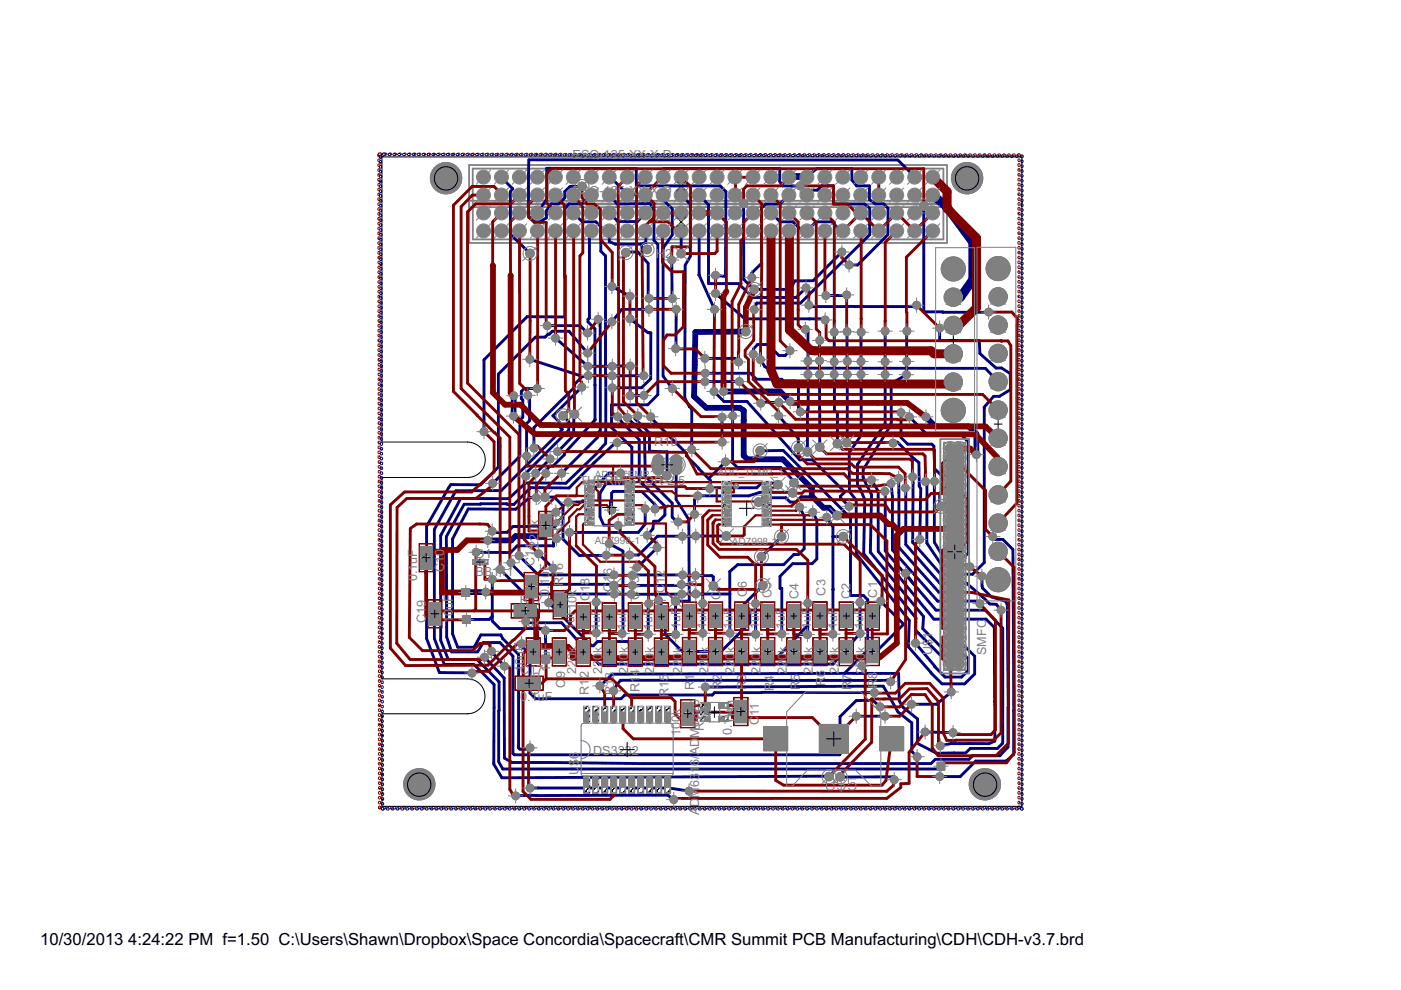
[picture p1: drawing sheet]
<svg xmlns="http://www.w3.org/2000/svg" width="297mm" height="210mm" viewBox="0 0 297 210" stroke-linecap="round" stroke-linejoin="round" font-family="sans-serif">
<defs><g id="words">
<g font-size="4">
<text x="8.5" y="200.4">10/30/2013</text>
<text x="27.2" y="200.4">4:24:22 PM f=1.50 C:\Users\Shawn\Dropbox\Space Concordia\Spacecraft\CMR Summit PCB Manufacturing\CDH\CDH-v3.7.brd</text>
</g>
<g font-size="3" fill="#808080">
<text x="121.4" y="33.7">ESQ-125-XX-X-D</text>
<text x="121.4" y="41.3">ESQ-125-X</text>
<text x="135.2" y="41.3">X-X-D</text>
<text x="139.1" y="47.1">H1</text>
<text x="139.1" y="54.7">H</text>
<text x="141" y="54.7">2</text>
<text x="138.7" y="94.6">R10</text>
<text x="122.9" y="102.7">TH</text>
<text x="126.5" y="102.7">ERMI</text>
<text x="133.2" y="102.7">STOR-2,</text>
<text x="143.8" y="102.7">5</text>
<text x="114.2" y="113.1" transform="rotate(-90 114.2 113.1)">0k</text>
<text x="119.2" y="113.7" transform="rotate(-90 119.2 113.7)">R9</text>
<text x="100.8" y="118.2">D1</text>
<text x="113.3" y="116.6" transform="rotate(-90 113.3 116.6)">4</text>
<text x="114.2" y="116.1" transform="rotate(-90 114.2 116.1)">22</text>
<text x="88.5" y="123.2" transform="rotate(-90 88.5 123.2)">0.1uF</text>
<text x="94.2" y="121.3" transform="rotate(-90 94.2 121.3)">C10</text>
<text x="100.8" y="122">BB</text>
<text x="104.4" y="122">141</text>
<text x="113.3" y="120.1" transform="rotate(-90 113.3 120.1)">C1</text>
<text x="116.5" y="121" transform="rotate(-90 116.5 121)">F</text>
<text x="119.4" y="124.2" transform="rotate(-90 119.4 124.2)">R16</text>
<text x="125" y="125.5" transform="rotate(-90 125 125.5)">18</text>
<text x="129.9" y="125.4" transform="rotate(-90 129.9 125.4)">C16</text>
<text x="135.5" y="125.2" transform="rotate(-90 135.5 125.2)">1</text>
<text x="135.5" y="123.7" transform="rotate(-90 135.5 123.7)">3</text>
<text x="141" y="125.8" transform="rotate(-90 141 125.8)">C</text>
<text x="141" y="123.9" transform="rotate(-90 141 123.9)">12</text>
<text x="152.8" y="125.2" transform="rotate(-90 152.8 125.2)">7</text>
<text x="158.3" y="124.6" transform="rotate(-90 158.3 124.6)">6</text>
<text x="96" y="130.5" transform="rotate(-90 96 130.5)">0</text>
<text x="96" y="129" transform="rotate(-90 96 129)">uF</text>
<text x="110.2" y="128">R17</text>
<text x="116.5" y="126.3" transform="rotate(-90 116.5 126.3)">0.1u</text>
<text x="122.2" y="127.9" transform="rotate(-90 122.2 127.9)">0k</text>
<text x="125" y="127.5" transform="rotate(-90 125 127.5)">C</text>
<text x="135.5" y="127.2" transform="rotate(-90 135.5 127.2)">C</text>
<text x="147.8" y="126.5" transform="rotate(-90 147.8 126.5)">C8</text>
<text x="152.8" y="127.1" transform="rotate(-90 152.8 127.1)">C</text>
<text x="158.3" y="126.5" transform="rotate(-90 158.3 126.5)">C</text>
<text x="163.6" y="126.8" transform="rotate(-90 163.6 126.8)">C5</text>
<text x="169.3" y="127.1" transform="rotate(-90 169.3 127.1)">C4</text>
<text x="175" y="126.3" transform="rotate(-90 175 126.3)">C3</text>
<text x="180.3" y="127" transform="rotate(-90 180.3 127)">C2</text>
<text x="186" y="126.7" transform="rotate(-90 186 126.7)">C1</text>
<text x="90.3" y="132" transform="rotate(-90 90.3 132)">C19</text>
<text x="96" y="132" transform="rotate(-90 96 132)">1</text>
<text x="110.2" y="132.9">1</text>
<text x="111.7" y="132.9">0k</text>
<text x="121.8" y="133.6" transform="rotate(-90 121.8 133.6)">1uF1</text>
<text x="127.3" y="133.6" transform="rotate(-90 127.3 133.6)">1uF</text>
<text x="132.8" y="133.6" transform="rotate(-90 132.8 133.6)">1uF</text>
<text x="138.3" y="133.5" transform="rotate(-90 138.3 133.5)">1uF</text>
<text x="144.3" y="133.4" transform="rotate(-90 144.3 133.4)">1uF</text>
<text x="149.8" y="133.4" transform="rotate(-90 149.8 133.4)">1uF</text>
<text x="155.3" y="133.4" transform="rotate(-90 155.3 133.4)">1uF</text>
<text x="160.9" y="133.4" transform="rotate(-90 160.9 133.4)">1uF</text>
<text x="166.4" y="133.4" transform="rotate(-90 166.4 133.4)">1uF</text>
<text x="171.9" y="133.4" transform="rotate(-90 171.9 133.4)">1uF</text>
<text x="177.5" y="133.4" transform="rotate(-90 177.5 133.4)">1uF</text>
<text x="183" y="133.4" transform="rotate(-90 183 133.4)">1uF</text>
<text x="110.3" y="143">C17</text>
<text x="111.2" y="142.5" transform="rotate(-90 111.2 142.5)">10uF</text>
<text x="116.7" y="142.5" transform="rotate(-90 116.7 142.5)">10</text>
<text x="116.7" y="139.5" transform="rotate(-90 116.7 139.5)">uF</text>
<text x="119.8" y="143.8" transform="rotate(-90 119.8 143.8)">9</text>
<text x="122.1" y="143" transform="rotate(-90 122.1 143)">220k</text>
<text x="124.8" y="143.9" transform="rotate(-90 124.8 143.9)">2</text>
<text x="127.7" y="143" transform="rotate(-90 127.7 143)">22</text>
<text x="127.7" y="140" transform="rotate(-90 127.7 140)">0k</text>
<text x="133.2" y="143" transform="rotate(-90 133.2 143)">22</text>
<text x="133.2" y="140" transform="rotate(-90 133.2 140)">0k</text>
<text x="138.7" y="143" transform="rotate(-90 138.7 143)">22</text>
<text x="138.7" y="140" transform="rotate(-90 138.7 140)">0k</text>
<text x="144.7" y="142.9" transform="rotate(-90 144.7 142.9)">220k</text>
<text x="150.2" y="142.9" transform="rotate(-90 150.2 142.9)">220k</text>
<text x="155.7" y="142.9" transform="rotate(-90 155.7 142.9)">220k</text>
<text x="161.2" y="142.9" transform="rotate(-90 161.2 142.9)">220k</text>
<text x="166.8" y="142.9" transform="rotate(-90 166.8 142.9)">220k</text>
<text x="172.3" y="142.9" transform="rotate(-90 172.3 142.9)">220k</text>
<text x="174.9" y="143.6" transform="rotate(-90 174.9 143.6)">6</text>
<text x="177.9" y="142.9" transform="rotate(-90 177.9 142.9)">220k</text>
<text x="183.4" y="142.9" transform="rotate(-90 183.4 142.9)">220k</text>
<text x="197.6" y="138.9" transform="rotate(-90 197.6 138.9)">U$1</text>
<text x="209.1" y="138.9" transform="rotate(-90 209.1 138.9)">SMFC</text>
<text x="110.3" y="148.7">0</text>
<text x="111.8" y="148.7">.1uF</text>
<text x="114.4" y="147.4" transform="rotate(-90 114.4 147.4)">C</text>
<text x="114.4" y="145.5" transform="rotate(-90 114.4 145.5)">15</text>
<text x="119.8" y="145.8" transform="rotate(-90 119.8 145.8)">C</text>
<text x="124.8" y="147.3" transform="rotate(-90 124.8 147.3)">R1</text>
<text x="130.2" y="147.4" transform="rotate(-90 130.2 147.4)">R13</text>
<text x="135.6" y="146.7" transform="rotate(-90 135.6 146.7)">R14</text>
<text x="141.7" y="147.8" transform="rotate(-90 141.7 147.8)">R15</text>
<text x="147.2" y="146.2" transform="rotate(-90 147.2 146.2)">R1</text>
<text x="153" y="146.3" transform="rotate(-90 153 146.3)">R2</text>
<text x="156.2" y="149.6" transform="rotate(-90 156.2 149.6)">4</text>
<text x="158.2" y="146.4" transform="rotate(-90 158.2 146.4)">R3</text>
<text x="164.1" y="146.6" transform="rotate(-90 164.1 146.6)">R4</text>
<text x="169.6" y="146.3" transform="rotate(-90 169.6 146.3)">R5</text>
<text x="174.9" y="145.5" transform="rotate(-90 174.9 145.5)">R</text>
<text x="180.5" y="146.2" transform="rotate(-90 180.5 146.2)">R7</text>
<text x="186" y="145.9" transform="rotate(-90 186 145.9)">R</text>
<text x="186" y="144" transform="rotate(-90 186 144)">8</text>
<text x="149.2" y="154.9" transform="rotate(-90 149.2 154.9)">R1</text>
<text x="149.2" y="151.7" transform="rotate(-90 149.2 151.7)">1</text>
<text x="155.2" y="155.9" transform="rotate(-90 155.2 155.9)">0.1u</text>
<text x="155.2" y="150.6" transform="rotate(-90 155.2 150.6)">F</text>
<text x="156.2" y="153.1" transform="rotate(-90 156.2 153.1)">U</text>
<text x="156.2" y="151.1" transform="rotate(-90 156.2 151.1)">$</text>
<text x="160.9" y="153.7" transform="rotate(-90 160.9 153.7)">C</text>
<text x="160.9" y="151.8" transform="rotate(-90 160.9 151.8)">11</text>
<text x="125.7" y="160.1">DS3232</text>
<text x="144.3" y="156" transform="rotate(-90 144.3 156)">100k</text>
<text x="148.2" y="156.4" transform="rotate(-90 148.2 156.4)">M6320</text>
<text x="122.7" y="164.3" transform="rotate(-90 122.7 164.3)">U</text>
<text x="122.7" y="162.3" transform="rotate(-90 122.7 162.3)">$6</text>
<text x="148.2" y="166.9" transform="rotate(-90 148.2 166.9)">631</text>
<text x="148.2" y="162.4" transform="rotate(-90 148.2 162.4)">6/AD</text>
<text x="148.2" y="172.9" transform="rotate(-90 148.2 172.9)">AD</text>
<text x="148.2" y="169.1" transform="rotate(-90 148.2 169.1)">M</text>
</g>
<g font-size="2.4" fill="#808080">
<text x="126.1" y="101.3">ADC_</text>
<text x="131.8" y="101.3">TE</text>
<text x="134.5" y="101.3">MP_2</text>
<text x="152.2" y="100.9">ADC_TEMP_1</text>
<text x="126.1" y="115.4">AD7998-1</text>
<text x="155.2" y="115.6">AD7998-1</text>
</g>
</g></defs>
<path d="M100.2 35.8h99.8v7.4h-99.8zM100.2 43.3h99.8v7.5h-99.8zM200.8 42.6h-101.3v8.9h101.3v-16.5h-101.3v8.9h101.3" fill="none" stroke="#808080" stroke-width=".38"/>
<g fill="#808080" stroke="#808080" stroke-width=".21">
<circle cx="88.9" cy="166.4" r="2.62"/>
<circle cx="94.6" cy="37.8" r="2.62"/>
<circle cx="208.9" cy="166.4" r="2.62"/>
<circle cx="205" cy="37.8" r="2.62"/>
<circle cx="203.4" cy="140.8" r="1.06"/>
<circle cx="201.5" cy="140.8" r="1.06"/>
<circle cx="203.4" cy="138.9" r="1.06"/>
<circle cx="201.5" cy="138.9" r="1.06"/>
<circle cx="203.4" cy="137" r="1.06"/>
<circle cx="201.5" cy="137" r="1.06"/>
<circle cx="203.4" cy="135.1" r="1.06"/>
<circle cx="201.5" cy="135.1" r="1.06"/>
<circle cx="203.4" cy="133.2" r="1.06"/>
<circle cx="201.5" cy="133.2" r="1.06"/>
<circle cx="203.4" cy="131.3" r="1.06"/>
<circle cx="201.5" cy="131.3" r="1.06"/>
<circle cx="203.4" cy="129.4" r="1.06"/>
<circle cx="201.5" cy="129.4" r="1.06"/>
<circle cx="203.4" cy="127.5" r="1.06"/>
<circle cx="201.5" cy="127.5" r="1.06"/>
<circle cx="203.4" cy="125.6" r="1.06"/>
<circle cx="201.5" cy="125.6" r="1.06"/>
<circle cx="203.4" cy="123.7" r="1.06"/>
<circle cx="201.5" cy="123.7" r="1.06"/>
<circle cx="203.4" cy="121.8" r="1.06"/>
<circle cx="201.5" cy="121.8" r="1.06"/>
<circle cx="203.4" cy="119.8" r="1.06"/>
<circle cx="201.5" cy="119.8" r="1.06"/>
<circle cx="203.4" cy="117.9" r="1.06"/>
<circle cx="201.5" cy="117.9" r="1.06"/>
<circle cx="203.4" cy="116" r="1.06"/>
<circle cx="201.5" cy="116" r="1.06"/>
<circle cx="203.4" cy="114.1" r="1.06"/>
<circle cx="201.5" cy="114.1" r="1.06"/>
<circle cx="203.4" cy="112.2" r="1.06"/>
<circle cx="201.5" cy="112.2" r="1.06"/>
<circle cx="203.4" cy="110.3" r="1.06"/>
<circle cx="201.5" cy="110.3" r="1.06"/>
<circle cx="203.4" cy="108.4" r="1.06"/>
<circle cx="201.5" cy="108.4" r="1.06"/>
<circle cx="203.4" cy="106.5" r="1.06"/>
<circle cx="201.5" cy="106.5" r="1.06"/>
<circle cx="203.4" cy="104.6" r="1.06"/>
<circle cx="201.5" cy="104.6" r="1.06"/>
<circle cx="203.4" cy="102.7" r="1.06"/>
<circle cx="201.5" cy="102.7" r="1.06"/>
<circle cx="203.4" cy="100.8" r="1.06"/>
<circle cx="201.5" cy="100.8" r="1.06"/>
<circle cx="203.4" cy="98.9" r="1.06"/>
<circle cx="201.5" cy="98.9" r="1.06"/>
<circle cx="203.4" cy="97" r="1.06"/>
<circle cx="201.5" cy="97" r="1.06"/>
<circle cx="203.4" cy="95.1" r="1.06"/>
<circle cx="201.5" cy="95.1" r="1.06"/>
<circle cx="102.5" cy="41.4" r="1.29"/>
<circle cx="102.5" cy="37.5" r="1.29"/>
<circle cx="106.3" cy="41.4" r="1.29"/>
<circle cx="106.3" cy="37.5" r="1.29"/>
<circle cx="110.1" cy="41.4" r="1.29"/>
<circle cx="110.1" cy="37.5" r="1.29"/>
<circle cx="113.9" cy="41.4" r="1.29"/>
<circle cx="113.9" cy="37.5" r="1.29"/>
<circle cx="117.8" cy="41.4" r="1.29"/>
<circle cx="117.8" cy="37.5" r="1.29"/>
<circle cx="121.6" cy="41.4" r="1.29"/>
<circle cx="121.6" cy="37.5" r="1.29"/>
<circle cx="125.4" cy="41.4" r="1.29"/>
<circle cx="125.4" cy="37.5" r="1.29"/>
<circle cx="129.2" cy="41.4" r="1.29"/>
<circle cx="129.2" cy="37.5" r="1.29"/>
<circle cx="133" cy="41.4" r="1.29"/>
<circle cx="133" cy="37.5" r="1.29"/>
<circle cx="136.8" cy="41.4" r="1.29"/>
<circle cx="136.8" cy="37.5" r="1.29"/>
<circle cx="140.6" cy="41.4" r="1.29"/>
<circle cx="140.6" cy="37.5" r="1.29"/>
<circle cx="144.4" cy="41.4" r="1.29"/>
<circle cx="144.4" cy="37.5" r="1.29"/>
<circle cx="148.2" cy="41.4" r="1.29"/>
<circle cx="148.2" cy="37.5" r="1.29"/>
<circle cx="152" cy="41.4" r="1.29"/>
<circle cx="152" cy="37.5" r="1.29"/>
<circle cx="155.8" cy="41.4" r="1.29"/>
<circle cx="155.8" cy="37.5" r="1.29"/>
<circle cx="159.6" cy="41.4" r="1.29"/>
<circle cx="159.6" cy="37.5" r="1.29"/>
<circle cx="163.4" cy="41.4" r="1.29"/>
<circle cx="163.4" cy="37.5" r="1.29"/>
<circle cx="167.3" cy="41.4" r="1.29"/>
<circle cx="167.3" cy="37.5" r="1.29"/>
<circle cx="171.1" cy="41.4" r="1.29"/>
<circle cx="171.1" cy="37.5" r="1.29"/>
<circle cx="174.9" cy="41.4" r="1.29"/>
<circle cx="174.9" cy="37.5" r="1.29"/>
<circle cx="178.7" cy="41.4" r="1.29"/>
<circle cx="178.7" cy="37.5" r="1.29"/>
<circle cx="182.5" cy="41.4" r="1.29"/>
<circle cx="182.5" cy="37.5" r="1.29"/>
<circle cx="186.3" cy="41.4" r="1.29"/>
<circle cx="186.3" cy="37.5" r="1.29"/>
<circle cx="190.1" cy="41.4" r="1.29"/>
<circle cx="190.1" cy="37.5" r="1.29"/>
<circle cx="193.9" cy="41.4" r="1.29"/>
<circle cx="193.9" cy="37.5" r="1.29"/>
<circle cx="197.7" cy="41.4" r="1.29"/>
<circle cx="197.7" cy="37.5" r="1.29"/>
<circle cx="102.5" cy="49" r="1.29"/>
<circle cx="102.5" cy="45.1" r="1.29"/>
<circle cx="106.3" cy="49" r="1.29"/>
<circle cx="106.3" cy="45.1" r="1.29"/>
<circle cx="110.1" cy="49" r="1.29"/>
<circle cx="110.1" cy="45.1" r="1.29"/>
<circle cx="113.9" cy="49" r="1.29"/>
<circle cx="113.9" cy="45.1" r="1.29"/>
<circle cx="117.8" cy="49" r="1.29"/>
<circle cx="117.8" cy="45.1" r="1.29"/>
<circle cx="121.6" cy="49" r="1.29"/>
<circle cx="121.6" cy="45.1" r="1.29"/>
<circle cx="125.4" cy="49" r="1.29"/>
<circle cx="125.4" cy="45.1" r="1.29"/>
<circle cx="129.2" cy="49" r="1.29"/>
<circle cx="129.2" cy="45.1" r="1.29"/>
<circle cx="133" cy="49" r="1.29"/>
<circle cx="133" cy="45.1" r="1.29"/>
<circle cx="136.8" cy="49" r="1.29"/>
<circle cx="136.8" cy="45.1" r="1.29"/>
<circle cx="140.6" cy="49" r="1.29"/>
<circle cx="140.6" cy="45.1" r="1.29"/>
<circle cx="144.4" cy="49" r="1.29"/>
<circle cx="144.4" cy="45.1" r="1.29"/>
<circle cx="148.2" cy="49" r="1.29"/>
<circle cx="148.2" cy="45.1" r="1.29"/>
<circle cx="152" cy="49" r="1.29"/>
<circle cx="152" cy="45.1" r="1.29"/>
<circle cx="155.9" cy="49" r="1.29"/>
<circle cx="155.9" cy="45.1" r="1.29"/>
<circle cx="159.7" cy="49" r="1.29"/>
<circle cx="159.7" cy="45.1" r="1.29"/>
<circle cx="163.5" cy="49" r="1.29"/>
<circle cx="163.5" cy="45.1" r="1.29"/>
<circle cx="167.3" cy="49" r="1.29"/>
<circle cx="167.3" cy="45.1" r="1.29"/>
<circle cx="171.1" cy="49" r="1.29"/>
<circle cx="171.1" cy="45.1" r="1.29"/>
<circle cx="174.9" cy="49" r="1.29"/>
<circle cx="174.9" cy="45.1" r="1.29"/>
<circle cx="178.7" cy="49" r="1.29"/>
<circle cx="178.7" cy="45.1" r="1.29"/>
<circle cx="182.5" cy="49" r="1.29"/>
<circle cx="182.5" cy="45.1" r="1.29"/>
<circle cx="186.3" cy="49" r="1.29"/>
<circle cx="186.3" cy="45.1" r="1.29"/>
<circle cx="190.1" cy="49" r="1.29"/>
<circle cx="190.1" cy="45.1" r="1.29"/>
<circle cx="193.9" cy="49" r="1.29"/>
<circle cx="193.9" cy="45.1" r="1.29"/>
<circle cx="197.7" cy="49" r="1.29"/>
<circle cx="197.7" cy="45.1" r="1.29"/>
<circle cx="202.1" cy="81" r="1.95"/>
<circle cx="202.1" cy="75" r="1.95"/>
<circle cx="202.1" cy="69" r="1.95"/>
<circle cx="202.1" cy="63" r="1.95"/>
<circle cx="202.1" cy="87" r="2.56"/>
<circle cx="202.1" cy="57" r="2.56"/>
<circle cx="211.6" cy="62.9" r="1.95"/>
<circle cx="211.6" cy="68.9" r="1.95"/>
<circle cx="211.6" cy="74.9" r="1.95"/>
<circle cx="211.6" cy="80.9" r="1.95"/>
<circle cx="211.6" cy="86.9" r="1.95"/>
<circle cx="211.6" cy="92.9" r="1.95"/>
<circle cx="211.6" cy="98.9" r="1.95"/>
<circle cx="211.6" cy="104.9" r="1.95"/>
<circle cx="211.6" cy="110.9" r="1.95"/>
<circle cx="211.6" cy="116.9" r="1.95"/>
<circle cx="211.6" cy="56.9" r="2.56"/>
<circle cx="211.6" cy="122.9" r="2.56"/>
<circle cx="115.6" cy="133.7" r=".83"/>
<circle cx="104.4" cy="122.8" r=".83"/>
<circle cx="187.6" cy="151.8" r=".83"/>
<circle cx="181.5" cy="151.8" r=".83"/>
<circle cx="169.7" cy="39.4" r=".83"/>
<circle cx="137.2" cy="52.9" r=".91"/>
<circle cx="112.4" cy="53.7" r=".91"/>
<circle cx="112.3" cy="76.2" r=".83"/>
<circle cx="124.7" cy="79.6" r=".83"/>
<circle cx="129.8" cy="79.7" r=".83"/>
<circle cx="136.5" cy="79.7" r=".83"/>
<circle cx="113.6" cy="100.4" r=".83"/>
<circle cx="116.6" cy="97.3" r=".83"/>
<circle cx="113.2" cy="95" r=".83"/>
<circle cx="144.4" cy="53.8" r=".91"/>
<circle cx="193.3" cy="149.3" r=".83"/>
<circle cx="201.7" cy="146.7" r=".83"/>
<circle cx="171.2" cy="134.6" r=".83"/>
<circle cx="171.3" cy="127.9" r=".83"/>
<circle cx="119.4" cy="88.2" r=".91"/>
<circle cx="111.5" cy="101" r=".83"/>
<circle cx="114.2" cy="117.4" r=".83"/>
<circle cx="117.2" cy="120.5" r=".83"/>
<circle cx="116.3" cy="127.8" r=".83"/>
<circle cx="176.6" cy="134.5" r=".83"/>
<circle cx="175.3" cy="109.7" r=".83"/>
<circle cx="178.8" cy="113.8" r=".91"/>
<circle cx="186.7" cy="127.5" r=".83"/>
<circle cx="182.8" cy="141.2" r=".83"/>
<circle cx="175.7" cy="164.7" r=".91"/>
<circle cx="123.3" cy="82.1" r=".83"/>
<circle cx="131.1" cy="111.4" r=".83"/>
<circle cx="139.6" cy="127.3" r=".83"/>
<circle cx="161.7" cy="124.1" r=".91"/>
<circle cx="161.4" cy="118" r=".91"/>
<circle cx="165.7" cy="113.8" r=".91"/>
<circle cx="131.9" cy="134.3" r=".83"/>
<circle cx="129.2" cy="115.3" r=".83"/>
<circle cx="126.4" cy="134.2" r=".83"/>
<circle cx="126.4" cy="127.7" r=".83"/>
<circle cx="137.4" cy="134.5" r=".83"/>
<circle cx="137.5" cy="128" r=".83"/>
<circle cx="135" cy="120.3" r=".83"/>
<circle cx="139.3" cy="116.1" r=".83"/>
<circle cx="137.2" cy="113.5" r=".83"/>
<circle cx="131" cy="88.3" r=".83"/>
<circle cx="129.8" cy="82.2" r=".83"/>
<circle cx="123.4" cy="39.5" r=".91"/>
<circle cx="129.7" cy="60.7" r=".83"/>
<circle cx="133.6" cy="62.8" r=".83"/>
<circle cx="133.6" cy="67.6" r=".83"/>
<circle cx="190.5" cy="101.4" r=".83"/>
<circle cx="146.7" cy="95.3" r=".83"/>
<circle cx="170.9" cy="61" r=".83"/>
<circle cx="171.5" cy="64.7" r=".83"/>
<circle cx="194.3" cy="64.7" r=".83"/>
<circle cx="199.2" cy="69.6" r=".83"/>
<circle cx="192.8" cy="88.4" r=".83"/>
<circle cx="165.1" cy="85.3" r=".83"/>
<circle cx="161.3" cy="85.5" r=".83"/>
<circle cx="156.8" cy="80.9" r=".83"/>
<circle cx="149.5" cy="80.9" r=".83"/>
<circle cx="136.5" cy="83.8" r=".83"/>
<circle cx="133.6" cy="83.9" r=".83"/>
<circle cx="133.6" cy="77.6" r=".83"/>
<circle cx="129.8" cy="77.7" r=".83"/>
<circle cx="124.6" cy="77.7" r=".83"/>
<circle cx="117.8" cy="71.7" r=".83"/>
<circle cx="154.7" cy="134.3" r=".83"/>
<circle cx="169.5" cy="107.5" r=".83"/>
<circle cx="106" cy="120.7" r=".83"/>
<circle cx="130.3" cy="125.9" r=".83"/>
<circle cx="133.8" cy="126" r=".83"/>
<circle cx="144.6" cy="126" r=".83"/>
<circle cx="147.5" cy="125.9" r=".83"/>
<circle cx="165.8" cy="134.4" r=".83"/>
<circle cx="172.3" cy="108.6" r=".83"/>
<circle cx="154" cy="113.6" r=".91"/>
<circle cx="147.5" cy="113.6" r=".83"/>
<circle cx="144.7" cy="113.7" r=".83"/>
<circle cx="133.5" cy="117.7" r=".83"/>
<circle cx="128.5" cy="117.7" r=".83"/>
<circle cx="115.5" cy="105.4" r=".91"/>
<circle cx="119.1" cy="100.4" r=".83"/>
<circle cx="126.8" cy="67.7" r=".83"/>
<circle cx="124.6" cy="70.6" r=".83"/>
<circle cx="116" cy="69" r=".83"/>
<circle cx="160.2" cy="134.5" r=".83"/>
<circle cx="160.2" cy="128" r=".83"/>
<circle cx="110.1" cy="117.8" r=".83"/>
<circle cx="130.2" cy="121.9" r=".83"/>
<circle cx="134" cy="122" r=".83"/>
<circle cx="144.7" cy="121.9" r=".83"/>
<circle cx="147.5" cy="122" r=".83"/>
<circle cx="151.2" cy="124.2" r=".91"/>
<circle cx="149" cy="134.3" r=".83"/>
<circle cx="149" cy="128" r=".83"/>
<circle cx="108.3" cy="119.3" r=".83"/>
<circle cx="130.2" cy="124.2" r=".91"/>
<circle cx="134.1" cy="124.1" r=".83"/>
<circle cx="144.5" cy="124" r=".83"/>
<circle cx="192" cy="103.5" r=".83"/>
<circle cx="159.9" cy="65.6" r=".83"/>
<circle cx="165.1" cy="88.2" r=".83"/>
<circle cx="169.3" cy="94.9" r=".91"/>
<circle cx="136.8" cy="107.9" r=".83"/>
<circle cx="120.8" cy="112.9" r=".83"/>
<circle cx="182.4" cy="134.3" r=".83"/>
<circle cx="182.3" cy="127.7" r=".83"/>
<circle cx="102.6" cy="91.5" r=".83"/>
<circle cx="111.5" cy="131.7" r=".83"/>
<circle cx="143.3" cy="134.5" r=".83"/>
<circle cx="143.2" cy="127.4" r=".91"/>
<circle cx="118" cy="114.2" r=".83"/>
<circle cx="138.9" cy="107.9" r=".83"/>
<circle cx="129.7" cy="108.2" r=".83"/>
<circle cx="100.9" cy="117.1" r=".83"/>
<circle cx="118" cy="110.8" r=".61"/>
<circle cx="103.4" cy="114.6" r=".83"/>
<circle cx="103" cy="125.5" r=".83"/>
<circle cx="180" cy="56.2" r=".83"/>
<circle cx="178.5" cy="53.4" r=".83"/>
<circle cx="159.9" cy="61.4" r=".91"/>
<circle cx="158.1" cy="70.3" r=".91"/>
<circle cx="160.8" cy="106.4" r=".91"/>
<circle cx="157.6" cy="43.1" r=".91"/>
<circle cx="177.5" cy="109.3" r=".91"/>
<circle cx="153.4" cy="83" r=".83"/>
<circle cx="167.5" cy="85.1" r=".83"/>
<circle cx="196.3" cy="88.4" r=".83"/>
<circle cx="207" cy="96.4" r=".83"/>
<circle cx="186.6" cy="149.9" r=".83"/>
<circle cx="130.9" cy="93.9" r=".83"/>
<circle cx="153.1" cy="93.7" r=".83"/>
<circle cx="153.1" cy="88.5" r=".83"/>
<circle cx="142.5" cy="82.4" r=".83"/>
<circle cx="159.4" cy="58.9" r=".83"/>
<circle cx="212.2" cy="129.4" r=".83"/>
<circle cx="185.4" cy="146.9" r=".83"/>
<circle cx="156.6" cy="76.8" r=".83"/>
<circle cx="100.1" cy="142.7" r=".83"/>
<circle cx="110.6" cy="136.5" r=".83"/>
<circle cx="149.4" cy="76" r=".83"/>
<circle cx="143.3" cy="73.9" r=".83"/>
<circle cx="143.4" cy="65.6" r=".83"/>
<circle cx="137.6" cy="65.6" r=".83"/>
<circle cx="129.7" cy="68.2" r=".83"/>
<circle cx="124.6" cy="74.9" r=".83"/>
<circle cx="182.6" cy="70.4" r=".83"/>
<circle cx="182.5" cy="76.6" r=".83"/>
<circle cx="182.5" cy="79.4" r=".83"/>
<circle cx="194.1" cy="136.4" r=".83"/>
<circle cx="195" cy="114.4" r=".83"/>
<circle cx="175.1" cy="62.7" r=".83"/>
<circle cx="179.5" cy="62.5" r=".83"/>
<circle cx="179.6" cy="70.3" r=".83"/>
<circle cx="179.6" cy="76.6" r=".83"/>
<circle cx="179.6" cy="79.4" r=".83"/>
<circle cx="179.5" cy="93.8" r=".91"/>
<circle cx="189.3" cy="93.9" r=".83"/>
<circle cx="187.7" cy="70.2" r=".83"/>
<circle cx="187.7" cy="76.7" r=".83"/>
<circle cx="187.7" cy="79.4" r=".83"/>
<circle cx="192.3" cy="70.2" r=".83"/>
<circle cx="192.2" cy="76.6" r=".83"/>
<circle cx="192.2" cy="79.4" r=".83"/>
<circle cx="167.5" cy="74.4" r=".83"/>
<circle cx="159.7" cy="75.1" r=".83"/>
<circle cx="130.1" cy="146.5" r=".83"/>
<circle cx="147.9" cy="105.1" r=".83"/>
<circle cx="168.1" cy="104.5" r=".91"/>
<circle cx="187.6" cy="104.2" r=".83"/>
<circle cx="133" cy="88.5" r=".83"/>
<circle cx="143.8" cy="110.7" r=".83"/>
<circle cx="147.3" cy="109" r=".83"/>
<circle cx="188.8" cy="144.5" r=".83"/>
<circle cx="192" cy="121.6" r=".83"/>
<circle cx="127.2" cy="145.4" r=".83"/>
<circle cx="150.5" cy="103.6" r=".83"/>
<circle cx="164.9" cy="102.8" r=".91"/>
<circle cx="138" cy="88.4" r=".83"/>
<circle cx="153.8" cy="97.9" r=".83"/>
<circle cx="161.2" cy="95.6" r=".91"/>
<circle cx="188.9" cy="102.5" r=".83"/>
<circle cx="168.3" cy="102.4" r=".91"/>
<circle cx="155.3" cy="88.2" r=".83"/>
<circle cx="207.8" cy="128" r=".83"/>
<circle cx="202.1" cy="155.3" r=".83"/>
<circle cx="196.1" cy="155.2" r=".83"/>
<circle cx="142.9" cy="169.5" r=".83"/>
<circle cx="109.3" cy="168.7" r=".83"/>
<circle cx="104.4" cy="112.6" r=".83"/>
<circle cx="117.9" cy="108.6" r=".83"/>
<circle cx="120.4" cy="106.5" r=".83"/>
<circle cx="131.6" cy="100.3" r=".83"/>
<circle cx="141.4" cy="100.8" r=".91"/>
<circle cx="135.2" cy="88.2" r=".83"/>
<circle cx="132.7" cy="53.6" r=".91"/>
<circle cx="137.6" cy="63.2" r=".83"/>
<circle cx="142.6" cy="63.3" r=".83"/>
<circle cx="142.4" cy="55.1" r=".83"/>
<circle cx="107" cy="141.2" r=".83"/>
<circle cx="104.2" cy="138.1" r=".83"/>
<circle cx="184.8" cy="101.7" r=".83"/>
<circle cx="118.2" cy="95.8" r=".83"/>
<circle cx="121.8" cy="87.8" r=".91"/>
<circle cx="170.8" cy="69.8" r=".83"/>
<circle cx="171.3" cy="76.5" r=".83"/>
<circle cx="171.3" cy="79.4" r=".83"/>
<circle cx="193.5" cy="101.1" r=".83"/>
<circle cx="171.2" cy="95.8" r=".91"/>
<circle cx="173.8" cy="72.2" r=".83"/>
<circle cx="173.8" cy="76.5" r=".83"/>
<circle cx="173.8" cy="79.4" r=".83"/>
<circle cx="196.2" cy="102.1" r=".83"/>
<circle cx="173.8" cy="94.8" r=".91"/>
<circle cx="176.9" cy="70.4" r=".83"/>
<circle cx="176.9" cy="76.7" r=".83"/>
<circle cx="176.9" cy="79.4" r=".83"/>
<circle cx="198.1" cy="102.1" r=".83"/>
<circle cx="177.5" cy="94.1" r=".91"/>
<circle cx="205.6" cy="120.2" r=".83"/>
<circle cx="208.2" cy="122.2" r=".83"/>
<circle cx="104.5" cy="102.5" r=".83"/>
<circle cx="113.9" cy="82.4" r=".83"/>
<circle cx="102.7" cy="139.3" r=".83"/>
<circle cx="149.5" cy="145.7" r=".83"/>
<circle cx="210.5" cy="113.8" r=".83"/>
<circle cx="199.2" cy="164.7" r=".83"/>
<circle cx="194.4" cy="160.4" r=".83"/>
<circle cx="191" cy="87.5" r=".83"/>
<circle cx="169.7" cy="87.3" r=".83"/>
<circle cx="149.5" cy="79.1" r=".83"/>
<circle cx="199.5" cy="107.4" r=".91"/>
<circle cx="180" cy="107.4" r=".83"/>
<circle cx="151.5" cy="65.6" r=".83"/>
<circle cx="151.4" cy="83" r=".83"/>
<circle cx="108.9" cy="88.2" r=".83"/>
<circle cx="108.9" cy="83.9" r=".83"/>
<circle cx="174.9" cy="67.8" r=".83"/>
<circle cx="151.7" cy="58.4" r=".83"/>
<circle cx="151.7" cy="62.2" r=".83"/>
<circle cx="209.6" cy="66.2" r=".83"/>
<circle cx="195.9" cy="43.7" r=".91"/>
<circle cx="161.2" cy="76.3" r=".83"/>
<circle cx="199.4" cy="158.1" r=".83"/>
<circle cx="178.1" cy="164.7" r=".91"/>
<circle cx="189.6" cy="165.3" r=".83"/>
<circle cx="146.1" cy="167.7" r=".83"/>
<circle cx="112.4" cy="167.1" r=".83"/>
<circle cx="112.4" cy="158.6" r=".83"/>
<circle cx="113.7" cy="105.5" r=".83"/>
<circle cx="115.7" cy="100.4" r=".83"/>
<circle cx="111.7" cy="96.7" r=".83"/>
<circle cx="111.9" cy="83.8" r=".83"/>
<circle cx="94.6" cy="37.8" r="3.3"/>
<circle cx="205" cy="37.8" r="3.3"/>
<circle cx="208.8" cy="166.3" r="3.3"/>
<circle cx="88.9" cy="166.3" r="3.3"/>
</g>
<g fill="#808080" stroke="#808080" stroke-width=".21">
<path d="M142.7 96.6a1.15 1.15 0 0 1 1.8 .8v2.3a1.15 1.15 0 0 1-1.1 1 1.15 1.15 0 0 1-1.2-1v-2.3z"/>
<path d="M138.9 96.6a1.15 1.15 0 0 1 1.8 .8v2.3a1.15 1.15 0 0 1-1.1 1 1.15 1.15 0 0 1-1.2-1v-2.3z"/>
<path d="M114.9 138.9h1.6v1.6h-1.6z"/>
<path d="M98 130.5h1.7v1.7h-1.7z"/>
<path d="M97.9 124.8h1.7v1.6h-1.7z"/>
<path d="M198.7 161.6h1.6v1.7h-1.6z"/>
</g>
<path d="M167 36.8h4.5v1.2h-4.5z" fill="#000080" stroke="#000080" stroke-width=".21"/>
<g fill="none" stroke="#000080" stroke-width=".61">
<path d="M106.3 37.5l2.4 2.5-.5 .6v9.1l4.2 4M129.2 37.5l.2 .1 3.4 3.3h.3l-.1 .5h3.8M140.6 37.5l.1 .1v-1.9h24.6v2.7l.6 1h3.8M148.2 35.7v1.8M170.9 37.6l2.3-1.8h7.4v2.4l1 1.2h2.7v2.9l1.3 .9h1.8l.9 1-.1 5.6-6.4 6.4h-1.8M193.9 37.5l-3.5-3.6h-78.3v11.9l1.2 1.2h1.2l1.3-.8v-1.5l1-1.5h1.7l1.2-1.2v-1.4l1.2-1.1h2.5M113.9 45.1l2-3v-6.4h19v3.7h17.8l1.2 1.2-.1 18-2.1-.2M121.6 45.1l1.9 1.9h2.8l1.1 1.1v5.2l1 1v39.7l-2 2.2-6.4 6.3-8.6-.1-3.6 3.3h-10.1l-4.3 7.9v22.1l1.6 4.1h6.1l4.7 4.7-.1 17 .9 1.5h92.3l.6-.6M125.4 41.4l-2 1.8h-2.8l-.9 1.1v22.9l-7.9-.1-9.2 9.2v15.2M125.4 49l-.2-.1-.2 .2v18.3l-.3 .3v.6l1.4 1.4 .1 19.3-6.5 7.1v.3l-2.5 2.4h-.6l-1.2 1.3 .3 .3M129.2 49v2.2l1.3 .6h5.4M129.2 41.4l1.7 1.8h6.9l.9 1.2v6.6l.8 .8v31.9l-2.2 2.1h-7.7v4.9l4.4 4.1v7l-.8 .8h-4.7l-1.3 2v4.9l.8 1.8 3.1 .1"/>
<path d="M129.2 45.1l1.8 1.9h4.1l1.7-1.9M132.7 53.6l.6-.2h1.9l2.2 2.4v7.6l.2-.2M135.9 51.8l.2 .7 1.1 .4M136.8 49l.1 .1v2.3l-1 .4M140.6 41.4l-.5 .4 2.4 2.5v5.5l-1.9 2.8v27.1l1.9 2.7M142.4 55.1l.2 8.2M142.4 55.1h.1M144.4 49v4.8M144.4 41.4l2 1.9v11l-1.1 1.9-.1 28.2 1 1.9 .5 .4v8.6M148.2 49v9.3l3.3 7.3M148.2 41.4l2 2v16.7h6.3l3.2 3h9.1l2.1-2.1M148.2 58.2v.1"/>
<path d="M157.6 43.1l.1 16.1 2.1 2.2h7.7l1-1.8 3.9-.1 6.1-6.1M163.5 45.1l1.9 1.9h2.7l1.9 1.9 1.1 .1 1.9-2h3.4l1.8 1.9 .5 .1M167.3 41.4l-1.9 1.9h-3.1l-.8 .8v11.7l-2.1 2.1v1h.2M171.1 41.4l1-1.1h1.2l.9-.9h2.5v3.8l6.7 .1 1 .9v5.6l-14.7 14.5h-9.3l-.5 1.3M195.9 43.7v22.4l13.7 .1M112.3 76.2l11.2 3.6M116 69h7l1.6 1.6M117.8 71.7l6.8 6M123.5 79.8l-1.7 1.7v.6l-8.6 8.6v4.3M124.6 74.9l-4-4.7h-3.5l-1.5 1.3h-2.1l-7.8 7.8v19.7l-3.8 3.8-6.3-.1-5.2 8.9v23.8l2.8 7.2 6.9 .1M124.7 79.6l-1.2 .2M126.8 67.7l.5 .5v23.1l-.6 .5v.9l-7.6 7.7"/>
<path d="M127.3 71h.1M129.7 60.7l3.9 2.1M133.6 67.6l3.8 2.9 .6 .1M133.6 77.6l-3.8 .1M136.5 79.7h-6.7M137.5 70.5l.5 .1M137.6 65.6h-5.8l-2.1 2.6M138 70.6v9.7l-2 1.9h-6.2M143.4 65.6l-.1 8.3M149.4 76h6.5l.7 .8M149.5 79.1h9.6l1.3 1.3h5.4l.3 .4h2.5l.7 .7v5.4l.4 .4M151.7 62.2l6.1 5.3 .5 .1h16.4l.2 .2"/>
<path d="M161.2 76.3l1 1.4 .4 .3 46.3 .1 2.7 2.8M167.5 74.4l-1 1h-1.4l-2.3-2.4h-2.2l-.9 1v1.1M170.8 69.8l.5 .6v6.1M171.3 79.4l-.1 16.4M171.5 64.7l.3 .3h22.2l.3-.3M171.6 67.6h.1M173.8 79.3v15.5M173.8 72.2v4.3M176.9 70.4v6.3M176.9 79.4v7.6l.6 .6v6.5M179.5 62.5l-.1 .2h-4.3M179.6 70.3v6.6v-.3"/>
<path d="M179.6 79.4l-.1 14.4M182.5 79.4l.1 12.9-2.6 3.7 .1 8.2 1.4 1.8v11.4l11.3 14.2-.2 5.5 4.8 5.6 2.3 2.3h4.8l2.2-2.1v-3.8l-2.2-2.1h-1.1M182.6 70.4l-.1 6.2M187.7 79.4v10.4l-5.9 8.7v4.3l.7 1.1 .8 2-.2 11.5 11.1 13.6v2.7l5.1 5.2h2.2M187.7 70.2v6.5M192.2 79.1v.3l-3.3 1.9 .1 8.2-.3 .9-5.7 9.2v1.6l1.8 3.7-.3 12.2 11.3 13.6-.2 2.6 3.7 3.7h2.2M192.3 70.2l-.1 6.4M199.2 69.6v2.6h8.4l.2 2.8 3.4 3h1.1l1.9 1.2v3.4l-2.3 1.4h-1.2l-2 2.3v33l-2.5 2.5h-2.8M111.9 83.7l.4 .5v5l-.6 .6v6.9M113.9 82.4h-2.8l-.6 .6v1.5l.3 .3v3.7l-.6 .6v7.6l-5.7 5.8M116.6 97.3l-3 3.1M117.2 88.2h.1"/>
<path d="M117.3 88.2l1.5 1.5v.9l.4 .5-12.9 12.9-9.7 .1-4.5 8.1v23.2l2.1 5.5h6.3l4.3 4.2-.1 16.9 1.7 2.9 69.3-.2M119.4 88.2l1.2 1.2v1.8l-9.5 9.5 .4 .3M121.6 88h.1M121.7 88l-.1 4.3-3.4 3.5M121.8 87.8l-.2 .2M123.3 82.1l-6.1 6.1M126.1 81.6l.1 .1M130.9 93.9l-.5 .1-4.5 4.1-5.3 5.4-8.2-.1-3.5 3.6h-1.3l-.2-.2-9 .1-3.8 6.9 .1 21.2 1.1 3.2h5.5l1.1-2h3.6l2.8 2.9v20.7l.2 .2h69l.1-8 3.4-3.5h3.6l1.5 1.4M131 88.3l1.2 1.7 3.3 3.2v8.7l5.5 5.4v1.9l-1.4 1.3h-1l-.2 1.6-1.2 1.4M133 88.5l3.7 3.7 .1 8.8 5.7 5.7v2.9l1 1.1h.3M135.2 88.2l-.6 .6 3.1 3v3.9l3.7 .1v5M136.5 83.8h-3.2l.3 .1"/>
<path d="M138 88.4v.1l7.5 7.6v.5l5.1 5.2-.1 1.8 .4-.2h9.5l1-1h3.2l.3 .4M143.4 98.6l-.1 7.3 2.7 4.3 .1 17.3-2.9-.1 .1 7.1M151.4 83l2.1 2.1h4.9l11.1 12.4h2.8l6.8 6.8-.9 .9v.3l1.8 1.9M153.1 88.5v5.2M153.8 97.9l-3.6 3.6M155.3 88.1v10l1 1h9.3l2.8 3-.1 .3M156.8 80.9h-7.3M161.2 95.6l4.9-.1 14.2 14.3v16.5h2.8l.9 .9v11.3h-.6l-4.3 4.3M165.1 88.2l4.1 4.7 .1 2M165.1 85.3h-3.6l-.2 .2M189.3 93.9l1-.2 3.5 3.6 1 .8 .1 4.9 .3 .6-.2 10.8M191 87.5v5.3l1.4 1.4h5.2l.4 .4 .2 4.8 1.4 1.4h1.9"/>
<path d="M192.8 88.4l3.8 3.7v.3h7.4l1.3 1.3v23.5l-.7 .7h-1.2M108.3 119.3l4.5 4.6h17.1l.3 .3M110.1 117.8l4 4.1h16.1M113.7 105.5h-1.4l-3 2.5-10-.1-3.4 6.4v20.1l1.1 2.8h3.5l1.5-2.6h4.2l.4 .8 3.3 3.3v19.9l.3 .3h1.9l.3-.3M114.2 117.4l3 3.1M115.5 105.4h2l1.9 1.9v7l3.4 3.5 5.7-.1M117.9 108.6l-4.1 3h-5l-1.3 1.3h-2.2l-.9-.3M118 114.2l-.6 .7v.9l-7.7-.1-1.5 1.5-7.3-.1M129.2 115.3l2.9 1.5v17.3l-.2 .2M131.6 100.3h-2.5l-3.6 4v2.1l-5.1 .1M136.3 102.6h.1M136.8 107.9v3.2l-1.5 1.8h-14.5"/>
<path d="M138.9 107.9v-.9l-2.8-2.8h-6.1l-.3 .4v3.6M139.3 116.1l-4.3 4.2M141 107.7h.1M144.7 113.7h.1h-5.4l-4 4h-1.9M147.5 113.6h6.5M165.7 113.8l-4.3 4.2M168.1 104.5l-.7-.1h-6.3l-2.4 .7h-10.8l-.6 .9v3M169.5 107.5l1 1.9v7l-1.2 1.2h-1l-2.1 2.1h-9.8l-1.7 1.5v13.1M172.1 105.2l.2 .1h-2.4l-1.2 1.1h-1.2l-.9-.9h-4.9l-.9 .9M172.3 108.6l.9 1.7v8.2l-1 1h-4.1l-2.7 2.7v2.6h.4v9.6M175.3 109.7l1.3 2v22.8M176.6 113.8h2.2"/>
<path d="M184.8 101.7l1.4 2.4v12.8l11.8 14.4h3.5M187.6 104.2l.1 12.6 6 7M188.9 102.5l.3 2.8v11.3l9.6 10.9h2.7M190.5 101.4l.1 14.7 8.5 9.5h2.4M192 103.5v-.2v12.1l7.2 8.2 2.3 .1M193.5 101.1v13.9l6 6.8h2M196.2 102.1l.3 .5v12.5l3.2 4.7h1.8M198.1 102.1v12.9l1.8 2.9h1.6M201.5 102.7l-.5 .1-1.8 1.8v2.5l.3 .3M203.4 119.8l1.5-.1 .4 .5h.3M210.5 113.8l.6 .6h1.5l2.2 2.1 .1 43.5-1.6 1.4h-6.4l-3.3 3.3h-4.4M98.8 125.5v.1"/>
<path d="M104.2 138.1l2.8 3.1M104.4 122.8v8.9l1.6 1.6h9.2l.4 .4 .1 6M104.4 130.7l-.7 .6h-4.8M106 120.7l5.3 5.2h19M110.6 136.5h-.6l2.4 2.3v8.1l1.2 1.2h18.1l.8-.7h18.5l.5-.5h33.9M116.3 127.8l9.2 9.1h.3l.9-.9h6.4l2.9 3.5h28.7l6.2-6.5h.4M126.4 127.7v6.5M133.8 126h.1M137.5 128l-.1 6.5M144.5 124l-.2 .1h-10.2M144.6 126h-10.7M144.7 121.9l-10.7 .1"/>
<path d="M147.5 122h3.4l.3 .3v1.9M147.5 125.9h7.2M149 128v6.3M160.2 128v6.5M161.7 124.1l-3.9 4 1.2 1.2v2.7l-6.1 6.1h-8.2l-3.7-3.6 .1-4.7-1.5-2.5M171.3 127.9l-.1 6.7M176.6 125h.1M182.3 127.7l.1 6.6-5.8 6.5h-49.7l-7.8-8.8h-7.3l-.3-.3M186.7 127.5l4.9 4.9-8.8 8.8M192 121.6l1.7 2.2M193.7 123.8l4.8 5.6h3M194.1 136.4l4.1 5 2.2 2.2h3.5l1.4-1.5v-2.4l-.8-.8h-1.1"/>
<path d="M201.5 133.2h1.9M201.5 135.1h1.9M203.4 123.7h1.5l3.6 3 1.3 1.4h1.4l1 1.3M203.4 129.4h5.5l3.7 3.8v24.4l-1.1 1.1h-5.8l-1 1h-6.2l-4-2.1v-5.2l-3.1-2.5-.7-1.3-.2-5.8h-11.4M203.4 127.5l3.8-.1 .6 .6M203.4 131.3h5.7l1.7 1.7 .1 24.1-1.2 .6-8.1-.1-2.2 .5M203.4 131.3h.1M208.2 122.2l.1 2.5 1.9 1.9 3 .9 .4 .8 .1 30.1-1.7 1.8h-5.8l-.8 .8h-7.1l-.9 .9h-61l-28.1-.2v-.2l-1.3-.8-.1-16.9-4.2-4.5M149.5 145.7l37.8-.2 3.1 5.5 2.9 2.3v6l1.1 1.1M179.1 142.8l-49.3 .1-2.6 2.5M181.5 151.8h6.1M188.8 144.5l-.6-.3h-56.6l-.8 .9-.7 1.4"/>
<path d="M196.1 155.2l6 .1M201.5 140.8h1.9M201.7 146.7l-3.1 2.6h-5.3M109.3 168.7l3.1-.1h29.2l1.3 .9M112.4 167.1h29.3l4.4 .6M178.1 164.7h11.4l.1 .6"/>
</g>
<path d="M158.1 70.3l-10.7 .1-.2 13.7 2.6 2.4h7l.9 .5v9.6l.8 .8h7.5l6.1 6.2v1.6M108.9 83.9v4.3M153.4 83h12l2.1 2.1M157.7 89v.1M196.3 88.4l2 2h7.1l1.6 1.6v4.4M117.9 110.9l-2.6 2.8h-6l-.9 .9h-5M172.3 105.3l2.3 2.4h1.2l1.7 1.6M98.8 125.5h4.2" fill="none" stroke="#000080" stroke-width="1.2"/>
<path d="M197.7 41.4l3 2.4 5.6 7.6v7.9l-2.7 3.7h-1.5" fill="none" stroke="#000080" stroke-width="1.9"/>
<circle cx="203.4" cy="140.8" r=".91" fill="#008000" stroke="#008000" stroke-width=".21"/>
<circle cx="203.4" cy="140.8" r=".53" fill="#fff" stroke="#000" stroke-width=".21"/>
<circle cx="201.5" cy="140.8" r=".91" fill="#008000" stroke="#008000" stroke-width=".21"/>
<circle cx="201.5" cy="140.8" r=".53" fill="#fff" stroke="#000" stroke-width=".21"/>
<circle cx="203.4" cy="138.9" r=".91" fill="#008000" stroke="#008000" stroke-width=".21"/>
<circle cx="203.4" cy="138.9" r=".53" fill="#fff" stroke="#000" stroke-width=".21"/>
<circle cx="201.5" cy="138.9" r=".91" fill="#008000" stroke="#008000" stroke-width=".21"/>
<circle cx="201.5" cy="138.9" r=".53" fill="#fff" stroke="#000" stroke-width=".21"/>
<circle cx="203.4" cy="137" r=".91" fill="#008000" stroke="#008000" stroke-width=".21"/>
<circle cx="203.4" cy="137" r=".53" fill="#fff" stroke="#000" stroke-width=".21"/>
<circle cx="201.5" cy="137" r=".91" fill="#008000" stroke="#008000" stroke-width=".21"/>
<circle cx="201.5" cy="137" r=".53" fill="#fff" stroke="#000" stroke-width=".21"/>
<circle cx="203.4" cy="135.1" r=".91" fill="#008000" stroke="#008000" stroke-width=".21"/>
<circle cx="203.4" cy="135.1" r=".53" fill="#fff" stroke="#000" stroke-width=".21"/>
<circle cx="201.5" cy="135.1" r=".91" fill="#008000" stroke="#008000" stroke-width=".21"/>
<circle cx="201.5" cy="135.1" r=".53" fill="#fff" stroke="#000" stroke-width=".21"/>
<circle cx="203.4" cy="133.2" r=".91" fill="#008000" stroke="#008000" stroke-width=".21"/>
<circle cx="203.4" cy="133.2" r=".53" fill="#fff" stroke="#000" stroke-width=".21"/>
<circle cx="201.5" cy="133.2" r=".91" fill="#008000" stroke="#008000" stroke-width=".21"/>
<circle cx="201.5" cy="133.2" r=".53" fill="#fff" stroke="#000" stroke-width=".21"/>
<circle cx="203.4" cy="131.3" r=".91" fill="#008000" stroke="#008000" stroke-width=".21"/>
<circle cx="203.4" cy="131.3" r=".53" fill="#fff" stroke="#000" stroke-width=".21"/>
<circle cx="201.5" cy="131.3" r=".91" fill="#008000" stroke="#008000" stroke-width=".21"/>
<circle cx="201.5" cy="131.3" r=".53" fill="#fff" stroke="#000" stroke-width=".21"/>
<circle cx="203.4" cy="129.4" r=".91" fill="#008000" stroke="#008000" stroke-width=".21"/>
<circle cx="203.4" cy="129.4" r=".53" fill="#fff" stroke="#000" stroke-width=".21"/>
<circle cx="201.5" cy="129.4" r=".91" fill="#008000" stroke="#008000" stroke-width=".21"/>
<circle cx="201.5" cy="129.4" r=".53" fill="#fff" stroke="#000" stroke-width=".21"/>
<circle cx="203.4" cy="127.5" r=".91" fill="#008000" stroke="#008000" stroke-width=".21"/>
<circle cx="203.4" cy="127.5" r=".53" fill="#fff" stroke="#000" stroke-width=".21"/>
<circle cx="201.5" cy="127.5" r=".91" fill="#008000" stroke="#008000" stroke-width=".21"/>
<circle cx="201.5" cy="127.5" r=".53" fill="#fff" stroke="#000" stroke-width=".21"/>
<circle cx="203.4" cy="125.6" r=".91" fill="#008000" stroke="#008000" stroke-width=".21"/>
<circle cx="203.4" cy="125.6" r=".53" fill="#fff" stroke="#000" stroke-width=".21"/>
<circle cx="201.5" cy="125.6" r=".91" fill="#008000" stroke="#008000" stroke-width=".21"/>
<circle cx="201.5" cy="125.6" r=".53" fill="#fff" stroke="#000" stroke-width=".21"/>
<circle cx="203.4" cy="123.7" r=".91" fill="#008000" stroke="#008000" stroke-width=".21"/>
<circle cx="203.4" cy="123.7" r=".53" fill="#fff" stroke="#000" stroke-width=".21"/>
<circle cx="201.5" cy="123.7" r=".91" fill="#008000" stroke="#008000" stroke-width=".21"/>
<circle cx="201.5" cy="123.7" r=".53" fill="#fff" stroke="#000" stroke-width=".21"/>
<circle cx="203.4" cy="121.8" r=".91" fill="#008000" stroke="#008000" stroke-width=".21"/>
<circle cx="203.4" cy="121.8" r=".53" fill="#fff" stroke="#000" stroke-width=".21"/>
<circle cx="201.5" cy="121.8" r=".91" fill="#008000" stroke="#008000" stroke-width=".21"/>
<circle cx="201.5" cy="121.8" r=".53" fill="#fff" stroke="#000" stroke-width=".21"/>
<circle cx="203.4" cy="119.8" r=".91" fill="#008000" stroke="#008000" stroke-width=".21"/>
<circle cx="203.4" cy="119.8" r=".53" fill="#fff" stroke="#000" stroke-width=".21"/>
<circle cx="201.5" cy="119.8" r=".91" fill="#008000" stroke="#008000" stroke-width=".21"/>
<circle cx="201.5" cy="119.8" r=".53" fill="#fff" stroke="#000" stroke-width=".21"/>
<circle cx="203.4" cy="117.9" r=".91" fill="#008000" stroke="#008000" stroke-width=".21"/>
<circle cx="203.4" cy="117.9" r=".53" fill="#fff" stroke="#000" stroke-width=".21"/>
<circle cx="201.5" cy="117.9" r=".91" fill="#008000" stroke="#008000" stroke-width=".21"/>
<circle cx="201.5" cy="117.9" r=".53" fill="#fff" stroke="#000" stroke-width=".21"/>
<circle cx="203.4" cy="116" r=".91" fill="#008000" stroke="#008000" stroke-width=".21"/>
<circle cx="203.4" cy="116" r=".53" fill="#fff" stroke="#000" stroke-width=".21"/>
<circle cx="201.5" cy="116" r=".91" fill="#008000" stroke="#008000" stroke-width=".21"/>
<circle cx="201.5" cy="116" r=".53" fill="#fff" stroke="#000" stroke-width=".21"/>
<circle cx="203.4" cy="114.1" r=".91" fill="#008000" stroke="#008000" stroke-width=".21"/>
<circle cx="203.4" cy="114.1" r=".53" fill="#fff" stroke="#000" stroke-width=".21"/>
<circle cx="201.5" cy="114.1" r=".91" fill="#008000" stroke="#008000" stroke-width=".21"/>
<circle cx="201.5" cy="114.1" r=".53" fill="#fff" stroke="#000" stroke-width=".21"/>
<circle cx="203.4" cy="112.2" r=".91" fill="#008000" stroke="#008000" stroke-width=".21"/>
<circle cx="203.4" cy="112.2" r=".53" fill="#fff" stroke="#000" stroke-width=".21"/>
<circle cx="201.5" cy="112.2" r=".91" fill="#008000" stroke="#008000" stroke-width=".21"/>
<circle cx="201.5" cy="112.2" r=".53" fill="#fff" stroke="#000" stroke-width=".21"/>
<circle cx="203.4" cy="110.3" r=".91" fill="#008000" stroke="#008000" stroke-width=".21"/>
<circle cx="203.4" cy="110.3" r=".53" fill="#fff" stroke="#000" stroke-width=".21"/>
<circle cx="201.5" cy="110.3" r=".91" fill="#008000" stroke="#008000" stroke-width=".21"/>
<circle cx="201.5" cy="110.3" r=".53" fill="#fff" stroke="#000" stroke-width=".21"/>
<circle cx="203.4" cy="108.4" r=".91" fill="#008000" stroke="#008000" stroke-width=".21"/>
<circle cx="203.4" cy="108.4" r=".53" fill="#fff" stroke="#000" stroke-width=".21"/>
<circle cx="201.5" cy="108.4" r=".91" fill="#008000" stroke="#008000" stroke-width=".21"/>
<circle cx="201.5" cy="108.4" r=".53" fill="#fff" stroke="#000" stroke-width=".21"/>
<circle cx="203.4" cy="106.5" r=".91" fill="#008000" stroke="#008000" stroke-width=".21"/>
<circle cx="203.4" cy="106.5" r=".53" fill="#fff" stroke="#000" stroke-width=".21"/>
<circle cx="201.5" cy="106.5" r=".91" fill="#008000" stroke="#008000" stroke-width=".21"/>
<circle cx="201.5" cy="106.5" r=".53" fill="#fff" stroke="#000" stroke-width=".21"/>
<circle cx="203.4" cy="104.6" r=".91" fill="#008000" stroke="#008000" stroke-width=".21"/>
<circle cx="203.4" cy="104.6" r=".53" fill="#fff" stroke="#000" stroke-width=".21"/>
<circle cx="201.5" cy="104.6" r=".91" fill="#008000" stroke="#008000" stroke-width=".21"/>
<circle cx="201.5" cy="104.6" r=".53" fill="#fff" stroke="#000" stroke-width=".21"/>
<circle cx="203.4" cy="102.7" r=".91" fill="#008000" stroke="#008000" stroke-width=".21"/>
<circle cx="203.4" cy="102.7" r=".53" fill="#fff" stroke="#000" stroke-width=".21"/>
<circle cx="201.5" cy="102.7" r=".91" fill="#008000" stroke="#008000" stroke-width=".21"/>
<circle cx="201.5" cy="102.7" r=".53" fill="#fff" stroke="#000" stroke-width=".21"/>
<circle cx="203.4" cy="100.8" r=".91" fill="#008000" stroke="#008000" stroke-width=".21"/>
<circle cx="203.4" cy="100.8" r=".53" fill="#fff" stroke="#000" stroke-width=".21"/>
<circle cx="201.5" cy="100.8" r=".91" fill="#008000" stroke="#008000" stroke-width=".21"/>
<circle cx="201.5" cy="100.8" r=".53" fill="#fff" stroke="#000" stroke-width=".21"/>
<circle cx="203.4" cy="98.9" r=".91" fill="#008000" stroke="#008000" stroke-width=".21"/>
<circle cx="203.4" cy="98.9" r=".53" fill="#fff" stroke="#000" stroke-width=".21"/>
<circle cx="201.5" cy="98.9" r=".91" fill="#008000" stroke="#008000" stroke-width=".21"/>
<circle cx="201.5" cy="98.9" r=".53" fill="#fff" stroke="#000" stroke-width=".21"/>
<circle cx="203.4" cy="97" r=".91" fill="#008000" stroke="#008000" stroke-width=".21"/>
<circle cx="203.4" cy="97" r=".53" fill="#fff" stroke="#000" stroke-width=".21"/>
<circle cx="201.5" cy="97" r=".91" fill="#008000" stroke="#008000" stroke-width=".21"/>
<circle cx="201.5" cy="97" r=".53" fill="#fff" stroke="#000" stroke-width=".21"/>
<circle cx="203.4" cy="95.1" r=".91" fill="#008000" stroke="#008000" stroke-width=".21"/>
<circle cx="203.4" cy="95.1" r=".53" fill="#fff" stroke="#000" stroke-width=".21"/>
<circle cx="201.5" cy="95.1" r=".91" fill="#008000" stroke="#008000" stroke-width=".21"/>
<circle cx="201.5" cy="95.1" r=".53" fill="#fff" stroke="#000" stroke-width=".21"/>
<circle cx="102.5" cy="41.4" r="1.14" fill="#008000" stroke="#008000" stroke-width=".21"/>
<circle cx="102.5" cy="41.4" r=".76" fill="#fff" stroke="#000" stroke-width=".21"/>
<circle cx="102.5" cy="37.5" r="1.14" fill="#008000" stroke="#008000" stroke-width=".21"/>
<circle cx="102.5" cy="37.5" r=".76" fill="#fff" stroke="#000" stroke-width=".21"/>
<circle cx="106.3" cy="41.4" r="1.14" fill="#008000" stroke="#008000" stroke-width=".21"/>
<circle cx="106.3" cy="41.4" r=".76" fill="#fff" stroke="#000" stroke-width=".21"/>
<circle cx="106.3" cy="37.5" r="1.14" fill="#008000" stroke="#008000" stroke-width=".21"/>
<circle cx="106.3" cy="37.5" r=".76" fill="#fff" stroke="#000" stroke-width=".21"/>
<circle cx="110.1" cy="41.4" r="1.14" fill="#008000" stroke="#008000" stroke-width=".21"/>
<circle cx="110.1" cy="41.4" r=".76" fill="#fff" stroke="#000" stroke-width=".21"/>
<circle cx="110.1" cy="37.5" r="1.14" fill="#008000" stroke="#008000" stroke-width=".21"/>
<circle cx="110.1" cy="37.5" r=".76" fill="#fff" stroke="#000" stroke-width=".21"/>
<circle cx="113.9" cy="41.4" r="1.14" fill="#008000" stroke="#008000" stroke-width=".21"/>
<circle cx="113.9" cy="41.4" r=".76" fill="#fff" stroke="#000" stroke-width=".21"/>
<circle cx="113.9" cy="37.5" r="1.14" fill="#008000" stroke="#008000" stroke-width=".21"/>
<circle cx="113.9" cy="37.5" r=".76" fill="#fff" stroke="#000" stroke-width=".21"/>
<circle cx="117.8" cy="41.4" r="1.14" fill="#008000" stroke="#008000" stroke-width=".21"/>
<circle cx="117.8" cy="41.4" r=".76" fill="#fff" stroke="#000" stroke-width=".21"/>
<circle cx="117.8" cy="37.5" r="1.14" fill="#008000" stroke="#008000" stroke-width=".21"/>
<circle cx="117.8" cy="37.5" r=".76" fill="#fff" stroke="#000" stroke-width=".21"/>
<circle cx="121.6" cy="41.4" r="1.14" fill="#008000" stroke="#008000" stroke-width=".21"/>
<circle cx="121.6" cy="41.4" r=".76" fill="#fff" stroke="#000" stroke-width=".21"/>
<circle cx="121.6" cy="37.5" r="1.14" fill="#008000" stroke="#008000" stroke-width=".21"/>
<circle cx="121.6" cy="37.5" r=".76" fill="#fff" stroke="#000" stroke-width=".21"/>
<circle cx="125.4" cy="41.4" r="1.14" fill="#008000" stroke="#008000" stroke-width=".21"/>
<circle cx="125.4" cy="41.4" r=".76" fill="#fff" stroke="#000" stroke-width=".21"/>
<circle cx="125.4" cy="37.5" r="1.14" fill="#008000" stroke="#008000" stroke-width=".21"/>
<circle cx="125.4" cy="37.5" r=".76" fill="#fff" stroke="#000" stroke-width=".21"/>
<circle cx="129.2" cy="41.4" r="1.14" fill="#008000" stroke="#008000" stroke-width=".21"/>
<circle cx="129.2" cy="41.4" r=".76" fill="#fff" stroke="#000" stroke-width=".21"/>
<circle cx="129.2" cy="37.5" r="1.14" fill="#008000" stroke="#008000" stroke-width=".21"/>
<circle cx="129.2" cy="37.5" r=".76" fill="#fff" stroke="#000" stroke-width=".21"/>
<circle cx="133" cy="41.4" r="1.14" fill="#008000" stroke="#008000" stroke-width=".21"/>
<circle cx="133" cy="41.4" r=".76" fill="#fff" stroke="#000" stroke-width=".21"/>
<circle cx="133" cy="37.5" r="1.14" fill="#008000" stroke="#008000" stroke-width=".21"/>
<circle cx="133" cy="37.5" r=".76" fill="#fff" stroke="#000" stroke-width=".21"/>
<circle cx="136.8" cy="41.4" r="1.14" fill="#008000" stroke="#008000" stroke-width=".21"/>
<circle cx="136.8" cy="41.4" r=".76" fill="#fff" stroke="#000" stroke-width=".21"/>
<circle cx="136.8" cy="37.5" r="1.14" fill="#008000" stroke="#008000" stroke-width=".21"/>
<circle cx="136.8" cy="37.5" r=".76" fill="#fff" stroke="#000" stroke-width=".21"/>
<circle cx="140.6" cy="41.4" r="1.14" fill="#008000" stroke="#008000" stroke-width=".21"/>
<circle cx="140.6" cy="41.4" r=".76" fill="#fff" stroke="#000" stroke-width=".21"/>
<circle cx="140.6" cy="37.5" r="1.14" fill="#008000" stroke="#008000" stroke-width=".21"/>
<circle cx="140.6" cy="37.5" r=".76" fill="#fff" stroke="#000" stroke-width=".21"/>
<circle cx="144.4" cy="41.4" r="1.14" fill="#008000" stroke="#008000" stroke-width=".21"/>
<circle cx="144.4" cy="41.4" r=".76" fill="#fff" stroke="#000" stroke-width=".21"/>
<circle cx="144.4" cy="37.5" r="1.14" fill="#008000" stroke="#008000" stroke-width=".21"/>
<circle cx="144.4" cy="37.5" r=".76" fill="#fff" stroke="#000" stroke-width=".21"/>
<circle cx="148.2" cy="41.4" r="1.14" fill="#008000" stroke="#008000" stroke-width=".21"/>
<circle cx="148.2" cy="41.4" r=".76" fill="#fff" stroke="#000" stroke-width=".21"/>
<circle cx="148.2" cy="37.5" r="1.14" fill="#008000" stroke="#008000" stroke-width=".21"/>
<circle cx="148.2" cy="37.5" r=".76" fill="#fff" stroke="#000" stroke-width=".21"/>
<circle cx="152" cy="41.4" r="1.14" fill="#008000" stroke="#008000" stroke-width=".21"/>
<circle cx="152" cy="41.4" r=".76" fill="#fff" stroke="#000" stroke-width=".21"/>
<circle cx="152" cy="37.5" r="1.14" fill="#008000" stroke="#008000" stroke-width=".21"/>
<circle cx="152" cy="37.5" r=".76" fill="#fff" stroke="#000" stroke-width=".21"/>
<circle cx="155.8" cy="41.4" r="1.14" fill="#008000" stroke="#008000" stroke-width=".21"/>
<circle cx="155.8" cy="41.4" r=".76" fill="#fff" stroke="#000" stroke-width=".21"/>
<circle cx="155.8" cy="37.5" r="1.14" fill="#008000" stroke="#008000" stroke-width=".21"/>
<circle cx="155.8" cy="37.5" r=".76" fill="#fff" stroke="#000" stroke-width=".21"/>
<circle cx="159.6" cy="41.4" r="1.14" fill="#008000" stroke="#008000" stroke-width=".21"/>
<circle cx="159.6" cy="41.4" r=".76" fill="#fff" stroke="#000" stroke-width=".21"/>
<circle cx="159.6" cy="37.5" r="1.14" fill="#008000" stroke="#008000" stroke-width=".21"/>
<circle cx="159.6" cy="37.5" r=".76" fill="#fff" stroke="#000" stroke-width=".21"/>
<circle cx="163.4" cy="41.4" r="1.14" fill="#008000" stroke="#008000" stroke-width=".21"/>
<circle cx="163.4" cy="41.4" r=".76" fill="#fff" stroke="#000" stroke-width=".21"/>
<circle cx="163.4" cy="37.5" r="1.14" fill="#008000" stroke="#008000" stroke-width=".21"/>
<circle cx="163.4" cy="37.5" r=".76" fill="#fff" stroke="#000" stroke-width=".21"/>
<circle cx="167.3" cy="41.4" r="1.14" fill="#008000" stroke="#008000" stroke-width=".21"/>
<circle cx="167.3" cy="41.4" r=".76" fill="#fff" stroke="#000" stroke-width=".21"/>
<circle cx="167.3" cy="37.5" r="1.14" fill="#008000" stroke="#008000" stroke-width=".21"/>
<circle cx="167.3" cy="37.5" r=".76" fill="#fff" stroke="#000" stroke-width=".21"/>
<circle cx="171.1" cy="41.4" r="1.14" fill="#008000" stroke="#008000" stroke-width=".21"/>
<circle cx="171.1" cy="41.4" r=".76" fill="#fff" stroke="#000" stroke-width=".21"/>
<circle cx="171.1" cy="37.5" r="1.14" fill="#008000" stroke="#008000" stroke-width=".21"/>
<circle cx="171.1" cy="37.5" r=".76" fill="#fff" stroke="#000" stroke-width=".21"/>
<circle cx="174.9" cy="41.4" r="1.14" fill="#008000" stroke="#008000" stroke-width=".21"/>
<circle cx="174.9" cy="41.4" r=".76" fill="#fff" stroke="#000" stroke-width=".21"/>
<circle cx="174.9" cy="37.5" r="1.14" fill="#008000" stroke="#008000" stroke-width=".21"/>
<circle cx="174.9" cy="37.5" r=".76" fill="#fff" stroke="#000" stroke-width=".21"/>
<circle cx="178.7" cy="41.4" r="1.14" fill="#008000" stroke="#008000" stroke-width=".21"/>
<circle cx="178.7" cy="41.4" r=".76" fill="#fff" stroke="#000" stroke-width=".21"/>
<circle cx="178.7" cy="37.5" r="1.14" fill="#008000" stroke="#008000" stroke-width=".21"/>
<circle cx="178.7" cy="37.5" r=".76" fill="#fff" stroke="#000" stroke-width=".21"/>
<circle cx="182.5" cy="41.4" r="1.14" fill="#008000" stroke="#008000" stroke-width=".21"/>
<circle cx="182.5" cy="41.4" r=".76" fill="#fff" stroke="#000" stroke-width=".21"/>
<circle cx="182.5" cy="37.5" r="1.14" fill="#008000" stroke="#008000" stroke-width=".21"/>
<circle cx="182.5" cy="37.5" r=".76" fill="#fff" stroke="#000" stroke-width=".21"/>
<circle cx="186.3" cy="41.4" r="1.14" fill="#008000" stroke="#008000" stroke-width=".21"/>
<circle cx="186.3" cy="41.4" r=".76" fill="#fff" stroke="#000" stroke-width=".21"/>
<circle cx="186.3" cy="37.5" r="1.14" fill="#008000" stroke="#008000" stroke-width=".21"/>
<circle cx="186.3" cy="37.5" r=".76" fill="#fff" stroke="#000" stroke-width=".21"/>
<circle cx="190.1" cy="41.4" r="1.14" fill="#008000" stroke="#008000" stroke-width=".21"/>
<circle cx="190.1" cy="41.4" r=".76" fill="#fff" stroke="#000" stroke-width=".21"/>
<circle cx="190.1" cy="37.5" r="1.14" fill="#008000" stroke="#008000" stroke-width=".21"/>
<circle cx="190.1" cy="37.5" r=".76" fill="#fff" stroke="#000" stroke-width=".21"/>
<circle cx="193.9" cy="41.4" r="1.14" fill="#008000" stroke="#008000" stroke-width=".21"/>
<circle cx="193.9" cy="41.4" r=".76" fill="#fff" stroke="#000" stroke-width=".21"/>
<circle cx="193.9" cy="37.5" r="1.14" fill="#008000" stroke="#008000" stroke-width=".21"/>
<circle cx="193.9" cy="37.5" r=".76" fill="#fff" stroke="#000" stroke-width=".21"/>
<circle cx="197.7" cy="41.4" r="1.14" fill="#008000" stroke="#008000" stroke-width=".21"/>
<circle cx="197.7" cy="41.4" r=".76" fill="#fff" stroke="#000" stroke-width=".21"/>
<circle cx="197.7" cy="37.5" r="1.14" fill="#008000" stroke="#008000" stroke-width=".21"/>
<circle cx="197.7" cy="37.5" r=".76" fill="#fff" stroke="#000" stroke-width=".21"/>
<circle cx="102.5" cy="49" r="1.14" fill="#008000" stroke="#008000" stroke-width=".21"/>
<circle cx="102.5" cy="49" r=".76" fill="#fff" stroke="#000" stroke-width=".21"/>
<circle cx="102.5" cy="45.1" r="1.14" fill="#008000" stroke="#008000" stroke-width=".21"/>
<circle cx="102.5" cy="45.1" r=".76" fill="#fff" stroke="#000" stroke-width=".21"/>
<circle cx="106.3" cy="49" r="1.14" fill="#008000" stroke="#008000" stroke-width=".21"/>
<circle cx="106.3" cy="49" r=".76" fill="#fff" stroke="#000" stroke-width=".21"/>
<circle cx="106.3" cy="45.1" r="1.14" fill="#008000" stroke="#008000" stroke-width=".21"/>
<circle cx="106.3" cy="45.1" r=".76" fill="#fff" stroke="#000" stroke-width=".21"/>
<circle cx="110.1" cy="49" r="1.14" fill="#008000" stroke="#008000" stroke-width=".21"/>
<circle cx="110.1" cy="49" r=".76" fill="#fff" stroke="#000" stroke-width=".21"/>
<circle cx="110.1" cy="45.1" r="1.14" fill="#008000" stroke="#008000" stroke-width=".21"/>
<circle cx="110.1" cy="45.1" r=".76" fill="#fff" stroke="#000" stroke-width=".21"/>
<circle cx="113.9" cy="49" r="1.14" fill="#008000" stroke="#008000" stroke-width=".21"/>
<circle cx="113.9" cy="49" r=".76" fill="#fff" stroke="#000" stroke-width=".21"/>
<circle cx="113.9" cy="45.1" r="1.14" fill="#008000" stroke="#008000" stroke-width=".21"/>
<circle cx="113.9" cy="45.1" r=".76" fill="#fff" stroke="#000" stroke-width=".21"/>
<circle cx="117.8" cy="49" r="1.14" fill="#008000" stroke="#008000" stroke-width=".21"/>
<circle cx="117.8" cy="49" r=".76" fill="#fff" stroke="#000" stroke-width=".21"/>
<circle cx="117.8" cy="45.1" r="1.14" fill="#008000" stroke="#008000" stroke-width=".21"/>
<circle cx="117.8" cy="45.1" r=".76" fill="#fff" stroke="#000" stroke-width=".21"/>
<circle cx="121.6" cy="49" r="1.14" fill="#008000" stroke="#008000" stroke-width=".21"/>
<circle cx="121.6" cy="49" r=".76" fill="#fff" stroke="#000" stroke-width=".21"/>
<circle cx="121.6" cy="45.1" r="1.14" fill="#008000" stroke="#008000" stroke-width=".21"/>
<circle cx="121.6" cy="45.1" r=".76" fill="#fff" stroke="#000" stroke-width=".21"/>
<circle cx="125.4" cy="49" r="1.14" fill="#008000" stroke="#008000" stroke-width=".21"/>
<circle cx="125.4" cy="49" r=".76" fill="#fff" stroke="#000" stroke-width=".21"/>
<circle cx="125.4" cy="45.1" r="1.14" fill="#008000" stroke="#008000" stroke-width=".21"/>
<circle cx="125.4" cy="45.1" r=".76" fill="#fff" stroke="#000" stroke-width=".21"/>
<circle cx="129.2" cy="49" r="1.14" fill="#008000" stroke="#008000" stroke-width=".21"/>
<circle cx="129.2" cy="49" r=".76" fill="#fff" stroke="#000" stroke-width=".21"/>
<circle cx="129.2" cy="45.1" r="1.14" fill="#008000" stroke="#008000" stroke-width=".21"/>
<circle cx="129.2" cy="45.1" r=".76" fill="#fff" stroke="#000" stroke-width=".21"/>
<circle cx="133" cy="49" r="1.14" fill="#008000" stroke="#008000" stroke-width=".21"/>
<circle cx="133" cy="49" r=".76" fill="#fff" stroke="#000" stroke-width=".21"/>
<circle cx="133" cy="45.1" r="1.14" fill="#008000" stroke="#008000" stroke-width=".21"/>
<circle cx="133" cy="45.1" r=".76" fill="#fff" stroke="#000" stroke-width=".21"/>
<circle cx="136.8" cy="49" r="1.14" fill="#008000" stroke="#008000" stroke-width=".21"/>
<circle cx="136.8" cy="49" r=".76" fill="#fff" stroke="#000" stroke-width=".21"/>
<circle cx="136.8" cy="45.1" r="1.14" fill="#008000" stroke="#008000" stroke-width=".21"/>
<circle cx="136.8" cy="45.1" r=".76" fill="#fff" stroke="#000" stroke-width=".21"/>
<circle cx="140.6" cy="49" r="1.14" fill="#008000" stroke="#008000" stroke-width=".21"/>
<circle cx="140.6" cy="49" r=".76" fill="#fff" stroke="#000" stroke-width=".21"/>
<circle cx="140.6" cy="45.1" r="1.14" fill="#008000" stroke="#008000" stroke-width=".21"/>
<circle cx="140.6" cy="45.1" r=".76" fill="#fff" stroke="#000" stroke-width=".21"/>
<circle cx="144.4" cy="49" r="1.14" fill="#008000" stroke="#008000" stroke-width=".21"/>
<circle cx="144.4" cy="49" r=".76" fill="#fff" stroke="#000" stroke-width=".21"/>
<circle cx="144.4" cy="45.1" r="1.14" fill="#008000" stroke="#008000" stroke-width=".21"/>
<circle cx="144.4" cy="45.1" r=".76" fill="#fff" stroke="#000" stroke-width=".21"/>
<circle cx="148.2" cy="49" r="1.14" fill="#008000" stroke="#008000" stroke-width=".21"/>
<circle cx="148.2" cy="49" r=".76" fill="#fff" stroke="#000" stroke-width=".21"/>
<circle cx="148.2" cy="45.1" r="1.14" fill="#008000" stroke="#008000" stroke-width=".21"/>
<circle cx="148.2" cy="45.1" r=".76" fill="#fff" stroke="#000" stroke-width=".21"/>
<circle cx="152" cy="49" r="1.14" fill="#008000" stroke="#008000" stroke-width=".21"/>
<circle cx="152" cy="49" r=".76" fill="#fff" stroke="#000" stroke-width=".21"/>
<circle cx="152" cy="45.1" r="1.14" fill="#008000" stroke="#008000" stroke-width=".21"/>
<circle cx="152" cy="45.1" r=".76" fill="#fff" stroke="#000" stroke-width=".21"/>
<circle cx="155.9" cy="49" r="1.14" fill="#008000" stroke="#008000" stroke-width=".21"/>
<circle cx="155.9" cy="49" r=".76" fill="#fff" stroke="#000" stroke-width=".21"/>
<circle cx="155.9" cy="45.1" r="1.14" fill="#008000" stroke="#008000" stroke-width=".21"/>
<circle cx="155.9" cy="45.1" r=".76" fill="#fff" stroke="#000" stroke-width=".21"/>
<circle cx="159.7" cy="49" r="1.14" fill="#008000" stroke="#008000" stroke-width=".21"/>
<circle cx="159.7" cy="49" r=".76" fill="#fff" stroke="#000" stroke-width=".21"/>
<circle cx="159.7" cy="45.1" r="1.14" fill="#008000" stroke="#008000" stroke-width=".21"/>
<circle cx="159.7" cy="45.1" r=".76" fill="#fff" stroke="#000" stroke-width=".21"/>
<circle cx="163.5" cy="49" r="1.14" fill="#008000" stroke="#008000" stroke-width=".21"/>
<circle cx="163.5" cy="49" r=".76" fill="#fff" stroke="#000" stroke-width=".21"/>
<circle cx="163.5" cy="45.1" r="1.14" fill="#008000" stroke="#008000" stroke-width=".21"/>
<circle cx="163.5" cy="45.1" r=".76" fill="#fff" stroke="#000" stroke-width=".21"/>
<circle cx="167.3" cy="49" r="1.14" fill="#008000" stroke="#008000" stroke-width=".21"/>
<circle cx="167.3" cy="49" r=".76" fill="#fff" stroke="#000" stroke-width=".21"/>
<circle cx="167.3" cy="45.1" r="1.14" fill="#008000" stroke="#008000" stroke-width=".21"/>
<circle cx="167.3" cy="45.1" r=".76" fill="#fff" stroke="#000" stroke-width=".21"/>
<circle cx="171.1" cy="49" r="1.14" fill="#008000" stroke="#008000" stroke-width=".21"/>
<circle cx="171.1" cy="49" r=".76" fill="#fff" stroke="#000" stroke-width=".21"/>
<circle cx="171.1" cy="45.1" r="1.14" fill="#008000" stroke="#008000" stroke-width=".21"/>
<circle cx="171.1" cy="45.1" r=".76" fill="#fff" stroke="#000" stroke-width=".21"/>
<circle cx="174.9" cy="49" r="1.14" fill="#008000" stroke="#008000" stroke-width=".21"/>
<circle cx="174.9" cy="49" r=".76" fill="#fff" stroke="#000" stroke-width=".21"/>
<circle cx="174.9" cy="45.1" r="1.14" fill="#008000" stroke="#008000" stroke-width=".21"/>
<circle cx="174.9" cy="45.1" r=".76" fill="#fff" stroke="#000" stroke-width=".21"/>
<circle cx="178.7" cy="49" r="1.14" fill="#008000" stroke="#008000" stroke-width=".21"/>
<circle cx="178.7" cy="49" r=".76" fill="#fff" stroke="#000" stroke-width=".21"/>
<circle cx="178.7" cy="45.1" r="1.14" fill="#008000" stroke="#008000" stroke-width=".21"/>
<circle cx="178.7" cy="45.1" r=".76" fill="#fff" stroke="#000" stroke-width=".21"/>
<circle cx="182.5" cy="49" r="1.14" fill="#008000" stroke="#008000" stroke-width=".21"/>
<circle cx="182.5" cy="49" r=".76" fill="#fff" stroke="#000" stroke-width=".21"/>
<circle cx="182.5" cy="45.1" r="1.14" fill="#008000" stroke="#008000" stroke-width=".21"/>
<circle cx="182.5" cy="45.1" r=".76" fill="#fff" stroke="#000" stroke-width=".21"/>
<circle cx="186.3" cy="49" r="1.14" fill="#008000" stroke="#008000" stroke-width=".21"/>
<circle cx="186.3" cy="49" r=".76" fill="#fff" stroke="#000" stroke-width=".21"/>
<circle cx="186.3" cy="45.1" r="1.14" fill="#008000" stroke="#008000" stroke-width=".21"/>
<circle cx="186.3" cy="45.1" r=".76" fill="#fff" stroke="#000" stroke-width=".21"/>
<circle cx="190.1" cy="49" r="1.14" fill="#008000" stroke="#008000" stroke-width=".21"/>
<circle cx="190.1" cy="49" r=".76" fill="#fff" stroke="#000" stroke-width=".21"/>
<circle cx="190.1" cy="45.1" r="1.14" fill="#008000" stroke="#008000" stroke-width=".21"/>
<circle cx="190.1" cy="45.1" r=".76" fill="#fff" stroke="#000" stroke-width=".21"/>
<circle cx="193.9" cy="49" r="1.14" fill="#008000" stroke="#008000" stroke-width=".21"/>
<circle cx="193.9" cy="49" r=".76" fill="#fff" stroke="#000" stroke-width=".21"/>
<circle cx="193.9" cy="45.1" r="1.14" fill="#008000" stroke="#008000" stroke-width=".21"/>
<circle cx="193.9" cy="45.1" r=".76" fill="#fff" stroke="#000" stroke-width=".21"/>
<circle cx="197.7" cy="49" r="1.14" fill="#008000" stroke="#008000" stroke-width=".21"/>
<circle cx="197.7" cy="49" r=".76" fill="#fff" stroke="#000" stroke-width=".21"/>
<circle cx="197.7" cy="45.1" r="1.14" fill="#008000" stroke="#008000" stroke-width=".21"/>
<circle cx="197.7" cy="45.1" r=".76" fill="#fff" stroke="#000" stroke-width=".21"/>
<circle cx="202.1" cy="81" r="1.8" fill="#008000" stroke="#008000" stroke-width=".21"/>
<circle cx="202.1" cy="81" r="1.21" fill="#fff" stroke="#000" stroke-width=".21"/>
<circle cx="202.1" cy="75" r="1.8" fill="#008000" stroke="#008000" stroke-width=".21"/>
<circle cx="202.1" cy="75" r="1.21" fill="#fff" stroke="#000" stroke-width=".21"/>
<circle cx="202.1" cy="69" r="1.8" fill="#008000" stroke="#008000" stroke-width=".21"/>
<circle cx="202.1" cy="69" r="1.21" fill="#fff" stroke="#000" stroke-width=".21"/>
<circle cx="202.1" cy="63" r="1.8" fill="#008000" stroke="#008000" stroke-width=".21"/>
<circle cx="202.1" cy="63" r="1.21" fill="#fff" stroke="#000" stroke-width=".21"/>
<circle cx="202.1" cy="87" r="2.41" fill="#008000" stroke="#008000" stroke-width=".21"/>
<circle cx="202.1" cy="87" r="1.65" fill="#fff" stroke="#000" stroke-width=".21"/>
<circle cx="202.1" cy="57" r="2.41" fill="#008000" stroke="#008000" stroke-width=".21"/>
<circle cx="202.1" cy="57" r="1.65" fill="#fff" stroke="#000" stroke-width=".21"/>
<circle cx="211.6" cy="62.9" r="1.8" fill="#008000" stroke="#008000" stroke-width=".21"/>
<circle cx="211.6" cy="62.9" r="1.21" fill="#fff" stroke="#000" stroke-width=".21"/>
<circle cx="211.6" cy="68.9" r="1.8" fill="#008000" stroke="#008000" stroke-width=".21"/>
<circle cx="211.6" cy="68.9" r="1.21" fill="#fff" stroke="#000" stroke-width=".21"/>
<circle cx="211.6" cy="74.9" r="1.8" fill="#008000" stroke="#008000" stroke-width=".21"/>
<circle cx="211.6" cy="74.9" r="1.21" fill="#fff" stroke="#000" stroke-width=".21"/>
<circle cx="211.6" cy="80.9" r="1.8" fill="#008000" stroke="#008000" stroke-width=".21"/>
<circle cx="211.6" cy="80.9" r="1.21" fill="#fff" stroke="#000" stroke-width=".21"/>
<circle cx="211.6" cy="86.9" r="1.8" fill="#008000" stroke="#008000" stroke-width=".21"/>
<circle cx="211.6" cy="86.9" r="1.21" fill="#fff" stroke="#000" stroke-width=".21"/>
<circle cx="211.6" cy="92.9" r="1.8" fill="#008000" stroke="#008000" stroke-width=".21"/>
<circle cx="211.6" cy="92.9" r="1.21" fill="#fff" stroke="#000" stroke-width=".21"/>
<circle cx="211.6" cy="98.9" r="1.8" fill="#008000" stroke="#008000" stroke-width=".21"/>
<circle cx="211.6" cy="98.9" r="1.21" fill="#fff" stroke="#000" stroke-width=".21"/>
<circle cx="211.6" cy="104.9" r="1.8" fill="#008000" stroke="#008000" stroke-width=".21"/>
<circle cx="211.6" cy="104.9" r="1.21" fill="#fff" stroke="#000" stroke-width=".21"/>
<circle cx="211.6" cy="110.9" r="1.8" fill="#008000" stroke="#008000" stroke-width=".21"/>
<circle cx="211.6" cy="110.9" r="1.21" fill="#fff" stroke="#000" stroke-width=".21"/>
<circle cx="211.6" cy="116.9" r="1.8" fill="#008000" stroke="#008000" stroke-width=".21"/>
<circle cx="211.6" cy="116.9" r="1.21" fill="#fff" stroke="#000" stroke-width=".21"/>
<circle cx="211.6" cy="56.9" r="2.41" fill="#008000" stroke="#008000" stroke-width=".21"/>
<circle cx="211.6" cy="56.9" r="1.65" fill="#fff" stroke="#000" stroke-width=".21"/>
<circle cx="211.6" cy="122.9" r="2.41" fill="#008000" stroke="#008000" stroke-width=".21"/>
<circle cx="211.6" cy="122.9" r="1.65" fill="#fff" stroke="#000" stroke-width=".21"/>
<path d="M143.4 97.6v1.9" fill="none" stroke="#008000" stroke-width="2"/>
<circle cx="143.4" cy="98.6" r=".61" fill="#fff" stroke="#000" stroke-width=".21"/>
<path d="M139.6 97.6v1.9" fill="none" stroke="#008000" stroke-width="2"/>
<circle cx="139.6" cy="98.6" r=".61" fill="#fff" stroke="#000" stroke-width=".21"/>
<circle cx="115.6" cy="133.7" r=".68" fill="#008000" stroke="#008000" stroke-width=".21"/>
<circle cx="115.6" cy="133.7" r=".38" fill="#fff" stroke="#000" stroke-width=".21"/>
<path d="M115 139h1.4v1.4h-1.4z" fill="#008000" stroke="#008000" stroke-width=".21"/>
<circle cx="115.7" cy="139.7" r=".38" fill="#fff" stroke="#000" stroke-width=".21"/>
<circle cx="104.4" cy="122.8" r=".68" fill="#008000" stroke="#008000" stroke-width=".21"/>
<circle cx="104.4" cy="122.8" r=".38" fill="#fff" stroke="#000" stroke-width=".21"/>
<path d="M98.2 130.7h1.3v1.3h-1.3z" fill="#008000" stroke="#008000" stroke-width=".21"/>
<circle cx="98.9" cy="131.3" r=".38" fill="#fff" stroke="#000" stroke-width=".21"/>
<circle cx="187.6" cy="151.8" r=".68" fill="#008000" stroke="#008000" stroke-width=".21"/>
<circle cx="187.6" cy="151.8" r=".38" fill="#fff" stroke="#000" stroke-width=".21"/>
<circle cx="181.5" cy="151.8" r=".68" fill="#008000" stroke="#008000" stroke-width=".21"/>
<circle cx="181.5" cy="151.8" r=".38" fill="#fff" stroke="#000" stroke-width=".21"/>
<circle cx="169.7" cy="39.4" r=".68" fill="#008000" stroke="#008000" stroke-width=".21"/>
<circle cx="169.7" cy="39.4" r=".38" fill="#fff" stroke="#000" stroke-width=".21"/>
<circle cx="137.2" cy="52.9" r=".76" fill="#008000" stroke="#008000" stroke-width=".21"/>
<circle cx="137.2" cy="52.9" r=".47" fill="#fff" stroke="#000" stroke-width=".21"/>
<circle cx="112.4" cy="53.7" r=".76" fill="#008000" stroke="#008000" stroke-width=".21"/>
<circle cx="112.4" cy="53.7" r=".47" fill="#fff" stroke="#000" stroke-width=".21"/>
<circle cx="112.3" cy="76.2" r=".68" fill="#008000" stroke="#008000" stroke-width=".21"/>
<circle cx="112.3" cy="76.2" r=".38" fill="#fff" stroke="#000" stroke-width=".21"/>
<circle cx="124.7" cy="79.6" r=".68" fill="#008000" stroke="#008000" stroke-width=".21"/>
<circle cx="124.7" cy="79.6" r=".38" fill="#fff" stroke="#000" stroke-width=".21"/>
<circle cx="129.8" cy="79.7" r=".68" fill="#008000" stroke="#008000" stroke-width=".21"/>
<circle cx="129.8" cy="79.7" r=".38" fill="#fff" stroke="#000" stroke-width=".21"/>
<circle cx="136.5" cy="79.7" r=".68" fill="#008000" stroke="#008000" stroke-width=".21"/>
<circle cx="136.5" cy="79.7" r=".38" fill="#fff" stroke="#000" stroke-width=".21"/>
<circle cx="113.6" cy="100.4" r=".68" fill="#008000" stroke="#008000" stroke-width=".21"/>
<circle cx="113.6" cy="100.4" r=".38" fill="#fff" stroke="#000" stroke-width=".21"/>
<circle cx="116.6" cy="97.3" r=".68" fill="#008000" stroke="#008000" stroke-width=".21"/>
<circle cx="116.6" cy="97.3" r=".38" fill="#fff" stroke="#000" stroke-width=".21"/>
<circle cx="113.2" cy="95" r=".68" fill="#008000" stroke="#008000" stroke-width=".21"/>
<circle cx="113.2" cy="95" r=".38" fill="#fff" stroke="#000" stroke-width=".21"/>
<circle cx="144.4" cy="53.8" r=".76" fill="#008000" stroke="#008000" stroke-width=".21"/>
<circle cx="144.4" cy="53.8" r=".44" fill="#fff" stroke="#000" stroke-width=".21"/>
<circle cx="193.3" cy="149.3" r=".68" fill="#008000" stroke="#008000" stroke-width=".21"/>
<circle cx="193.3" cy="149.3" r=".38" fill="#fff" stroke="#000" stroke-width=".21"/>
<circle cx="201.7" cy="146.7" r=".68" fill="#008000" stroke="#008000" stroke-width=".21"/>
<circle cx="201.7" cy="146.7" r=".38" fill="#fff" stroke="#000" stroke-width=".21"/>
<circle cx="171.2" cy="134.6" r=".68" fill="#008000" stroke="#008000" stroke-width=".21"/>
<circle cx="171.2" cy="134.6" r=".38" fill="#fff" stroke="#000" stroke-width=".21"/>
<circle cx="171.3" cy="127.9" r=".68" fill="#008000" stroke="#008000" stroke-width=".21"/>
<circle cx="171.3" cy="127.9" r=".38" fill="#fff" stroke="#000" stroke-width=".21"/>
<circle cx="119.4" cy="88.2" r=".76" fill="#008000" stroke="#008000" stroke-width=".21"/>
<circle cx="119.4" cy="88.2" r=".47" fill="#fff" stroke="#000" stroke-width=".21"/>
<circle cx="111.5" cy="101" r=".68" fill="#008000" stroke="#008000" stroke-width=".21"/>
<circle cx="111.5" cy="101" r=".38" fill="#fff" stroke="#000" stroke-width=".21"/>
<circle cx="114.2" cy="117.4" r=".68" fill="#008000" stroke="#008000" stroke-width=".21"/>
<circle cx="114.2" cy="117.4" r=".38" fill="#fff" stroke="#000" stroke-width=".21"/>
<circle cx="117.2" cy="120.5" r=".68" fill="#008000" stroke="#008000" stroke-width=".21"/>
<circle cx="117.2" cy="120.5" r=".38" fill="#fff" stroke="#000" stroke-width=".21"/>
<circle cx="116.3" cy="127.8" r=".68" fill="#008000" stroke="#008000" stroke-width=".21"/>
<circle cx="116.3" cy="127.8" r=".38" fill="#fff" stroke="#000" stroke-width=".21"/>
<circle cx="176.6" cy="134.5" r=".68" fill="#008000" stroke="#008000" stroke-width=".21"/>
<circle cx="176.6" cy="134.5" r=".38" fill="#fff" stroke="#000" stroke-width=".21"/>
<circle cx="175.3" cy="109.7" r=".68" fill="#008000" stroke="#008000" stroke-width=".21"/>
<circle cx="175.3" cy="109.7" r=".38" fill="#fff" stroke="#000" stroke-width=".21"/>
<circle cx="178.8" cy="113.8" r=".76" fill="#008000" stroke="#008000" stroke-width=".21"/>
<circle cx="178.8" cy="113.8" r=".47" fill="#fff" stroke="#000" stroke-width=".21"/>
<circle cx="186.7" cy="127.5" r=".68" fill="#008000" stroke="#008000" stroke-width=".21"/>
<circle cx="186.7" cy="127.5" r=".38" fill="#fff" stroke="#000" stroke-width=".21"/>
<circle cx="182.8" cy="141.2" r=".68" fill="#008000" stroke="#008000" stroke-width=".21"/>
<circle cx="182.8" cy="141.2" r=".38" fill="#fff" stroke="#000" stroke-width=".21"/>
<circle cx="175.7" cy="164.7" r=".76" fill="#008000" stroke="#008000" stroke-width=".21"/>
<circle cx="175.7" cy="164.7" r=".47" fill="#fff" stroke="#000" stroke-width=".21"/>
<circle cx="123.3" cy="82.1" r=".68" fill="#008000" stroke="#008000" stroke-width=".21"/>
<circle cx="123.3" cy="82.1" r=".38" fill="#fff" stroke="#000" stroke-width=".21"/>
<circle cx="131.1" cy="111.4" r=".68" fill="#008000" stroke="#008000" stroke-width=".21"/>
<circle cx="131.1" cy="111.4" r=".38" fill="#fff" stroke="#000" stroke-width=".21"/>
<circle cx="139.6" cy="127.3" r=".68" fill="#008000" stroke="#008000" stroke-width=".21"/>
<circle cx="139.6" cy="127.3" r=".38" fill="#fff" stroke="#000" stroke-width=".21"/>
<circle cx="161.7" cy="124.1" r=".76" fill="#008000" stroke="#008000" stroke-width=".21"/>
<circle cx="161.7" cy="124.1" r=".47" fill="#fff" stroke="#000" stroke-width=".21"/>
<circle cx="161.4" cy="118" r=".76" fill="#008000" stroke="#008000" stroke-width=".21"/>
<circle cx="161.4" cy="118" r=".47" fill="#fff" stroke="#000" stroke-width=".21"/>
<circle cx="165.7" cy="113.8" r=".76" fill="#008000" stroke="#008000" stroke-width=".21"/>
<circle cx="165.7" cy="113.8" r=".47" fill="#fff" stroke="#000" stroke-width=".21"/>
<circle cx="131.9" cy="134.3" r=".68" fill="#008000" stroke="#008000" stroke-width=".21"/>
<circle cx="131.9" cy="134.3" r=".38" fill="#fff" stroke="#000" stroke-width=".21"/>
<circle cx="129.2" cy="115.3" r=".68" fill="#008000" stroke="#008000" stroke-width=".21"/>
<circle cx="129.2" cy="115.3" r=".38" fill="#fff" stroke="#000" stroke-width=".21"/>
<circle cx="126.4" cy="134.2" r=".68" fill="#008000" stroke="#008000" stroke-width=".21"/>
<circle cx="126.4" cy="134.2" r=".38" fill="#fff" stroke="#000" stroke-width=".21"/>
<circle cx="126.4" cy="127.7" r=".68" fill="#008000" stroke="#008000" stroke-width=".21"/>
<circle cx="126.4" cy="127.7" r=".38" fill="#fff" stroke="#000" stroke-width=".21"/>
<circle cx="137.4" cy="134.5" r=".68" fill="#008000" stroke="#008000" stroke-width=".21"/>
<circle cx="137.4" cy="134.5" r=".38" fill="#fff" stroke="#000" stroke-width=".21"/>
<circle cx="137.5" cy="128" r=".68" fill="#008000" stroke="#008000" stroke-width=".21"/>
<circle cx="137.5" cy="128" r=".38" fill="#fff" stroke="#000" stroke-width=".21"/>
<circle cx="135" cy="120.3" r=".68" fill="#008000" stroke="#008000" stroke-width=".21"/>
<circle cx="135" cy="120.3" r=".38" fill="#fff" stroke="#000" stroke-width=".21"/>
<circle cx="139.3" cy="116.1" r=".68" fill="#008000" stroke="#008000" stroke-width=".21"/>
<circle cx="139.3" cy="116.1" r=".38" fill="#fff" stroke="#000" stroke-width=".21"/>
<circle cx="137.2" cy="113.5" r=".68" fill="#008000" stroke="#008000" stroke-width=".21"/>
<circle cx="137.2" cy="113.5" r=".38" fill="#fff" stroke="#000" stroke-width=".21"/>
<circle cx="131" cy="88.3" r=".68" fill="#008000" stroke="#008000" stroke-width=".21"/>
<circle cx="131" cy="88.3" r=".38" fill="#fff" stroke="#000" stroke-width=".21"/>
<circle cx="129.8" cy="82.2" r=".68" fill="#008000" stroke="#008000" stroke-width=".21"/>
<circle cx="129.8" cy="82.2" r=".38" fill="#fff" stroke="#000" stroke-width=".21"/>
<circle cx="123.4" cy="39.5" r=".76" fill="#008000" stroke="#008000" stroke-width=".21"/>
<circle cx="123.4" cy="39.5" r=".47" fill="#fff" stroke="#000" stroke-width=".21"/>
<circle cx="129.7" cy="60.7" r=".68" fill="#008000" stroke="#008000" stroke-width=".21"/>
<circle cx="129.7" cy="60.7" r=".38" fill="#fff" stroke="#000" stroke-width=".21"/>
<circle cx="133.6" cy="62.8" r=".68" fill="#008000" stroke="#008000" stroke-width=".21"/>
<circle cx="133.6" cy="62.8" r=".38" fill="#fff" stroke="#000" stroke-width=".21"/>
<circle cx="133.6" cy="67.6" r=".68" fill="#008000" stroke="#008000" stroke-width=".21"/>
<circle cx="133.6" cy="67.6" r=".38" fill="#fff" stroke="#000" stroke-width=".21"/>
<circle cx="190.5" cy="101.4" r=".68" fill="#008000" stroke="#008000" stroke-width=".21"/>
<circle cx="190.5" cy="101.4" r=".38" fill="#fff" stroke="#000" stroke-width=".21"/>
<circle cx="146.7" cy="95.3" r=".68" fill="#008000" stroke="#008000" stroke-width=".21"/>
<circle cx="146.7" cy="95.3" r=".38" fill="#fff" stroke="#000" stroke-width=".21"/>
<circle cx="170.9" cy="61" r=".68" fill="#008000" stroke="#008000" stroke-width=".21"/>
<circle cx="170.9" cy="61" r=".38" fill="#fff" stroke="#000" stroke-width=".21"/>
<circle cx="171.5" cy="64.7" r=".68" fill="#008000" stroke="#008000" stroke-width=".21"/>
<circle cx="171.5" cy="64.7" r=".38" fill="#fff" stroke="#000" stroke-width=".21"/>
<circle cx="194.3" cy="64.7" r=".68" fill="#008000" stroke="#008000" stroke-width=".21"/>
<circle cx="194.3" cy="64.7" r=".38" fill="#fff" stroke="#000" stroke-width=".21"/>
<circle cx="199.2" cy="69.6" r=".68" fill="#008000" stroke="#008000" stroke-width=".21"/>
<circle cx="199.2" cy="69.6" r=".38" fill="#fff" stroke="#000" stroke-width=".21"/>
<circle cx="192.8" cy="88.4" r=".68" fill="#008000" stroke="#008000" stroke-width=".21"/>
<circle cx="192.8" cy="88.4" r=".38" fill="#fff" stroke="#000" stroke-width=".21"/>
<circle cx="165.1" cy="85.3" r=".68" fill="#008000" stroke="#008000" stroke-width=".21"/>
<circle cx="165.1" cy="85.3" r=".38" fill="#fff" stroke="#000" stroke-width=".21"/>
<circle cx="161.3" cy="85.5" r=".68" fill="#008000" stroke="#008000" stroke-width=".21"/>
<circle cx="161.3" cy="85.5" r=".38" fill="#fff" stroke="#000" stroke-width=".21"/>
<circle cx="156.8" cy="80.9" r=".68" fill="#008000" stroke="#008000" stroke-width=".21"/>
<circle cx="156.8" cy="80.9" r=".38" fill="#fff" stroke="#000" stroke-width=".21"/>
<circle cx="149.5" cy="80.9" r=".68" fill="#008000" stroke="#008000" stroke-width=".21"/>
<circle cx="149.5" cy="80.9" r=".38" fill="#fff" stroke="#000" stroke-width=".21"/>
<circle cx="136.5" cy="83.8" r=".68" fill="#008000" stroke="#008000" stroke-width=".21"/>
<circle cx="136.5" cy="83.8" r=".38" fill="#fff" stroke="#000" stroke-width=".21"/>
<circle cx="133.6" cy="83.9" r=".68" fill="#008000" stroke="#008000" stroke-width=".21"/>
<circle cx="133.6" cy="83.9" r=".38" fill="#fff" stroke="#000" stroke-width=".21"/>
<circle cx="133.6" cy="77.6" r=".68" fill="#008000" stroke="#008000" stroke-width=".21"/>
<circle cx="133.6" cy="77.6" r=".38" fill="#fff" stroke="#000" stroke-width=".21"/>
<circle cx="129.8" cy="77.7" r=".68" fill="#008000" stroke="#008000" stroke-width=".21"/>
<circle cx="129.8" cy="77.7" r=".38" fill="#fff" stroke="#000" stroke-width=".21"/>
<circle cx="124.6" cy="77.7" r=".68" fill="#008000" stroke="#008000" stroke-width=".21"/>
<circle cx="124.6" cy="77.7" r=".38" fill="#fff" stroke="#000" stroke-width=".21"/>
<circle cx="117.8" cy="71.7" r=".68" fill="#008000" stroke="#008000" stroke-width=".21"/>
<circle cx="117.8" cy="71.7" r=".38" fill="#fff" stroke="#000" stroke-width=".21"/>
<circle cx="154.7" cy="134.3" r=".68" fill="#008000" stroke="#008000" stroke-width=".21"/>
<circle cx="154.7" cy="134.3" r=".38" fill="#fff" stroke="#000" stroke-width=".21"/>
<circle cx="169.5" cy="107.5" r=".68" fill="#008000" stroke="#008000" stroke-width=".21"/>
<circle cx="169.5" cy="107.5" r=".38" fill="#fff" stroke="#000" stroke-width=".21"/>
<circle cx="106" cy="120.7" r=".68" fill="#008000" stroke="#008000" stroke-width=".21"/>
<circle cx="106" cy="120.7" r=".38" fill="#fff" stroke="#000" stroke-width=".21"/>
<circle cx="130.3" cy="125.9" r=".68" fill="#008000" stroke="#008000" stroke-width=".21"/>
<circle cx="130.3" cy="125.9" r=".38" fill="#fff" stroke="#000" stroke-width=".21"/>
<circle cx="133.8" cy="126" r=".68" fill="#008000" stroke="#008000" stroke-width=".21"/>
<circle cx="133.8" cy="126" r=".38" fill="#fff" stroke="#000" stroke-width=".21"/>
<circle cx="144.6" cy="126" r=".68" fill="#008000" stroke="#008000" stroke-width=".21"/>
<circle cx="144.6" cy="126" r=".38" fill="#fff" stroke="#000" stroke-width=".21"/>
<circle cx="147.5" cy="125.9" r=".68" fill="#008000" stroke="#008000" stroke-width=".21"/>
<circle cx="147.5" cy="125.9" r=".38" fill="#fff" stroke="#000" stroke-width=".21"/>
<circle cx="165.8" cy="134.4" r=".68" fill="#008000" stroke="#008000" stroke-width=".21"/>
<circle cx="165.8" cy="134.4" r=".38" fill="#fff" stroke="#000" stroke-width=".21"/>
<circle cx="172.3" cy="108.6" r=".68" fill="#008000" stroke="#008000" stroke-width=".21"/>
<circle cx="172.3" cy="108.6" r=".38" fill="#fff" stroke="#000" stroke-width=".21"/>
<circle cx="154" cy="113.6" r=".76" fill="#008000" stroke="#008000" stroke-width=".21"/>
<circle cx="154" cy="113.6" r=".44" fill="#fff" stroke="#000" stroke-width=".21"/>
<circle cx="147.5" cy="113.6" r=".68" fill="#008000" stroke="#008000" stroke-width=".21"/>
<circle cx="147.5" cy="113.6" r=".38" fill="#fff" stroke="#000" stroke-width=".21"/>
<circle cx="144.7" cy="113.7" r=".68" fill="#008000" stroke="#008000" stroke-width=".21"/>
<circle cx="144.7" cy="113.7" r=".38" fill="#fff" stroke="#000" stroke-width=".21"/>
<circle cx="133.5" cy="117.7" r=".68" fill="#008000" stroke="#008000" stroke-width=".21"/>
<circle cx="133.5" cy="117.7" r=".38" fill="#fff" stroke="#000" stroke-width=".21"/>
<circle cx="128.5" cy="117.7" r=".68" fill="#008000" stroke="#008000" stroke-width=".21"/>
<circle cx="128.5" cy="117.7" r=".38" fill="#fff" stroke="#000" stroke-width=".21"/>
<circle cx="115.5" cy="105.4" r=".76" fill="#008000" stroke="#008000" stroke-width=".21"/>
<circle cx="115.5" cy="105.4" r=".44" fill="#fff" stroke="#000" stroke-width=".21"/>
<circle cx="119.1" cy="100.4" r=".68" fill="#008000" stroke="#008000" stroke-width=".21"/>
<circle cx="119.1" cy="100.4" r=".38" fill="#fff" stroke="#000" stroke-width=".21"/>
<circle cx="126.8" cy="67.7" r=".68" fill="#008000" stroke="#008000" stroke-width=".21"/>
<circle cx="126.8" cy="67.7" r=".38" fill="#fff" stroke="#000" stroke-width=".21"/>
<circle cx="124.6" cy="70.6" r=".68" fill="#008000" stroke="#008000" stroke-width=".21"/>
<circle cx="124.6" cy="70.6" r=".38" fill="#fff" stroke="#000" stroke-width=".21"/>
<circle cx="116" cy="69" r=".68" fill="#008000" stroke="#008000" stroke-width=".21"/>
<circle cx="116" cy="69" r=".38" fill="#fff" stroke="#000" stroke-width=".21"/>
<circle cx="160.2" cy="134.5" r=".68" fill="#008000" stroke="#008000" stroke-width=".21"/>
<circle cx="160.2" cy="134.5" r=".38" fill="#fff" stroke="#000" stroke-width=".21"/>
<circle cx="160.2" cy="128" r=".68" fill="#008000" stroke="#008000" stroke-width=".21"/>
<circle cx="160.2" cy="128" r=".38" fill="#fff" stroke="#000" stroke-width=".21"/>
<circle cx="110.1" cy="117.8" r=".68" fill="#008000" stroke="#008000" stroke-width=".21"/>
<circle cx="110.1" cy="117.8" r=".38" fill="#fff" stroke="#000" stroke-width=".21"/>
<circle cx="130.2" cy="121.9" r=".68" fill="#008000" stroke="#008000" stroke-width=".21"/>
<circle cx="130.2" cy="121.9" r=".38" fill="#fff" stroke="#000" stroke-width=".21"/>
<circle cx="134" cy="122" r=".68" fill="#008000" stroke="#008000" stroke-width=".21"/>
<circle cx="134" cy="122" r=".38" fill="#fff" stroke="#000" stroke-width=".21"/>
<circle cx="144.7" cy="121.9" r=".68" fill="#008000" stroke="#008000" stroke-width=".21"/>
<circle cx="144.7" cy="121.9" r=".38" fill="#fff" stroke="#000" stroke-width=".21"/>
<circle cx="147.5" cy="122" r=".68" fill="#008000" stroke="#008000" stroke-width=".21"/>
<circle cx="147.5" cy="122" r=".38" fill="#fff" stroke="#000" stroke-width=".21"/>
<circle cx="151.2" cy="124.2" r=".76" fill="#008000" stroke="#008000" stroke-width=".21"/>
<circle cx="151.2" cy="124.2" r=".44" fill="#fff" stroke="#000" stroke-width=".21"/>
<circle cx="149" cy="134.3" r=".68" fill="#008000" stroke="#008000" stroke-width=".21"/>
<circle cx="149" cy="134.3" r=".38" fill="#fff" stroke="#000" stroke-width=".21"/>
<circle cx="149" cy="128" r=".68" fill="#008000" stroke="#008000" stroke-width=".21"/>
<circle cx="149" cy="128" r=".38" fill="#fff" stroke="#000" stroke-width=".21"/>
<circle cx="108.3" cy="119.3" r=".68" fill="#008000" stroke="#008000" stroke-width=".21"/>
<circle cx="108.3" cy="119.3" r=".38" fill="#fff" stroke="#000" stroke-width=".21"/>
<circle cx="130.2" cy="124.2" r=".76" fill="#008000" stroke="#008000" stroke-width=".21"/>
<circle cx="130.2" cy="124.2" r=".44" fill="#fff" stroke="#000" stroke-width=".21"/>
<circle cx="134.1" cy="124.1" r=".68" fill="#008000" stroke="#008000" stroke-width=".21"/>
<circle cx="134.1" cy="124.1" r=".38" fill="#fff" stroke="#000" stroke-width=".21"/>
<circle cx="144.5" cy="124" r=".68" fill="#008000" stroke="#008000" stroke-width=".21"/>
<circle cx="144.5" cy="124" r=".38" fill="#fff" stroke="#000" stroke-width=".21"/>
<circle cx="192" cy="103.5" r=".68" fill="#008000" stroke="#008000" stroke-width=".21"/>
<circle cx="192" cy="103.5" r=".38" fill="#fff" stroke="#000" stroke-width=".21"/>
<circle cx="159.9" cy="65.6" r=".68" fill="#008000" stroke="#008000" stroke-width=".21"/>
<circle cx="159.9" cy="65.6" r=".38" fill="#fff" stroke="#000" stroke-width=".21"/>
<circle cx="165.1" cy="88.2" r=".68" fill="#008000" stroke="#008000" stroke-width=".21"/>
<circle cx="165.1" cy="88.2" r=".38" fill="#fff" stroke="#000" stroke-width=".21"/>
<circle cx="169.3" cy="94.9" r=".76" fill="#008000" stroke="#008000" stroke-width=".21"/>
<circle cx="169.3" cy="94.9" r=".47" fill="#fff" stroke="#000" stroke-width=".21"/>
<circle cx="136.8" cy="107.9" r=".68" fill="#008000" stroke="#008000" stroke-width=".21"/>
<circle cx="136.8" cy="107.9" r=".38" fill="#fff" stroke="#000" stroke-width=".21"/>
<circle cx="120.8" cy="112.9" r=".68" fill="#008000" stroke="#008000" stroke-width=".21"/>
<circle cx="120.8" cy="112.9" r=".38" fill="#fff" stroke="#000" stroke-width=".21"/>
<circle cx="182.4" cy="134.3" r=".68" fill="#008000" stroke="#008000" stroke-width=".21"/>
<circle cx="182.4" cy="134.3" r=".38" fill="#fff" stroke="#000" stroke-width=".21"/>
<circle cx="182.3" cy="127.7" r=".68" fill="#008000" stroke="#008000" stroke-width=".21"/>
<circle cx="182.3" cy="127.7" r=".38" fill="#fff" stroke="#000" stroke-width=".21"/>
<circle cx="102.6" cy="91.5" r=".68" fill="#008000" stroke="#008000" stroke-width=".21"/>
<circle cx="102.6" cy="91.5" r=".38" fill="#fff" stroke="#000" stroke-width=".21"/>
<circle cx="111.5" cy="131.7" r=".68" fill="#008000" stroke="#008000" stroke-width=".21"/>
<circle cx="111.5" cy="131.7" r=".38" fill="#fff" stroke="#000" stroke-width=".21"/>
<circle cx="143.3" cy="134.5" r=".68" fill="#008000" stroke="#008000" stroke-width=".21"/>
<circle cx="143.3" cy="134.5" r=".38" fill="#fff" stroke="#000" stroke-width=".21"/>
<circle cx="143.2" cy="127.4" r=".76" fill="#008000" stroke="#008000" stroke-width=".21"/>
<circle cx="143.2" cy="127.4" r=".44" fill="#fff" stroke="#000" stroke-width=".21"/>
<circle cx="118" cy="114.2" r=".68" fill="#008000" stroke="#008000" stroke-width=".21"/>
<circle cx="118" cy="114.2" r=".38" fill="#fff" stroke="#000" stroke-width=".21"/>
<circle cx="138.9" cy="107.9" r=".68" fill="#008000" stroke="#008000" stroke-width=".21"/>
<circle cx="138.9" cy="107.9" r=".38" fill="#fff" stroke="#000" stroke-width=".21"/>
<circle cx="129.7" cy="108.2" r=".68" fill="#008000" stroke="#008000" stroke-width=".21"/>
<circle cx="129.7" cy="108.2" r=".38" fill="#fff" stroke="#000" stroke-width=".21"/>
<circle cx="100.9" cy="117.1" r=".68" fill="#008000" stroke="#008000" stroke-width=".21"/>
<circle cx="100.9" cy="117.1" r=".38" fill="#fff" stroke="#000" stroke-width=".21"/>
<circle cx="118" cy="110.8" r=".44" fill="#008000" stroke="#008000" stroke-width=".21"/>
<circle cx="118" cy="110.8" r=".15" fill="#fff" stroke="#000" stroke-width=".21"/>
<circle cx="103.4" cy="114.6" r=".68" fill="#008000" stroke="#008000" stroke-width=".21"/>
<circle cx="103.4" cy="114.6" r=".38" fill="#fff" stroke="#000" stroke-width=".21"/>
<circle cx="103" cy="125.5" r=".68" fill="#008000" stroke="#008000" stroke-width=".21"/>
<circle cx="103" cy="125.5" r=".38" fill="#fff" stroke="#000" stroke-width=".21"/>
<path d="M98.1 124.9h1.3v1.4h-1.3z" fill="#008000" stroke="#008000" stroke-width=".21"/>
<circle cx="98.8" cy="125.6" r=".38" fill="#fff" stroke="#000" stroke-width=".21"/>
<circle cx="180" cy="56.2" r=".68" fill="#008000" stroke="#008000" stroke-width=".21"/>
<circle cx="180" cy="56.2" r=".38" fill="#fff" stroke="#000" stroke-width=".21"/>
<circle cx="178.5" cy="53.4" r=".68" fill="#008000" stroke="#008000" stroke-width=".21"/>
<circle cx="178.5" cy="53.4" r=".38" fill="#fff" stroke="#000" stroke-width=".21"/>
<circle cx="159.9" cy="61.4" r=".76" fill="#008000" stroke="#008000" stroke-width=".21"/>
<circle cx="159.9" cy="61.4" r=".47" fill="#fff" stroke="#000" stroke-width=".21"/>
<circle cx="158.1" cy="70.3" r=".76" fill="#008000" stroke="#008000" stroke-width=".21"/>
<circle cx="158.1" cy="70.3" r=".47" fill="#fff" stroke="#000" stroke-width=".21"/>
<circle cx="160.8" cy="106.4" r=".76" fill="#008000" stroke="#008000" stroke-width=".21"/>
<circle cx="160.8" cy="106.4" r=".47" fill="#fff" stroke="#000" stroke-width=".21"/>
<circle cx="157.6" cy="43.1" r=".76" fill="#008000" stroke="#008000" stroke-width=".21"/>
<circle cx="157.6" cy="43.1" r=".44" fill="#fff" stroke="#000" stroke-width=".21"/>
<circle cx="177.5" cy="109.3" r=".76" fill="#008000" stroke="#008000" stroke-width=".21"/>
<circle cx="177.5" cy="109.3" r=".44" fill="#fff" stroke="#000" stroke-width=".21"/>
<circle cx="153.4" cy="83" r=".68" fill="#008000" stroke="#008000" stroke-width=".21"/>
<circle cx="153.4" cy="83" r=".38" fill="#fff" stroke="#000" stroke-width=".21"/>
<circle cx="167.5" cy="85.1" r=".68" fill="#008000" stroke="#008000" stroke-width=".21"/>
<circle cx="167.5" cy="85.1" r=".38" fill="#fff" stroke="#000" stroke-width=".21"/>
<circle cx="196.3" cy="88.4" r=".68" fill="#008000" stroke="#008000" stroke-width=".21"/>
<circle cx="196.3" cy="88.4" r=".38" fill="#fff" stroke="#000" stroke-width=".21"/>
<circle cx="207" cy="96.4" r=".68" fill="#008000" stroke="#008000" stroke-width=".21"/>
<circle cx="207" cy="96.4" r=".38" fill="#fff" stroke="#000" stroke-width=".21"/>
<circle cx="186.6" cy="149.9" r=".68" fill="#008000" stroke="#008000" stroke-width=".21"/>
<circle cx="186.6" cy="149.9" r=".38" fill="#fff" stroke="#000" stroke-width=".21"/>
<circle cx="130.9" cy="93.9" r=".68" fill="#008000" stroke="#008000" stroke-width=".21"/>
<circle cx="130.9" cy="93.9" r=".38" fill="#fff" stroke="#000" stroke-width=".21"/>
<circle cx="153.1" cy="93.7" r=".68" fill="#008000" stroke="#008000" stroke-width=".21"/>
<circle cx="153.1" cy="93.7" r=".38" fill="#fff" stroke="#000" stroke-width=".21"/>
<circle cx="153.1" cy="88.5" r=".68" fill="#008000" stroke="#008000" stroke-width=".21"/>
<circle cx="153.1" cy="88.5" r=".38" fill="#fff" stroke="#000" stroke-width=".21"/>
<circle cx="142.5" cy="82.4" r=".68" fill="#008000" stroke="#008000" stroke-width=".21"/>
<circle cx="142.5" cy="82.4" r=".38" fill="#fff" stroke="#000" stroke-width=".21"/>
<circle cx="159.4" cy="58.9" r=".68" fill="#008000" stroke="#008000" stroke-width=".21"/>
<circle cx="159.4" cy="58.9" r=".38" fill="#fff" stroke="#000" stroke-width=".21"/>
<circle cx="212.2" cy="129.4" r=".68" fill="#008000" stroke="#008000" stroke-width=".21"/>
<circle cx="212.2" cy="129.4" r=".38" fill="#fff" stroke="#000" stroke-width=".21"/>
<circle cx="185.4" cy="146.9" r=".68" fill="#008000" stroke="#008000" stroke-width=".21"/>
<circle cx="185.4" cy="146.9" r=".38" fill="#fff" stroke="#000" stroke-width=".21"/>
<circle cx="156.6" cy="76.8" r=".68" fill="#008000" stroke="#008000" stroke-width=".21"/>
<circle cx="156.6" cy="76.8" r=".38" fill="#fff" stroke="#000" stroke-width=".21"/>
<circle cx="100.1" cy="142.7" r=".68" fill="#008000" stroke="#008000" stroke-width=".21"/>
<circle cx="100.1" cy="142.7" r=".38" fill="#fff" stroke="#000" stroke-width=".21"/>
<circle cx="110.6" cy="136.5" r=".68" fill="#008000" stroke="#008000" stroke-width=".21"/>
<circle cx="110.6" cy="136.5" r=".38" fill="#fff" stroke="#000" stroke-width=".21"/>
<circle cx="149.4" cy="76" r=".68" fill="#008000" stroke="#008000" stroke-width=".21"/>
<circle cx="149.4" cy="76" r=".38" fill="#fff" stroke="#000" stroke-width=".21"/>
<circle cx="143.3" cy="73.9" r=".68" fill="#008000" stroke="#008000" stroke-width=".21"/>
<circle cx="143.3" cy="73.9" r=".38" fill="#fff" stroke="#000" stroke-width=".21"/>
<circle cx="143.4" cy="65.6" r=".68" fill="#008000" stroke="#008000" stroke-width=".21"/>
<circle cx="143.4" cy="65.6" r=".38" fill="#fff" stroke="#000" stroke-width=".21"/>
<circle cx="137.6" cy="65.6" r=".68" fill="#008000" stroke="#008000" stroke-width=".21"/>
<circle cx="137.6" cy="65.6" r=".38" fill="#fff" stroke="#000" stroke-width=".21"/>
<circle cx="129.7" cy="68.2" r=".68" fill="#008000" stroke="#008000" stroke-width=".21"/>
<circle cx="129.7" cy="68.2" r=".38" fill="#fff" stroke="#000" stroke-width=".21"/>
<circle cx="124.6" cy="74.9" r=".68" fill="#008000" stroke="#008000" stroke-width=".21"/>
<circle cx="124.6" cy="74.9" r=".38" fill="#fff" stroke="#000" stroke-width=".21"/>
<circle cx="182.6" cy="70.4" r=".68" fill="#008000" stroke="#008000" stroke-width=".21"/>
<circle cx="182.6" cy="70.4" r=".38" fill="#fff" stroke="#000" stroke-width=".21"/>
<circle cx="182.5" cy="76.6" r=".68" fill="#008000" stroke="#008000" stroke-width=".21"/>
<circle cx="182.5" cy="76.6" r=".38" fill="#fff" stroke="#000" stroke-width=".21"/>
<circle cx="182.5" cy="79.4" r=".68" fill="#008000" stroke="#008000" stroke-width=".21"/>
<circle cx="182.5" cy="79.4" r=".38" fill="#fff" stroke="#000" stroke-width=".21"/>
<circle cx="194.1" cy="136.4" r=".68" fill="#008000" stroke="#008000" stroke-width=".21"/>
<circle cx="194.1" cy="136.4" r=".38" fill="#fff" stroke="#000" stroke-width=".21"/>
<circle cx="195" cy="114.4" r=".68" fill="#008000" stroke="#008000" stroke-width=".21"/>
<circle cx="195" cy="114.4" r=".38" fill="#fff" stroke="#000" stroke-width=".21"/>
<circle cx="175.1" cy="62.7" r=".68" fill="#008000" stroke="#008000" stroke-width=".21"/>
<circle cx="175.1" cy="62.7" r=".38" fill="#fff" stroke="#000" stroke-width=".21"/>
<circle cx="179.5" cy="62.5" r=".68" fill="#008000" stroke="#008000" stroke-width=".21"/>
<circle cx="179.5" cy="62.5" r=".38" fill="#fff" stroke="#000" stroke-width=".21"/>
<circle cx="179.6" cy="70.3" r=".68" fill="#008000" stroke="#008000" stroke-width=".21"/>
<circle cx="179.6" cy="70.3" r=".38" fill="#fff" stroke="#000" stroke-width=".21"/>
<circle cx="179.6" cy="76.6" r=".68" fill="#008000" stroke="#008000" stroke-width=".21"/>
<circle cx="179.6" cy="76.6" r=".38" fill="#fff" stroke="#000" stroke-width=".21"/>
<circle cx="179.6" cy="79.4" r=".68" fill="#008000" stroke="#008000" stroke-width=".21"/>
<circle cx="179.6" cy="79.4" r=".38" fill="#fff" stroke="#000" stroke-width=".21"/>
<circle cx="179.5" cy="93.8" r=".76" fill="#008000" stroke="#008000" stroke-width=".21"/>
<circle cx="179.5" cy="93.8" r=".44" fill="#fff" stroke="#000" stroke-width=".21"/>
<circle cx="189.3" cy="93.9" r=".68" fill="#008000" stroke="#008000" stroke-width=".21"/>
<circle cx="189.3" cy="93.9" r=".38" fill="#fff" stroke="#000" stroke-width=".21"/>
<circle cx="187.7" cy="70.2" r=".68" fill="#008000" stroke="#008000" stroke-width=".21"/>
<circle cx="187.7" cy="70.2" r=".38" fill="#fff" stroke="#000" stroke-width=".21"/>
<circle cx="187.7" cy="76.7" r=".68" fill="#008000" stroke="#008000" stroke-width=".21"/>
<circle cx="187.7" cy="76.7" r=".38" fill="#fff" stroke="#000" stroke-width=".21"/>
<circle cx="187.7" cy="79.4" r=".68" fill="#008000" stroke="#008000" stroke-width=".21"/>
<circle cx="187.7" cy="79.4" r=".38" fill="#fff" stroke="#000" stroke-width=".21"/>
<circle cx="192.3" cy="70.2" r=".68" fill="#008000" stroke="#008000" stroke-width=".21"/>
<circle cx="192.3" cy="70.2" r=".38" fill="#fff" stroke="#000" stroke-width=".21"/>
<circle cx="192.2" cy="76.6" r=".68" fill="#008000" stroke="#008000" stroke-width=".21"/>
<circle cx="192.2" cy="76.6" r=".38" fill="#fff" stroke="#000" stroke-width=".21"/>
<circle cx="192.2" cy="79.4" r=".68" fill="#008000" stroke="#008000" stroke-width=".21"/>
<circle cx="192.2" cy="79.4" r=".38" fill="#fff" stroke="#000" stroke-width=".21"/>
<circle cx="167.5" cy="74.4" r=".68" fill="#008000" stroke="#008000" stroke-width=".21"/>
<circle cx="167.5" cy="74.4" r=".38" fill="#fff" stroke="#000" stroke-width=".21"/>
<circle cx="159.7" cy="75.1" r=".68" fill="#008000" stroke="#008000" stroke-width=".21"/>
<circle cx="159.7" cy="75.1" r=".38" fill="#fff" stroke="#000" stroke-width=".21"/>
<circle cx="130.1" cy="146.5" r=".68" fill="#008000" stroke="#008000" stroke-width=".21"/>
<circle cx="130.1" cy="146.5" r=".38" fill="#fff" stroke="#000" stroke-width=".21"/>
<circle cx="147.9" cy="105.1" r=".68" fill="#008000" stroke="#008000" stroke-width=".21"/>
<circle cx="147.9" cy="105.1" r=".38" fill="#fff" stroke="#000" stroke-width=".21"/>
<circle cx="168.1" cy="104.5" r=".76" fill="#008000" stroke="#008000" stroke-width=".21"/>
<circle cx="168.1" cy="104.5" r=".44" fill="#fff" stroke="#000" stroke-width=".21"/>
<circle cx="187.6" cy="104.2" r=".68" fill="#008000" stroke="#008000" stroke-width=".21"/>
<circle cx="187.6" cy="104.2" r=".38" fill="#fff" stroke="#000" stroke-width=".21"/>
<circle cx="133" cy="88.5" r=".68" fill="#008000" stroke="#008000" stroke-width=".21"/>
<circle cx="133" cy="88.5" r=".38" fill="#fff" stroke="#000" stroke-width=".21"/>
<circle cx="143.8" cy="110.7" r=".68" fill="#008000" stroke="#008000" stroke-width=".21"/>
<circle cx="143.8" cy="110.7" r=".38" fill="#fff" stroke="#000" stroke-width=".21"/>
<circle cx="147.3" cy="109" r=".68" fill="#008000" stroke="#008000" stroke-width=".21"/>
<circle cx="147.3" cy="109" r=".38" fill="#fff" stroke="#000" stroke-width=".21"/>
<circle cx="188.8" cy="144.5" r=".68" fill="#008000" stroke="#008000" stroke-width=".21"/>
<circle cx="188.8" cy="144.5" r=".38" fill="#fff" stroke="#000" stroke-width=".21"/>
<circle cx="192" cy="121.6" r=".68" fill="#008000" stroke="#008000" stroke-width=".21"/>
<circle cx="192" cy="121.6" r=".38" fill="#fff" stroke="#000" stroke-width=".21"/>
<circle cx="127.2" cy="145.4" r=".68" fill="#008000" stroke="#008000" stroke-width=".21"/>
<circle cx="127.2" cy="145.4" r=".38" fill="#fff" stroke="#000" stroke-width=".21"/>
<circle cx="150.5" cy="103.6" r=".68" fill="#008000" stroke="#008000" stroke-width=".21"/>
<circle cx="150.5" cy="103.6" r=".38" fill="#fff" stroke="#000" stroke-width=".21"/>
<circle cx="164.9" cy="102.8" r=".76" fill="#008000" stroke="#008000" stroke-width=".21"/>
<circle cx="164.9" cy="102.8" r=".44" fill="#fff" stroke="#000" stroke-width=".21"/>
<circle cx="138" cy="88.4" r=".68" fill="#008000" stroke="#008000" stroke-width=".21"/>
<circle cx="138" cy="88.4" r=".38" fill="#fff" stroke="#000" stroke-width=".21"/>
<circle cx="153.8" cy="97.9" r=".68" fill="#008000" stroke="#008000" stroke-width=".21"/>
<circle cx="153.8" cy="97.9" r=".38" fill="#fff" stroke="#000" stroke-width=".21"/>
<circle cx="161.2" cy="95.6" r=".76" fill="#008000" stroke="#008000" stroke-width=".21"/>
<circle cx="161.2" cy="95.6" r=".47" fill="#fff" stroke="#000" stroke-width=".21"/>
<circle cx="188.9" cy="102.5" r=".68" fill="#008000" stroke="#008000" stroke-width=".21"/>
<circle cx="188.9" cy="102.5" r=".38" fill="#fff" stroke="#000" stroke-width=".21"/>
<circle cx="168.3" cy="102.4" r=".76" fill="#008000" stroke="#008000" stroke-width=".21"/>
<circle cx="168.3" cy="102.4" r=".44" fill="#fff" stroke="#000" stroke-width=".21"/>
<circle cx="155.3" cy="88.2" r=".68" fill="#008000" stroke="#008000" stroke-width=".21"/>
<circle cx="155.3" cy="88.2" r=".38" fill="#fff" stroke="#000" stroke-width=".21"/>
<circle cx="207.8" cy="128" r=".68" fill="#008000" stroke="#008000" stroke-width=".21"/>
<circle cx="207.8" cy="128" r=".38" fill="#fff" stroke="#000" stroke-width=".21"/>
<circle cx="202.1" cy="155.3" r=".68" fill="#008000" stroke="#008000" stroke-width=".21"/>
<circle cx="202.1" cy="155.3" r=".38" fill="#fff" stroke="#000" stroke-width=".21"/>
<circle cx="196.1" cy="155.2" r=".68" fill="#008000" stroke="#008000" stroke-width=".21"/>
<circle cx="196.1" cy="155.2" r=".38" fill="#fff" stroke="#000" stroke-width=".21"/>
<circle cx="142.9" cy="169.5" r=".68" fill="#008000" stroke="#008000" stroke-width=".21"/>
<circle cx="142.9" cy="169.5" r=".38" fill="#fff" stroke="#000" stroke-width=".21"/>
<circle cx="109.3" cy="168.7" r=".68" fill="#008000" stroke="#008000" stroke-width=".21"/>
<circle cx="109.3" cy="168.7" r=".38" fill="#fff" stroke="#000" stroke-width=".21"/>
<circle cx="104.4" cy="112.6" r=".68" fill="#008000" stroke="#008000" stroke-width=".21"/>
<circle cx="104.4" cy="112.6" r=".38" fill="#fff" stroke="#000" stroke-width=".21"/>
<circle cx="117.9" cy="108.6" r=".68" fill="#008000" stroke="#008000" stroke-width=".21"/>
<circle cx="117.9" cy="108.6" r=".38" fill="#fff" stroke="#000" stroke-width=".21"/>
<circle cx="120.4" cy="106.5" r=".68" fill="#008000" stroke="#008000" stroke-width=".21"/>
<circle cx="120.4" cy="106.5" r=".38" fill="#fff" stroke="#000" stroke-width=".21"/>
<circle cx="131.6" cy="100.3" r=".68" fill="#008000" stroke="#008000" stroke-width=".21"/>
<circle cx="131.6" cy="100.3" r=".38" fill="#fff" stroke="#000" stroke-width=".21"/>
<circle cx="141.4" cy="100.8" r=".76" fill="#008000" stroke="#008000" stroke-width=".21"/>
<circle cx="141.4" cy="100.8" r=".47" fill="#fff" stroke="#000" stroke-width=".21"/>
<circle cx="135.2" cy="88.2" r=".68" fill="#008000" stroke="#008000" stroke-width=".21"/>
<circle cx="135.2" cy="88.2" r=".38" fill="#fff" stroke="#000" stroke-width=".21"/>
<circle cx="132.7" cy="53.6" r=".76" fill="#008000" stroke="#008000" stroke-width=".21"/>
<circle cx="132.7" cy="53.6" r=".47" fill="#fff" stroke="#000" stroke-width=".21"/>
<circle cx="137.6" cy="63.2" r=".68" fill="#008000" stroke="#008000" stroke-width=".21"/>
<circle cx="137.6" cy="63.2" r=".38" fill="#fff" stroke="#000" stroke-width=".21"/>
<circle cx="142.6" cy="63.3" r=".68" fill="#008000" stroke="#008000" stroke-width=".21"/>
<circle cx="142.6" cy="63.3" r=".38" fill="#fff" stroke="#000" stroke-width=".21"/>
<circle cx="142.4" cy="55.1" r=".68" fill="#008000" stroke="#008000" stroke-width=".21"/>
<circle cx="142.4" cy="55.1" r=".38" fill="#fff" stroke="#000" stroke-width=".21"/>
<circle cx="107" cy="141.2" r=".68" fill="#008000" stroke="#008000" stroke-width=".21"/>
<circle cx="107" cy="141.2" r=".38" fill="#fff" stroke="#000" stroke-width=".21"/>
<circle cx="104.2" cy="138.1" r=".68" fill="#008000" stroke="#008000" stroke-width=".21"/>
<circle cx="104.2" cy="138.1" r=".38" fill="#fff" stroke="#000" stroke-width=".21"/>
<circle cx="184.8" cy="101.7" r=".68" fill="#008000" stroke="#008000" stroke-width=".21"/>
<circle cx="184.8" cy="101.7" r=".38" fill="#fff" stroke="#000" stroke-width=".21"/>
<circle cx="118.2" cy="95.8" r=".68" fill="#008000" stroke="#008000" stroke-width=".21"/>
<circle cx="118.2" cy="95.8" r=".38" fill="#fff" stroke="#000" stroke-width=".21"/>
<circle cx="121.8" cy="87.8" r=".76" fill="#008000" stroke="#008000" stroke-width=".21"/>
<circle cx="121.8" cy="87.8" r=".44" fill="#fff" stroke="#000" stroke-width=".21"/>
<circle cx="170.8" cy="69.8" r=".68" fill="#008000" stroke="#008000" stroke-width=".21"/>
<circle cx="170.8" cy="69.8" r=".38" fill="#fff" stroke="#000" stroke-width=".21"/>
<circle cx="171.3" cy="76.5" r=".68" fill="#008000" stroke="#008000" stroke-width=".21"/>
<circle cx="171.3" cy="76.5" r=".38" fill="#fff" stroke="#000" stroke-width=".21"/>
<circle cx="171.3" cy="79.4" r=".68" fill="#008000" stroke="#008000" stroke-width=".21"/>
<circle cx="171.3" cy="79.4" r=".38" fill="#fff" stroke="#000" stroke-width=".21"/>
<circle cx="193.5" cy="101.1" r=".68" fill="#008000" stroke="#008000" stroke-width=".21"/>
<circle cx="193.5" cy="101.1" r=".38" fill="#fff" stroke="#000" stroke-width=".21"/>
<circle cx="171.2" cy="95.8" r=".76" fill="#008000" stroke="#008000" stroke-width=".21"/>
<circle cx="171.2" cy="95.8" r=".44" fill="#fff" stroke="#000" stroke-width=".21"/>
<circle cx="173.8" cy="72.2" r=".68" fill="#008000" stroke="#008000" stroke-width=".21"/>
<circle cx="173.8" cy="72.2" r=".38" fill="#fff" stroke="#000" stroke-width=".21"/>
<circle cx="173.8" cy="76.5" r=".68" fill="#008000" stroke="#008000" stroke-width=".21"/>
<circle cx="173.8" cy="76.5" r=".38" fill="#fff" stroke="#000" stroke-width=".21"/>
<circle cx="173.8" cy="79.4" r=".68" fill="#008000" stroke="#008000" stroke-width=".21"/>
<circle cx="173.8" cy="79.4" r=".38" fill="#fff" stroke="#000" stroke-width=".21"/>
<circle cx="196.2" cy="102.1" r=".68" fill="#008000" stroke="#008000" stroke-width=".21"/>
<circle cx="196.2" cy="102.1" r=".38" fill="#fff" stroke="#000" stroke-width=".21"/>
<circle cx="173.8" cy="94.8" r=".76" fill="#008000" stroke="#008000" stroke-width=".21"/>
<circle cx="173.8" cy="94.8" r=".44" fill="#fff" stroke="#000" stroke-width=".21"/>
<circle cx="176.9" cy="70.4" r=".68" fill="#008000" stroke="#008000" stroke-width=".21"/>
<circle cx="176.9" cy="70.4" r=".38" fill="#fff" stroke="#000" stroke-width=".21"/>
<circle cx="176.9" cy="76.7" r=".68" fill="#008000" stroke="#008000" stroke-width=".21"/>
<circle cx="176.9" cy="76.7" r=".38" fill="#fff" stroke="#000" stroke-width=".21"/>
<circle cx="176.9" cy="79.4" r=".68" fill="#008000" stroke="#008000" stroke-width=".21"/>
<circle cx="176.9" cy="79.4" r=".38" fill="#fff" stroke="#000" stroke-width=".21"/>
<circle cx="198.1" cy="102.1" r=".68" fill="#008000" stroke="#008000" stroke-width=".21"/>
<circle cx="198.1" cy="102.1" r=".38" fill="#fff" stroke="#000" stroke-width=".21"/>
<circle cx="177.5" cy="94.1" r=".76" fill="#008000" stroke="#008000" stroke-width=".21"/>
<circle cx="177.5" cy="94.1" r=".44" fill="#fff" stroke="#000" stroke-width=".21"/>
<circle cx="205.6" cy="120.2" r=".68" fill="#008000" stroke="#008000" stroke-width=".21"/>
<circle cx="205.6" cy="120.2" r=".38" fill="#fff" stroke="#000" stroke-width=".21"/>
<circle cx="208.2" cy="122.2" r=".68" fill="#008000" stroke="#008000" stroke-width=".21"/>
<circle cx="208.2" cy="122.2" r=".38" fill="#fff" stroke="#000" stroke-width=".21"/>
<circle cx="104.5" cy="102.5" r=".68" fill="#008000" stroke="#008000" stroke-width=".21"/>
<circle cx="104.5" cy="102.5" r=".38" fill="#fff" stroke="#000" stroke-width=".21"/>
<circle cx="113.9" cy="82.4" r=".68" fill="#008000" stroke="#008000" stroke-width=".21"/>
<circle cx="113.9" cy="82.4" r=".38" fill="#fff" stroke="#000" stroke-width=".21"/>
<circle cx="102.7" cy="139.3" r=".68" fill="#008000" stroke="#008000" stroke-width=".21"/>
<circle cx="102.7" cy="139.3" r=".38" fill="#fff" stroke="#000" stroke-width=".21"/>
<circle cx="149.5" cy="145.7" r=".68" fill="#008000" stroke="#008000" stroke-width=".21"/>
<circle cx="149.5" cy="145.7" r=".38" fill="#fff" stroke="#000" stroke-width=".21"/>
<circle cx="210.5" cy="113.8" r=".68" fill="#008000" stroke="#008000" stroke-width=".21"/>
<circle cx="210.5" cy="113.8" r=".38" fill="#fff" stroke="#000" stroke-width=".21"/>
<circle cx="199.2" cy="164.7" r=".68" fill="#008000" stroke="#008000" stroke-width=".21"/>
<circle cx="199.2" cy="164.7" r=".38" fill="#fff" stroke="#000" stroke-width=".21"/>
<circle cx="194.4" cy="160.4" r=".68" fill="#008000" stroke="#008000" stroke-width=".21"/>
<circle cx="194.4" cy="160.4" r=".38" fill="#fff" stroke="#000" stroke-width=".21"/>
<circle cx="191" cy="87.5" r=".68" fill="#008000" stroke="#008000" stroke-width=".21"/>
<circle cx="191" cy="87.5" r=".38" fill="#fff" stroke="#000" stroke-width=".21"/>
<circle cx="169.7" cy="87.3" r=".68" fill="#008000" stroke="#008000" stroke-width=".21"/>
<circle cx="169.7" cy="87.3" r=".38" fill="#fff" stroke="#000" stroke-width=".21"/>
<circle cx="149.5" cy="79.1" r=".68" fill="#008000" stroke="#008000" stroke-width=".21"/>
<circle cx="149.5" cy="79.1" r=".38" fill="#fff" stroke="#000" stroke-width=".21"/>
<circle cx="199.5" cy="107.4" r=".76" fill="#008000" stroke="#008000" stroke-width=".21"/>
<circle cx="199.5" cy="107.4" r=".47" fill="#fff" stroke="#000" stroke-width=".21"/>
<circle cx="180" cy="107.4" r=".68" fill="#008000" stroke="#008000" stroke-width=".21"/>
<circle cx="180" cy="107.4" r=".38" fill="#fff" stroke="#000" stroke-width=".21"/>
<circle cx="151.5" cy="65.6" r=".68" fill="#008000" stroke="#008000" stroke-width=".21"/>
<circle cx="151.5" cy="65.6" r=".38" fill="#fff" stroke="#000" stroke-width=".21"/>
<circle cx="151.4" cy="83" r=".68" fill="#008000" stroke="#008000" stroke-width=".21"/>
<circle cx="151.4" cy="83" r=".38" fill="#fff" stroke="#000" stroke-width=".21"/>
<circle cx="108.9" cy="88.2" r=".68" fill="#008000" stroke="#008000" stroke-width=".21"/>
<circle cx="108.9" cy="88.2" r=".38" fill="#fff" stroke="#000" stroke-width=".21"/>
<circle cx="108.9" cy="83.9" r=".68" fill="#008000" stroke="#008000" stroke-width=".21"/>
<circle cx="108.9" cy="83.9" r=".38" fill="#fff" stroke="#000" stroke-width=".21"/>
<circle cx="174.9" cy="67.8" r=".68" fill="#008000" stroke="#008000" stroke-width=".21"/>
<circle cx="174.9" cy="67.8" r=".38" fill="#fff" stroke="#000" stroke-width=".21"/>
<circle cx="151.7" cy="58.4" r=".68" fill="#008000" stroke="#008000" stroke-width=".21"/>
<circle cx="151.7" cy="58.4" r=".38" fill="#fff" stroke="#000" stroke-width=".21"/>
<circle cx="151.7" cy="62.2" r=".68" fill="#008000" stroke="#008000" stroke-width=".21"/>
<circle cx="151.7" cy="62.2" r=".38" fill="#fff" stroke="#000" stroke-width=".21"/>
<circle cx="209.6" cy="66.2" r=".68" fill="#008000" stroke="#008000" stroke-width=".21"/>
<circle cx="209.6" cy="66.2" r=".38" fill="#fff" stroke="#000" stroke-width=".21"/>
<circle cx="195.9" cy="43.7" r=".76" fill="#008000" stroke="#008000" stroke-width=".21"/>
<circle cx="195.9" cy="43.7" r=".47" fill="#fff" stroke="#000" stroke-width=".21"/>
<circle cx="161.2" cy="76.3" r=".68" fill="#008000" stroke="#008000" stroke-width=".21"/>
<circle cx="161.2" cy="76.3" r=".38" fill="#fff" stroke="#000" stroke-width=".21"/>
<circle cx="199.4" cy="158.1" r=".68" fill="#008000" stroke="#008000" stroke-width=".21"/>
<circle cx="199.4" cy="158.1" r=".38" fill="#fff" stroke="#000" stroke-width=".21"/>
<circle cx="178.1" cy="164.7" r=".76" fill="#008000" stroke="#008000" stroke-width=".21"/>
<circle cx="178.1" cy="164.7" r=".47" fill="#fff" stroke="#000" stroke-width=".21"/>
<circle cx="189.6" cy="165.3" r=".68" fill="#008000" stroke="#008000" stroke-width=".21"/>
<circle cx="189.6" cy="165.3" r=".38" fill="#fff" stroke="#000" stroke-width=".21"/>
<circle cx="146.1" cy="167.7" r=".68" fill="#008000" stroke="#008000" stroke-width=".21"/>
<circle cx="146.1" cy="167.7" r=".38" fill="#fff" stroke="#000" stroke-width=".21"/>
<circle cx="112.4" cy="167.1" r=".68" fill="#008000" stroke="#008000" stroke-width=".21"/>
<circle cx="112.4" cy="167.1" r=".38" fill="#fff" stroke="#000" stroke-width=".21"/>
<circle cx="112.4" cy="158.6" r=".68" fill="#008000" stroke="#008000" stroke-width=".21"/>
<circle cx="112.4" cy="158.6" r=".38" fill="#fff" stroke="#000" stroke-width=".21"/>
<circle cx="113.7" cy="105.5" r=".68" fill="#008000" stroke="#008000" stroke-width=".21"/>
<circle cx="113.7" cy="105.5" r=".38" fill="#fff" stroke="#000" stroke-width=".21"/>
<circle cx="115.7" cy="100.4" r=".68" fill="#008000" stroke="#008000" stroke-width=".21"/>
<circle cx="115.7" cy="100.4" r=".38" fill="#fff" stroke="#000" stroke-width=".21"/>
<circle cx="111.7" cy="96.7" r=".68" fill="#008000" stroke="#008000" stroke-width=".21"/>
<circle cx="111.7" cy="96.7" r=".38" fill="#fff" stroke="#000" stroke-width=".21"/>
<circle cx="111.9" cy="83.8" r=".68" fill="#008000" stroke="#008000" stroke-width=".21"/>
<circle cx="111.9" cy="83.8" r=".38" fill="#fff" stroke="#000" stroke-width=".21"/>
<circle cx="94.6" cy="37.8" r="3.2" fill="#008000" stroke="#008000" stroke-width=".21"/>
<circle cx="94.6" cy="37.8" r="2.39" fill="#fff" stroke="#000" stroke-width=".21"/>
<circle cx="205" cy="37.8" r="3.2" fill="#008000" stroke="#008000" stroke-width=".21"/>
<circle cx="205" cy="37.8" r="2.39" fill="#fff" stroke="#000" stroke-width=".21"/>
<circle cx="208.8" cy="166.3" r="3.2" fill="#008000" stroke="#008000" stroke-width=".21"/>
<circle cx="208.8" cy="166.3" r="2.39" fill="#fff" stroke="#000" stroke-width=".21"/>
<circle cx="88.9" cy="166.3" r="3.2" fill="#008000" stroke="#008000" stroke-width=".21"/>
<circle cx="88.9" cy="166.3" r="2.39" fill="#fff" stroke="#000" stroke-width=".21"/>
<path d="M198.8 161.8h1.4v1.3h-1.4z" fill="#008000" stroke="#008000" stroke-width=".21"/>
<circle cx="199.5" cy="162.4" r=".38" fill="#fff" stroke="#000" stroke-width=".21"/>
<g fill="#800000" stroke="#800000" stroke-width=".21">
<path d="M80.3 32.5l.3 .1-.2 .5-.3-.1z"/>
<path d="M80.3 32.5h.4l.1 .3-.5 .1-.1-.1z"/>
<circle cx="80.7" cy="32.7" r=".27"/>
<circle cx="81.7" cy="32.7" r=".28"/>
<circle cx="82.7" cy="32.7" r=".28"/>
<circle cx="83.8" cy="32.7" r=".28"/>
<circle cx="84.8" cy="32.7" r=".27"/>
<circle cx="85.8" cy="32.7" r=".27"/>
<circle cx="86.9" cy="32.7" r=".28"/>
<circle cx="87.9" cy="32.7" r=".28"/>
<circle cx="88.9" cy="32.7" r=".28"/>
<circle cx="90" cy="32.7" r=".27"/>
<circle cx="91" cy="32.7" r=".27"/>
<circle cx="92" cy="32.7" r=".28"/>
<circle cx="93.1" cy="32.7" r=".28"/>
<circle cx="94.1" cy="32.7" r=".28"/>
<circle cx="95.1" cy="32.7" r=".27"/>
<circle cx="96.2" cy="32.7" r=".27"/>
<circle cx="97.2" cy="32.7" r=".28"/>
<circle cx="98.2" cy="32.7" r=".28"/>
<circle cx="99.3" cy="32.7" r=".28"/>
<circle cx="100.3" cy="32.7" r=".27"/>
<circle cx="101.3" cy="32.7" r=".27"/>
<circle cx="102.4" cy="32.7" r=".28"/>
<circle cx="103.4" cy="32.7" r=".28"/>
<circle cx="104.4" cy="32.7" r=".28"/>
<circle cx="105.5" cy="32.7" r=".27"/>
<circle cx="106.5" cy="32.7" r=".27"/>
<circle cx="107.5" cy="32.7" r=".28"/>
<circle cx="108.6" cy="32.7" r=".28"/>
<circle cx="109.6" cy="32.7" r=".28"/>
<circle cx="110.6" cy="32.7" r=".27"/>
<circle cx="111.7" cy="32.7" r=".27"/>
<circle cx="112.7" cy="32.7" r=".28"/>
<circle cx="113.7" cy="32.7" r=".28"/>
<circle cx="114.8" cy="32.7" r=".28"/>
<circle cx="115.8" cy="32.7" r=".27"/>
<circle cx="116.8" cy="32.7" r=".27"/>
<circle cx="117.9" cy="32.7" r=".28"/>
<circle cx="118.9" cy="32.7" r=".28"/>
<circle cx="119.9" cy="32.8" r=".28"/>
<circle cx="121" cy="32.8" r=".27"/>
<circle cx="122" cy="32.8" r=".27"/>
<circle cx="123" cy="32.8" r=".28"/>
<circle cx="124.1" cy="32.8" r=".28"/>
<circle cx="125.1" cy="32.8" r=".28"/>
<circle cx="126.1" cy="32.8" r=".27"/>
<circle cx="127.2" cy="32.8" r=".27"/>
<circle cx="128.2" cy="32.8" r=".28"/>
<circle cx="129.2" cy="32.8" r=".28"/>
<circle cx="130.3" cy="32.8" r=".28"/>
<circle cx="131.3" cy="32.8" r=".27"/>
<circle cx="132.3" cy="32.8" r=".27"/>
<circle cx="133.3" cy="32.8" r=".28"/>
<circle cx="134.4" cy="32.8" r=".28"/>
<circle cx="135.4" cy="32.8" r=".28"/>
<circle cx="136.5" cy="32.8" r=".27"/>
<circle cx="137.5" cy="32.8" r=".27"/>
<circle cx="138.5" cy="32.8" r=".28"/>
<circle cx="139.6" cy="32.8" r=".28"/>
<circle cx="140.6" cy="32.8" r=".28"/>
<circle cx="141.6" cy="32.8" r=".27"/>
<circle cx="142.7" cy="32.8" r=".27"/>
<circle cx="143.7" cy="32.8" r=".28"/>
<circle cx="144.7" cy="32.8" r=".28"/>
<circle cx="145.8" cy="32.8" r=".28"/>
<circle cx="146.8" cy="32.8" r=".27"/>
<circle cx="147.8" cy="32.8" r=".27"/>
<circle cx="148.8" cy="32.8" r=".28"/>
<circle cx="149.9" cy="32.8" r=".28"/>
<circle cx="150.9" cy="32.8" r=".28"/>
<circle cx="151.9" cy="32.8" r=".27"/>
<circle cx="153" cy="32.8" r=".27"/>
<circle cx="154" cy="32.8" r=".28"/>
<circle cx="155" cy="32.8" r=".28"/>
<circle cx="156.1" cy="32.8" r=".28"/>
<circle cx="157.1" cy="32.8" r=".27"/>
<circle cx="158.1" cy="32.8" r=".27"/>
<circle cx="159.2" cy="32.8" r=".28"/>
<circle cx="160.2" cy="32.8" r=".28"/>
<circle cx="161.2" cy="32.8" r=".28"/>
<circle cx="162.3" cy="32.8" r=".27"/>
<circle cx="163.3" cy="32.8" r=".27"/>
<circle cx="164.3" cy="32.8" r=".28"/>
<circle cx="165.4" cy="32.8" r=".28"/>
<circle cx="166.4" cy="32.8" r=".28"/>
<circle cx="167.4" cy="32.8" r=".27"/>
<circle cx="168.5" cy="32.8" r=".28"/>
<circle cx="169.5" cy="32.8" r=".28"/>
<circle cx="170.5" cy="32.8" r=".28"/>
<circle cx="171.6" cy="32.8" r=".28"/>
<circle cx="172.6" cy="32.8" r=".27"/>
<circle cx="173.6" cy="32.8" r=".28"/>
<circle cx="174.7" cy="32.8" r=".28"/>
<circle cx="175.7" cy="32.8" r=".28"/>
<circle cx="176.7" cy="32.8" r=".27"/>
<circle cx="177.8" cy="32.8" r=".27"/>
<circle cx="178.8" cy="32.8" r=".28"/>
<circle cx="179.8" cy="32.8" r=".28"/>
<circle cx="180.9" cy="32.9" r=".28"/>
<circle cx="181.9" cy="32.8" r=".27"/>
<circle cx="182.9" cy="32.8" r=".27"/>
<circle cx="184" cy="32.9" r=".28"/>
<circle cx="185" cy="32.9" r=".28"/>
<circle cx="186" cy="32.9" r=".28"/>
<circle cx="187.1" cy="32.8" r=".27"/>
<circle cx="188.1" cy="32.8" r=".27"/>
<circle cx="189.1" cy="32.9" r=".28"/>
<circle cx="190.2" cy="32.9" r=".28"/>
<circle cx="191.2" cy="32.9" r=".28"/>
<circle cx="192.2" cy="32.8" r=".27"/>
<circle cx="193.3" cy="32.8" r=".27"/>
<circle cx="194.3" cy="32.9" r=".28"/>
<circle cx="195.3" cy="32.9" r=".28"/>
<circle cx="196.4" cy="32.9" r=".28"/>
<circle cx="197.4" cy="32.9" r=".27"/>
<circle cx="198.4" cy="32.9" r=".27"/>
<circle cx="199.5" cy="32.9" r=".28"/>
<circle cx="200.5" cy="32.9" r=".28"/>
<circle cx="201.5" cy="32.9" r=".28"/>
<circle cx="202.6" cy="32.9" r=".27"/>
<circle cx="203.6" cy="32.9" r=".27"/>
<circle cx="204.6" cy="32.9" r=".28"/>
<circle cx="205.7" cy="32.9" r=".28"/>
<circle cx="206.7" cy="32.9" r=".28"/>
<circle cx="207.7" cy="32.9" r=".27"/>
<circle cx="208.8" cy="32.9" r=".27"/>
<circle cx="209.8" cy="32.9" r=".28"/>
<circle cx="210.8" cy="32.9" r=".28"/>
<circle cx="211.9" cy="32.9" r=".28"/>
<circle cx="212.9" cy="32.9" r=".27"/>
<circle cx="213.9" cy="32.9" r=".27"/>
<circle cx="214.9" cy="32.9" r=".28"/>
<circle cx="216" cy="32.9" r=".28"/>
<circle cx="216" cy="32.9" r=".27"/>
<circle cx="216" cy="34" r=".27"/>
<circle cx="216" cy="35" r=".28"/>
<circle cx="216" cy="36" r=".28"/>
<circle cx="216" cy="37.1" r=".27"/>
<circle cx="216" cy="38.1" r=".27"/>
<circle cx="216" cy="39.1" r=".28"/>
<circle cx="216" cy="40.2" r=".28"/>
<circle cx="216" cy="41.2" r=".27"/>
<circle cx="216" cy="42.2" r=".27"/>
<circle cx="216" cy="43.2" r=".28"/>
<circle cx="216" cy="44.3" r=".28"/>
<circle cx="216" cy="45.3" r=".27"/>
<circle cx="216" cy="46.3" r=".27"/>
<circle cx="216" cy="47.4" r=".28"/>
<circle cx="216" cy="48.4" r=".28"/>
<circle cx="216" cy="49.4" r=".27"/>
<circle cx="216" cy="50.5" r=".27"/>
<circle cx="216" cy="51.5" r=".28"/>
<circle cx="216" cy="52.5" r=".28"/>
<circle cx="216" cy="53.6" r=".27"/>
<circle cx="216" cy="54.6" r=".27"/>
<circle cx="216" cy="55.6" r=".28"/>
<circle cx="216" cy="56.7" r=".28"/>
<circle cx="216" cy="57.7" r=".27"/>
<circle cx="216" cy="58.7" r=".27"/>
<circle cx="216" cy="59.8" r=".28"/>
<circle cx="216" cy="60.8" r=".28"/>
<circle cx="216" cy="61.8" r=".27"/>
<circle cx="216" cy="62.9" r=".27"/>
<circle cx="216" cy="63.9" r=".28"/>
<circle cx="216" cy="64.9" r=".28"/>
<circle cx="216" cy="65.9" r=".27"/>
<circle cx="216" cy="67" r=".27"/>
<circle cx="216" cy="68" r=".28"/>
<circle cx="216" cy="69" r=".28"/>
<circle cx="216" cy="70.1" r=".27"/>
<circle cx="216" cy="71.1" r=".27"/>
<circle cx="216" cy="72.1" r=".28"/>
<circle cx="216" cy="73.2" r=".28"/>
<circle cx="216" cy="74.2" r=".27"/>
<circle cx="216" cy="75.2" r=".27"/>
<circle cx="216" cy="76.3" r=".28"/>
<circle cx="216" cy="77.3" r=".28"/>
<circle cx="216" cy="78.3" r=".27"/>
<circle cx="216" cy="79.4" r=".27"/>
<circle cx="216" cy="80.4" r=".28"/>
<circle cx="216" cy="81.4" r=".28"/>
<circle cx="216" cy="82.5" r=".27"/>
<circle cx="216" cy="83.5" r=".27"/>
<circle cx="216" cy="84.5" r=".28"/>
<circle cx="216" cy="85.6" r=".28"/>
<circle cx="216" cy="86.6" r=".27"/>
<circle cx="216" cy="87.6" r=".27"/>
<circle cx="216" cy="88.6" r=".28"/>
<circle cx="216" cy="89.7" r=".28"/>
<circle cx="216" cy="90.7" r=".27"/>
<circle cx="216" cy="91.7" r=".27"/>
<circle cx="216" cy="92.8" r=".28"/>
<circle cx="216" cy="93.8" r=".28"/>
<circle cx="216" cy="94.8" r=".27"/>
<circle cx="216" cy="95.9" r=".27"/>
<circle cx="216" cy="96.9" r=".28"/>
<circle cx="216" cy="97.9" r=".28"/>
<circle cx="216" cy="99" r=".27"/>
<circle cx="216" cy="100" r=".27"/>
<circle cx="216" cy="101" r=".28"/>
<circle cx="216" cy="102.1" r=".28"/>
<circle cx="216" cy="103.1" r=".27"/>
<circle cx="216" cy="104.1" r=".27"/>
<circle cx="216" cy="105.2" r=".28"/>
<circle cx="216" cy="106.2" r=".28"/>
<circle cx="216" cy="107.2" r=".27"/>
<circle cx="216" cy="108.3" r=".27"/>
<circle cx="216" cy="109.3" r=".28"/>
<circle cx="216" cy="110.3" r=".28"/>
<circle cx="216" cy="111.3" r=".27"/>
<circle cx="216" cy="112.4" r=".27"/>
<circle cx="216" cy="113.4" r=".28"/>
<circle cx="216" cy="114.4" r=".28"/>
<circle cx="216" cy="115.5" r=".27"/>
<circle cx="216" cy="116.5" r=".27"/>
<circle cx="216" cy="117.5" r=".28"/>
<circle cx="216" cy="118.6" r=".28"/>
<circle cx="216" cy="119.6" r=".27"/>
<circle cx="216" cy="120.6" r=".27"/>
<circle cx="216" cy="121.7" r=".28"/>
<circle cx="216" cy="122.7" r=".28"/>
<circle cx="216" cy="123.7" r=".27"/>
<circle cx="216" cy="124.8" r=".27"/>
<circle cx="216" cy="125.8" r=".28"/>
<circle cx="216" cy="126.8" r=".28"/>
<circle cx="216" cy="127.9" r=".27"/>
<circle cx="216" cy="128.9" r=".27"/>
<circle cx="216" cy="129.9" r=".28"/>
<circle cx="216" cy="131" r=".28"/>
<circle cx="216" cy="132" r=".27"/>
<circle cx="216" cy="133" r=".27"/>
<circle cx="216" cy="134" r=".28"/>
<circle cx="216" cy="135.1" r=".28"/>
<circle cx="216" cy="136.1" r=".27"/>
<circle cx="216" cy="137.1" r=".27"/>
<circle cx="216" cy="138.2" r=".28"/>
<circle cx="216" cy="139.2" r=".28"/>
<circle cx="216" cy="140.2" r=".27"/>
<circle cx="216" cy="141.3" r=".27"/>
<circle cx="216" cy="142.3" r=".28"/>
<circle cx="216" cy="143.3" r=".28"/>
<circle cx="216" cy="144.4" r=".27"/>
<circle cx="216" cy="145.4" r=".27"/>
<circle cx="216" cy="146.4" r=".28"/>
<circle cx="216" cy="147.5" r=".28"/>
<circle cx="216" cy="148.5" r=".27"/>
<circle cx="216" cy="149.5" r=".27"/>
<circle cx="216" cy="150.6" r=".28"/>
<circle cx="216" cy="151.6" r=".28"/>
<circle cx="216" cy="152.6" r=".27"/>
<circle cx="216" cy="153.7" r=".27"/>
<circle cx="216" cy="154.7" r=".28"/>
<circle cx="216" cy="155.7" r=".28"/>
<circle cx="216" cy="156.7" r=".27"/>
<circle cx="216" cy="157.8" r=".27"/>
<circle cx="216" cy="158.8" r=".28"/>
<circle cx="216" cy="159.9" r=".28"/>
<circle cx="216" cy="160.9" r=".27"/>
<circle cx="216" cy="161.9" r=".27"/>
<circle cx="216" cy="162.9" r=".28"/>
<circle cx="216" cy="164" r=".28"/>
<circle cx="216" cy="165" r=".27"/>
<circle cx="216" cy="166" r=".27"/>
<circle cx="216" cy="167.1" r=".28"/>
<circle cx="216" cy="168.1" r=".28"/>
<circle cx="216" cy="169.1" r=".27"/>
<circle cx="216" cy="170.2" r=".27"/>
<circle cx="216" cy="171.2" r=".28"/>
<circle cx="214.9" cy="171.2" r=".28"/>
<circle cx="213.9" cy="171.2" r=".28"/>
<circle cx="212.9" cy="171.2" r=".27"/>
<circle cx="211.8" cy="171.2" r=".27"/>
<circle cx="210.8" cy="171.2" r=".28"/>
<circle cx="209.8" cy="171.2" r=".28"/>
<circle cx="208.7" cy="171.2" r=".28"/>
<circle cx="207.7" cy="171.2" r=".28"/>
<circle cx="206.7" cy="171.2" r=".27"/>
<circle cx="205.6" cy="171.2" r=".27"/>
<circle cx="204.6" cy="171.2" r=".27"/>
<circle cx="203.6" cy="171.2" r=".28"/>
<circle cx="202.5" cy="171.2" r=".28"/>
<circle cx="201.5" cy="171.2" r=".28"/>
<circle cx="200.5" cy="171.2" r=".28"/>
<circle cx="199.4" cy="171.2" r=".27"/>
<circle cx="198.4" cy="171.2" r=".27"/>
<circle cx="197.4" cy="171.2" r=".28"/>
<circle cx="196.3" cy="171.2" r=".28"/>
<circle cx="195.3" cy="171.2" r=".28"/>
<circle cx="194.3" cy="171.2" r=".28"/>
<circle cx="193.2" cy="171.2" r=".28"/>
<circle cx="192.2" cy="171.2" r=".27"/>
<circle cx="191.2" cy="171.2" r=".27"/>
<circle cx="190.1" cy="171.2" r=".28"/>
<circle cx="189.1" cy="171.2" r=".28"/>
<circle cx="188.1" cy="171.2" r=".28"/>
<circle cx="187" cy="171.2" r=".28"/>
<circle cx="186" cy="171.2" r=".27"/>
<circle cx="185" cy="171.2" r=".27"/>
<circle cx="183.9" cy="171.2" r=".28"/>
<circle cx="182.9" cy="171.2" r=".28"/>
<circle cx="181.9" cy="171.2" r=".28"/>
<circle cx="180.8" cy="171.2" r=".28"/>
<circle cx="179.8" cy="171.2" r=".28"/>
<circle cx="178.8" cy="171.2" r=".27"/>
<circle cx="177.7" cy="171.2" r=".27"/>
<circle cx="176.7" cy="171.2" r=".28"/>
<circle cx="175.7" cy="171.2" r=".28"/>
<circle cx="174.6" cy="171.2" r=".28"/>
<circle cx="173.6" cy="171.2" r=".28"/>
<circle cx="172.6" cy="171.2" r=".28"/>
<circle cx="171.5" cy="171.2" r=".27"/>
<circle cx="170.5" cy="171.2" r=".27"/>
<circle cx="169.5" cy="171.2" r=".28"/>
<circle cx="168.4" cy="171.2" r=".28"/>
<circle cx="167.4" cy="171.2" r=".28"/>
<circle cx="166.3" cy="171.2" r=".28"/>
<circle cx="165.3" cy="171.2" r=".27"/>
<circle cx="164.3" cy="171.2" r=".27"/>
<circle cx="163.3" cy="171.2" r=".28"/>
<circle cx="162.2" cy="171.2" r=".28"/>
<circle cx="161.2" cy="171.2" r=".28"/>
<circle cx="160.1" cy="171.2" r=".28"/>
<circle cx="159.1" cy="171.2" r=".28"/>
<circle cx="158.1" cy="171.2" r=".27"/>
<circle cx="157" cy="171.2" r=".27"/>
<circle cx="156" cy="171.2" r=".28"/>
<circle cx="155" cy="171.2" r=".28"/>
<circle cx="153.9" cy="171.2" r=".28"/>
<circle cx="152.9" cy="171.2" r=".28"/>
<circle cx="151.9" cy="171.2" r=".27"/>
<circle cx="150.8" cy="171.2" r=".27"/>
<circle cx="149.8" cy="171.2" r=".27"/>
<circle cx="148.8" cy="171.2" r=".28"/>
<circle cx="147.7" cy="171.2" r=".28"/>
<circle cx="146.7" cy="171.2" r=".28"/>
<circle cx="145.7" cy="171.2" r=".28"/>
<circle cx="144.6" cy="171.2" r=".27"/>
<circle cx="143.6" cy="171.2" r=".27"/>
<circle cx="142.6" cy="171.2" r=".28"/>
<circle cx="141.5" cy="171.2" r=".28"/>
<circle cx="140.5" cy="171.2" r=".28"/>
<circle cx="139.5" cy="171.2" r=".28"/>
<circle cx="138.4" cy="171.2" r=".28"/>
<circle cx="137.4" cy="171.2" r=".27"/>
<circle cx="136.4" cy="171.2" r=".27"/>
<circle cx="135.3" cy="171.2" r=".28"/>
<circle cx="134.3" cy="171.2" r=".28"/>
<circle cx="133.3" cy="171.2" r=".28"/>
<circle cx="132.2" cy="171.2" r=".28"/>
<circle cx="131.2" cy="171.2" r=".27"/>
<circle cx="130.2" cy="171.2" r=".27"/>
<circle cx="129.1" cy="171.2" r=".27"/>
<circle cx="128.1" cy="171.2" r=".28"/>
<circle cx="127.1" cy="171.2" r=".28"/>
<circle cx="126" cy="171.2" r=".28"/>
<circle cx="125" cy="171.2" r=".28"/>
<circle cx="124" cy="171.2" r=".27"/>
<circle cx="122.9" cy="171.2" r=".27"/>
<circle cx="121.9" cy="171.2" r=".28"/>
<circle cx="120.9" cy="171.2" r=".28"/>
<circle cx="119.8" cy="171.2" r=".28"/>
<circle cx="118.8" cy="171.2" r=".28"/>
<circle cx="117.8" cy="171.2" r=".28"/>
<circle cx="116.7" cy="171.2" r=".27"/>
<circle cx="115.7" cy="171.2" r=".27"/>
<circle cx="114.7" cy="171.2" r=".28"/>
<circle cx="113.6" cy="171.2" r=".28"/>
<circle cx="112.6" cy="171.2" r=".28"/>
<circle cx="111.5" cy="171.2" r=".28"/>
<circle cx="110.5" cy="171.2" r=".27"/>
<circle cx="109.5" cy="171.2" r=".27"/>
<circle cx="108.5" cy="171.2" r=".28"/>
<circle cx="107.4" cy="171.2" r=".28"/>
<circle cx="106.4" cy="171.2" r=".28"/>
<circle cx="105.3" cy="171.2" r=".28"/>
<circle cx="104.3" cy="171.2" r=".28"/>
<circle cx="103.3" cy="171.2" r=".27"/>
<circle cx="102.2" cy="171.2" r=".27"/>
<circle cx="101.2" cy="171.2" r=".28"/>
<circle cx="100.2" cy="171.2" r=".28"/>
<circle cx="99.1" cy="171.2" r=".28"/>
<circle cx="98.1" cy="171.2" r=".28"/>
<circle cx="97.1" cy="171.2" r=".27"/>
<circle cx="96" cy="171.2" r=".27"/>
<circle cx="95" cy="171.2" r=".27"/>
<circle cx="94" cy="171.2" r=".28"/>
<circle cx="92.9" cy="171.2" r=".28"/>
<circle cx="91.9" cy="171.2" r=".28"/>
<circle cx="90.9" cy="171.2" r=".28"/>
<circle cx="89.8" cy="171.2" r=".27"/>
<circle cx="88.8" cy="171.2" r=".27"/>
<circle cx="87.8" cy="171.2" r=".28"/>
<circle cx="86.7" cy="171.2" r=".28"/>
<circle cx="85.7" cy="171.2" r=".28"/>
<circle cx="84.7" cy="171.2" r=".28"/>
<circle cx="83.6" cy="171.2" r=".28"/>
<circle cx="82.6" cy="171.2" r=".27"/>
<circle cx="81.6" cy="171.2" r=".27"/>
<circle cx="80.5" cy="171.2" r=".28"/>
<circle cx="80.5" cy="170.2" r=".27"/>
<circle cx="80.5" cy="169.1" r=".27"/>
<circle cx="80.5" cy="168.1" r=".28"/>
<circle cx="80.5" cy="167.1" r=".28"/>
<circle cx="80.5" cy="166" r=".27"/>
<circle cx="80.5" cy="165" r=".27"/>
<circle cx="80.5" cy="164" r=".28"/>
<circle cx="80.5" cy="162.9" r=".28"/>
<circle cx="80.5" cy="161.9" r=".27"/>
<circle cx="80.5" cy="160.9" r=".28"/>
<circle cx="80.5" cy="159.9" r=".28"/>
<circle cx="80.5" cy="158.8" r=".27"/>
<circle cx="80.5" cy="157.8" r=".27"/>
<circle cx="80.5" cy="156.8" r=".28"/>
<circle cx="80.5" cy="155.7" r=".28"/>
<circle cx="80.5" cy="154.7" r=".27"/>
<circle cx="80.5" cy="153.7" r=".27"/>
<circle cx="80.5" cy="152.6" r=".28"/>
<circle cx="80.5" cy="151.6" r=".28"/>
<circle cx="80.5" cy="150.6" r=".27"/>
<circle cx="80.5" cy="149.5" r=".27"/>
<circle cx="80.5" cy="148.5" r=".28"/>
<circle cx="80.5" cy="147.5" r=".28"/>
<circle cx="80.5" cy="146.4" r=".27"/>
<circle cx="80.5" cy="145.4" r=".27"/>
<circle cx="80.5" cy="144.4" r=".28"/>
<circle cx="80.5" cy="143.3" r=".28"/>
<circle cx="80.5" cy="142.3" r=".27"/>
<circle cx="80.5" cy="141.3" r=".28"/>
<circle cx="80.5" cy="140.3" r=".28"/>
<circle cx="80.5" cy="139.2" r=".27"/>
<circle cx="80.5" cy="138.2" r=".27"/>
<circle cx="80.5" cy="137.2" r=".28"/>
<circle cx="80.5" cy="136.1" r=".28"/>
<circle cx="80.5" cy="135.1" r=".27"/>
<circle cx="80.5" cy="134.1" r=".27"/>
<circle cx="80.5" cy="133" r=".28"/>
<circle cx="80.5" cy="132" r=".28"/>
<circle cx="80.5" cy="131" r=".27"/>
<circle cx="80.5" cy="129.9" r=".27"/>
<circle cx="80.5" cy="128.9" r=".28"/>
<circle cx="80.5" cy="127.9" r=".28"/>
<circle cx="80.5" cy="126.8" r=".27"/>
<circle cx="80.5" cy="125.8" r=".27"/>
<circle cx="80.5" cy="124.8" r=".28"/>
<circle cx="80.5" cy="123.7" r=".28"/>
<circle cx="80.5" cy="122.7" r=".27"/>
<circle cx="80.5" cy="121.7" r=".28"/>
<circle cx="80.5" cy="120.6" r=".28"/>
<circle cx="80.5" cy="119.6" r=".27"/>
<circle cx="80.4" cy="118.6" r=".27"/>
<circle cx="80.4" cy="117.6" r=".28"/>
<circle cx="80.4" cy="116.5" r=".28"/>
<circle cx="80.4" cy="115.5" r=".27"/>
<circle cx="80.4" cy="114.5" r=".27"/>
<circle cx="80.4" cy="113.4" r=".28"/>
<circle cx="80.4" cy="112.4" r=".28"/>
<circle cx="80.4" cy="111.4" r=".27"/>
<circle cx="80.4" cy="110.3" r=".27"/>
<circle cx="80.4" cy="109.3" r=".28"/>
<circle cx="80.4" cy="108.3" r=".28"/>
<circle cx="80.4" cy="107.2" r=".27"/>
<circle cx="80.4" cy="106.2" r=".27"/>
<circle cx="80.4" cy="105.2" r=".28"/>
<circle cx="80.4" cy="104.1" r=".28"/>
<circle cx="80.4" cy="103.1" r=".27"/>
<circle cx="80.4" cy="102.1" r=".28"/>
<circle cx="80.4" cy="101" r=".28"/>
<circle cx="80.4" cy="100" r=".27"/>
<circle cx="80.4" cy="99" r=".27"/>
<circle cx="80.4" cy="98" r=".28"/>
<circle cx="80.4" cy="96.9" r=".28"/>
<circle cx="80.4" cy="95.9" r=".27"/>
<circle cx="80.4" cy="94.9" r=".27"/>
<circle cx="80.4" cy="93.8" r=".28"/>
<circle cx="80.4" cy="92.8" r=".28"/>
<circle cx="80.4" cy="91.8" r=".27"/>
<circle cx="80.4" cy="90.7" r=".27"/>
<circle cx="80.4" cy="89.7" r=".28"/>
<circle cx="80.4" cy="88.7" r=".28"/>
<circle cx="80.4" cy="87.6" r=".27"/>
<circle cx="80.4" cy="86.6" r=".27"/>
<circle cx="80.4" cy="85.6" r=".28"/>
<circle cx="80.4" cy="84.5" r=".28"/>
<circle cx="80.4" cy="83.5" r=".27"/>
<circle cx="80.4" cy="82.5" r=".28"/>
<circle cx="80.4" cy="81.4" r=".28"/>
<circle cx="80.4" cy="80.4" r=".27"/>
<circle cx="80.4" cy="79.4" r=".27"/>
<circle cx="80.4" cy="78.4" r=".28"/>
<circle cx="80.4" cy="77.3" r=".28"/>
<circle cx="80.4" cy="76.3" r=".27"/>
<circle cx="80.4" cy="75.3" r=".27"/>
<circle cx="80.4" cy="74.2" r=".28"/>
<circle cx="80.4" cy="73.2" r=".28"/>
<circle cx="80.4" cy="72.2" r=".27"/>
<circle cx="80.4" cy="71.1" r=".27"/>
<circle cx="80.4" cy="70.1" r=".28"/>
<circle cx="80.4" cy="69.1" r=".28"/>
<circle cx="80.4" cy="68" r=".27"/>
<circle cx="80.4" cy="67" r=".27"/>
<circle cx="80.4" cy="66" r=".28"/>
<circle cx="80.4" cy="64.9" r=".28"/>
<circle cx="80.4" cy="63.9" r=".27"/>
<circle cx="80.4" cy="62.9" r=".28"/>
<circle cx="80.4" cy="61.8" r=".28"/>
<circle cx="80.4" cy="60.8" r=".27"/>
<circle cx="80.4" cy="59.8" r=".27"/>
<circle cx="80.4" cy="58.8" r=".28"/>
<circle cx="80.4" cy="57.7" r=".28"/>
<circle cx="80.4" cy="56.7" r=".27"/>
<circle cx="80.4" cy="55.7" r=".27"/>
<circle cx="80.4" cy="54.6" r=".28"/>
<circle cx="80.4" cy="53.6" r=".28"/>
<circle cx="80.4" cy="52.6" r=".27"/>
<circle cx="80.4" cy="51.5" r=".27"/>
<circle cx="80.4" cy="50.5" r=".28"/>
<circle cx="80.4" cy="49.5" r=".28"/>
<circle cx="80.4" cy="48.4" r=".27"/>
<circle cx="80.4" cy="47.4" r=".27"/>
<circle cx="80.4" cy="46.4" r=".28"/>
<circle cx="80.4" cy="45.3" r=".28"/>
<circle cx="80.4" cy="44.3" r=".27"/>
<circle cx="80.4" cy="43.3" r=".28"/>
<circle cx="80.4" cy="42.2" r=".28"/>
<circle cx="80.4" cy="41.2" r=".27"/>
<circle cx="80.4" cy="40.2" r=".27"/>
<circle cx="80.4" cy="39.2" r=".28"/>
<circle cx="80.4" cy="38.1" r=".28"/>
<circle cx="80.4" cy="37.1" r=".27"/>
<circle cx="80.4" cy="36.1" r=".27"/>
<circle cx="80.4" cy="35" r=".28"/>
<circle cx="80.4" cy="34" r=".28"/>
<circle cx="80.4" cy="33" r=".27"/>
</g>
<circle cx="203.4" cy="140.8" r=".91" fill="#008000" stroke="#008000" stroke-width=".21"/>
<circle cx="203.4" cy="140.8" r=".53" fill="#fff" stroke="#000" stroke-width=".21"/>
<circle cx="201.5" cy="140.8" r=".91" fill="#008000" stroke="#008000" stroke-width=".21"/>
<circle cx="201.5" cy="140.8" r=".53" fill="#fff" stroke="#000" stroke-width=".21"/>
<circle cx="203.4" cy="138.9" r=".91" fill="#008000" stroke="#008000" stroke-width=".21"/>
<circle cx="203.4" cy="138.9" r=".53" fill="#fff" stroke="#000" stroke-width=".21"/>
<circle cx="201.5" cy="138.9" r=".91" fill="#008000" stroke="#008000" stroke-width=".21"/>
<circle cx="201.5" cy="138.9" r=".53" fill="#fff" stroke="#000" stroke-width=".21"/>
<circle cx="203.4" cy="137" r=".91" fill="#008000" stroke="#008000" stroke-width=".21"/>
<circle cx="203.4" cy="137" r=".53" fill="#fff" stroke="#000" stroke-width=".21"/>
<circle cx="201.5" cy="137" r=".91" fill="#008000" stroke="#008000" stroke-width=".21"/>
<circle cx="201.5" cy="137" r=".53" fill="#fff" stroke="#000" stroke-width=".21"/>
<circle cx="203.4" cy="135.1" r=".91" fill="#008000" stroke="#008000" stroke-width=".21"/>
<circle cx="203.4" cy="135.1" r=".53" fill="#fff" stroke="#000" stroke-width=".21"/>
<circle cx="201.5" cy="135.1" r=".91" fill="#008000" stroke="#008000" stroke-width=".21"/>
<circle cx="201.5" cy="135.1" r=".53" fill="#fff" stroke="#000" stroke-width=".21"/>
<circle cx="203.4" cy="133.2" r=".91" fill="#008000" stroke="#008000" stroke-width=".21"/>
<circle cx="203.4" cy="133.2" r=".53" fill="#fff" stroke="#000" stroke-width=".21"/>
<circle cx="201.5" cy="133.2" r=".91" fill="#008000" stroke="#008000" stroke-width=".21"/>
<circle cx="201.5" cy="133.2" r=".53" fill="#fff" stroke="#000" stroke-width=".21"/>
<circle cx="203.4" cy="131.3" r=".91" fill="#008000" stroke="#008000" stroke-width=".21"/>
<circle cx="203.4" cy="131.3" r=".53" fill="#fff" stroke="#000" stroke-width=".21"/>
<circle cx="201.5" cy="131.3" r=".91" fill="#008000" stroke="#008000" stroke-width=".21"/>
<circle cx="201.5" cy="131.3" r=".53" fill="#fff" stroke="#000" stroke-width=".21"/>
<circle cx="203.4" cy="129.4" r=".91" fill="#008000" stroke="#008000" stroke-width=".21"/>
<circle cx="203.4" cy="129.4" r=".53" fill="#fff" stroke="#000" stroke-width=".21"/>
<circle cx="201.5" cy="129.4" r=".91" fill="#008000" stroke="#008000" stroke-width=".21"/>
<circle cx="201.5" cy="129.4" r=".53" fill="#fff" stroke="#000" stroke-width=".21"/>
<circle cx="203.4" cy="127.5" r=".91" fill="#008000" stroke="#008000" stroke-width=".21"/>
<circle cx="203.4" cy="127.5" r=".53" fill="#fff" stroke="#000" stroke-width=".21"/>
<circle cx="201.5" cy="127.5" r=".91" fill="#008000" stroke="#008000" stroke-width=".21"/>
<circle cx="201.5" cy="127.5" r=".53" fill="#fff" stroke="#000" stroke-width=".21"/>
<circle cx="203.4" cy="125.6" r=".91" fill="#008000" stroke="#008000" stroke-width=".21"/>
<circle cx="203.4" cy="125.6" r=".53" fill="#fff" stroke="#000" stroke-width=".21"/>
<circle cx="201.5" cy="125.6" r=".91" fill="#008000" stroke="#008000" stroke-width=".21"/>
<circle cx="201.5" cy="125.6" r=".53" fill="#fff" stroke="#000" stroke-width=".21"/>
<circle cx="203.4" cy="123.7" r=".91" fill="#008000" stroke="#008000" stroke-width=".21"/>
<circle cx="203.4" cy="123.7" r=".53" fill="#fff" stroke="#000" stroke-width=".21"/>
<circle cx="201.5" cy="123.7" r=".91" fill="#008000" stroke="#008000" stroke-width=".21"/>
<circle cx="201.5" cy="123.7" r=".53" fill="#fff" stroke="#000" stroke-width=".21"/>
<circle cx="203.4" cy="121.8" r=".91" fill="#008000" stroke="#008000" stroke-width=".21"/>
<circle cx="203.4" cy="121.8" r=".53" fill="#fff" stroke="#000" stroke-width=".21"/>
<circle cx="201.5" cy="121.8" r=".91" fill="#008000" stroke="#008000" stroke-width=".21"/>
<circle cx="201.5" cy="121.8" r=".53" fill="#fff" stroke="#000" stroke-width=".21"/>
<circle cx="203.4" cy="119.8" r=".91" fill="#008000" stroke="#008000" stroke-width=".21"/>
<circle cx="203.4" cy="119.8" r=".53" fill="#fff" stroke="#000" stroke-width=".21"/>
<circle cx="201.5" cy="119.8" r=".91" fill="#008000" stroke="#008000" stroke-width=".21"/>
<circle cx="201.5" cy="119.8" r=".53" fill="#fff" stroke="#000" stroke-width=".21"/>
<circle cx="203.4" cy="117.9" r=".91" fill="#008000" stroke="#008000" stroke-width=".21"/>
<circle cx="203.4" cy="117.9" r=".53" fill="#fff" stroke="#000" stroke-width=".21"/>
<circle cx="201.5" cy="117.9" r=".91" fill="#008000" stroke="#008000" stroke-width=".21"/>
<circle cx="201.5" cy="117.9" r=".53" fill="#fff" stroke="#000" stroke-width=".21"/>
<circle cx="203.4" cy="116" r=".91" fill="#008000" stroke="#008000" stroke-width=".21"/>
<circle cx="203.4" cy="116" r=".53" fill="#fff" stroke="#000" stroke-width=".21"/>
<circle cx="201.5" cy="116" r=".91" fill="#008000" stroke="#008000" stroke-width=".21"/>
<circle cx="201.5" cy="116" r=".53" fill="#fff" stroke="#000" stroke-width=".21"/>
<circle cx="203.4" cy="114.1" r=".91" fill="#008000" stroke="#008000" stroke-width=".21"/>
<circle cx="203.4" cy="114.1" r=".53" fill="#fff" stroke="#000" stroke-width=".21"/>
<circle cx="201.5" cy="114.1" r=".91" fill="#008000" stroke="#008000" stroke-width=".21"/>
<circle cx="201.5" cy="114.1" r=".53" fill="#fff" stroke="#000" stroke-width=".21"/>
<circle cx="203.4" cy="112.2" r=".91" fill="#008000" stroke="#008000" stroke-width=".21"/>
<circle cx="203.4" cy="112.2" r=".53" fill="#fff" stroke="#000" stroke-width=".21"/>
<circle cx="201.5" cy="112.2" r=".91" fill="#008000" stroke="#008000" stroke-width=".21"/>
<circle cx="201.5" cy="112.2" r=".53" fill="#fff" stroke="#000" stroke-width=".21"/>
<circle cx="203.4" cy="110.3" r=".91" fill="#008000" stroke="#008000" stroke-width=".21"/>
<circle cx="203.4" cy="110.3" r=".53" fill="#fff" stroke="#000" stroke-width=".21"/>
<circle cx="201.5" cy="110.3" r=".91" fill="#008000" stroke="#008000" stroke-width=".21"/>
<circle cx="201.5" cy="110.3" r=".53" fill="#fff" stroke="#000" stroke-width=".21"/>
<circle cx="203.4" cy="108.4" r=".91" fill="#008000" stroke="#008000" stroke-width=".21"/>
<circle cx="203.4" cy="108.4" r=".53" fill="#fff" stroke="#000" stroke-width=".21"/>
<circle cx="201.5" cy="108.4" r=".91" fill="#008000" stroke="#008000" stroke-width=".21"/>
<circle cx="201.5" cy="108.4" r=".53" fill="#fff" stroke="#000" stroke-width=".21"/>
<circle cx="203.4" cy="106.5" r=".91" fill="#008000" stroke="#008000" stroke-width=".21"/>
<circle cx="203.4" cy="106.5" r=".53" fill="#fff" stroke="#000" stroke-width=".21"/>
<circle cx="201.5" cy="106.5" r=".91" fill="#008000" stroke="#008000" stroke-width=".21"/>
<circle cx="201.5" cy="106.5" r=".53" fill="#fff" stroke="#000" stroke-width=".21"/>
<circle cx="203.4" cy="104.6" r=".91" fill="#008000" stroke="#008000" stroke-width=".21"/>
<circle cx="203.4" cy="104.6" r=".53" fill="#fff" stroke="#000" stroke-width=".21"/>
<circle cx="201.5" cy="104.6" r=".91" fill="#008000" stroke="#008000" stroke-width=".21"/>
<circle cx="201.5" cy="104.6" r=".53" fill="#fff" stroke="#000" stroke-width=".21"/>
<circle cx="203.4" cy="102.7" r=".91" fill="#008000" stroke="#008000" stroke-width=".21"/>
<circle cx="203.4" cy="102.7" r=".53" fill="#fff" stroke="#000" stroke-width=".21"/>
<circle cx="201.5" cy="102.7" r=".91" fill="#008000" stroke="#008000" stroke-width=".21"/>
<circle cx="201.5" cy="102.7" r=".53" fill="#fff" stroke="#000" stroke-width=".21"/>
<circle cx="203.4" cy="100.8" r=".91" fill="#008000" stroke="#008000" stroke-width=".21"/>
<circle cx="203.4" cy="100.8" r=".53" fill="#fff" stroke="#000" stroke-width=".21"/>
<circle cx="201.5" cy="100.8" r=".91" fill="#008000" stroke="#008000" stroke-width=".21"/>
<circle cx="201.5" cy="100.8" r=".53" fill="#fff" stroke="#000" stroke-width=".21"/>
<circle cx="203.4" cy="98.9" r=".91" fill="#008000" stroke="#008000" stroke-width=".21"/>
<circle cx="203.4" cy="98.9" r=".53" fill="#fff" stroke="#000" stroke-width=".21"/>
<circle cx="201.5" cy="98.9" r=".91" fill="#008000" stroke="#008000" stroke-width=".21"/>
<circle cx="201.5" cy="98.9" r=".53" fill="#fff" stroke="#000" stroke-width=".21"/>
<circle cx="203.4" cy="97" r=".91" fill="#008000" stroke="#008000" stroke-width=".21"/>
<circle cx="203.4" cy="97" r=".53" fill="#fff" stroke="#000" stroke-width=".21"/>
<circle cx="201.5" cy="97" r=".91" fill="#008000" stroke="#008000" stroke-width=".21"/>
<circle cx="201.5" cy="97" r=".53" fill="#fff" stroke="#000" stroke-width=".21"/>
<circle cx="203.4" cy="95.1" r=".91" fill="#008000" stroke="#008000" stroke-width=".21"/>
<circle cx="203.4" cy="95.1" r=".53" fill="#fff" stroke="#000" stroke-width=".21"/>
<circle cx="201.5" cy="95.1" r=".91" fill="#008000" stroke="#008000" stroke-width=".21"/>
<circle cx="201.5" cy="95.1" r=".53" fill="#fff" stroke="#000" stroke-width=".21"/>
<circle cx="102.5" cy="41.4" r="1.14" fill="#008000" stroke="#008000" stroke-width=".21"/>
<circle cx="102.5" cy="41.4" r=".76" fill="#fff" stroke="#000" stroke-width=".21"/>
<circle cx="102.5" cy="37.5" r="1.14" fill="#008000" stroke="#008000" stroke-width=".21"/>
<circle cx="102.5" cy="37.5" r=".76" fill="#fff" stroke="#000" stroke-width=".21"/>
<circle cx="106.3" cy="41.4" r="1.14" fill="#008000" stroke="#008000" stroke-width=".21"/>
<circle cx="106.3" cy="41.4" r=".76" fill="#fff" stroke="#000" stroke-width=".21"/>
<circle cx="106.3" cy="37.5" r="1.14" fill="#008000" stroke="#008000" stroke-width=".21"/>
<circle cx="106.3" cy="37.5" r=".76" fill="#fff" stroke="#000" stroke-width=".21"/>
<circle cx="110.1" cy="41.4" r="1.14" fill="#008000" stroke="#008000" stroke-width=".21"/>
<circle cx="110.1" cy="41.4" r=".76" fill="#fff" stroke="#000" stroke-width=".21"/>
<circle cx="110.1" cy="37.5" r="1.14" fill="#008000" stroke="#008000" stroke-width=".21"/>
<circle cx="110.1" cy="37.5" r=".76" fill="#fff" stroke="#000" stroke-width=".21"/>
<circle cx="113.9" cy="41.4" r="1.14" fill="#008000" stroke="#008000" stroke-width=".21"/>
<circle cx="113.9" cy="41.4" r=".76" fill="#fff" stroke="#000" stroke-width=".21"/>
<circle cx="113.9" cy="37.5" r="1.14" fill="#008000" stroke="#008000" stroke-width=".21"/>
<circle cx="113.9" cy="37.5" r=".76" fill="#fff" stroke="#000" stroke-width=".21"/>
<circle cx="117.8" cy="41.4" r="1.14" fill="#008000" stroke="#008000" stroke-width=".21"/>
<circle cx="117.8" cy="41.4" r=".76" fill="#fff" stroke="#000" stroke-width=".21"/>
<circle cx="117.8" cy="37.5" r="1.14" fill="#008000" stroke="#008000" stroke-width=".21"/>
<circle cx="117.8" cy="37.5" r=".76" fill="#fff" stroke="#000" stroke-width=".21"/>
<circle cx="121.6" cy="41.4" r="1.14" fill="#008000" stroke="#008000" stroke-width=".21"/>
<circle cx="121.6" cy="41.4" r=".76" fill="#fff" stroke="#000" stroke-width=".21"/>
<circle cx="121.6" cy="37.5" r="1.14" fill="#008000" stroke="#008000" stroke-width=".21"/>
<circle cx="121.6" cy="37.5" r=".76" fill="#fff" stroke="#000" stroke-width=".21"/>
<circle cx="125.4" cy="41.4" r="1.14" fill="#008000" stroke="#008000" stroke-width=".21"/>
<circle cx="125.4" cy="41.4" r=".76" fill="#fff" stroke="#000" stroke-width=".21"/>
<circle cx="125.4" cy="37.5" r="1.14" fill="#008000" stroke="#008000" stroke-width=".21"/>
<circle cx="125.4" cy="37.5" r=".76" fill="#fff" stroke="#000" stroke-width=".21"/>
<circle cx="129.2" cy="41.4" r="1.14" fill="#008000" stroke="#008000" stroke-width=".21"/>
<circle cx="129.2" cy="41.4" r=".76" fill="#fff" stroke="#000" stroke-width=".21"/>
<circle cx="129.2" cy="37.5" r="1.14" fill="#008000" stroke="#008000" stroke-width=".21"/>
<circle cx="129.2" cy="37.5" r=".76" fill="#fff" stroke="#000" stroke-width=".21"/>
<circle cx="133" cy="41.4" r="1.14" fill="#008000" stroke="#008000" stroke-width=".21"/>
<circle cx="133" cy="41.4" r=".76" fill="#fff" stroke="#000" stroke-width=".21"/>
<circle cx="133" cy="37.5" r="1.14" fill="#008000" stroke="#008000" stroke-width=".21"/>
<circle cx="133" cy="37.5" r=".76" fill="#fff" stroke="#000" stroke-width=".21"/>
<circle cx="136.8" cy="41.4" r="1.14" fill="#008000" stroke="#008000" stroke-width=".21"/>
<circle cx="136.8" cy="41.4" r=".76" fill="#fff" stroke="#000" stroke-width=".21"/>
<circle cx="136.8" cy="37.5" r="1.14" fill="#008000" stroke="#008000" stroke-width=".21"/>
<circle cx="136.8" cy="37.5" r=".76" fill="#fff" stroke="#000" stroke-width=".21"/>
<circle cx="140.6" cy="41.4" r="1.14" fill="#008000" stroke="#008000" stroke-width=".21"/>
<circle cx="140.6" cy="41.4" r=".76" fill="#fff" stroke="#000" stroke-width=".21"/>
<circle cx="140.6" cy="37.5" r="1.14" fill="#008000" stroke="#008000" stroke-width=".21"/>
<circle cx="140.6" cy="37.5" r=".76" fill="#fff" stroke="#000" stroke-width=".21"/>
<circle cx="144.4" cy="41.4" r="1.14" fill="#008000" stroke="#008000" stroke-width=".21"/>
<circle cx="144.4" cy="41.4" r=".76" fill="#fff" stroke="#000" stroke-width=".21"/>
<circle cx="144.4" cy="37.5" r="1.14" fill="#008000" stroke="#008000" stroke-width=".21"/>
<circle cx="144.4" cy="37.5" r=".76" fill="#fff" stroke="#000" stroke-width=".21"/>
<circle cx="148.2" cy="41.4" r="1.14" fill="#008000" stroke="#008000" stroke-width=".21"/>
<circle cx="148.2" cy="41.4" r=".76" fill="#fff" stroke="#000" stroke-width=".21"/>
<circle cx="148.2" cy="37.5" r="1.14" fill="#008000" stroke="#008000" stroke-width=".21"/>
<circle cx="148.2" cy="37.5" r=".76" fill="#fff" stroke="#000" stroke-width=".21"/>
<circle cx="152" cy="41.4" r="1.14" fill="#008000" stroke="#008000" stroke-width=".21"/>
<circle cx="152" cy="41.4" r=".76" fill="#fff" stroke="#000" stroke-width=".21"/>
<circle cx="152" cy="37.5" r="1.14" fill="#008000" stroke="#008000" stroke-width=".21"/>
<circle cx="152" cy="37.5" r=".76" fill="#fff" stroke="#000" stroke-width=".21"/>
<circle cx="155.8" cy="41.4" r="1.14" fill="#008000" stroke="#008000" stroke-width=".21"/>
<circle cx="155.8" cy="41.4" r=".76" fill="#fff" stroke="#000" stroke-width=".21"/>
<circle cx="155.8" cy="37.5" r="1.14" fill="#008000" stroke="#008000" stroke-width=".21"/>
<circle cx="155.8" cy="37.5" r=".76" fill="#fff" stroke="#000" stroke-width=".21"/>
<circle cx="159.6" cy="41.4" r="1.14" fill="#008000" stroke="#008000" stroke-width=".21"/>
<circle cx="159.6" cy="41.4" r=".76" fill="#fff" stroke="#000" stroke-width=".21"/>
<circle cx="159.6" cy="37.5" r="1.14" fill="#008000" stroke="#008000" stroke-width=".21"/>
<circle cx="159.6" cy="37.5" r=".76" fill="#fff" stroke="#000" stroke-width=".21"/>
<circle cx="163.4" cy="41.4" r="1.14" fill="#008000" stroke="#008000" stroke-width=".21"/>
<circle cx="163.4" cy="41.4" r=".76" fill="#fff" stroke="#000" stroke-width=".21"/>
<circle cx="163.4" cy="37.5" r="1.14" fill="#008000" stroke="#008000" stroke-width=".21"/>
<circle cx="163.4" cy="37.5" r=".76" fill="#fff" stroke="#000" stroke-width=".21"/>
<circle cx="167.3" cy="41.4" r="1.14" fill="#008000" stroke="#008000" stroke-width=".21"/>
<circle cx="167.3" cy="41.4" r=".76" fill="#fff" stroke="#000" stroke-width=".21"/>
<circle cx="167.3" cy="37.5" r="1.14" fill="#008000" stroke="#008000" stroke-width=".21"/>
<circle cx="167.3" cy="37.5" r=".76" fill="#fff" stroke="#000" stroke-width=".21"/>
<circle cx="171.1" cy="41.4" r="1.14" fill="#008000" stroke="#008000" stroke-width=".21"/>
<circle cx="171.1" cy="41.4" r=".76" fill="#fff" stroke="#000" stroke-width=".21"/>
<circle cx="171.1" cy="37.5" r="1.14" fill="#008000" stroke="#008000" stroke-width=".21"/>
<circle cx="171.1" cy="37.5" r=".76" fill="#fff" stroke="#000" stroke-width=".21"/>
<circle cx="174.9" cy="41.4" r="1.14" fill="#008000" stroke="#008000" stroke-width=".21"/>
<circle cx="174.9" cy="41.4" r=".76" fill="#fff" stroke="#000" stroke-width=".21"/>
<circle cx="174.9" cy="37.5" r="1.14" fill="#008000" stroke="#008000" stroke-width=".21"/>
<circle cx="174.9" cy="37.5" r=".76" fill="#fff" stroke="#000" stroke-width=".21"/>
<circle cx="178.7" cy="41.4" r="1.14" fill="#008000" stroke="#008000" stroke-width=".21"/>
<circle cx="178.7" cy="41.4" r=".76" fill="#fff" stroke="#000" stroke-width=".21"/>
<circle cx="178.7" cy="37.5" r="1.14" fill="#008000" stroke="#008000" stroke-width=".21"/>
<circle cx="178.7" cy="37.5" r=".76" fill="#fff" stroke="#000" stroke-width=".21"/>
<circle cx="182.5" cy="41.4" r="1.14" fill="#008000" stroke="#008000" stroke-width=".21"/>
<circle cx="182.5" cy="41.4" r=".76" fill="#fff" stroke="#000" stroke-width=".21"/>
<circle cx="182.5" cy="37.5" r="1.14" fill="#008000" stroke="#008000" stroke-width=".21"/>
<circle cx="182.5" cy="37.5" r=".76" fill="#fff" stroke="#000" stroke-width=".21"/>
<circle cx="186.3" cy="41.4" r="1.14" fill="#008000" stroke="#008000" stroke-width=".21"/>
<circle cx="186.3" cy="41.4" r=".76" fill="#fff" stroke="#000" stroke-width=".21"/>
<circle cx="186.3" cy="37.5" r="1.14" fill="#008000" stroke="#008000" stroke-width=".21"/>
<circle cx="186.3" cy="37.5" r=".76" fill="#fff" stroke="#000" stroke-width=".21"/>
<circle cx="190.1" cy="41.4" r="1.14" fill="#008000" stroke="#008000" stroke-width=".21"/>
<circle cx="190.1" cy="41.4" r=".76" fill="#fff" stroke="#000" stroke-width=".21"/>
<circle cx="190.1" cy="37.5" r="1.14" fill="#008000" stroke="#008000" stroke-width=".21"/>
<circle cx="190.1" cy="37.5" r=".76" fill="#fff" stroke="#000" stroke-width=".21"/>
<circle cx="193.9" cy="41.4" r="1.14" fill="#008000" stroke="#008000" stroke-width=".21"/>
<circle cx="193.9" cy="41.4" r=".76" fill="#fff" stroke="#000" stroke-width=".21"/>
<circle cx="193.9" cy="37.5" r="1.14" fill="#008000" stroke="#008000" stroke-width=".21"/>
<circle cx="193.9" cy="37.5" r=".76" fill="#fff" stroke="#000" stroke-width=".21"/>
<circle cx="197.7" cy="41.4" r="1.14" fill="#008000" stroke="#008000" stroke-width=".21"/>
<circle cx="197.7" cy="41.4" r=".76" fill="#fff" stroke="#000" stroke-width=".21"/>
<circle cx="197.7" cy="37.5" r="1.14" fill="#008000" stroke="#008000" stroke-width=".21"/>
<circle cx="197.7" cy="37.5" r=".76" fill="#fff" stroke="#000" stroke-width=".21"/>
<circle cx="102.5" cy="49" r="1.14" fill="#008000" stroke="#008000" stroke-width=".21"/>
<circle cx="102.5" cy="49" r=".76" fill="#fff" stroke="#000" stroke-width=".21"/>
<circle cx="102.5" cy="45.1" r="1.14" fill="#008000" stroke="#008000" stroke-width=".21"/>
<circle cx="102.5" cy="45.1" r=".76" fill="#fff" stroke="#000" stroke-width=".21"/>
<circle cx="106.3" cy="49" r="1.14" fill="#008000" stroke="#008000" stroke-width=".21"/>
<circle cx="106.3" cy="49" r=".76" fill="#fff" stroke="#000" stroke-width=".21"/>
<circle cx="106.3" cy="45.1" r="1.14" fill="#008000" stroke="#008000" stroke-width=".21"/>
<circle cx="106.3" cy="45.1" r=".76" fill="#fff" stroke="#000" stroke-width=".21"/>
<circle cx="110.1" cy="49" r="1.14" fill="#008000" stroke="#008000" stroke-width=".21"/>
<circle cx="110.1" cy="49" r=".76" fill="#fff" stroke="#000" stroke-width=".21"/>
<circle cx="110.1" cy="45.1" r="1.14" fill="#008000" stroke="#008000" stroke-width=".21"/>
<circle cx="110.1" cy="45.1" r=".76" fill="#fff" stroke="#000" stroke-width=".21"/>
<circle cx="113.9" cy="49" r="1.14" fill="#008000" stroke="#008000" stroke-width=".21"/>
<circle cx="113.9" cy="49" r=".76" fill="#fff" stroke="#000" stroke-width=".21"/>
<circle cx="113.9" cy="45.1" r="1.14" fill="#008000" stroke="#008000" stroke-width=".21"/>
<circle cx="113.9" cy="45.1" r=".76" fill="#fff" stroke="#000" stroke-width=".21"/>
<circle cx="117.8" cy="49" r="1.14" fill="#008000" stroke="#008000" stroke-width=".21"/>
<circle cx="117.8" cy="49" r=".76" fill="#fff" stroke="#000" stroke-width=".21"/>
<circle cx="117.8" cy="45.1" r="1.14" fill="#008000" stroke="#008000" stroke-width=".21"/>
<circle cx="117.8" cy="45.1" r=".76" fill="#fff" stroke="#000" stroke-width=".21"/>
<circle cx="121.6" cy="49" r="1.14" fill="#008000" stroke="#008000" stroke-width=".21"/>
<circle cx="121.6" cy="49" r=".76" fill="#fff" stroke="#000" stroke-width=".21"/>
<circle cx="121.6" cy="45.1" r="1.14" fill="#008000" stroke="#008000" stroke-width=".21"/>
<circle cx="121.6" cy="45.1" r=".76" fill="#fff" stroke="#000" stroke-width=".21"/>
<circle cx="125.4" cy="49" r="1.14" fill="#008000" stroke="#008000" stroke-width=".21"/>
<circle cx="125.4" cy="49" r=".76" fill="#fff" stroke="#000" stroke-width=".21"/>
<circle cx="125.4" cy="45.1" r="1.14" fill="#008000" stroke="#008000" stroke-width=".21"/>
<circle cx="125.4" cy="45.1" r=".76" fill="#fff" stroke="#000" stroke-width=".21"/>
<circle cx="129.2" cy="49" r="1.14" fill="#008000" stroke="#008000" stroke-width=".21"/>
<circle cx="129.2" cy="49" r=".76" fill="#fff" stroke="#000" stroke-width=".21"/>
<circle cx="129.2" cy="45.1" r="1.14" fill="#008000" stroke="#008000" stroke-width=".21"/>
<circle cx="129.2" cy="45.1" r=".76" fill="#fff" stroke="#000" stroke-width=".21"/>
<circle cx="133" cy="49" r="1.14" fill="#008000" stroke="#008000" stroke-width=".21"/>
<circle cx="133" cy="49" r=".76" fill="#fff" stroke="#000" stroke-width=".21"/>
<circle cx="133" cy="45.1" r="1.14" fill="#008000" stroke="#008000" stroke-width=".21"/>
<circle cx="133" cy="45.1" r=".76" fill="#fff" stroke="#000" stroke-width=".21"/>
<circle cx="136.8" cy="49" r="1.14" fill="#008000" stroke="#008000" stroke-width=".21"/>
<circle cx="136.8" cy="49" r=".76" fill="#fff" stroke="#000" stroke-width=".21"/>
<circle cx="136.8" cy="45.1" r="1.14" fill="#008000" stroke="#008000" stroke-width=".21"/>
<circle cx="136.8" cy="45.1" r=".76" fill="#fff" stroke="#000" stroke-width=".21"/>
<circle cx="140.6" cy="49" r="1.14" fill="#008000" stroke="#008000" stroke-width=".21"/>
<circle cx="140.6" cy="49" r=".76" fill="#fff" stroke="#000" stroke-width=".21"/>
<circle cx="140.6" cy="45.1" r="1.14" fill="#008000" stroke="#008000" stroke-width=".21"/>
<circle cx="140.6" cy="45.1" r=".76" fill="#fff" stroke="#000" stroke-width=".21"/>
<circle cx="144.4" cy="49" r="1.14" fill="#008000" stroke="#008000" stroke-width=".21"/>
<circle cx="144.4" cy="49" r=".76" fill="#fff" stroke="#000" stroke-width=".21"/>
<circle cx="144.4" cy="45.1" r="1.14" fill="#008000" stroke="#008000" stroke-width=".21"/>
<circle cx="144.4" cy="45.1" r=".76" fill="#fff" stroke="#000" stroke-width=".21"/>
<circle cx="148.2" cy="49" r="1.14" fill="#008000" stroke="#008000" stroke-width=".21"/>
<circle cx="148.2" cy="49" r=".76" fill="#fff" stroke="#000" stroke-width=".21"/>
<circle cx="148.2" cy="45.1" r="1.14" fill="#008000" stroke="#008000" stroke-width=".21"/>
<circle cx="148.2" cy="45.1" r=".76" fill="#fff" stroke="#000" stroke-width=".21"/>
<circle cx="152" cy="49" r="1.14" fill="#008000" stroke="#008000" stroke-width=".21"/>
<circle cx="152" cy="49" r=".76" fill="#fff" stroke="#000" stroke-width=".21"/>
<circle cx="152" cy="45.1" r="1.14" fill="#008000" stroke="#008000" stroke-width=".21"/>
<circle cx="152" cy="45.1" r=".76" fill="#fff" stroke="#000" stroke-width=".21"/>
<circle cx="155.9" cy="49" r="1.14" fill="#008000" stroke="#008000" stroke-width=".21"/>
<circle cx="155.9" cy="49" r=".76" fill="#fff" stroke="#000" stroke-width=".21"/>
<circle cx="155.9" cy="45.1" r="1.14" fill="#008000" stroke="#008000" stroke-width=".21"/>
<circle cx="155.9" cy="45.1" r=".76" fill="#fff" stroke="#000" stroke-width=".21"/>
<circle cx="159.7" cy="49" r="1.14" fill="#008000" stroke="#008000" stroke-width=".21"/>
<circle cx="159.7" cy="49" r=".76" fill="#fff" stroke="#000" stroke-width=".21"/>
<circle cx="159.7" cy="45.1" r="1.14" fill="#008000" stroke="#008000" stroke-width=".21"/>
<circle cx="159.7" cy="45.1" r=".76" fill="#fff" stroke="#000" stroke-width=".21"/>
<circle cx="163.5" cy="49" r="1.14" fill="#008000" stroke="#008000" stroke-width=".21"/>
<circle cx="163.5" cy="49" r=".76" fill="#fff" stroke="#000" stroke-width=".21"/>
<circle cx="163.5" cy="45.1" r="1.14" fill="#008000" stroke="#008000" stroke-width=".21"/>
<circle cx="163.5" cy="45.1" r=".76" fill="#fff" stroke="#000" stroke-width=".21"/>
<circle cx="167.3" cy="49" r="1.14" fill="#008000" stroke="#008000" stroke-width=".21"/>
<circle cx="167.3" cy="49" r=".76" fill="#fff" stroke="#000" stroke-width=".21"/>
<circle cx="167.3" cy="45.1" r="1.14" fill="#008000" stroke="#008000" stroke-width=".21"/>
<circle cx="167.3" cy="45.1" r=".76" fill="#fff" stroke="#000" stroke-width=".21"/>
<circle cx="171.1" cy="49" r="1.14" fill="#008000" stroke="#008000" stroke-width=".21"/>
<circle cx="171.1" cy="49" r=".76" fill="#fff" stroke="#000" stroke-width=".21"/>
<circle cx="171.1" cy="45.1" r="1.14" fill="#008000" stroke="#008000" stroke-width=".21"/>
<circle cx="171.1" cy="45.1" r=".76" fill="#fff" stroke="#000" stroke-width=".21"/>
<circle cx="174.9" cy="49" r="1.14" fill="#008000" stroke="#008000" stroke-width=".21"/>
<circle cx="174.9" cy="49" r=".76" fill="#fff" stroke="#000" stroke-width=".21"/>
<circle cx="174.9" cy="45.1" r="1.14" fill="#008000" stroke="#008000" stroke-width=".21"/>
<circle cx="174.9" cy="45.1" r=".76" fill="#fff" stroke="#000" stroke-width=".21"/>
<circle cx="178.7" cy="49" r="1.14" fill="#008000" stroke="#008000" stroke-width=".21"/>
<circle cx="178.7" cy="49" r=".76" fill="#fff" stroke="#000" stroke-width=".21"/>
<circle cx="178.7" cy="45.1" r="1.14" fill="#008000" stroke="#008000" stroke-width=".21"/>
<circle cx="178.7" cy="45.1" r=".76" fill="#fff" stroke="#000" stroke-width=".21"/>
<circle cx="182.5" cy="49" r="1.14" fill="#008000" stroke="#008000" stroke-width=".21"/>
<circle cx="182.5" cy="49" r=".76" fill="#fff" stroke="#000" stroke-width=".21"/>
<circle cx="182.5" cy="45.1" r="1.14" fill="#008000" stroke="#008000" stroke-width=".21"/>
<circle cx="182.5" cy="45.1" r=".76" fill="#fff" stroke="#000" stroke-width=".21"/>
<circle cx="186.3" cy="49" r="1.14" fill="#008000" stroke="#008000" stroke-width=".21"/>
<circle cx="186.3" cy="49" r=".76" fill="#fff" stroke="#000" stroke-width=".21"/>
<circle cx="186.3" cy="45.1" r="1.14" fill="#008000" stroke="#008000" stroke-width=".21"/>
<circle cx="186.3" cy="45.1" r=".76" fill="#fff" stroke="#000" stroke-width=".21"/>
<circle cx="190.1" cy="49" r="1.14" fill="#008000" stroke="#008000" stroke-width=".21"/>
<circle cx="190.1" cy="49" r=".76" fill="#fff" stroke="#000" stroke-width=".21"/>
<circle cx="190.1" cy="45.1" r="1.14" fill="#008000" stroke="#008000" stroke-width=".21"/>
<circle cx="190.1" cy="45.1" r=".76" fill="#fff" stroke="#000" stroke-width=".21"/>
<circle cx="193.9" cy="49" r="1.14" fill="#008000" stroke="#008000" stroke-width=".21"/>
<circle cx="193.9" cy="49" r=".76" fill="#fff" stroke="#000" stroke-width=".21"/>
<circle cx="193.9" cy="45.1" r="1.14" fill="#008000" stroke="#008000" stroke-width=".21"/>
<circle cx="193.9" cy="45.1" r=".76" fill="#fff" stroke="#000" stroke-width=".21"/>
<circle cx="197.7" cy="49" r="1.14" fill="#008000" stroke="#008000" stroke-width=".21"/>
<circle cx="197.7" cy="49" r=".76" fill="#fff" stroke="#000" stroke-width=".21"/>
<circle cx="197.7" cy="45.1" r="1.14" fill="#008000" stroke="#008000" stroke-width=".21"/>
<circle cx="197.7" cy="45.1" r=".76" fill="#fff" stroke="#000" stroke-width=".21"/>
<circle cx="202.1" cy="81" r="1.8" fill="#008000" stroke="#008000" stroke-width=".21"/>
<circle cx="202.1" cy="81" r="1.21" fill="#fff" stroke="#000" stroke-width=".21"/>
<circle cx="202.1" cy="75" r="1.8" fill="#008000" stroke="#008000" stroke-width=".21"/>
<circle cx="202.1" cy="75" r="1.21" fill="#fff" stroke="#000" stroke-width=".21"/>
<circle cx="202.1" cy="69" r="1.8" fill="#008000" stroke="#008000" stroke-width=".21"/>
<circle cx="202.1" cy="69" r="1.21" fill="#fff" stroke="#000" stroke-width=".21"/>
<circle cx="202.1" cy="63" r="1.8" fill="#008000" stroke="#008000" stroke-width=".21"/>
<circle cx="202.1" cy="63" r="1.21" fill="#fff" stroke="#000" stroke-width=".21"/>
<circle cx="202.1" cy="87" r="2.41" fill="#008000" stroke="#008000" stroke-width=".21"/>
<circle cx="202.1" cy="87" r="1.65" fill="#fff" stroke="#000" stroke-width=".21"/>
<circle cx="202.1" cy="57" r="2.41" fill="#008000" stroke="#008000" stroke-width=".21"/>
<circle cx="202.1" cy="57" r="1.65" fill="#fff" stroke="#000" stroke-width=".21"/>
<circle cx="211.6" cy="62.9" r="1.8" fill="#008000" stroke="#008000" stroke-width=".21"/>
<circle cx="211.6" cy="62.9" r="1.21" fill="#fff" stroke="#000" stroke-width=".21"/>
<circle cx="211.6" cy="68.9" r="1.8" fill="#008000" stroke="#008000" stroke-width=".21"/>
<circle cx="211.6" cy="68.9" r="1.21" fill="#fff" stroke="#000" stroke-width=".21"/>
<circle cx="211.6" cy="74.9" r="1.8" fill="#008000" stroke="#008000" stroke-width=".21"/>
<circle cx="211.6" cy="74.9" r="1.21" fill="#fff" stroke="#000" stroke-width=".21"/>
<circle cx="211.6" cy="80.9" r="1.8" fill="#008000" stroke="#008000" stroke-width=".21"/>
<circle cx="211.6" cy="80.9" r="1.21" fill="#fff" stroke="#000" stroke-width=".21"/>
<circle cx="211.6" cy="86.9" r="1.8" fill="#008000" stroke="#008000" stroke-width=".21"/>
<circle cx="211.6" cy="86.9" r="1.21" fill="#fff" stroke="#000" stroke-width=".21"/>
<circle cx="211.6" cy="92.9" r="1.8" fill="#008000" stroke="#008000" stroke-width=".21"/>
<circle cx="211.6" cy="92.9" r="1.21" fill="#fff" stroke="#000" stroke-width=".21"/>
<circle cx="211.6" cy="98.9" r="1.8" fill="#008000" stroke="#008000" stroke-width=".21"/>
<circle cx="211.6" cy="98.9" r="1.21" fill="#fff" stroke="#000" stroke-width=".21"/>
<circle cx="211.6" cy="104.9" r="1.8" fill="#008000" stroke="#008000" stroke-width=".21"/>
<circle cx="211.6" cy="104.9" r="1.21" fill="#fff" stroke="#000" stroke-width=".21"/>
<circle cx="211.6" cy="110.9" r="1.8" fill="#008000" stroke="#008000" stroke-width=".21"/>
<circle cx="211.6" cy="110.9" r="1.21" fill="#fff" stroke="#000" stroke-width=".21"/>
<circle cx="211.6" cy="116.9" r="1.8" fill="#008000" stroke="#008000" stroke-width=".21"/>
<circle cx="211.6" cy="116.9" r="1.21" fill="#fff" stroke="#000" stroke-width=".21"/>
<circle cx="211.6" cy="56.9" r="2.41" fill="#008000" stroke="#008000" stroke-width=".21"/>
<circle cx="211.6" cy="56.9" r="1.65" fill="#fff" stroke="#000" stroke-width=".21"/>
<circle cx="211.6" cy="122.9" r="2.41" fill="#008000" stroke="#008000" stroke-width=".21"/>
<circle cx="211.6" cy="122.9" r="1.65" fill="#fff" stroke="#000" stroke-width=".21"/>
<circle cx="143.4" cy="98.6" r=".99" fill="#008000" stroke="#008000" stroke-width=".21"/>
<circle cx="143.4" cy="98.6" r=".61" fill="#fff" stroke="#000" stroke-width=".21"/>
<circle cx="139.6" cy="98.6" r=".99" fill="#008000" stroke="#008000" stroke-width=".21"/>
<circle cx="139.6" cy="98.6" r=".61" fill="#fff" stroke="#000" stroke-width=".21"/>
<circle cx="115.6" cy="133.7" r=".68" fill="#008000" stroke="#008000" stroke-width=".21"/>
<circle cx="115.6" cy="133.7" r=".38" fill="#fff" stroke="#000" stroke-width=".21"/>
<circle cx="115.7" cy="139.7" r=".68" fill="#008000" stroke="#008000" stroke-width=".21"/>
<circle cx="115.7" cy="139.7" r=".38" fill="#fff" stroke="#000" stroke-width=".21"/>
<circle cx="104.4" cy="122.8" r=".68" fill="#008000" stroke="#008000" stroke-width=".21"/>
<circle cx="104.4" cy="122.8" r=".38" fill="#fff" stroke="#000" stroke-width=".21"/>
<circle cx="98.9" cy="131.3" r=".68" fill="#008000" stroke="#008000" stroke-width=".21"/>
<circle cx="98.9" cy="131.3" r=".38" fill="#fff" stroke="#000" stroke-width=".21"/>
<circle cx="187.6" cy="151.8" r=".68" fill="#008000" stroke="#008000" stroke-width=".21"/>
<circle cx="187.6" cy="151.8" r=".38" fill="#fff" stroke="#000" stroke-width=".21"/>
<circle cx="181.5" cy="151.8" r=".68" fill="#008000" stroke="#008000" stroke-width=".21"/>
<circle cx="181.5" cy="151.8" r=".38" fill="#fff" stroke="#000" stroke-width=".21"/>
<circle cx="169.7" cy="39.4" r=".68" fill="#008000" stroke="#008000" stroke-width=".21"/>
<circle cx="169.7" cy="39.4" r=".38" fill="#fff" stroke="#000" stroke-width=".21"/>
<circle cx="137.2" cy="52.9" r=".76" fill="#008000" stroke="#008000" stroke-width=".21"/>
<circle cx="137.2" cy="52.9" r=".47" fill="#fff" stroke="#000" stroke-width=".21"/>
<circle cx="112.4" cy="53.7" r=".76" fill="#008000" stroke="#008000" stroke-width=".21"/>
<circle cx="112.4" cy="53.7" r=".47" fill="#fff" stroke="#000" stroke-width=".21"/>
<circle cx="112.3" cy="76.2" r=".68" fill="#008000" stroke="#008000" stroke-width=".21"/>
<circle cx="112.3" cy="76.2" r=".38" fill="#fff" stroke="#000" stroke-width=".21"/>
<circle cx="124.7" cy="79.6" r=".68" fill="#008000" stroke="#008000" stroke-width=".21"/>
<circle cx="124.7" cy="79.6" r=".38" fill="#fff" stroke="#000" stroke-width=".21"/>
<circle cx="129.8" cy="79.7" r=".68" fill="#008000" stroke="#008000" stroke-width=".21"/>
<circle cx="129.8" cy="79.7" r=".38" fill="#fff" stroke="#000" stroke-width=".21"/>
<circle cx="136.5" cy="79.7" r=".68" fill="#008000" stroke="#008000" stroke-width=".21"/>
<circle cx="136.5" cy="79.7" r=".38" fill="#fff" stroke="#000" stroke-width=".21"/>
<circle cx="113.6" cy="100.4" r=".68" fill="#008000" stroke="#008000" stroke-width=".21"/>
<circle cx="113.6" cy="100.4" r=".38" fill="#fff" stroke="#000" stroke-width=".21"/>
<circle cx="116.6" cy="97.3" r=".68" fill="#008000" stroke="#008000" stroke-width=".21"/>
<circle cx="116.6" cy="97.3" r=".38" fill="#fff" stroke="#000" stroke-width=".21"/>
<circle cx="113.2" cy="95" r=".68" fill="#008000" stroke="#008000" stroke-width=".21"/>
<circle cx="113.2" cy="95" r=".38" fill="#fff" stroke="#000" stroke-width=".21"/>
<circle cx="144.4" cy="53.8" r=".76" fill="#008000" stroke="#008000" stroke-width=".21"/>
<circle cx="144.4" cy="53.8" r=".44" fill="#fff" stroke="#000" stroke-width=".21"/>
<circle cx="193.3" cy="149.3" r=".68" fill="#008000" stroke="#008000" stroke-width=".21"/>
<circle cx="193.3" cy="149.3" r=".38" fill="#fff" stroke="#000" stroke-width=".21"/>
<circle cx="201.7" cy="146.7" r=".68" fill="#008000" stroke="#008000" stroke-width=".21"/>
<circle cx="201.7" cy="146.7" r=".38" fill="#fff" stroke="#000" stroke-width=".21"/>
<circle cx="171.2" cy="134.6" r=".68" fill="#008000" stroke="#008000" stroke-width=".21"/>
<circle cx="171.2" cy="134.6" r=".38" fill="#fff" stroke="#000" stroke-width=".21"/>
<circle cx="171.3" cy="127.9" r=".68" fill="#008000" stroke="#008000" stroke-width=".21"/>
<circle cx="171.3" cy="127.9" r=".38" fill="#fff" stroke="#000" stroke-width=".21"/>
<circle cx="119.4" cy="88.2" r=".76" fill="#008000" stroke="#008000" stroke-width=".21"/>
<circle cx="119.4" cy="88.2" r=".47" fill="#fff" stroke="#000" stroke-width=".21"/>
<circle cx="111.5" cy="101" r=".68" fill="#008000" stroke="#008000" stroke-width=".21"/>
<circle cx="111.5" cy="101" r=".38" fill="#fff" stroke="#000" stroke-width=".21"/>
<circle cx="114.2" cy="117.4" r=".68" fill="#008000" stroke="#008000" stroke-width=".21"/>
<circle cx="114.2" cy="117.4" r=".38" fill="#fff" stroke="#000" stroke-width=".21"/>
<circle cx="117.2" cy="120.5" r=".68" fill="#008000" stroke="#008000" stroke-width=".21"/>
<circle cx="117.2" cy="120.5" r=".38" fill="#fff" stroke="#000" stroke-width=".21"/>
<circle cx="116.3" cy="127.8" r=".68" fill="#008000" stroke="#008000" stroke-width=".21"/>
<circle cx="116.3" cy="127.8" r=".38" fill="#fff" stroke="#000" stroke-width=".21"/>
<circle cx="176.6" cy="134.5" r=".68" fill="#008000" stroke="#008000" stroke-width=".21"/>
<circle cx="176.6" cy="134.5" r=".38" fill="#fff" stroke="#000" stroke-width=".21"/>
<circle cx="175.3" cy="109.7" r=".68" fill="#008000" stroke="#008000" stroke-width=".21"/>
<circle cx="175.3" cy="109.7" r=".38" fill="#fff" stroke="#000" stroke-width=".21"/>
<circle cx="178.8" cy="113.8" r=".76" fill="#008000" stroke="#008000" stroke-width=".21"/>
<circle cx="178.8" cy="113.8" r=".47" fill="#fff" stroke="#000" stroke-width=".21"/>
<circle cx="186.7" cy="127.5" r=".68" fill="#008000" stroke="#008000" stroke-width=".21"/>
<circle cx="186.7" cy="127.5" r=".38" fill="#fff" stroke="#000" stroke-width=".21"/>
<circle cx="182.8" cy="141.2" r=".68" fill="#008000" stroke="#008000" stroke-width=".21"/>
<circle cx="182.8" cy="141.2" r=".38" fill="#fff" stroke="#000" stroke-width=".21"/>
<circle cx="175.7" cy="164.7" r=".76" fill="#008000" stroke="#008000" stroke-width=".21"/>
<circle cx="175.7" cy="164.7" r=".47" fill="#fff" stroke="#000" stroke-width=".21"/>
<circle cx="123.3" cy="82.1" r=".68" fill="#008000" stroke="#008000" stroke-width=".21"/>
<circle cx="123.3" cy="82.1" r=".38" fill="#fff" stroke="#000" stroke-width=".21"/>
<circle cx="131.1" cy="111.4" r=".68" fill="#008000" stroke="#008000" stroke-width=".21"/>
<circle cx="131.1" cy="111.4" r=".38" fill="#fff" stroke="#000" stroke-width=".21"/>
<circle cx="139.6" cy="127.3" r=".68" fill="#008000" stroke="#008000" stroke-width=".21"/>
<circle cx="139.6" cy="127.3" r=".38" fill="#fff" stroke="#000" stroke-width=".21"/>
<circle cx="161.7" cy="124.1" r=".76" fill="#008000" stroke="#008000" stroke-width=".21"/>
<circle cx="161.7" cy="124.1" r=".47" fill="#fff" stroke="#000" stroke-width=".21"/>
<circle cx="161.4" cy="118" r=".76" fill="#008000" stroke="#008000" stroke-width=".21"/>
<circle cx="161.4" cy="118" r=".47" fill="#fff" stroke="#000" stroke-width=".21"/>
<circle cx="165.7" cy="113.8" r=".76" fill="#008000" stroke="#008000" stroke-width=".21"/>
<circle cx="165.7" cy="113.8" r=".47" fill="#fff" stroke="#000" stroke-width=".21"/>
<circle cx="131.9" cy="134.3" r=".68" fill="#008000" stroke="#008000" stroke-width=".21"/>
<circle cx="131.9" cy="134.3" r=".38" fill="#fff" stroke="#000" stroke-width=".21"/>
<circle cx="129.2" cy="115.3" r=".68" fill="#008000" stroke="#008000" stroke-width=".21"/>
<circle cx="129.2" cy="115.3" r=".38" fill="#fff" stroke="#000" stroke-width=".21"/>
<circle cx="126.4" cy="134.2" r=".68" fill="#008000" stroke="#008000" stroke-width=".21"/>
<circle cx="126.4" cy="134.2" r=".38" fill="#fff" stroke="#000" stroke-width=".21"/>
<circle cx="126.4" cy="127.7" r=".68" fill="#008000" stroke="#008000" stroke-width=".21"/>
<circle cx="126.4" cy="127.7" r=".38" fill="#fff" stroke="#000" stroke-width=".21"/>
<circle cx="137.4" cy="134.5" r=".68" fill="#008000" stroke="#008000" stroke-width=".21"/>
<circle cx="137.4" cy="134.5" r=".38" fill="#fff" stroke="#000" stroke-width=".21"/>
<circle cx="137.5" cy="128" r=".68" fill="#008000" stroke="#008000" stroke-width=".21"/>
<circle cx="137.5" cy="128" r=".38" fill="#fff" stroke="#000" stroke-width=".21"/>
<circle cx="135" cy="120.3" r=".68" fill="#008000" stroke="#008000" stroke-width=".21"/>
<circle cx="135" cy="120.3" r=".38" fill="#fff" stroke="#000" stroke-width=".21"/>
<circle cx="139.3" cy="116.1" r=".68" fill="#008000" stroke="#008000" stroke-width=".21"/>
<circle cx="139.3" cy="116.1" r=".38" fill="#fff" stroke="#000" stroke-width=".21"/>
<circle cx="137.2" cy="113.5" r=".68" fill="#008000" stroke="#008000" stroke-width=".21"/>
<circle cx="137.2" cy="113.5" r=".38" fill="#fff" stroke="#000" stroke-width=".21"/>
<circle cx="131" cy="88.3" r=".68" fill="#008000" stroke="#008000" stroke-width=".21"/>
<circle cx="131" cy="88.3" r=".38" fill="#fff" stroke="#000" stroke-width=".21"/>
<circle cx="129.8" cy="82.2" r=".68" fill="#008000" stroke="#008000" stroke-width=".21"/>
<circle cx="129.8" cy="82.2" r=".38" fill="#fff" stroke="#000" stroke-width=".21"/>
<circle cx="123.4" cy="39.5" r=".76" fill="#008000" stroke="#008000" stroke-width=".21"/>
<circle cx="123.4" cy="39.5" r=".47" fill="#fff" stroke="#000" stroke-width=".21"/>
<circle cx="129.7" cy="60.7" r=".68" fill="#008000" stroke="#008000" stroke-width=".21"/>
<circle cx="129.7" cy="60.7" r=".38" fill="#fff" stroke="#000" stroke-width=".21"/>
<circle cx="133.6" cy="62.8" r=".68" fill="#008000" stroke="#008000" stroke-width=".21"/>
<circle cx="133.6" cy="62.8" r=".38" fill="#fff" stroke="#000" stroke-width=".21"/>
<circle cx="133.6" cy="67.6" r=".68" fill="#008000" stroke="#008000" stroke-width=".21"/>
<circle cx="133.6" cy="67.6" r=".38" fill="#fff" stroke="#000" stroke-width=".21"/>
<circle cx="190.5" cy="101.4" r=".68" fill="#008000" stroke="#008000" stroke-width=".21"/>
<circle cx="190.5" cy="101.4" r=".38" fill="#fff" stroke="#000" stroke-width=".21"/>
<circle cx="146.7" cy="95.3" r=".68" fill="#008000" stroke="#008000" stroke-width=".21"/>
<circle cx="146.7" cy="95.3" r=".38" fill="#fff" stroke="#000" stroke-width=".21"/>
<circle cx="170.9" cy="61" r=".68" fill="#008000" stroke="#008000" stroke-width=".21"/>
<circle cx="170.9" cy="61" r=".38" fill="#fff" stroke="#000" stroke-width=".21"/>
<circle cx="171.5" cy="64.7" r=".68" fill="#008000" stroke="#008000" stroke-width=".21"/>
<circle cx="171.5" cy="64.7" r=".38" fill="#fff" stroke="#000" stroke-width=".21"/>
<circle cx="194.3" cy="64.7" r=".68" fill="#008000" stroke="#008000" stroke-width=".21"/>
<circle cx="194.3" cy="64.7" r=".38" fill="#fff" stroke="#000" stroke-width=".21"/>
<circle cx="199.2" cy="69.6" r=".68" fill="#008000" stroke="#008000" stroke-width=".21"/>
<circle cx="199.2" cy="69.6" r=".38" fill="#fff" stroke="#000" stroke-width=".21"/>
<circle cx="192.8" cy="88.4" r=".68" fill="#008000" stroke="#008000" stroke-width=".21"/>
<circle cx="192.8" cy="88.4" r=".38" fill="#fff" stroke="#000" stroke-width=".21"/>
<circle cx="165.1" cy="85.3" r=".68" fill="#008000" stroke="#008000" stroke-width=".21"/>
<circle cx="165.1" cy="85.3" r=".38" fill="#fff" stroke="#000" stroke-width=".21"/>
<circle cx="161.3" cy="85.5" r=".68" fill="#008000" stroke="#008000" stroke-width=".21"/>
<circle cx="161.3" cy="85.5" r=".38" fill="#fff" stroke="#000" stroke-width=".21"/>
<circle cx="156.8" cy="80.9" r=".68" fill="#008000" stroke="#008000" stroke-width=".21"/>
<circle cx="156.8" cy="80.9" r=".38" fill="#fff" stroke="#000" stroke-width=".21"/>
<circle cx="149.5" cy="80.9" r=".68" fill="#008000" stroke="#008000" stroke-width=".21"/>
<circle cx="149.5" cy="80.9" r=".38" fill="#fff" stroke="#000" stroke-width=".21"/>
<circle cx="136.5" cy="83.8" r=".68" fill="#008000" stroke="#008000" stroke-width=".21"/>
<circle cx="136.5" cy="83.8" r=".38" fill="#fff" stroke="#000" stroke-width=".21"/>
<circle cx="133.6" cy="83.9" r=".68" fill="#008000" stroke="#008000" stroke-width=".21"/>
<circle cx="133.6" cy="83.9" r=".38" fill="#fff" stroke="#000" stroke-width=".21"/>
<circle cx="133.6" cy="77.6" r=".68" fill="#008000" stroke="#008000" stroke-width=".21"/>
<circle cx="133.6" cy="77.6" r=".38" fill="#fff" stroke="#000" stroke-width=".21"/>
<circle cx="129.8" cy="77.7" r=".68" fill="#008000" stroke="#008000" stroke-width=".21"/>
<circle cx="129.8" cy="77.7" r=".38" fill="#fff" stroke="#000" stroke-width=".21"/>
<circle cx="124.6" cy="77.7" r=".68" fill="#008000" stroke="#008000" stroke-width=".21"/>
<circle cx="124.6" cy="77.7" r=".38" fill="#fff" stroke="#000" stroke-width=".21"/>
<circle cx="117.8" cy="71.7" r=".68" fill="#008000" stroke="#008000" stroke-width=".21"/>
<circle cx="117.8" cy="71.7" r=".38" fill="#fff" stroke="#000" stroke-width=".21"/>
<circle cx="154.7" cy="134.3" r=".68" fill="#008000" stroke="#008000" stroke-width=".21"/>
<circle cx="154.7" cy="134.3" r=".38" fill="#fff" stroke="#000" stroke-width=".21"/>
<circle cx="169.5" cy="107.5" r=".68" fill="#008000" stroke="#008000" stroke-width=".21"/>
<circle cx="169.5" cy="107.5" r=".38" fill="#fff" stroke="#000" stroke-width=".21"/>
<circle cx="106" cy="120.7" r=".68" fill="#008000" stroke="#008000" stroke-width=".21"/>
<circle cx="106" cy="120.7" r=".38" fill="#fff" stroke="#000" stroke-width=".21"/>
<circle cx="130.3" cy="125.9" r=".68" fill="#008000" stroke="#008000" stroke-width=".21"/>
<circle cx="130.3" cy="125.9" r=".38" fill="#fff" stroke="#000" stroke-width=".21"/>
<circle cx="133.8" cy="126" r=".68" fill="#008000" stroke="#008000" stroke-width=".21"/>
<circle cx="133.8" cy="126" r=".38" fill="#fff" stroke="#000" stroke-width=".21"/>
<circle cx="144.6" cy="126" r=".68" fill="#008000" stroke="#008000" stroke-width=".21"/>
<circle cx="144.6" cy="126" r=".38" fill="#fff" stroke="#000" stroke-width=".21"/>
<circle cx="147.5" cy="125.9" r=".68" fill="#008000" stroke="#008000" stroke-width=".21"/>
<circle cx="147.5" cy="125.9" r=".38" fill="#fff" stroke="#000" stroke-width=".21"/>
<circle cx="165.8" cy="134.4" r=".68" fill="#008000" stroke="#008000" stroke-width=".21"/>
<circle cx="165.8" cy="134.4" r=".38" fill="#fff" stroke="#000" stroke-width=".21"/>
<circle cx="172.3" cy="108.6" r=".68" fill="#008000" stroke="#008000" stroke-width=".21"/>
<circle cx="172.3" cy="108.6" r=".38" fill="#fff" stroke="#000" stroke-width=".21"/>
<circle cx="154" cy="113.6" r=".76" fill="#008000" stroke="#008000" stroke-width=".21"/>
<circle cx="154" cy="113.6" r=".44" fill="#fff" stroke="#000" stroke-width=".21"/>
<circle cx="147.5" cy="113.6" r=".68" fill="#008000" stroke="#008000" stroke-width=".21"/>
<circle cx="147.5" cy="113.6" r=".38" fill="#fff" stroke="#000" stroke-width=".21"/>
<circle cx="144.7" cy="113.7" r=".68" fill="#008000" stroke="#008000" stroke-width=".21"/>
<circle cx="144.7" cy="113.7" r=".38" fill="#fff" stroke="#000" stroke-width=".21"/>
<circle cx="133.5" cy="117.7" r=".68" fill="#008000" stroke="#008000" stroke-width=".21"/>
<circle cx="133.5" cy="117.7" r=".38" fill="#fff" stroke="#000" stroke-width=".21"/>
<circle cx="128.5" cy="117.7" r=".68" fill="#008000" stroke="#008000" stroke-width=".21"/>
<circle cx="128.5" cy="117.7" r=".38" fill="#fff" stroke="#000" stroke-width=".21"/>
<circle cx="115.5" cy="105.4" r=".76" fill="#008000" stroke="#008000" stroke-width=".21"/>
<circle cx="115.5" cy="105.4" r=".44" fill="#fff" stroke="#000" stroke-width=".21"/>
<circle cx="119.1" cy="100.4" r=".68" fill="#008000" stroke="#008000" stroke-width=".21"/>
<circle cx="119.1" cy="100.4" r=".38" fill="#fff" stroke="#000" stroke-width=".21"/>
<circle cx="126.8" cy="67.7" r=".68" fill="#008000" stroke="#008000" stroke-width=".21"/>
<circle cx="126.8" cy="67.7" r=".38" fill="#fff" stroke="#000" stroke-width=".21"/>
<circle cx="124.6" cy="70.6" r=".68" fill="#008000" stroke="#008000" stroke-width=".21"/>
<circle cx="124.6" cy="70.6" r=".38" fill="#fff" stroke="#000" stroke-width=".21"/>
<circle cx="116" cy="69" r=".68" fill="#008000" stroke="#008000" stroke-width=".21"/>
<circle cx="116" cy="69" r=".38" fill="#fff" stroke="#000" stroke-width=".21"/>
<circle cx="160.2" cy="134.5" r=".68" fill="#008000" stroke="#008000" stroke-width=".21"/>
<circle cx="160.2" cy="134.5" r=".38" fill="#fff" stroke="#000" stroke-width=".21"/>
<circle cx="160.2" cy="128" r=".68" fill="#008000" stroke="#008000" stroke-width=".21"/>
<circle cx="160.2" cy="128" r=".38" fill="#fff" stroke="#000" stroke-width=".21"/>
<circle cx="110.1" cy="117.8" r=".68" fill="#008000" stroke="#008000" stroke-width=".21"/>
<circle cx="110.1" cy="117.8" r=".38" fill="#fff" stroke="#000" stroke-width=".21"/>
<circle cx="130.2" cy="121.9" r=".68" fill="#008000" stroke="#008000" stroke-width=".21"/>
<circle cx="130.2" cy="121.9" r=".38" fill="#fff" stroke="#000" stroke-width=".21"/>
<circle cx="134" cy="122" r=".68" fill="#008000" stroke="#008000" stroke-width=".21"/>
<circle cx="134" cy="122" r=".38" fill="#fff" stroke="#000" stroke-width=".21"/>
<circle cx="144.7" cy="121.9" r=".68" fill="#008000" stroke="#008000" stroke-width=".21"/>
<circle cx="144.7" cy="121.9" r=".38" fill="#fff" stroke="#000" stroke-width=".21"/>
<circle cx="147.5" cy="122" r=".68" fill="#008000" stroke="#008000" stroke-width=".21"/>
<circle cx="147.5" cy="122" r=".38" fill="#fff" stroke="#000" stroke-width=".21"/>
<circle cx="151.2" cy="124.2" r=".76" fill="#008000" stroke="#008000" stroke-width=".21"/>
<circle cx="151.2" cy="124.2" r=".44" fill="#fff" stroke="#000" stroke-width=".21"/>
<circle cx="149" cy="134.3" r=".68" fill="#008000" stroke="#008000" stroke-width=".21"/>
<circle cx="149" cy="134.3" r=".38" fill="#fff" stroke="#000" stroke-width=".21"/>
<circle cx="149" cy="128" r=".68" fill="#008000" stroke="#008000" stroke-width=".21"/>
<circle cx="149" cy="128" r=".38" fill="#fff" stroke="#000" stroke-width=".21"/>
<circle cx="108.3" cy="119.3" r=".68" fill="#008000" stroke="#008000" stroke-width=".21"/>
<circle cx="108.3" cy="119.3" r=".38" fill="#fff" stroke="#000" stroke-width=".21"/>
<circle cx="130.2" cy="124.2" r=".76" fill="#008000" stroke="#008000" stroke-width=".21"/>
<circle cx="130.2" cy="124.2" r=".44" fill="#fff" stroke="#000" stroke-width=".21"/>
<circle cx="134.1" cy="124.1" r=".68" fill="#008000" stroke="#008000" stroke-width=".21"/>
<circle cx="134.1" cy="124.1" r=".38" fill="#fff" stroke="#000" stroke-width=".21"/>
<circle cx="144.5" cy="124" r=".68" fill="#008000" stroke="#008000" stroke-width=".21"/>
<circle cx="144.5" cy="124" r=".38" fill="#fff" stroke="#000" stroke-width=".21"/>
<circle cx="192" cy="103.5" r=".68" fill="#008000" stroke="#008000" stroke-width=".21"/>
<circle cx="192" cy="103.5" r=".38" fill="#fff" stroke="#000" stroke-width=".21"/>
<circle cx="159.9" cy="65.6" r=".68" fill="#008000" stroke="#008000" stroke-width=".21"/>
<circle cx="159.9" cy="65.6" r=".38" fill="#fff" stroke="#000" stroke-width=".21"/>
<circle cx="165.1" cy="88.2" r=".68" fill="#008000" stroke="#008000" stroke-width=".21"/>
<circle cx="165.1" cy="88.2" r=".38" fill="#fff" stroke="#000" stroke-width=".21"/>
<circle cx="169.3" cy="94.9" r=".76" fill="#008000" stroke="#008000" stroke-width=".21"/>
<circle cx="169.3" cy="94.9" r=".47" fill="#fff" stroke="#000" stroke-width=".21"/>
<circle cx="136.8" cy="107.9" r=".68" fill="#008000" stroke="#008000" stroke-width=".21"/>
<circle cx="136.8" cy="107.9" r=".38" fill="#fff" stroke="#000" stroke-width=".21"/>
<circle cx="120.8" cy="112.9" r=".68" fill="#008000" stroke="#008000" stroke-width=".21"/>
<circle cx="120.8" cy="112.9" r=".38" fill="#fff" stroke="#000" stroke-width=".21"/>
<circle cx="182.4" cy="134.3" r=".68" fill="#008000" stroke="#008000" stroke-width=".21"/>
<circle cx="182.4" cy="134.3" r=".38" fill="#fff" stroke="#000" stroke-width=".21"/>
<circle cx="182.3" cy="127.7" r=".68" fill="#008000" stroke="#008000" stroke-width=".21"/>
<circle cx="182.3" cy="127.7" r=".38" fill="#fff" stroke="#000" stroke-width=".21"/>
<circle cx="102.6" cy="91.5" r=".68" fill="#008000" stroke="#008000" stroke-width=".21"/>
<circle cx="102.6" cy="91.5" r=".38" fill="#fff" stroke="#000" stroke-width=".21"/>
<circle cx="111.5" cy="131.7" r=".68" fill="#008000" stroke="#008000" stroke-width=".21"/>
<circle cx="111.5" cy="131.7" r=".38" fill="#fff" stroke="#000" stroke-width=".21"/>
<circle cx="143.3" cy="134.5" r=".68" fill="#008000" stroke="#008000" stroke-width=".21"/>
<circle cx="143.3" cy="134.5" r=".38" fill="#fff" stroke="#000" stroke-width=".21"/>
<circle cx="143.2" cy="127.4" r=".76" fill="#008000" stroke="#008000" stroke-width=".21"/>
<circle cx="143.2" cy="127.4" r=".44" fill="#fff" stroke="#000" stroke-width=".21"/>
<circle cx="118" cy="114.2" r=".68" fill="#008000" stroke="#008000" stroke-width=".21"/>
<circle cx="118" cy="114.2" r=".38" fill="#fff" stroke="#000" stroke-width=".21"/>
<circle cx="138.9" cy="107.9" r=".68" fill="#008000" stroke="#008000" stroke-width=".21"/>
<circle cx="138.9" cy="107.9" r=".38" fill="#fff" stroke="#000" stroke-width=".21"/>
<circle cx="129.7" cy="108.2" r=".68" fill="#008000" stroke="#008000" stroke-width=".21"/>
<circle cx="129.7" cy="108.2" r=".38" fill="#fff" stroke="#000" stroke-width=".21"/>
<circle cx="100.9" cy="117.1" r=".68" fill="#008000" stroke="#008000" stroke-width=".21"/>
<circle cx="100.9" cy="117.1" r=".38" fill="#fff" stroke="#000" stroke-width=".21"/>
<circle cx="118" cy="110.8" r=".44" fill="#008000" stroke="#008000" stroke-width=".21"/>
<circle cx="118" cy="110.8" r=".15" fill="#fff" stroke="#000" stroke-width=".21"/>
<circle cx="103.4" cy="114.6" r=".68" fill="#008000" stroke="#008000" stroke-width=".21"/>
<circle cx="103.4" cy="114.6" r=".38" fill="#fff" stroke="#000" stroke-width=".21"/>
<circle cx="103" cy="125.5" r=".68" fill="#008000" stroke="#008000" stroke-width=".21"/>
<circle cx="103" cy="125.5" r=".38" fill="#fff" stroke="#000" stroke-width=".21"/>
<circle cx="98.8" cy="125.6" r=".68" fill="#008000" stroke="#008000" stroke-width=".21"/>
<circle cx="98.8" cy="125.6" r=".38" fill="#fff" stroke="#000" stroke-width=".21"/>
<circle cx="180" cy="56.2" r=".68" fill="#008000" stroke="#008000" stroke-width=".21"/>
<circle cx="180" cy="56.2" r=".38" fill="#fff" stroke="#000" stroke-width=".21"/>
<circle cx="178.5" cy="53.4" r=".68" fill="#008000" stroke="#008000" stroke-width=".21"/>
<circle cx="178.5" cy="53.4" r=".38" fill="#fff" stroke="#000" stroke-width=".21"/>
<circle cx="159.9" cy="61.4" r=".76" fill="#008000" stroke="#008000" stroke-width=".21"/>
<circle cx="159.9" cy="61.4" r=".47" fill="#fff" stroke="#000" stroke-width=".21"/>
<circle cx="158.1" cy="70.3" r=".76" fill="#008000" stroke="#008000" stroke-width=".21"/>
<circle cx="158.1" cy="70.3" r=".47" fill="#fff" stroke="#000" stroke-width=".21"/>
<circle cx="160.8" cy="106.4" r=".76" fill="#008000" stroke="#008000" stroke-width=".21"/>
<circle cx="160.8" cy="106.4" r=".47" fill="#fff" stroke="#000" stroke-width=".21"/>
<circle cx="157.6" cy="43.1" r=".76" fill="#008000" stroke="#008000" stroke-width=".21"/>
<circle cx="157.6" cy="43.1" r=".44" fill="#fff" stroke="#000" stroke-width=".21"/>
<circle cx="177.5" cy="109.3" r=".76" fill="#008000" stroke="#008000" stroke-width=".21"/>
<circle cx="177.5" cy="109.3" r=".44" fill="#fff" stroke="#000" stroke-width=".21"/>
<circle cx="153.4" cy="83" r=".68" fill="#008000" stroke="#008000" stroke-width=".21"/>
<circle cx="153.4" cy="83" r=".38" fill="#fff" stroke="#000" stroke-width=".21"/>
<circle cx="167.5" cy="85.1" r=".68" fill="#008000" stroke="#008000" stroke-width=".21"/>
<circle cx="167.5" cy="85.1" r=".38" fill="#fff" stroke="#000" stroke-width=".21"/>
<circle cx="196.3" cy="88.4" r=".68" fill="#008000" stroke="#008000" stroke-width=".21"/>
<circle cx="196.3" cy="88.4" r=".38" fill="#fff" stroke="#000" stroke-width=".21"/>
<circle cx="207" cy="96.4" r=".68" fill="#008000" stroke="#008000" stroke-width=".21"/>
<circle cx="207" cy="96.4" r=".38" fill="#fff" stroke="#000" stroke-width=".21"/>
<circle cx="186.6" cy="149.9" r=".68" fill="#008000" stroke="#008000" stroke-width=".21"/>
<circle cx="186.6" cy="149.9" r=".38" fill="#fff" stroke="#000" stroke-width=".21"/>
<circle cx="130.9" cy="93.9" r=".68" fill="#008000" stroke="#008000" stroke-width=".21"/>
<circle cx="130.9" cy="93.9" r=".38" fill="#fff" stroke="#000" stroke-width=".21"/>
<circle cx="153.1" cy="93.7" r=".68" fill="#008000" stroke="#008000" stroke-width=".21"/>
<circle cx="153.1" cy="93.7" r=".38" fill="#fff" stroke="#000" stroke-width=".21"/>
<circle cx="153.1" cy="88.5" r=".68" fill="#008000" stroke="#008000" stroke-width=".21"/>
<circle cx="153.1" cy="88.5" r=".38" fill="#fff" stroke="#000" stroke-width=".21"/>
<circle cx="142.5" cy="82.4" r=".68" fill="#008000" stroke="#008000" stroke-width=".21"/>
<circle cx="142.5" cy="82.4" r=".38" fill="#fff" stroke="#000" stroke-width=".21"/>
<circle cx="159.4" cy="58.9" r=".68" fill="#008000" stroke="#008000" stroke-width=".21"/>
<circle cx="159.4" cy="58.9" r=".38" fill="#fff" stroke="#000" stroke-width=".21"/>
<circle cx="212.2" cy="129.4" r=".68" fill="#008000" stroke="#008000" stroke-width=".21"/>
<circle cx="212.2" cy="129.4" r=".38" fill="#fff" stroke="#000" stroke-width=".21"/>
<circle cx="185.4" cy="146.9" r=".68" fill="#008000" stroke="#008000" stroke-width=".21"/>
<circle cx="185.4" cy="146.9" r=".38" fill="#fff" stroke="#000" stroke-width=".21"/>
<circle cx="156.6" cy="76.8" r=".68" fill="#008000" stroke="#008000" stroke-width=".21"/>
<circle cx="156.6" cy="76.8" r=".38" fill="#fff" stroke="#000" stroke-width=".21"/>
<circle cx="100.1" cy="142.7" r=".68" fill="#008000" stroke="#008000" stroke-width=".21"/>
<circle cx="100.1" cy="142.7" r=".38" fill="#fff" stroke="#000" stroke-width=".21"/>
<circle cx="110.6" cy="136.5" r=".68" fill="#008000" stroke="#008000" stroke-width=".21"/>
<circle cx="110.6" cy="136.5" r=".38" fill="#fff" stroke="#000" stroke-width=".21"/>
<circle cx="149.4" cy="76" r=".68" fill="#008000" stroke="#008000" stroke-width=".21"/>
<circle cx="149.4" cy="76" r=".38" fill="#fff" stroke="#000" stroke-width=".21"/>
<circle cx="143.3" cy="73.9" r=".68" fill="#008000" stroke="#008000" stroke-width=".21"/>
<circle cx="143.3" cy="73.9" r=".38" fill="#fff" stroke="#000" stroke-width=".21"/>
<circle cx="143.4" cy="65.6" r=".68" fill="#008000" stroke="#008000" stroke-width=".21"/>
<circle cx="143.4" cy="65.6" r=".38" fill="#fff" stroke="#000" stroke-width=".21"/>
<circle cx="137.6" cy="65.6" r=".68" fill="#008000" stroke="#008000" stroke-width=".21"/>
<circle cx="137.6" cy="65.6" r=".38" fill="#fff" stroke="#000" stroke-width=".21"/>
<circle cx="129.7" cy="68.2" r=".68" fill="#008000" stroke="#008000" stroke-width=".21"/>
<circle cx="129.7" cy="68.2" r=".38" fill="#fff" stroke="#000" stroke-width=".21"/>
<circle cx="124.6" cy="74.9" r=".68" fill="#008000" stroke="#008000" stroke-width=".21"/>
<circle cx="124.6" cy="74.9" r=".38" fill="#fff" stroke="#000" stroke-width=".21"/>
<circle cx="182.6" cy="70.4" r=".68" fill="#008000" stroke="#008000" stroke-width=".21"/>
<circle cx="182.6" cy="70.4" r=".38" fill="#fff" stroke="#000" stroke-width=".21"/>
<circle cx="182.5" cy="76.6" r=".68" fill="#008000" stroke="#008000" stroke-width=".21"/>
<circle cx="182.5" cy="76.6" r=".38" fill="#fff" stroke="#000" stroke-width=".21"/>
<circle cx="182.5" cy="79.4" r=".68" fill="#008000" stroke="#008000" stroke-width=".21"/>
<circle cx="182.5" cy="79.4" r=".38" fill="#fff" stroke="#000" stroke-width=".21"/>
<circle cx="194.1" cy="136.4" r=".68" fill="#008000" stroke="#008000" stroke-width=".21"/>
<circle cx="194.1" cy="136.4" r=".38" fill="#fff" stroke="#000" stroke-width=".21"/>
<circle cx="195" cy="114.4" r=".68" fill="#008000" stroke="#008000" stroke-width=".21"/>
<circle cx="195" cy="114.4" r=".38" fill="#fff" stroke="#000" stroke-width=".21"/>
<circle cx="175.1" cy="62.7" r=".68" fill="#008000" stroke="#008000" stroke-width=".21"/>
<circle cx="175.1" cy="62.7" r=".38" fill="#fff" stroke="#000" stroke-width=".21"/>
<circle cx="179.5" cy="62.5" r=".68" fill="#008000" stroke="#008000" stroke-width=".21"/>
<circle cx="179.5" cy="62.5" r=".38" fill="#fff" stroke="#000" stroke-width=".21"/>
<circle cx="179.6" cy="70.3" r=".68" fill="#008000" stroke="#008000" stroke-width=".21"/>
<circle cx="179.6" cy="70.3" r=".38" fill="#fff" stroke="#000" stroke-width=".21"/>
<circle cx="179.6" cy="76.6" r=".68" fill="#008000" stroke="#008000" stroke-width=".21"/>
<circle cx="179.6" cy="76.6" r=".38" fill="#fff" stroke="#000" stroke-width=".21"/>
<circle cx="179.6" cy="79.4" r=".68" fill="#008000" stroke="#008000" stroke-width=".21"/>
<circle cx="179.6" cy="79.4" r=".38" fill="#fff" stroke="#000" stroke-width=".21"/>
<circle cx="179.5" cy="93.8" r=".76" fill="#008000" stroke="#008000" stroke-width=".21"/>
<circle cx="179.5" cy="93.8" r=".44" fill="#fff" stroke="#000" stroke-width=".21"/>
<circle cx="189.3" cy="93.9" r=".68" fill="#008000" stroke="#008000" stroke-width=".21"/>
<circle cx="189.3" cy="93.9" r=".38" fill="#fff" stroke="#000" stroke-width=".21"/>
<circle cx="187.7" cy="70.2" r=".68" fill="#008000" stroke="#008000" stroke-width=".21"/>
<circle cx="187.7" cy="70.2" r=".38" fill="#fff" stroke="#000" stroke-width=".21"/>
<circle cx="187.7" cy="76.7" r=".68" fill="#008000" stroke="#008000" stroke-width=".21"/>
<circle cx="187.7" cy="76.7" r=".38" fill="#fff" stroke="#000" stroke-width=".21"/>
<circle cx="187.7" cy="79.4" r=".68" fill="#008000" stroke="#008000" stroke-width=".21"/>
<circle cx="187.7" cy="79.4" r=".38" fill="#fff" stroke="#000" stroke-width=".21"/>
<circle cx="192.3" cy="70.2" r=".68" fill="#008000" stroke="#008000" stroke-width=".21"/>
<circle cx="192.3" cy="70.2" r=".38" fill="#fff" stroke="#000" stroke-width=".21"/>
<circle cx="192.2" cy="76.6" r=".68" fill="#008000" stroke="#008000" stroke-width=".21"/>
<circle cx="192.2" cy="76.6" r=".38" fill="#fff" stroke="#000" stroke-width=".21"/>
<circle cx="192.2" cy="79.4" r=".68" fill="#008000" stroke="#008000" stroke-width=".21"/>
<circle cx="192.2" cy="79.4" r=".38" fill="#fff" stroke="#000" stroke-width=".21"/>
<circle cx="167.5" cy="74.4" r=".68" fill="#008000" stroke="#008000" stroke-width=".21"/>
<circle cx="167.5" cy="74.4" r=".38" fill="#fff" stroke="#000" stroke-width=".21"/>
<circle cx="159.7" cy="75.1" r=".68" fill="#008000" stroke="#008000" stroke-width=".21"/>
<circle cx="159.7" cy="75.1" r=".38" fill="#fff" stroke="#000" stroke-width=".21"/>
<circle cx="130.1" cy="146.5" r=".68" fill="#008000" stroke="#008000" stroke-width=".21"/>
<circle cx="130.1" cy="146.5" r=".38" fill="#fff" stroke="#000" stroke-width=".21"/>
<circle cx="147.9" cy="105.1" r=".68" fill="#008000" stroke="#008000" stroke-width=".21"/>
<circle cx="147.9" cy="105.1" r=".38" fill="#fff" stroke="#000" stroke-width=".21"/>
<circle cx="168.1" cy="104.5" r=".76" fill="#008000" stroke="#008000" stroke-width=".21"/>
<circle cx="168.1" cy="104.5" r=".44" fill="#fff" stroke="#000" stroke-width=".21"/>
<circle cx="187.6" cy="104.2" r=".68" fill="#008000" stroke="#008000" stroke-width=".21"/>
<circle cx="187.6" cy="104.2" r=".38" fill="#fff" stroke="#000" stroke-width=".21"/>
<circle cx="133" cy="88.5" r=".68" fill="#008000" stroke="#008000" stroke-width=".21"/>
<circle cx="133" cy="88.5" r=".38" fill="#fff" stroke="#000" stroke-width=".21"/>
<circle cx="143.8" cy="110.7" r=".68" fill="#008000" stroke="#008000" stroke-width=".21"/>
<circle cx="143.8" cy="110.7" r=".38" fill="#fff" stroke="#000" stroke-width=".21"/>
<circle cx="147.3" cy="109" r=".68" fill="#008000" stroke="#008000" stroke-width=".21"/>
<circle cx="147.3" cy="109" r=".38" fill="#fff" stroke="#000" stroke-width=".21"/>
<circle cx="188.8" cy="144.5" r=".68" fill="#008000" stroke="#008000" stroke-width=".21"/>
<circle cx="188.8" cy="144.5" r=".38" fill="#fff" stroke="#000" stroke-width=".21"/>
<circle cx="192" cy="121.6" r=".68" fill="#008000" stroke="#008000" stroke-width=".21"/>
<circle cx="192" cy="121.6" r=".38" fill="#fff" stroke="#000" stroke-width=".21"/>
<circle cx="127.2" cy="145.4" r=".68" fill="#008000" stroke="#008000" stroke-width=".21"/>
<circle cx="127.2" cy="145.4" r=".38" fill="#fff" stroke="#000" stroke-width=".21"/>
<circle cx="150.5" cy="103.6" r=".68" fill="#008000" stroke="#008000" stroke-width=".21"/>
<circle cx="150.5" cy="103.6" r=".38" fill="#fff" stroke="#000" stroke-width=".21"/>
<circle cx="164.9" cy="102.8" r=".76" fill="#008000" stroke="#008000" stroke-width=".21"/>
<circle cx="164.9" cy="102.8" r=".44" fill="#fff" stroke="#000" stroke-width=".21"/>
<circle cx="138" cy="88.4" r=".68" fill="#008000" stroke="#008000" stroke-width=".21"/>
<circle cx="138" cy="88.4" r=".38" fill="#fff" stroke="#000" stroke-width=".21"/>
<circle cx="153.8" cy="97.9" r=".68" fill="#008000" stroke="#008000" stroke-width=".21"/>
<circle cx="153.8" cy="97.9" r=".38" fill="#fff" stroke="#000" stroke-width=".21"/>
<circle cx="161.2" cy="95.6" r=".76" fill="#008000" stroke="#008000" stroke-width=".21"/>
<circle cx="161.2" cy="95.6" r=".47" fill="#fff" stroke="#000" stroke-width=".21"/>
<circle cx="188.9" cy="102.5" r=".68" fill="#008000" stroke="#008000" stroke-width=".21"/>
<circle cx="188.9" cy="102.5" r=".38" fill="#fff" stroke="#000" stroke-width=".21"/>
<circle cx="168.3" cy="102.4" r=".76" fill="#008000" stroke="#008000" stroke-width=".21"/>
<circle cx="168.3" cy="102.4" r=".44" fill="#fff" stroke="#000" stroke-width=".21"/>
<circle cx="155.3" cy="88.2" r=".68" fill="#008000" stroke="#008000" stroke-width=".21"/>
<circle cx="155.3" cy="88.2" r=".38" fill="#fff" stroke="#000" stroke-width=".21"/>
<circle cx="207.8" cy="128" r=".68" fill="#008000" stroke="#008000" stroke-width=".21"/>
<circle cx="207.8" cy="128" r=".38" fill="#fff" stroke="#000" stroke-width=".21"/>
<circle cx="202.1" cy="155.3" r=".68" fill="#008000" stroke="#008000" stroke-width=".21"/>
<circle cx="202.1" cy="155.3" r=".38" fill="#fff" stroke="#000" stroke-width=".21"/>
<circle cx="196.1" cy="155.2" r=".68" fill="#008000" stroke="#008000" stroke-width=".21"/>
<circle cx="196.1" cy="155.2" r=".38" fill="#fff" stroke="#000" stroke-width=".21"/>
<circle cx="142.9" cy="169.5" r=".68" fill="#008000" stroke="#008000" stroke-width=".21"/>
<circle cx="142.9" cy="169.5" r=".38" fill="#fff" stroke="#000" stroke-width=".21"/>
<circle cx="109.3" cy="168.7" r=".68" fill="#008000" stroke="#008000" stroke-width=".21"/>
<circle cx="109.3" cy="168.7" r=".38" fill="#fff" stroke="#000" stroke-width=".21"/>
<circle cx="104.4" cy="112.6" r=".68" fill="#008000" stroke="#008000" stroke-width=".21"/>
<circle cx="104.4" cy="112.6" r=".38" fill="#fff" stroke="#000" stroke-width=".21"/>
<circle cx="117.9" cy="108.6" r=".68" fill="#008000" stroke="#008000" stroke-width=".21"/>
<circle cx="117.9" cy="108.6" r=".38" fill="#fff" stroke="#000" stroke-width=".21"/>
<circle cx="120.4" cy="106.5" r=".68" fill="#008000" stroke="#008000" stroke-width=".21"/>
<circle cx="120.4" cy="106.5" r=".38" fill="#fff" stroke="#000" stroke-width=".21"/>
<circle cx="131.6" cy="100.3" r=".68" fill="#008000" stroke="#008000" stroke-width=".21"/>
<circle cx="131.6" cy="100.3" r=".38" fill="#fff" stroke="#000" stroke-width=".21"/>
<circle cx="141.4" cy="100.8" r=".76" fill="#008000" stroke="#008000" stroke-width=".21"/>
<circle cx="141.4" cy="100.8" r=".47" fill="#fff" stroke="#000" stroke-width=".21"/>
<circle cx="135.2" cy="88.2" r=".68" fill="#008000" stroke="#008000" stroke-width=".21"/>
<circle cx="135.2" cy="88.2" r=".38" fill="#fff" stroke="#000" stroke-width=".21"/>
<circle cx="132.7" cy="53.6" r=".76" fill="#008000" stroke="#008000" stroke-width=".21"/>
<circle cx="132.7" cy="53.6" r=".47" fill="#fff" stroke="#000" stroke-width=".21"/>
<circle cx="137.6" cy="63.2" r=".68" fill="#008000" stroke="#008000" stroke-width=".21"/>
<circle cx="137.6" cy="63.2" r=".38" fill="#fff" stroke="#000" stroke-width=".21"/>
<circle cx="142.6" cy="63.3" r=".68" fill="#008000" stroke="#008000" stroke-width=".21"/>
<circle cx="142.6" cy="63.3" r=".38" fill="#fff" stroke="#000" stroke-width=".21"/>
<circle cx="142.4" cy="55.1" r=".68" fill="#008000" stroke="#008000" stroke-width=".21"/>
<circle cx="142.4" cy="55.1" r=".38" fill="#fff" stroke="#000" stroke-width=".21"/>
<circle cx="107" cy="141.2" r=".68" fill="#008000" stroke="#008000" stroke-width=".21"/>
<circle cx="107" cy="141.2" r=".38" fill="#fff" stroke="#000" stroke-width=".21"/>
<circle cx="104.2" cy="138.1" r=".68" fill="#008000" stroke="#008000" stroke-width=".21"/>
<circle cx="104.2" cy="138.1" r=".38" fill="#fff" stroke="#000" stroke-width=".21"/>
<circle cx="184.8" cy="101.7" r=".68" fill="#008000" stroke="#008000" stroke-width=".21"/>
<circle cx="184.8" cy="101.7" r=".38" fill="#fff" stroke="#000" stroke-width=".21"/>
<circle cx="118.2" cy="95.8" r=".68" fill="#008000" stroke="#008000" stroke-width=".21"/>
<circle cx="118.2" cy="95.8" r=".38" fill="#fff" stroke="#000" stroke-width=".21"/>
<circle cx="121.8" cy="87.8" r=".76" fill="#008000" stroke="#008000" stroke-width=".21"/>
<circle cx="121.8" cy="87.8" r=".44" fill="#fff" stroke="#000" stroke-width=".21"/>
<circle cx="170.8" cy="69.8" r=".68" fill="#008000" stroke="#008000" stroke-width=".21"/>
<circle cx="170.8" cy="69.8" r=".38" fill="#fff" stroke="#000" stroke-width=".21"/>
<circle cx="171.3" cy="76.5" r=".68" fill="#008000" stroke="#008000" stroke-width=".21"/>
<circle cx="171.3" cy="76.5" r=".38" fill="#fff" stroke="#000" stroke-width=".21"/>
<circle cx="171.3" cy="79.4" r=".68" fill="#008000" stroke="#008000" stroke-width=".21"/>
<circle cx="171.3" cy="79.4" r=".38" fill="#fff" stroke="#000" stroke-width=".21"/>
<circle cx="193.5" cy="101.1" r=".68" fill="#008000" stroke="#008000" stroke-width=".21"/>
<circle cx="193.5" cy="101.1" r=".38" fill="#fff" stroke="#000" stroke-width=".21"/>
<circle cx="171.2" cy="95.8" r=".76" fill="#008000" stroke="#008000" stroke-width=".21"/>
<circle cx="171.2" cy="95.8" r=".44" fill="#fff" stroke="#000" stroke-width=".21"/>
<circle cx="173.8" cy="72.2" r=".68" fill="#008000" stroke="#008000" stroke-width=".21"/>
<circle cx="173.8" cy="72.2" r=".38" fill="#fff" stroke="#000" stroke-width=".21"/>
<circle cx="173.8" cy="76.5" r=".68" fill="#008000" stroke="#008000" stroke-width=".21"/>
<circle cx="173.8" cy="76.5" r=".38" fill="#fff" stroke="#000" stroke-width=".21"/>
<circle cx="173.8" cy="79.4" r=".68" fill="#008000" stroke="#008000" stroke-width=".21"/>
<circle cx="173.8" cy="79.4" r=".38" fill="#fff" stroke="#000" stroke-width=".21"/>
<circle cx="196.2" cy="102.1" r=".68" fill="#008000" stroke="#008000" stroke-width=".21"/>
<circle cx="196.2" cy="102.1" r=".38" fill="#fff" stroke="#000" stroke-width=".21"/>
<circle cx="173.8" cy="94.8" r=".76" fill="#008000" stroke="#008000" stroke-width=".21"/>
<circle cx="173.8" cy="94.8" r=".44" fill="#fff" stroke="#000" stroke-width=".21"/>
<circle cx="176.9" cy="70.4" r=".68" fill="#008000" stroke="#008000" stroke-width=".21"/>
<circle cx="176.9" cy="70.4" r=".38" fill="#fff" stroke="#000" stroke-width=".21"/>
<circle cx="176.9" cy="76.7" r=".68" fill="#008000" stroke="#008000" stroke-width=".21"/>
<circle cx="176.9" cy="76.7" r=".38" fill="#fff" stroke="#000" stroke-width=".21"/>
<circle cx="176.9" cy="79.4" r=".68" fill="#008000" stroke="#008000" stroke-width=".21"/>
<circle cx="176.9" cy="79.4" r=".38" fill="#fff" stroke="#000" stroke-width=".21"/>
<circle cx="198.1" cy="102.1" r=".68" fill="#008000" stroke="#008000" stroke-width=".21"/>
<circle cx="198.1" cy="102.1" r=".38" fill="#fff" stroke="#000" stroke-width=".21"/>
<circle cx="177.5" cy="94.1" r=".76" fill="#008000" stroke="#008000" stroke-width=".21"/>
<circle cx="177.5" cy="94.1" r=".44" fill="#fff" stroke="#000" stroke-width=".21"/>
<circle cx="205.6" cy="120.2" r=".68" fill="#008000" stroke="#008000" stroke-width=".21"/>
<circle cx="205.6" cy="120.2" r=".38" fill="#fff" stroke="#000" stroke-width=".21"/>
<circle cx="208.2" cy="122.2" r=".68" fill="#008000" stroke="#008000" stroke-width=".21"/>
<circle cx="208.2" cy="122.2" r=".38" fill="#fff" stroke="#000" stroke-width=".21"/>
<circle cx="104.5" cy="102.5" r=".68" fill="#008000" stroke="#008000" stroke-width=".21"/>
<circle cx="104.5" cy="102.5" r=".38" fill="#fff" stroke="#000" stroke-width=".21"/>
<circle cx="113.9" cy="82.4" r=".68" fill="#008000" stroke="#008000" stroke-width=".21"/>
<circle cx="113.9" cy="82.4" r=".38" fill="#fff" stroke="#000" stroke-width=".21"/>
<circle cx="102.7" cy="139.3" r=".68" fill="#008000" stroke="#008000" stroke-width=".21"/>
<circle cx="102.7" cy="139.3" r=".38" fill="#fff" stroke="#000" stroke-width=".21"/>
<circle cx="149.5" cy="145.7" r=".68" fill="#008000" stroke="#008000" stroke-width=".21"/>
<circle cx="149.5" cy="145.7" r=".38" fill="#fff" stroke="#000" stroke-width=".21"/>
<circle cx="210.5" cy="113.8" r=".68" fill="#008000" stroke="#008000" stroke-width=".21"/>
<circle cx="210.5" cy="113.8" r=".38" fill="#fff" stroke="#000" stroke-width=".21"/>
<circle cx="199.2" cy="164.7" r=".68" fill="#008000" stroke="#008000" stroke-width=".21"/>
<circle cx="199.2" cy="164.7" r=".38" fill="#fff" stroke="#000" stroke-width=".21"/>
<circle cx="194.4" cy="160.4" r=".68" fill="#008000" stroke="#008000" stroke-width=".21"/>
<circle cx="194.4" cy="160.4" r=".38" fill="#fff" stroke="#000" stroke-width=".21"/>
<circle cx="191" cy="87.5" r=".68" fill="#008000" stroke="#008000" stroke-width=".21"/>
<circle cx="191" cy="87.5" r=".38" fill="#fff" stroke="#000" stroke-width=".21"/>
<circle cx="169.7" cy="87.3" r=".68" fill="#008000" stroke="#008000" stroke-width=".21"/>
<circle cx="169.7" cy="87.3" r=".38" fill="#fff" stroke="#000" stroke-width=".21"/>
<circle cx="149.5" cy="79.1" r=".68" fill="#008000" stroke="#008000" stroke-width=".21"/>
<circle cx="149.5" cy="79.1" r=".38" fill="#fff" stroke="#000" stroke-width=".21"/>
<circle cx="199.5" cy="107.4" r=".76" fill="#008000" stroke="#008000" stroke-width=".21"/>
<circle cx="199.5" cy="107.4" r=".47" fill="#fff" stroke="#000" stroke-width=".21"/>
<circle cx="180" cy="107.4" r=".68" fill="#008000" stroke="#008000" stroke-width=".21"/>
<circle cx="180" cy="107.4" r=".38" fill="#fff" stroke="#000" stroke-width=".21"/>
<circle cx="151.5" cy="65.6" r=".68" fill="#008000" stroke="#008000" stroke-width=".21"/>
<circle cx="151.5" cy="65.6" r=".38" fill="#fff" stroke="#000" stroke-width=".21"/>
<circle cx="151.4" cy="83" r=".68" fill="#008000" stroke="#008000" stroke-width=".21"/>
<circle cx="151.4" cy="83" r=".38" fill="#fff" stroke="#000" stroke-width=".21"/>
<circle cx="108.9" cy="88.2" r=".68" fill="#008000" stroke="#008000" stroke-width=".21"/>
<circle cx="108.9" cy="88.2" r=".38" fill="#fff" stroke="#000" stroke-width=".21"/>
<circle cx="108.9" cy="83.9" r=".68" fill="#008000" stroke="#008000" stroke-width=".21"/>
<circle cx="108.9" cy="83.9" r=".38" fill="#fff" stroke="#000" stroke-width=".21"/>
<circle cx="174.9" cy="67.8" r=".68" fill="#008000" stroke="#008000" stroke-width=".21"/>
<circle cx="174.9" cy="67.8" r=".38" fill="#fff" stroke="#000" stroke-width=".21"/>
<circle cx="151.7" cy="58.4" r=".68" fill="#008000" stroke="#008000" stroke-width=".21"/>
<circle cx="151.7" cy="58.4" r=".38" fill="#fff" stroke="#000" stroke-width=".21"/>
<circle cx="151.7" cy="62.2" r=".68" fill="#008000" stroke="#008000" stroke-width=".21"/>
<circle cx="151.7" cy="62.2" r=".38" fill="#fff" stroke="#000" stroke-width=".21"/>
<circle cx="209.6" cy="66.2" r=".68" fill="#008000" stroke="#008000" stroke-width=".21"/>
<circle cx="209.6" cy="66.2" r=".38" fill="#fff" stroke="#000" stroke-width=".21"/>
<circle cx="195.9" cy="43.7" r=".76" fill="#008000" stroke="#008000" stroke-width=".21"/>
<circle cx="195.9" cy="43.7" r=".47" fill="#fff" stroke="#000" stroke-width=".21"/>
<circle cx="161.2" cy="76.3" r=".68" fill="#008000" stroke="#008000" stroke-width=".21"/>
<circle cx="161.2" cy="76.3" r=".38" fill="#fff" stroke="#000" stroke-width=".21"/>
<circle cx="199.4" cy="158.1" r=".68" fill="#008000" stroke="#008000" stroke-width=".21"/>
<circle cx="199.4" cy="158.1" r=".38" fill="#fff" stroke="#000" stroke-width=".21"/>
<circle cx="178.1" cy="164.7" r=".76" fill="#008000" stroke="#008000" stroke-width=".21"/>
<circle cx="178.1" cy="164.7" r=".47" fill="#fff" stroke="#000" stroke-width=".21"/>
<circle cx="189.6" cy="165.3" r=".68" fill="#008000" stroke="#008000" stroke-width=".21"/>
<circle cx="189.6" cy="165.3" r=".38" fill="#fff" stroke="#000" stroke-width=".21"/>
<circle cx="146.1" cy="167.7" r=".68" fill="#008000" stroke="#008000" stroke-width=".21"/>
<circle cx="146.1" cy="167.7" r=".38" fill="#fff" stroke="#000" stroke-width=".21"/>
<circle cx="112.4" cy="167.1" r=".68" fill="#008000" stroke="#008000" stroke-width=".21"/>
<circle cx="112.4" cy="167.1" r=".38" fill="#fff" stroke="#000" stroke-width=".21"/>
<circle cx="112.4" cy="158.6" r=".68" fill="#008000" stroke="#008000" stroke-width=".21"/>
<circle cx="112.4" cy="158.6" r=".38" fill="#fff" stroke="#000" stroke-width=".21"/>
<circle cx="113.7" cy="105.5" r=".68" fill="#008000" stroke="#008000" stroke-width=".21"/>
<circle cx="113.7" cy="105.5" r=".38" fill="#fff" stroke="#000" stroke-width=".21"/>
<circle cx="115.7" cy="100.4" r=".68" fill="#008000" stroke="#008000" stroke-width=".21"/>
<circle cx="115.7" cy="100.4" r=".38" fill="#fff" stroke="#000" stroke-width=".21"/>
<circle cx="111.7" cy="96.7" r=".68" fill="#008000" stroke="#008000" stroke-width=".21"/>
<circle cx="111.7" cy="96.7" r=".38" fill="#fff" stroke="#000" stroke-width=".21"/>
<circle cx="111.9" cy="83.8" r=".68" fill="#008000" stroke="#008000" stroke-width=".21"/>
<circle cx="111.9" cy="83.8" r=".38" fill="#fff" stroke="#000" stroke-width=".21"/>
<circle cx="94.6" cy="37.8" r="3.2" fill="#008000" stroke="#008000" stroke-width=".21"/>
<circle cx="94.6" cy="37.8" r="2.39" fill="#fff" stroke="#000" stroke-width=".21"/>
<circle cx="205" cy="37.8" r="3.2" fill="#008000" stroke="#008000" stroke-width=".21"/>
<circle cx="205" cy="37.8" r="2.39" fill="#fff" stroke="#000" stroke-width=".21"/>
<circle cx="208.8" cy="166.3" r="3.2" fill="#008000" stroke="#008000" stroke-width=".21"/>
<circle cx="208.8" cy="166.3" r="2.39" fill="#fff" stroke="#000" stroke-width=".21"/>
<circle cx="88.9" cy="166.3" r="3.2" fill="#008000" stroke="#008000" stroke-width=".21"/>
<circle cx="88.9" cy="166.3" r="2.39" fill="#fff" stroke="#000" stroke-width=".21"/>
<circle cx="199.5" cy="162.4" r=".68" fill="#008000" stroke="#008000" stroke-width=".21"/>
<circle cx="199.5" cy="162.4" r=".38" fill="#fff" stroke="#000" stroke-width=".21"/>
<g fill="#000080" stroke="#000080" stroke-width=".21">
<path d="M80.5 33.1l.4-.4 .4 .2-.1 .2-.4 .4-.3-.1z"/>
<path d="M81.2 32.5h.2l.1 .2-.5 .5-.2-.3z"/>
<path d="M81.1 32.6l.4-.1 .2 .3-.5 .1z"/>
<circle cx="81.5" cy="32.7" r=".28"/>
<circle cx="82.5" cy="32.8" r=".28"/>
<circle cx="83.6" cy="32.8" r=".27"/>
<circle cx="84.6" cy="32.8" r=".28"/>
<circle cx="85.6" cy="32.8" r=".28"/>
<circle cx="86.7" cy="32.8" r=".27"/>
<circle cx="87.7" cy="32.8" r=".27"/>
<circle cx="88.7" cy="32.8" r=".28"/>
<circle cx="89.8" cy="32.8" r=".28"/>
<circle cx="90.8" cy="32.8" r=".27"/>
<circle cx="91.8" cy="32.8" r=".27"/>
<circle cx="92.9" cy="32.8" r=".28"/>
<circle cx="93.9" cy="32.8" r=".28"/>
<circle cx="94.9" cy="32.8" r=".27"/>
<circle cx="95.9" cy="32.8" r=".28"/>
<circle cx="97" cy="32.8" r=".28"/>
<circle cx="98" cy="32.8" r=".27"/>
<circle cx="99" cy="32.8" r=".27"/>
<circle cx="100.1" cy="32.8" r=".28"/>
<circle cx="101.1" cy="32.8" r=".28"/>
<circle cx="102.1" cy="32.8" r=".27"/>
<circle cx="103.2" cy="32.8" r=".27"/>
<circle cx="104.2" cy="32.8" r=".28"/>
<circle cx="105.2" cy="32.8" r=".28"/>
<circle cx="106.3" cy="32.8" r=".27"/>
<circle cx="107.3" cy="32.8" r=".28"/>
<circle cx="108.3" cy="32.8" r=".28"/>
<circle cx="109.4" cy="32.8" r=".27"/>
<circle cx="110.4" cy="32.8" r=".27"/>
<circle cx="111.4" cy="32.9" r=".28"/>
<circle cx="112.5" cy="32.9" r=".28"/>
<circle cx="113.5" cy="32.8" r=".27"/>
<circle cx="114.5" cy="32.8" r=".27"/>
<circle cx="115.5" cy="32.9" r=".28"/>
<circle cx="116.6" cy="32.9" r=".28"/>
<circle cx="117.6" cy="32.8" r=".27"/>
<circle cx="118.6" cy="32.9" r=".28"/>
<circle cx="119.7" cy="32.9" r=".28"/>
<circle cx="120.7" cy="32.9" r=".27"/>
<circle cx="121.7" cy="32.9" r=".27"/>
<circle cx="122.8" cy="32.9" r=".28"/>
<circle cx="123.8" cy="32.9" r=".28"/>
<circle cx="124.8" cy="32.9" r=".27"/>
<circle cx="125.9" cy="32.9" r=".27"/>
<circle cx="126.9" cy="32.9" r=".28"/>
<circle cx="127.9" cy="32.9" r=".28"/>
<circle cx="129" cy="32.9" r=".27"/>
<circle cx="130" cy="32.9" r=".28"/>
<circle cx="131" cy="32.9" r=".28"/>
<circle cx="132" cy="32.9" r=".27"/>
<circle cx="133.1" cy="32.9" r=".27"/>
<circle cx="134.1" cy="32.9" r=".28"/>
<circle cx="135.1" cy="32.9" r=".28"/>
<circle cx="136.2" cy="32.9" r=".27"/>
<circle cx="137.2" cy="32.9" r=".27"/>
<circle cx="138.2" cy="32.9" r=".28"/>
<circle cx="139.3" cy="32.9" r=".28"/>
<circle cx="140.3" cy="32.9" r=".27"/>
<circle cx="141.3" cy="32.9" r=".28"/>
<circle cx="142.4" cy="32.9" r=".28"/>
<circle cx="143.4" cy="32.9" r=".27"/>
<circle cx="144.4" cy="32.9" r=".27"/>
<circle cx="145.5" cy="32.9" r=".28"/>
<circle cx="146.5" cy="32.9" r=".28"/>
<circle cx="147.5" cy="32.9" r=".27"/>
<circle cx="148.5" cy="33" r=".28"/>
<circle cx="149.6" cy="33" r=".28"/>
<circle cx="150.6" cy="33" r=".27"/>
<circle cx="151.6" cy="33" r=".27"/>
<circle cx="152.7" cy="33" r=".28"/>
<circle cx="153.7" cy="33" r=".28"/>
<circle cx="154.7" cy="33" r=".27"/>
<circle cx="155.8" cy="33" r=".27"/>
<circle cx="156.8" cy="33" r=".28"/>
<circle cx="157.8" cy="33" r=".28"/>
<circle cx="158.9" cy="33" r=".27"/>
<circle cx="159.9" cy="33" r=".28"/>
<circle cx="160.9" cy="33" r=".28"/>
<circle cx="162" cy="33" r=".27"/>
<circle cx="163" cy="33" r=".27"/>
<circle cx="164" cy="33" r=".28"/>
<circle cx="165.1" cy="33" r=".28"/>
<circle cx="166.1" cy="33" r=".27"/>
<circle cx="167.1" cy="33" r=".27"/>
<circle cx="168.1" cy="33" r=".28"/>
<circle cx="169.2" cy="33" r=".28"/>
<circle cx="170.2" cy="33" r=".27"/>
<circle cx="171.2" cy="33" r=".28"/>
<circle cx="172.3" cy="33" r=".28"/>
<circle cx="173.3" cy="33" r=".27"/>
<circle cx="174.3" cy="33" r=".27"/>
<circle cx="175.4" cy="33" r=".28"/>
<circle cx="176.4" cy="33" r=".28"/>
<circle cx="177.4" cy="33" r=".27"/>
<circle cx="178.5" cy="33" r=".27"/>
<circle cx="179.5" cy="33" r=".28"/>
<circle cx="180.5" cy="33" r=".28"/>
<circle cx="181.6" cy="33" r=".27"/>
<circle cx="182.6" cy="33" r=".28"/>
<circle cx="183.6" cy="33" r=".28"/>
<circle cx="184.6" cy="33.1" r=".27"/>
<circle cx="185.7" cy="33.1" r=".27"/>
<circle cx="186.7" cy="33.1" r=".28"/>
<circle cx="187.7" cy="33.1" r=".28"/>
<circle cx="188.8" cy="33.1" r=".27"/>
<circle cx="189.8" cy="33.1" r=".27"/>
<circle cx="190.8" cy="33.1" r=".28"/>
<circle cx="191.9" cy="33.1" r=".28"/>
<circle cx="192.9" cy="33.1" r=".27"/>
<circle cx="193.9" cy="33.1" r=".28"/>
<circle cx="195" cy="33.1" r=".28"/>
<circle cx="196" cy="33.1" r=".27"/>
<circle cx="197" cy="33.1" r=".27"/>
<circle cx="198.1" cy="33.1" r=".28"/>
<circle cx="199.1" cy="33.1" r=".28"/>
<circle cx="200.1" cy="33.1" r=".27"/>
<circle cx="201.2" cy="33.1" r=".27"/>
<circle cx="202.2" cy="33.1" r=".28"/>
<circle cx="203.2" cy="33.1" r=".28"/>
<circle cx="204.2" cy="33.1" r=".27"/>
<circle cx="205.3" cy="33.1" r=".28"/>
<circle cx="206.3" cy="33.1" r=".28"/>
<circle cx="207.3" cy="33.1" r=".27"/>
<circle cx="208.4" cy="33.1" r=".27"/>
<circle cx="209.4" cy="33.1" r=".28"/>
<circle cx="210.4" cy="33.1" r=".28"/>
<circle cx="211.5" cy="33.1" r=".27"/>
<circle cx="212.5" cy="33.1" r=".27"/>
<circle cx="213.5" cy="33.1" r=".28"/>
<circle cx="214.6" cy="33.1" r=".27"/>
<circle cx="215.6" cy="33.1" r=".27"/>
<circle cx="216.6" cy="33.1" r=".28"/>
<circle cx="216.7" cy="33.2" r=".27"/>
<circle cx="216.7" cy="34.2" r=".27"/>
<circle cx="216.7" cy="35.2" r=".28"/>
<circle cx="216.7" cy="36.3" r=".28"/>
<circle cx="216.7" cy="37.3" r=".27"/>
<circle cx="216.7" cy="38.3" r=".27"/>
<circle cx="216.7" cy="39.4" r=".28"/>
<circle cx="216.7" cy="40.4" r=".28"/>
<circle cx="216.7" cy="41.4" r=".27"/>
<circle cx="216.7" cy="42.5" r=".27"/>
<circle cx="216.7" cy="43.5" r=".28"/>
<circle cx="216.7" cy="44.5" r=".28"/>
<circle cx="216.7" cy="45.6" r=".27"/>
<circle cx="216.7" cy="46.6" r=".27"/>
<circle cx="216.7" cy="47.6" r=".28"/>
<circle cx="216.7" cy="48.7" r=".28"/>
<circle cx="216.7" cy="49.7" r=".27"/>
<circle cx="216.7" cy="50.7" r=".27"/>
<circle cx="216.7" cy="51.8" r=".28"/>
<circle cx="216.7" cy="52.8" r=".28"/>
<circle cx="216.7" cy="53.8" r=".27"/>
<circle cx="216.7" cy="54.9" r=".27"/>
<circle cx="216.7" cy="55.9" r=".28"/>
<circle cx="216.7" cy="56.9" r=".28"/>
<circle cx="216.7" cy="57.9" r=".27"/>
<circle cx="216.7" cy="59" r=".27"/>
<circle cx="216.7" cy="60" r=".28"/>
<circle cx="216.7" cy="61" r=".28"/>
<circle cx="216.7" cy="62.1" r=".27"/>
<circle cx="216.7" cy="63.1" r=".27"/>
<circle cx="216.7" cy="64.1" r=".28"/>
<circle cx="216.7" cy="65.2" r=".28"/>
<circle cx="216.7" cy="66.2" r=".27"/>
<circle cx="216.7" cy="67.2" r=".27"/>
<circle cx="216.7" cy="68.3" r=".28"/>
<circle cx="216.7" cy="69.3" r=".28"/>
<circle cx="216.7" cy="70.3" r=".27"/>
<circle cx="216.7" cy="71.4" r=".27"/>
<circle cx="216.7" cy="72.4" r=".28"/>
<circle cx="216.7" cy="73.4" r=".28"/>
<circle cx="216.7" cy="74.5" r=".27"/>
<circle cx="216.7" cy="75.5" r=".27"/>
<circle cx="216.7" cy="76.5" r=".28"/>
<circle cx="216.7" cy="77.6" r=".28"/>
<circle cx="216.7" cy="78.6" r=".27"/>
<circle cx="216.7" cy="79.6" r=".27"/>
<circle cx="216.7" cy="80.6" r=".28"/>
<circle cx="216.7" cy="81.7" r=".28"/>
<circle cx="216.7" cy="82.7" r=".27"/>
<circle cx="216.7" cy="83.7" r=".27"/>
<circle cx="216.7" cy="84.8" r=".28"/>
<circle cx="216.7" cy="85.8" r=".28"/>
<circle cx="216.7" cy="86.8" r=".27"/>
<circle cx="216.7" cy="87.9" r=".27"/>
<circle cx="216.7" cy="88.9" r=".28"/>
<circle cx="216.7" cy="89.9" r=".28"/>
<circle cx="216.7" cy="91" r=".27"/>
<circle cx="216.7" cy="92" r=".27"/>
<circle cx="216.7" cy="93" r=".28"/>
<circle cx="216.7" cy="94.1" r=".28"/>
<circle cx="216.7" cy="95.1" r=".27"/>
<circle cx="216.7" cy="96.1" r=".27"/>
<circle cx="216.7" cy="97.2" r=".28"/>
<circle cx="216.7" cy="98.2" r=".28"/>
<circle cx="216.7" cy="99.2" r=".27"/>
<circle cx="216.7" cy="100.3" r=".27"/>
<circle cx="216.7" cy="101.3" r=".28"/>
<circle cx="216.7" cy="102.3" r=".28"/>
<circle cx="216.7" cy="103.3" r=".27"/>
<circle cx="216.7" cy="104.4" r=".27"/>
<circle cx="216.7" cy="105.4" r=".28"/>
<circle cx="216.7" cy="106.4" r=".28"/>
<circle cx="216.7" cy="107.5" r=".27"/>
<circle cx="216.7" cy="108.5" r=".27"/>
<circle cx="216.7" cy="109.5" r=".28"/>
<circle cx="216.7" cy="110.6" r=".28"/>
<circle cx="216.7" cy="111.6" r=".27"/>
<circle cx="216.7" cy="112.6" r=".27"/>
<circle cx="216.7" cy="113.7" r=".28"/>
<circle cx="216.7" cy="114.7" r=".28"/>
<circle cx="216.7" cy="115.7" r=".27"/>
<circle cx="216.7" cy="116.8" r=".27"/>
<circle cx="216.7" cy="117.8" r=".28"/>
<circle cx="216.7" cy="118.8" r=".28"/>
<circle cx="216.7" cy="119.9" r=".27"/>
<circle cx="216.7" cy="120.9" r=".27"/>
<circle cx="216.7" cy="121.9" r=".28"/>
<circle cx="216.7" cy="123" r=".28"/>
<circle cx="216.7" cy="124" r=".27"/>
<circle cx="216.7" cy="125" r=".27"/>
<circle cx="216.7" cy="126" r=".28"/>
<circle cx="216.7" cy="127.1" r=".28"/>
<circle cx="216.7" cy="128.1" r=".27"/>
<circle cx="216.7" cy="129.1" r=".27"/>
<circle cx="216.7" cy="130.2" r=".28"/>
<circle cx="216.7" cy="131.2" r=".28"/>
<circle cx="216.7" cy="132.2" r=".27"/>
<circle cx="216.7" cy="133.3" r=".27"/>
<circle cx="216.7" cy="134.3" r=".28"/>
<circle cx="216.7" cy="135.3" r=".28"/>
<circle cx="216.7" cy="136.4" r=".27"/>
<circle cx="216.7" cy="137.4" r=".27"/>
<circle cx="216.7" cy="138.4" r=".28"/>
<circle cx="216.7" cy="139.5" r=".28"/>
<circle cx="216.7" cy="140.5" r=".27"/>
<circle cx="216.7" cy="141.5" r=".27"/>
<circle cx="216.7" cy="142.6" r=".28"/>
<circle cx="216.7" cy="143.6" r=".28"/>
<circle cx="216.7" cy="144.6" r=".27"/>
<circle cx="216.7" cy="145.7" r=".27"/>
<circle cx="216.7" cy="146.7" r=".28"/>
<circle cx="216.7" cy="147.7" r=".28"/>
<circle cx="216.7" cy="148.7" r=".27"/>
<circle cx="216.7" cy="149.8" r=".27"/>
<circle cx="216.7" cy="150.8" r=".28"/>
<circle cx="216.7" cy="151.8" r=".28"/>
<circle cx="216.7" cy="152.9" r=".27"/>
<circle cx="216.7" cy="153.9" r=".27"/>
<circle cx="216.7" cy="154.9" r=".28"/>
<circle cx="216.7" cy="156" r=".28"/>
<circle cx="216.7" cy="157" r=".27"/>
<circle cx="216.7" cy="158" r=".27"/>
<circle cx="216.7" cy="159.1" r=".28"/>
<circle cx="216.7" cy="160.1" r=".28"/>
<circle cx="216.7" cy="161.1" r=".27"/>
<circle cx="216.7" cy="162.2" r=".27"/>
<circle cx="216.7" cy="163.2" r=".28"/>
<circle cx="216.7" cy="164.2" r=".28"/>
<circle cx="216.7" cy="165.3" r=".27"/>
<circle cx="216.7" cy="166.3" r=".27"/>
<circle cx="216.7" cy="167.3" r=".28"/>
<circle cx="216.7" cy="168.4" r=".28"/>
<circle cx="216.7" cy="169.4" r=".27"/>
<circle cx="216.7" cy="170.4" r=".27"/>
<circle cx="216.7" cy="171.4" r=".28"/>
<circle cx="216.6" cy="171.5" r=".28"/>
<circle cx="215.6" cy="171.5" r=".28"/>
<circle cx="214.6" cy="171.5" r=".27"/>
<circle cx="213.5" cy="171.5" r=".27"/>
<circle cx="212.5" cy="171.5" r=".28"/>
<circle cx="211.5" cy="171.5" r=".28"/>
<circle cx="210.4" cy="171.5" r=".28"/>
<circle cx="209.4" cy="171.5" r=".28"/>
<circle cx="208.3" cy="171.5" r=".28"/>
<circle cx="207.3" cy="171.5" r=".27"/>
<circle cx="206.3" cy="171.5" r=".27"/>
<circle cx="205.3" cy="171.5" r=".28"/>
<circle cx="204.2" cy="171.5" r=".28"/>
<circle cx="203.2" cy="171.5" r=".28"/>
<circle cx="202.1" cy="171.5" r=".28"/>
<circle cx="201.1" cy="171.5" r=".27"/>
<circle cx="200.1" cy="171.5" r=".27"/>
<circle cx="199.1" cy="171.5" r=".28"/>
<circle cx="198" cy="171.5" r=".28"/>
<circle cx="197" cy="171.5" r=".28"/>
<circle cx="195.9" cy="171.5" r=".28"/>
<circle cx="194.9" cy="171.5" r=".28"/>
<circle cx="193.9" cy="171.5" r=".27"/>
<circle cx="192.8" cy="171.5" r=".27"/>
<circle cx="191.8" cy="171.5" r=".28"/>
<circle cx="190.8" cy="171.5" r=".28"/>
<circle cx="189.7" cy="171.5" r=".28"/>
<circle cx="188.7" cy="171.5" r=".28"/>
<circle cx="187.7" cy="171.5" r=".27"/>
<circle cx="186.6" cy="171.5" r=".27"/>
<circle cx="185.6" cy="171.5" r=".27"/>
<circle cx="184.6" cy="171.5" r=".28"/>
<circle cx="183.5" cy="171.5" r=".28"/>
<circle cx="182.5" cy="171.5" r=".28"/>
<circle cx="181.5" cy="171.5" r=".28"/>
<circle cx="180.4" cy="171.5" r=".27"/>
<circle cx="179.4" cy="171.5" r=".27"/>
<circle cx="178.4" cy="171.5" r=".28"/>
<circle cx="177.3" cy="171.5" r=".28"/>
<circle cx="176.3" cy="171.5" r=".28"/>
<circle cx="175.3" cy="171.5" r=".28"/>
<circle cx="174.2" cy="171.5" r=".28"/>
<circle cx="173.2" cy="171.5" r=".27"/>
<circle cx="172.2" cy="171.5" r=".27"/>
<circle cx="171.1" cy="171.5" r=".28"/>
<circle cx="170.1" cy="171.5" r=".28"/>
<circle cx="169.1" cy="171.5" r=".28"/>
<circle cx="168" cy="171.5" r=".28"/>
<circle cx="167" cy="171.5" r=".27"/>
<circle cx="166" cy="171.5" r=".27"/>
<circle cx="164.9" cy="171.5" r=".27"/>
<circle cx="163.9" cy="171.5" r=".28"/>
<circle cx="162.9" cy="171.5" r=".28"/>
<circle cx="161.8" cy="171.5" r=".28"/>
<circle cx="160.8" cy="171.5" r=".28"/>
<circle cx="159.8" cy="171.5" r=".27"/>
<circle cx="158.7" cy="171.5" r=".27"/>
<circle cx="157.7" cy="171.5" r=".28"/>
<circle cx="156.7" cy="171.5" r=".28"/>
<circle cx="155.6" cy="171.5" r=".28"/>
<circle cx="154.6" cy="171.5" r=".28"/>
<circle cx="153.5" cy="171.5" r=".28"/>
<circle cx="152.5" cy="171.5" r=".27"/>
<circle cx="151.5" cy="171.5" r=".27"/>
<circle cx="150.5" cy="171.5" r=".28"/>
<circle cx="149.4" cy="171.5" r=".28"/>
<circle cx="148.4" cy="171.5" r=".28"/>
<circle cx="147.3" cy="171.5" r=".28"/>
<circle cx="146.3" cy="171.5" r=".27"/>
<circle cx="145.3" cy="171.5" r=".27"/>
<circle cx="144.2" cy="171.5" r=".27"/>
<circle cx="143.2" cy="171.5" r=".28"/>
<circle cx="142.2" cy="171.5" r=".28"/>
<circle cx="141.1" cy="171.5" r=".28"/>
<circle cx="140.1" cy="171.5" r=".28"/>
<circle cx="139.1" cy="171.5" r=".27"/>
<circle cx="138" cy="171.5" r=".27"/>
<circle cx="137" cy="171.5" r=".28"/>
<circle cx="136" cy="171.5" r=".28"/>
<circle cx="134.9" cy="171.5" r=".28"/>
<circle cx="133.9" cy="171.5" r=".28"/>
<circle cx="132.9" cy="171.5" r=".28"/>
<circle cx="131.8" cy="171.5" r=".27"/>
<circle cx="130.8" cy="171.5" r=".27"/>
<circle cx="129.8" cy="171.5" r=".28"/>
<circle cx="128.7" cy="171.5" r=".28"/>
<circle cx="127.7" cy="171.5" r=".28"/>
<circle cx="126.7" cy="171.5" r=".28"/>
<circle cx="125.6" cy="171.5" r=".27"/>
<circle cx="124.6" cy="171.5" r=".27"/>
<circle cx="123.6" cy="171.5" r=".28"/>
<circle cx="122.5" cy="171.5" r=".28"/>
<circle cx="121.5" cy="171.5" r=".28"/>
<circle cx="120.5" cy="171.5" r=".28"/>
<circle cx="119.4" cy="171.5" r=".28"/>
<circle cx="118.4" cy="171.5" r=".27"/>
<circle cx="117.4" cy="171.5" r=".27"/>
<circle cx="116.3" cy="171.5" r=".28"/>
<circle cx="115.3" cy="171.5" r=".28"/>
<circle cx="114.3" cy="171.5" r=".28"/>
<circle cx="113.2" cy="171.5" r=".28"/>
<circle cx="112.2" cy="171.5" r=".27"/>
<circle cx="111.2" cy="171.5" r=".27"/>
<circle cx="110.1" cy="171.5" r=".27"/>
<circle cx="109.1" cy="171.5" r=".28"/>
<circle cx="108.1" cy="171.5" r=".28"/>
<circle cx="107" cy="171.5" r=".28"/>
<circle cx="106" cy="171.5" r=".28"/>
<circle cx="105" cy="171.5" r=".27"/>
<circle cx="103.9" cy="171.5" r=".27"/>
<circle cx="102.9" cy="171.5" r=".28"/>
<circle cx="101.9" cy="171.5" r=".28"/>
<circle cx="100.8" cy="171.5" r=".28"/>
<circle cx="99.8" cy="171.5" r=".28"/>
<circle cx="98.7" cy="171.5" r=".28"/>
<circle cx="97.7" cy="171.5" r=".27"/>
<circle cx="96.7" cy="171.5" r=".27"/>
<circle cx="95.7" cy="171.5" r=".28"/>
<circle cx="94.6" cy="171.5" r=".28"/>
<circle cx="93.6" cy="171.5" r=".28"/>
<circle cx="92.5" cy="171.5" r=".28"/>
<circle cx="91.5" cy="171.5" r=".27"/>
<circle cx="90.5" cy="171.5" r=".27"/>
<circle cx="89.4" cy="171.5" r=".27"/>
<circle cx="88.4" cy="171.5" r=".28"/>
<circle cx="87.4" cy="171.5" r=".28"/>
<circle cx="86.3" cy="171.5" r=".28"/>
<circle cx="85.3" cy="171.5" r=".28"/>
<circle cx="84.3" cy="171.5" r=".27"/>
<circle cx="83.2" cy="171.5" r=".27"/>
<circle cx="82.2" cy="171.5" r=".28"/>
<circle cx="81.2" cy="171.5" r=".28"/>
<circle cx="81.1" cy="171.4" r=".28"/>
<circle cx="81.1" cy="170.4" r=".27"/>
<circle cx="81.1" cy="169.4" r=".28"/>
<circle cx="81.1" cy="168.4" r=".28"/>
<circle cx="81.1" cy="167.3" r=".27"/>
<circle cx="81.1" cy="166.3" r=".27"/>
<circle cx="81.1" cy="165.3" r=".28"/>
<circle cx="81.1" cy="164.2" r=".28"/>
<circle cx="81.1" cy="163.2" r=".27"/>
<circle cx="81.1" cy="162.2" r=".28"/>
<circle cx="81.1" cy="161.1" r=".28"/>
<circle cx="81.1" cy="160.1" r=".27"/>
<circle cx="81.1" cy="159.1" r=".27"/>
<circle cx="81.1" cy="158.1" r=".28"/>
<circle cx="81.1" cy="157" r=".27"/>
<circle cx="81.1" cy="156" r=".27"/>
<circle cx="81.1" cy="155" r=".28"/>
<circle cx="81.1" cy="153.9" r=".28"/>
<circle cx="81.1" cy="152.9" r=".27"/>
<circle cx="81.1" cy="151.9" r=".28"/>
<circle cx="81.1" cy="150.8" r=".28"/>
<circle cx="81.1" cy="149.8" r=".27"/>
<circle cx="81.1" cy="148.8" r=".27"/>
<circle cx="81.1" cy="147.7" r=".28"/>
<circle cx="81" cy="146.7" r=".28"/>
<circle cx="81" cy="145.7" r=".27"/>
<circle cx="81" cy="144.7" r=".28"/>
<circle cx="81" cy="143.6" r=".28"/>
<circle cx="81" cy="142.6" r=".27"/>
<circle cx="81" cy="141.6" r=".27"/>
<circle cx="81" cy="140.5" r=".28"/>
<circle cx="81" cy="139.5" r=".28"/>
<circle cx="81" cy="138.5" r=".27"/>
<circle cx="81" cy="137.4" r=".28"/>
<circle cx="81" cy="136.4" r=".28"/>
<circle cx="81" cy="135.4" r=".27"/>
<circle cx="81" cy="134.3" r=".27"/>
<circle cx="81" cy="133.3" r=".28"/>
<circle cx="81" cy="132.3" r=".27"/>
<circle cx="81" cy="131.2" r=".27"/>
<circle cx="81" cy="130.2" r=".28"/>
<circle cx="81" cy="129.2" r=".28"/>
<circle cx="81" cy="128.2" r=".27"/>
<circle cx="81" cy="127.1" r=".28"/>
<circle cx="81" cy="126.1" r=".28"/>
<circle cx="81" cy="125.1" r=".27"/>
<circle cx="81" cy="124" r=".27"/>
<circle cx="81" cy="123" r=".28"/>
<circle cx="81" cy="122" r=".28"/>
<circle cx="81" cy="120.9" r=".27"/>
<circle cx="81" cy="119.9" r=".28"/>
<circle cx="81" cy="118.9" r=".28"/>
<circle cx="81" cy="117.8" r=".27"/>
<circle cx="81" cy="116.8" r=".27"/>
<circle cx="81" cy="115.8" r=".28"/>
<circle cx="81" cy="114.7" r=".28"/>
<circle cx="81" cy="113.7" r=".27"/>
<circle cx="81" cy="112.7" r=".28"/>
<circle cx="80.9" cy="111.7" r=".28"/>
<circle cx="80.9" cy="110.6" r=".27"/>
<circle cx="80.9" cy="109.6" r=".27"/>
<circle cx="80.9" cy="108.6" r=".28"/>
<circle cx="80.9" cy="107.5" r=".27"/>
<circle cx="80.9" cy="106.5" r=".27"/>
<circle cx="80.9" cy="105.5" r=".28"/>
<circle cx="80.9" cy="104.4" r=".28"/>
<circle cx="80.9" cy="103.4" r=".27"/>
<circle cx="80.9" cy="102.4" r=".28"/>
<circle cx="80.9" cy="101.3" r=".28"/>
<circle cx="80.9" cy="100.3" r=".27"/>
<circle cx="80.9" cy="99.3" r=".27"/>
<circle cx="80.9" cy="98.3" r=".28"/>
<circle cx="80.9" cy="97.2" r=".28"/>
<circle cx="80.9" cy="96.2" r=".27"/>
<circle cx="80.9" cy="95.2" r=".28"/>
<circle cx="80.9" cy="94.1" r=".28"/>
<circle cx="80.9" cy="93.1" r=".27"/>
<circle cx="80.9" cy="92.1" r=".27"/>
<circle cx="80.9" cy="91" r=".28"/>
<circle cx="80.9" cy="90" r=".27"/>
<circle cx="80.9" cy="89" r=".27"/>
<circle cx="80.9" cy="87.9" r=".28"/>
<circle cx="80.9" cy="86.9" r=".28"/>
<circle cx="80.9" cy="85.9" r=".27"/>
<circle cx="80.9" cy="84.8" r=".27"/>
<circle cx="80.9" cy="83.8" r=".28"/>
<circle cx="80.9" cy="82.8" r=".27"/>
<circle cx="80.9" cy="81.8" r=".27"/>
<circle cx="80.9" cy="80.7" r=".28"/>
<circle cx="80.9" cy="79.7" r=".28"/>
<circle cx="80.9" cy="78.7" r=".27"/>
<circle cx="80.9" cy="77.6" r=".28"/>
<circle cx="80.8" cy="76.6" r=".28"/>
<circle cx="80.8" cy="75.6" r=".27"/>
<circle cx="80.8" cy="74.5" r=".27"/>
<circle cx="80.8" cy="73.5" r=".28"/>
<circle cx="80.8" cy="72.5" r=".28"/>
<circle cx="80.8" cy="71.4" r=".27"/>
<circle cx="80.8" cy="70.4" r=".28"/>
<circle cx="80.8" cy="69.4" r=".28"/>
<circle cx="80.8" cy="68.4" r=".27"/>
<circle cx="80.8" cy="67.3" r=".27"/>
<circle cx="80.8" cy="66.3" r=".28"/>
<circle cx="80.8" cy="65.3" r=".27"/>
<circle cx="80.8" cy="64.2" r=".27"/>
<circle cx="80.8" cy="63.2" r=".28"/>
<circle cx="80.8" cy="62.2" r=".28"/>
<circle cx="80.8" cy="61.1" r=".27"/>
<circle cx="80.8" cy="60.1" r=".27"/>
<circle cx="80.8" cy="59.1" r=".28"/>
<circle cx="80.8" cy="58" r=".27"/>
<circle cx="80.8" cy="57" r=".27"/>
<circle cx="80.8" cy="56" r=".28"/>
<circle cx="80.8" cy="54.9" r=".28"/>
<circle cx="80.8" cy="53.9" r=".27"/>
<circle cx="80.8" cy="52.9" r=".28"/>
<circle cx="80.8" cy="51.9" r=".28"/>
<circle cx="80.8" cy="50.8" r=".27"/>
<circle cx="80.8" cy="49.8" r=".27"/>
<circle cx="80.8" cy="48.8" r=".28"/>
<circle cx="80.8" cy="47.7" r=".28"/>
<circle cx="80.7" cy="46.7" r=".27"/>
<circle cx="80.8" cy="45.7" r=".28"/>
<circle cx="80.8" cy="44.6" r=".28"/>
<circle cx="80.7" cy="43.6" r=".27"/>
<circle cx="80.7" cy="42.6" r=".27"/>
<circle cx="80.7" cy="41.6" r=".28"/>
<circle cx="80.7" cy="40.5" r=".27"/>
<circle cx="80.7" cy="39.5" r=".27"/>
<circle cx="80.7" cy="38.5" r=".28"/>
<circle cx="80.7" cy="37.4" r=".28"/>
<circle cx="80.7" cy="36.4" r=".27"/>
<circle cx="80.7" cy="35.4" r=".27"/>
<circle cx="80.7" cy="34.3" r=".28"/>
<circle cx="80.7" cy="33.3" r=".27"/>
</g>
<circle cx="203.4" cy="140.8" r=".91" fill="#008000" stroke="#008000" stroke-width=".21"/>
<circle cx="203.4" cy="140.8" r=".53" fill="#fff" stroke="#000" stroke-width=".21"/>
<circle cx="201.5" cy="140.8" r=".91" fill="#008000" stroke="#008000" stroke-width=".21"/>
<circle cx="201.5" cy="140.8" r=".53" fill="#fff" stroke="#000" stroke-width=".21"/>
<circle cx="203.4" cy="138.9" r=".91" fill="#008000" stroke="#008000" stroke-width=".21"/>
<circle cx="203.4" cy="138.9" r=".53" fill="#fff" stroke="#000" stroke-width=".21"/>
<circle cx="201.5" cy="138.9" r=".91" fill="#008000" stroke="#008000" stroke-width=".21"/>
<circle cx="201.5" cy="138.9" r=".53" fill="#fff" stroke="#000" stroke-width=".21"/>
<circle cx="203.4" cy="137" r=".91" fill="#008000" stroke="#008000" stroke-width=".21"/>
<circle cx="203.4" cy="137" r=".53" fill="#fff" stroke="#000" stroke-width=".21"/>
<circle cx="201.5" cy="137" r=".91" fill="#008000" stroke="#008000" stroke-width=".21"/>
<circle cx="201.5" cy="137" r=".53" fill="#fff" stroke="#000" stroke-width=".21"/>
<circle cx="203.4" cy="135.1" r=".91" fill="#008000" stroke="#008000" stroke-width=".21"/>
<circle cx="203.4" cy="135.1" r=".53" fill="#fff" stroke="#000" stroke-width=".21"/>
<circle cx="201.5" cy="135.1" r=".91" fill="#008000" stroke="#008000" stroke-width=".21"/>
<circle cx="201.5" cy="135.1" r=".53" fill="#fff" stroke="#000" stroke-width=".21"/>
<circle cx="203.4" cy="133.2" r=".91" fill="#008000" stroke="#008000" stroke-width=".21"/>
<circle cx="203.4" cy="133.2" r=".53" fill="#fff" stroke="#000" stroke-width=".21"/>
<circle cx="201.5" cy="133.2" r=".91" fill="#008000" stroke="#008000" stroke-width=".21"/>
<circle cx="201.5" cy="133.2" r=".53" fill="#fff" stroke="#000" stroke-width=".21"/>
<circle cx="203.4" cy="131.3" r=".91" fill="#008000" stroke="#008000" stroke-width=".21"/>
<circle cx="203.4" cy="131.3" r=".53" fill="#fff" stroke="#000" stroke-width=".21"/>
<circle cx="201.5" cy="131.3" r=".91" fill="#008000" stroke="#008000" stroke-width=".21"/>
<circle cx="201.5" cy="131.3" r=".53" fill="#fff" stroke="#000" stroke-width=".21"/>
<circle cx="203.4" cy="129.4" r=".91" fill="#008000" stroke="#008000" stroke-width=".21"/>
<circle cx="203.4" cy="129.4" r=".53" fill="#fff" stroke="#000" stroke-width=".21"/>
<circle cx="201.5" cy="129.4" r=".91" fill="#008000" stroke="#008000" stroke-width=".21"/>
<circle cx="201.5" cy="129.4" r=".53" fill="#fff" stroke="#000" stroke-width=".21"/>
<circle cx="203.4" cy="127.5" r=".91" fill="#008000" stroke="#008000" stroke-width=".21"/>
<circle cx="203.4" cy="127.5" r=".53" fill="#fff" stroke="#000" stroke-width=".21"/>
<circle cx="201.5" cy="127.5" r=".91" fill="#008000" stroke="#008000" stroke-width=".21"/>
<circle cx="201.5" cy="127.5" r=".53" fill="#fff" stroke="#000" stroke-width=".21"/>
<circle cx="203.4" cy="125.6" r=".91" fill="#008000" stroke="#008000" stroke-width=".21"/>
<circle cx="203.4" cy="125.6" r=".53" fill="#fff" stroke="#000" stroke-width=".21"/>
<circle cx="201.5" cy="125.6" r=".91" fill="#008000" stroke="#008000" stroke-width=".21"/>
<circle cx="201.5" cy="125.6" r=".53" fill="#fff" stroke="#000" stroke-width=".21"/>
<circle cx="203.4" cy="123.7" r=".91" fill="#008000" stroke="#008000" stroke-width=".21"/>
<circle cx="203.4" cy="123.7" r=".53" fill="#fff" stroke="#000" stroke-width=".21"/>
<circle cx="201.5" cy="123.7" r=".91" fill="#008000" stroke="#008000" stroke-width=".21"/>
<circle cx="201.5" cy="123.7" r=".53" fill="#fff" stroke="#000" stroke-width=".21"/>
<circle cx="203.4" cy="121.8" r=".91" fill="#008000" stroke="#008000" stroke-width=".21"/>
<circle cx="203.4" cy="121.8" r=".53" fill="#fff" stroke="#000" stroke-width=".21"/>
<circle cx="201.5" cy="121.8" r=".91" fill="#008000" stroke="#008000" stroke-width=".21"/>
<circle cx="201.5" cy="121.8" r=".53" fill="#fff" stroke="#000" stroke-width=".21"/>
<circle cx="203.4" cy="119.8" r=".91" fill="#008000" stroke="#008000" stroke-width=".21"/>
<circle cx="203.4" cy="119.8" r=".53" fill="#fff" stroke="#000" stroke-width=".21"/>
<circle cx="201.5" cy="119.8" r=".91" fill="#008000" stroke="#008000" stroke-width=".21"/>
<circle cx="201.5" cy="119.8" r=".53" fill="#fff" stroke="#000" stroke-width=".21"/>
<circle cx="203.4" cy="117.9" r=".91" fill="#008000" stroke="#008000" stroke-width=".21"/>
<circle cx="203.4" cy="117.9" r=".53" fill="#fff" stroke="#000" stroke-width=".21"/>
<circle cx="201.5" cy="117.9" r=".91" fill="#008000" stroke="#008000" stroke-width=".21"/>
<circle cx="201.5" cy="117.9" r=".53" fill="#fff" stroke="#000" stroke-width=".21"/>
<circle cx="203.4" cy="116" r=".91" fill="#008000" stroke="#008000" stroke-width=".21"/>
<circle cx="203.4" cy="116" r=".53" fill="#fff" stroke="#000" stroke-width=".21"/>
<circle cx="201.5" cy="116" r=".91" fill="#008000" stroke="#008000" stroke-width=".21"/>
<circle cx="201.5" cy="116" r=".53" fill="#fff" stroke="#000" stroke-width=".21"/>
<circle cx="203.4" cy="114.1" r=".91" fill="#008000" stroke="#008000" stroke-width=".21"/>
<circle cx="203.4" cy="114.1" r=".53" fill="#fff" stroke="#000" stroke-width=".21"/>
<circle cx="201.5" cy="114.1" r=".91" fill="#008000" stroke="#008000" stroke-width=".21"/>
<circle cx="201.5" cy="114.1" r=".53" fill="#fff" stroke="#000" stroke-width=".21"/>
<circle cx="203.4" cy="112.2" r=".91" fill="#008000" stroke="#008000" stroke-width=".21"/>
<circle cx="203.4" cy="112.2" r=".53" fill="#fff" stroke="#000" stroke-width=".21"/>
<circle cx="201.5" cy="112.2" r=".91" fill="#008000" stroke="#008000" stroke-width=".21"/>
<circle cx="201.5" cy="112.2" r=".53" fill="#fff" stroke="#000" stroke-width=".21"/>
<circle cx="203.4" cy="110.3" r=".91" fill="#008000" stroke="#008000" stroke-width=".21"/>
<circle cx="203.4" cy="110.3" r=".53" fill="#fff" stroke="#000" stroke-width=".21"/>
<circle cx="201.5" cy="110.3" r=".91" fill="#008000" stroke="#008000" stroke-width=".21"/>
<circle cx="201.5" cy="110.3" r=".53" fill="#fff" stroke="#000" stroke-width=".21"/>
<circle cx="203.4" cy="108.4" r=".91" fill="#008000" stroke="#008000" stroke-width=".21"/>
<circle cx="203.4" cy="108.4" r=".53" fill="#fff" stroke="#000" stroke-width=".21"/>
<circle cx="201.5" cy="108.4" r=".91" fill="#008000" stroke="#008000" stroke-width=".21"/>
<circle cx="201.5" cy="108.4" r=".53" fill="#fff" stroke="#000" stroke-width=".21"/>
<circle cx="203.4" cy="106.5" r=".91" fill="#008000" stroke="#008000" stroke-width=".21"/>
<circle cx="203.4" cy="106.5" r=".53" fill="#fff" stroke="#000" stroke-width=".21"/>
<circle cx="201.5" cy="106.5" r=".91" fill="#008000" stroke="#008000" stroke-width=".21"/>
<circle cx="201.5" cy="106.5" r=".53" fill="#fff" stroke="#000" stroke-width=".21"/>
<circle cx="203.4" cy="104.6" r=".91" fill="#008000" stroke="#008000" stroke-width=".21"/>
<circle cx="203.4" cy="104.6" r=".53" fill="#fff" stroke="#000" stroke-width=".21"/>
<circle cx="201.5" cy="104.6" r=".91" fill="#008000" stroke="#008000" stroke-width=".21"/>
<circle cx="201.5" cy="104.6" r=".53" fill="#fff" stroke="#000" stroke-width=".21"/>
<circle cx="203.4" cy="102.7" r=".91" fill="#008000" stroke="#008000" stroke-width=".21"/>
<circle cx="203.4" cy="102.7" r=".53" fill="#fff" stroke="#000" stroke-width=".21"/>
<circle cx="201.5" cy="102.7" r=".91" fill="#008000" stroke="#008000" stroke-width=".21"/>
<circle cx="201.5" cy="102.7" r=".53" fill="#fff" stroke="#000" stroke-width=".21"/>
<circle cx="203.4" cy="100.8" r=".91" fill="#008000" stroke="#008000" stroke-width=".21"/>
<circle cx="203.4" cy="100.8" r=".53" fill="#fff" stroke="#000" stroke-width=".21"/>
<circle cx="201.5" cy="100.8" r=".91" fill="#008000" stroke="#008000" stroke-width=".21"/>
<circle cx="201.5" cy="100.8" r=".53" fill="#fff" stroke="#000" stroke-width=".21"/>
<circle cx="203.4" cy="98.9" r=".91" fill="#008000" stroke="#008000" stroke-width=".21"/>
<circle cx="203.4" cy="98.9" r=".53" fill="#fff" stroke="#000" stroke-width=".21"/>
<circle cx="201.5" cy="98.9" r=".91" fill="#008000" stroke="#008000" stroke-width=".21"/>
<circle cx="201.5" cy="98.9" r=".53" fill="#fff" stroke="#000" stroke-width=".21"/>
<circle cx="203.4" cy="97" r=".91" fill="#008000" stroke="#008000" stroke-width=".21"/>
<circle cx="203.4" cy="97" r=".53" fill="#fff" stroke="#000" stroke-width=".21"/>
<circle cx="201.5" cy="97" r=".91" fill="#008000" stroke="#008000" stroke-width=".21"/>
<circle cx="201.5" cy="97" r=".53" fill="#fff" stroke="#000" stroke-width=".21"/>
<circle cx="203.4" cy="95.1" r=".91" fill="#008000" stroke="#008000" stroke-width=".21"/>
<circle cx="203.4" cy="95.1" r=".53" fill="#fff" stroke="#000" stroke-width=".21"/>
<circle cx="201.5" cy="95.1" r=".91" fill="#008000" stroke="#008000" stroke-width=".21"/>
<circle cx="201.5" cy="95.1" r=".53" fill="#fff" stroke="#000" stroke-width=".21"/>
<circle cx="102.5" cy="41.4" r="1.14" fill="#008000" stroke="#008000" stroke-width=".21"/>
<circle cx="102.5" cy="41.4" r=".76" fill="#fff" stroke="#000" stroke-width=".21"/>
<circle cx="102.5" cy="37.5" r="1.14" fill="#008000" stroke="#008000" stroke-width=".21"/>
<circle cx="102.5" cy="37.5" r=".76" fill="#fff" stroke="#000" stroke-width=".21"/>
<circle cx="106.3" cy="41.4" r="1.14" fill="#008000" stroke="#008000" stroke-width=".21"/>
<circle cx="106.3" cy="41.4" r=".76" fill="#fff" stroke="#000" stroke-width=".21"/>
<circle cx="106.3" cy="37.5" r="1.14" fill="#008000" stroke="#008000" stroke-width=".21"/>
<circle cx="106.3" cy="37.5" r=".76" fill="#fff" stroke="#000" stroke-width=".21"/>
<circle cx="110.1" cy="41.4" r="1.14" fill="#008000" stroke="#008000" stroke-width=".21"/>
<circle cx="110.1" cy="41.4" r=".76" fill="#fff" stroke="#000" stroke-width=".21"/>
<circle cx="110.1" cy="37.5" r="1.14" fill="#008000" stroke="#008000" stroke-width=".21"/>
<circle cx="110.1" cy="37.5" r=".76" fill="#fff" stroke="#000" stroke-width=".21"/>
<circle cx="113.9" cy="41.4" r="1.14" fill="#008000" stroke="#008000" stroke-width=".21"/>
<circle cx="113.9" cy="41.4" r=".76" fill="#fff" stroke="#000" stroke-width=".21"/>
<circle cx="113.9" cy="37.5" r="1.14" fill="#008000" stroke="#008000" stroke-width=".21"/>
<circle cx="113.9" cy="37.5" r=".76" fill="#fff" stroke="#000" stroke-width=".21"/>
<circle cx="117.8" cy="41.4" r="1.14" fill="#008000" stroke="#008000" stroke-width=".21"/>
<circle cx="117.8" cy="41.4" r=".76" fill="#fff" stroke="#000" stroke-width=".21"/>
<circle cx="117.8" cy="37.5" r="1.14" fill="#008000" stroke="#008000" stroke-width=".21"/>
<circle cx="117.8" cy="37.5" r=".76" fill="#fff" stroke="#000" stroke-width=".21"/>
<circle cx="121.6" cy="41.4" r="1.14" fill="#008000" stroke="#008000" stroke-width=".21"/>
<circle cx="121.6" cy="41.4" r=".76" fill="#fff" stroke="#000" stroke-width=".21"/>
<circle cx="121.6" cy="37.5" r="1.14" fill="#008000" stroke="#008000" stroke-width=".21"/>
<circle cx="121.6" cy="37.5" r=".76" fill="#fff" stroke="#000" stroke-width=".21"/>
<circle cx="125.4" cy="41.4" r="1.14" fill="#008000" stroke="#008000" stroke-width=".21"/>
<circle cx="125.4" cy="41.4" r=".76" fill="#fff" stroke="#000" stroke-width=".21"/>
<circle cx="125.4" cy="37.5" r="1.14" fill="#008000" stroke="#008000" stroke-width=".21"/>
<circle cx="125.4" cy="37.5" r=".76" fill="#fff" stroke="#000" stroke-width=".21"/>
<circle cx="129.2" cy="41.4" r="1.14" fill="#008000" stroke="#008000" stroke-width=".21"/>
<circle cx="129.2" cy="41.4" r=".76" fill="#fff" stroke="#000" stroke-width=".21"/>
<circle cx="129.2" cy="37.5" r="1.14" fill="#008000" stroke="#008000" stroke-width=".21"/>
<circle cx="129.2" cy="37.5" r=".76" fill="#fff" stroke="#000" stroke-width=".21"/>
<circle cx="133" cy="41.4" r="1.14" fill="#008000" stroke="#008000" stroke-width=".21"/>
<circle cx="133" cy="41.4" r=".76" fill="#fff" stroke="#000" stroke-width=".21"/>
<circle cx="133" cy="37.5" r="1.14" fill="#008000" stroke="#008000" stroke-width=".21"/>
<circle cx="133" cy="37.5" r=".76" fill="#fff" stroke="#000" stroke-width=".21"/>
<circle cx="136.8" cy="41.4" r="1.14" fill="#008000" stroke="#008000" stroke-width=".21"/>
<circle cx="136.8" cy="41.4" r=".76" fill="#fff" stroke="#000" stroke-width=".21"/>
<circle cx="136.8" cy="37.5" r="1.14" fill="#008000" stroke="#008000" stroke-width=".21"/>
<circle cx="136.8" cy="37.5" r=".76" fill="#fff" stroke="#000" stroke-width=".21"/>
<circle cx="140.6" cy="41.4" r="1.14" fill="#008000" stroke="#008000" stroke-width=".21"/>
<circle cx="140.6" cy="41.4" r=".76" fill="#fff" stroke="#000" stroke-width=".21"/>
<circle cx="140.6" cy="37.5" r="1.14" fill="#008000" stroke="#008000" stroke-width=".21"/>
<circle cx="140.6" cy="37.5" r=".76" fill="#fff" stroke="#000" stroke-width=".21"/>
<circle cx="144.4" cy="41.4" r="1.14" fill="#008000" stroke="#008000" stroke-width=".21"/>
<circle cx="144.4" cy="41.4" r=".76" fill="#fff" stroke="#000" stroke-width=".21"/>
<circle cx="144.4" cy="37.5" r="1.14" fill="#008000" stroke="#008000" stroke-width=".21"/>
<circle cx="144.4" cy="37.5" r=".76" fill="#fff" stroke="#000" stroke-width=".21"/>
<circle cx="148.2" cy="41.4" r="1.14" fill="#008000" stroke="#008000" stroke-width=".21"/>
<circle cx="148.2" cy="41.4" r=".76" fill="#fff" stroke="#000" stroke-width=".21"/>
<circle cx="148.2" cy="37.5" r="1.14" fill="#008000" stroke="#008000" stroke-width=".21"/>
<circle cx="148.2" cy="37.5" r=".76" fill="#fff" stroke="#000" stroke-width=".21"/>
<circle cx="152" cy="41.4" r="1.14" fill="#008000" stroke="#008000" stroke-width=".21"/>
<circle cx="152" cy="41.4" r=".76" fill="#fff" stroke="#000" stroke-width=".21"/>
<circle cx="152" cy="37.5" r="1.14" fill="#008000" stroke="#008000" stroke-width=".21"/>
<circle cx="152" cy="37.5" r=".76" fill="#fff" stroke="#000" stroke-width=".21"/>
<circle cx="155.8" cy="41.4" r="1.14" fill="#008000" stroke="#008000" stroke-width=".21"/>
<circle cx="155.8" cy="41.4" r=".76" fill="#fff" stroke="#000" stroke-width=".21"/>
<circle cx="155.8" cy="37.5" r="1.14" fill="#008000" stroke="#008000" stroke-width=".21"/>
<circle cx="155.8" cy="37.5" r=".76" fill="#fff" stroke="#000" stroke-width=".21"/>
<circle cx="159.6" cy="41.4" r="1.14" fill="#008000" stroke="#008000" stroke-width=".21"/>
<circle cx="159.6" cy="41.4" r=".76" fill="#fff" stroke="#000" stroke-width=".21"/>
<circle cx="159.6" cy="37.5" r="1.14" fill="#008000" stroke="#008000" stroke-width=".21"/>
<circle cx="159.6" cy="37.5" r=".76" fill="#fff" stroke="#000" stroke-width=".21"/>
<circle cx="163.4" cy="41.4" r="1.14" fill="#008000" stroke="#008000" stroke-width=".21"/>
<circle cx="163.4" cy="41.4" r=".76" fill="#fff" stroke="#000" stroke-width=".21"/>
<circle cx="163.4" cy="37.5" r="1.14" fill="#008000" stroke="#008000" stroke-width=".21"/>
<circle cx="163.4" cy="37.5" r=".76" fill="#fff" stroke="#000" stroke-width=".21"/>
<circle cx="167.3" cy="41.4" r="1.14" fill="#008000" stroke="#008000" stroke-width=".21"/>
<circle cx="167.3" cy="41.4" r=".76" fill="#fff" stroke="#000" stroke-width=".21"/>
<circle cx="167.3" cy="37.5" r="1.14" fill="#008000" stroke="#008000" stroke-width=".21"/>
<circle cx="167.3" cy="37.5" r=".76" fill="#fff" stroke="#000" stroke-width=".21"/>
<circle cx="171.1" cy="41.4" r="1.14" fill="#008000" stroke="#008000" stroke-width=".21"/>
<circle cx="171.1" cy="41.4" r=".76" fill="#fff" stroke="#000" stroke-width=".21"/>
<circle cx="171.1" cy="37.5" r="1.14" fill="#008000" stroke="#008000" stroke-width=".21"/>
<circle cx="171.1" cy="37.5" r=".76" fill="#fff" stroke="#000" stroke-width=".21"/>
<circle cx="174.9" cy="41.4" r="1.14" fill="#008000" stroke="#008000" stroke-width=".21"/>
<circle cx="174.9" cy="41.4" r=".76" fill="#fff" stroke="#000" stroke-width=".21"/>
<circle cx="174.9" cy="37.5" r="1.14" fill="#008000" stroke="#008000" stroke-width=".21"/>
<circle cx="174.9" cy="37.5" r=".76" fill="#fff" stroke="#000" stroke-width=".21"/>
<circle cx="178.7" cy="41.4" r="1.14" fill="#008000" stroke="#008000" stroke-width=".21"/>
<circle cx="178.7" cy="41.4" r=".76" fill="#fff" stroke="#000" stroke-width=".21"/>
<circle cx="178.7" cy="37.5" r="1.14" fill="#008000" stroke="#008000" stroke-width=".21"/>
<circle cx="178.7" cy="37.5" r=".76" fill="#fff" stroke="#000" stroke-width=".21"/>
<circle cx="182.5" cy="41.4" r="1.14" fill="#008000" stroke="#008000" stroke-width=".21"/>
<circle cx="182.5" cy="41.4" r=".76" fill="#fff" stroke="#000" stroke-width=".21"/>
<circle cx="182.5" cy="37.5" r="1.14" fill="#008000" stroke="#008000" stroke-width=".21"/>
<circle cx="182.5" cy="37.5" r=".76" fill="#fff" stroke="#000" stroke-width=".21"/>
<circle cx="186.3" cy="41.4" r="1.14" fill="#008000" stroke="#008000" stroke-width=".21"/>
<circle cx="186.3" cy="41.4" r=".76" fill="#fff" stroke="#000" stroke-width=".21"/>
<circle cx="186.3" cy="37.5" r="1.14" fill="#008000" stroke="#008000" stroke-width=".21"/>
<circle cx="186.3" cy="37.5" r=".76" fill="#fff" stroke="#000" stroke-width=".21"/>
<circle cx="190.1" cy="41.4" r="1.14" fill="#008000" stroke="#008000" stroke-width=".21"/>
<circle cx="190.1" cy="41.4" r=".76" fill="#fff" stroke="#000" stroke-width=".21"/>
<circle cx="190.1" cy="37.5" r="1.14" fill="#008000" stroke="#008000" stroke-width=".21"/>
<circle cx="190.1" cy="37.5" r=".76" fill="#fff" stroke="#000" stroke-width=".21"/>
<circle cx="193.9" cy="41.4" r="1.14" fill="#008000" stroke="#008000" stroke-width=".21"/>
<circle cx="193.9" cy="41.4" r=".76" fill="#fff" stroke="#000" stroke-width=".21"/>
<circle cx="193.9" cy="37.5" r="1.14" fill="#008000" stroke="#008000" stroke-width=".21"/>
<circle cx="193.9" cy="37.5" r=".76" fill="#fff" stroke="#000" stroke-width=".21"/>
<circle cx="197.7" cy="41.4" r="1.14" fill="#008000" stroke="#008000" stroke-width=".21"/>
<circle cx="197.7" cy="41.4" r=".76" fill="#fff" stroke="#000" stroke-width=".21"/>
<circle cx="197.7" cy="37.5" r="1.14" fill="#008000" stroke="#008000" stroke-width=".21"/>
<circle cx="197.7" cy="37.5" r=".76" fill="#fff" stroke="#000" stroke-width=".21"/>
<circle cx="102.5" cy="49" r="1.14" fill="#008000" stroke="#008000" stroke-width=".21"/>
<circle cx="102.5" cy="49" r=".76" fill="#fff" stroke="#000" stroke-width=".21"/>
<circle cx="102.5" cy="45.1" r="1.14" fill="#008000" stroke="#008000" stroke-width=".21"/>
<circle cx="102.5" cy="45.1" r=".76" fill="#fff" stroke="#000" stroke-width=".21"/>
<circle cx="106.3" cy="49" r="1.14" fill="#008000" stroke="#008000" stroke-width=".21"/>
<circle cx="106.3" cy="49" r=".76" fill="#fff" stroke="#000" stroke-width=".21"/>
<circle cx="106.3" cy="45.1" r="1.14" fill="#008000" stroke="#008000" stroke-width=".21"/>
<circle cx="106.3" cy="45.1" r=".76" fill="#fff" stroke="#000" stroke-width=".21"/>
<circle cx="110.1" cy="49" r="1.14" fill="#008000" stroke="#008000" stroke-width=".21"/>
<circle cx="110.1" cy="49" r=".76" fill="#fff" stroke="#000" stroke-width=".21"/>
<circle cx="110.1" cy="45.1" r="1.14" fill="#008000" stroke="#008000" stroke-width=".21"/>
<circle cx="110.1" cy="45.1" r=".76" fill="#fff" stroke="#000" stroke-width=".21"/>
<circle cx="113.9" cy="49" r="1.14" fill="#008000" stroke="#008000" stroke-width=".21"/>
<circle cx="113.9" cy="49" r=".76" fill="#fff" stroke="#000" stroke-width=".21"/>
<circle cx="113.9" cy="45.1" r="1.14" fill="#008000" stroke="#008000" stroke-width=".21"/>
<circle cx="113.9" cy="45.1" r=".76" fill="#fff" stroke="#000" stroke-width=".21"/>
<circle cx="117.8" cy="49" r="1.14" fill="#008000" stroke="#008000" stroke-width=".21"/>
<circle cx="117.8" cy="49" r=".76" fill="#fff" stroke="#000" stroke-width=".21"/>
<circle cx="117.8" cy="45.1" r="1.14" fill="#008000" stroke="#008000" stroke-width=".21"/>
<circle cx="117.8" cy="45.1" r=".76" fill="#fff" stroke="#000" stroke-width=".21"/>
<circle cx="121.6" cy="49" r="1.14" fill="#008000" stroke="#008000" stroke-width=".21"/>
<circle cx="121.6" cy="49" r=".76" fill="#fff" stroke="#000" stroke-width=".21"/>
<circle cx="121.6" cy="45.1" r="1.14" fill="#008000" stroke="#008000" stroke-width=".21"/>
<circle cx="121.6" cy="45.1" r=".76" fill="#fff" stroke="#000" stroke-width=".21"/>
<circle cx="125.4" cy="49" r="1.14" fill="#008000" stroke="#008000" stroke-width=".21"/>
<circle cx="125.4" cy="49" r=".76" fill="#fff" stroke="#000" stroke-width=".21"/>
<circle cx="125.4" cy="45.1" r="1.14" fill="#008000" stroke="#008000" stroke-width=".21"/>
<circle cx="125.4" cy="45.1" r=".76" fill="#fff" stroke="#000" stroke-width=".21"/>
<circle cx="129.2" cy="49" r="1.14" fill="#008000" stroke="#008000" stroke-width=".21"/>
<circle cx="129.2" cy="49" r=".76" fill="#fff" stroke="#000" stroke-width=".21"/>
<circle cx="129.2" cy="45.1" r="1.14" fill="#008000" stroke="#008000" stroke-width=".21"/>
<circle cx="129.2" cy="45.1" r=".76" fill="#fff" stroke="#000" stroke-width=".21"/>
<circle cx="133" cy="49" r="1.14" fill="#008000" stroke="#008000" stroke-width=".21"/>
<circle cx="133" cy="49" r=".76" fill="#fff" stroke="#000" stroke-width=".21"/>
<circle cx="133" cy="45.1" r="1.14" fill="#008000" stroke="#008000" stroke-width=".21"/>
<circle cx="133" cy="45.1" r=".76" fill="#fff" stroke="#000" stroke-width=".21"/>
<circle cx="136.8" cy="49" r="1.14" fill="#008000" stroke="#008000" stroke-width=".21"/>
<circle cx="136.8" cy="49" r=".76" fill="#fff" stroke="#000" stroke-width=".21"/>
<circle cx="136.8" cy="45.1" r="1.14" fill="#008000" stroke="#008000" stroke-width=".21"/>
<circle cx="136.8" cy="45.1" r=".76" fill="#fff" stroke="#000" stroke-width=".21"/>
<circle cx="140.6" cy="49" r="1.14" fill="#008000" stroke="#008000" stroke-width=".21"/>
<circle cx="140.6" cy="49" r=".76" fill="#fff" stroke="#000" stroke-width=".21"/>
<circle cx="140.6" cy="45.1" r="1.14" fill="#008000" stroke="#008000" stroke-width=".21"/>
<circle cx="140.6" cy="45.1" r=".76" fill="#fff" stroke="#000" stroke-width=".21"/>
<circle cx="144.4" cy="49" r="1.14" fill="#008000" stroke="#008000" stroke-width=".21"/>
<circle cx="144.4" cy="49" r=".76" fill="#fff" stroke="#000" stroke-width=".21"/>
<circle cx="144.4" cy="45.1" r="1.14" fill="#008000" stroke="#008000" stroke-width=".21"/>
<circle cx="144.4" cy="45.1" r=".76" fill="#fff" stroke="#000" stroke-width=".21"/>
<circle cx="148.2" cy="49" r="1.14" fill="#008000" stroke="#008000" stroke-width=".21"/>
<circle cx="148.2" cy="49" r=".76" fill="#fff" stroke="#000" stroke-width=".21"/>
<circle cx="148.2" cy="45.1" r="1.14" fill="#008000" stroke="#008000" stroke-width=".21"/>
<circle cx="148.2" cy="45.1" r=".76" fill="#fff" stroke="#000" stroke-width=".21"/>
<circle cx="152" cy="49" r="1.14" fill="#008000" stroke="#008000" stroke-width=".21"/>
<circle cx="152" cy="49" r=".76" fill="#fff" stroke="#000" stroke-width=".21"/>
<circle cx="152" cy="45.1" r="1.14" fill="#008000" stroke="#008000" stroke-width=".21"/>
<circle cx="152" cy="45.1" r=".76" fill="#fff" stroke="#000" stroke-width=".21"/>
<circle cx="155.9" cy="49" r="1.14" fill="#008000" stroke="#008000" stroke-width=".21"/>
<circle cx="155.9" cy="49" r=".76" fill="#fff" stroke="#000" stroke-width=".21"/>
<circle cx="155.9" cy="45.1" r="1.14" fill="#008000" stroke="#008000" stroke-width=".21"/>
<circle cx="155.9" cy="45.1" r=".76" fill="#fff" stroke="#000" stroke-width=".21"/>
<circle cx="159.7" cy="49" r="1.14" fill="#008000" stroke="#008000" stroke-width=".21"/>
<circle cx="159.7" cy="49" r=".76" fill="#fff" stroke="#000" stroke-width=".21"/>
<circle cx="159.7" cy="45.1" r="1.14" fill="#008000" stroke="#008000" stroke-width=".21"/>
<circle cx="159.7" cy="45.1" r=".76" fill="#fff" stroke="#000" stroke-width=".21"/>
<circle cx="163.5" cy="49" r="1.14" fill="#008000" stroke="#008000" stroke-width=".21"/>
<circle cx="163.5" cy="49" r=".76" fill="#fff" stroke="#000" stroke-width=".21"/>
<circle cx="163.5" cy="45.1" r="1.14" fill="#008000" stroke="#008000" stroke-width=".21"/>
<circle cx="163.5" cy="45.1" r=".76" fill="#fff" stroke="#000" stroke-width=".21"/>
<circle cx="167.3" cy="49" r="1.14" fill="#008000" stroke="#008000" stroke-width=".21"/>
<circle cx="167.3" cy="49" r=".76" fill="#fff" stroke="#000" stroke-width=".21"/>
<circle cx="167.3" cy="45.1" r="1.14" fill="#008000" stroke="#008000" stroke-width=".21"/>
<circle cx="167.3" cy="45.1" r=".76" fill="#fff" stroke="#000" stroke-width=".21"/>
<circle cx="171.1" cy="49" r="1.14" fill="#008000" stroke="#008000" stroke-width=".21"/>
<circle cx="171.1" cy="49" r=".76" fill="#fff" stroke="#000" stroke-width=".21"/>
<circle cx="171.1" cy="45.1" r="1.14" fill="#008000" stroke="#008000" stroke-width=".21"/>
<circle cx="171.1" cy="45.1" r=".76" fill="#fff" stroke="#000" stroke-width=".21"/>
<circle cx="174.9" cy="49" r="1.14" fill="#008000" stroke="#008000" stroke-width=".21"/>
<circle cx="174.9" cy="49" r=".76" fill="#fff" stroke="#000" stroke-width=".21"/>
<circle cx="174.9" cy="45.1" r="1.14" fill="#008000" stroke="#008000" stroke-width=".21"/>
<circle cx="174.9" cy="45.1" r=".76" fill="#fff" stroke="#000" stroke-width=".21"/>
<circle cx="178.7" cy="49" r="1.14" fill="#008000" stroke="#008000" stroke-width=".21"/>
<circle cx="178.7" cy="49" r=".76" fill="#fff" stroke="#000" stroke-width=".21"/>
<circle cx="178.7" cy="45.1" r="1.14" fill="#008000" stroke="#008000" stroke-width=".21"/>
<circle cx="178.7" cy="45.1" r=".76" fill="#fff" stroke="#000" stroke-width=".21"/>
<circle cx="182.5" cy="49" r="1.14" fill="#008000" stroke="#008000" stroke-width=".21"/>
<circle cx="182.5" cy="49" r=".76" fill="#fff" stroke="#000" stroke-width=".21"/>
<circle cx="182.5" cy="45.1" r="1.14" fill="#008000" stroke="#008000" stroke-width=".21"/>
<circle cx="182.5" cy="45.1" r=".76" fill="#fff" stroke="#000" stroke-width=".21"/>
<circle cx="186.3" cy="49" r="1.14" fill="#008000" stroke="#008000" stroke-width=".21"/>
<circle cx="186.3" cy="49" r=".76" fill="#fff" stroke="#000" stroke-width=".21"/>
<circle cx="186.3" cy="45.1" r="1.14" fill="#008000" stroke="#008000" stroke-width=".21"/>
<circle cx="186.3" cy="45.1" r=".76" fill="#fff" stroke="#000" stroke-width=".21"/>
<circle cx="190.1" cy="49" r="1.14" fill="#008000" stroke="#008000" stroke-width=".21"/>
<circle cx="190.1" cy="49" r=".76" fill="#fff" stroke="#000" stroke-width=".21"/>
<circle cx="190.1" cy="45.1" r="1.14" fill="#008000" stroke="#008000" stroke-width=".21"/>
<circle cx="190.1" cy="45.1" r=".76" fill="#fff" stroke="#000" stroke-width=".21"/>
<circle cx="193.9" cy="49" r="1.14" fill="#008000" stroke="#008000" stroke-width=".21"/>
<circle cx="193.9" cy="49" r=".76" fill="#fff" stroke="#000" stroke-width=".21"/>
<circle cx="193.9" cy="45.1" r="1.14" fill="#008000" stroke="#008000" stroke-width=".21"/>
<circle cx="193.9" cy="45.1" r=".76" fill="#fff" stroke="#000" stroke-width=".21"/>
<circle cx="197.7" cy="49" r="1.14" fill="#008000" stroke="#008000" stroke-width=".21"/>
<circle cx="197.7" cy="49" r=".76" fill="#fff" stroke="#000" stroke-width=".21"/>
<circle cx="197.7" cy="45.1" r="1.14" fill="#008000" stroke="#008000" stroke-width=".21"/>
<circle cx="197.7" cy="45.1" r=".76" fill="#fff" stroke="#000" stroke-width=".21"/>
<circle cx="202.1" cy="81" r="1.8" fill="#008000" stroke="#008000" stroke-width=".21"/>
<circle cx="202.1" cy="81" r="1.21" fill="#fff" stroke="#000" stroke-width=".21"/>
<circle cx="202.1" cy="75" r="1.8" fill="#008000" stroke="#008000" stroke-width=".21"/>
<circle cx="202.1" cy="75" r="1.21" fill="#fff" stroke="#000" stroke-width=".21"/>
<circle cx="202.1" cy="69" r="1.8" fill="#008000" stroke="#008000" stroke-width=".21"/>
<circle cx="202.1" cy="69" r="1.21" fill="#fff" stroke="#000" stroke-width=".21"/>
<circle cx="202.1" cy="63" r="1.8" fill="#008000" stroke="#008000" stroke-width=".21"/>
<circle cx="202.1" cy="63" r="1.21" fill="#fff" stroke="#000" stroke-width=".21"/>
<circle cx="202.1" cy="87" r="2.41" fill="#008000" stroke="#008000" stroke-width=".21"/>
<circle cx="202.1" cy="87" r="1.65" fill="#fff" stroke="#000" stroke-width=".21"/>
<circle cx="202.1" cy="57" r="2.41" fill="#008000" stroke="#008000" stroke-width=".21"/>
<circle cx="202.1" cy="57" r="1.65" fill="#fff" stroke="#000" stroke-width=".21"/>
<circle cx="211.6" cy="62.9" r="1.8" fill="#008000" stroke="#008000" stroke-width=".21"/>
<circle cx="211.6" cy="62.9" r="1.21" fill="#fff" stroke="#000" stroke-width=".21"/>
<circle cx="211.6" cy="68.9" r="1.8" fill="#008000" stroke="#008000" stroke-width=".21"/>
<circle cx="211.6" cy="68.9" r="1.21" fill="#fff" stroke="#000" stroke-width=".21"/>
<circle cx="211.6" cy="74.9" r="1.8" fill="#008000" stroke="#008000" stroke-width=".21"/>
<circle cx="211.6" cy="74.9" r="1.21" fill="#fff" stroke="#000" stroke-width=".21"/>
<circle cx="211.6" cy="80.9" r="1.8" fill="#008000" stroke="#008000" stroke-width=".21"/>
<circle cx="211.6" cy="80.9" r="1.21" fill="#fff" stroke="#000" stroke-width=".21"/>
<circle cx="211.6" cy="86.9" r="1.8" fill="#008000" stroke="#008000" stroke-width=".21"/>
<circle cx="211.6" cy="86.9" r="1.21" fill="#fff" stroke="#000" stroke-width=".21"/>
<circle cx="211.6" cy="92.9" r="1.8" fill="#008000" stroke="#008000" stroke-width=".21"/>
<circle cx="211.6" cy="92.9" r="1.21" fill="#fff" stroke="#000" stroke-width=".21"/>
<circle cx="211.6" cy="98.9" r="1.8" fill="#008000" stroke="#008000" stroke-width=".21"/>
<circle cx="211.6" cy="98.9" r="1.21" fill="#fff" stroke="#000" stroke-width=".21"/>
<circle cx="211.6" cy="104.9" r="1.8" fill="#008000" stroke="#008000" stroke-width=".21"/>
<circle cx="211.6" cy="104.9" r="1.21" fill="#fff" stroke="#000" stroke-width=".21"/>
<circle cx="211.6" cy="110.9" r="1.8" fill="#008000" stroke="#008000" stroke-width=".21"/>
<circle cx="211.6" cy="110.9" r="1.21" fill="#fff" stroke="#000" stroke-width=".21"/>
<circle cx="211.6" cy="116.9" r="1.8" fill="#008000" stroke="#008000" stroke-width=".21"/>
<circle cx="211.6" cy="116.9" r="1.21" fill="#fff" stroke="#000" stroke-width=".21"/>
<circle cx="211.6" cy="56.9" r="2.41" fill="#008000" stroke="#008000" stroke-width=".21"/>
<circle cx="211.6" cy="56.9" r="1.65" fill="#fff" stroke="#000" stroke-width=".21"/>
<circle cx="211.6" cy="122.9" r="2.41" fill="#008000" stroke="#008000" stroke-width=".21"/>
<circle cx="211.6" cy="122.9" r="1.65" fill="#fff" stroke="#000" stroke-width=".21"/>
<circle cx="143.4" cy="98.6" r=".99" fill="#008000" stroke="#008000" stroke-width=".21"/>
<circle cx="143.4" cy="98.6" r=".61" fill="#fff" stroke="#000" stroke-width=".21"/>
<circle cx="139.6" cy="98.6" r=".99" fill="#008000" stroke="#008000" stroke-width=".21"/>
<circle cx="139.6" cy="98.6" r=".61" fill="#fff" stroke="#000" stroke-width=".21"/>
<circle cx="115.6" cy="133.7" r=".68" fill="#008000" stroke="#008000" stroke-width=".21"/>
<circle cx="115.6" cy="133.7" r=".38" fill="#fff" stroke="#000" stroke-width=".21"/>
<circle cx="115.7" cy="139.7" r=".68" fill="#008000" stroke="#008000" stroke-width=".21"/>
<circle cx="115.7" cy="139.7" r=".38" fill="#fff" stroke="#000" stroke-width=".21"/>
<circle cx="104.4" cy="122.8" r=".68" fill="#008000" stroke="#008000" stroke-width=".21"/>
<circle cx="104.4" cy="122.8" r=".38" fill="#fff" stroke="#000" stroke-width=".21"/>
<circle cx="98.9" cy="131.3" r=".68" fill="#008000" stroke="#008000" stroke-width=".21"/>
<circle cx="98.9" cy="131.3" r=".38" fill="#fff" stroke="#000" stroke-width=".21"/>
<circle cx="187.6" cy="151.8" r=".68" fill="#008000" stroke="#008000" stroke-width=".21"/>
<circle cx="187.6" cy="151.8" r=".38" fill="#fff" stroke="#000" stroke-width=".21"/>
<circle cx="181.5" cy="151.8" r=".68" fill="#008000" stroke="#008000" stroke-width=".21"/>
<circle cx="181.5" cy="151.8" r=".38" fill="#fff" stroke="#000" stroke-width=".21"/>
<circle cx="169.7" cy="39.4" r=".68" fill="#008000" stroke="#008000" stroke-width=".21"/>
<circle cx="169.7" cy="39.4" r=".38" fill="#fff" stroke="#000" stroke-width=".21"/>
<circle cx="137.2" cy="52.9" r=".76" fill="#008000" stroke="#008000" stroke-width=".21"/>
<circle cx="137.2" cy="52.9" r=".47" fill="#fff" stroke="#000" stroke-width=".21"/>
<circle cx="112.4" cy="53.7" r=".76" fill="#008000" stroke="#008000" stroke-width=".21"/>
<circle cx="112.4" cy="53.7" r=".47" fill="#fff" stroke="#000" stroke-width=".21"/>
<circle cx="112.3" cy="76.2" r=".68" fill="#008000" stroke="#008000" stroke-width=".21"/>
<circle cx="112.3" cy="76.2" r=".38" fill="#fff" stroke="#000" stroke-width=".21"/>
<circle cx="124.7" cy="79.6" r=".68" fill="#008000" stroke="#008000" stroke-width=".21"/>
<circle cx="124.7" cy="79.6" r=".38" fill="#fff" stroke="#000" stroke-width=".21"/>
<circle cx="129.8" cy="79.7" r=".68" fill="#008000" stroke="#008000" stroke-width=".21"/>
<circle cx="129.8" cy="79.7" r=".38" fill="#fff" stroke="#000" stroke-width=".21"/>
<circle cx="136.5" cy="79.7" r=".68" fill="#008000" stroke="#008000" stroke-width=".21"/>
<circle cx="136.5" cy="79.7" r=".38" fill="#fff" stroke="#000" stroke-width=".21"/>
<circle cx="113.6" cy="100.4" r=".68" fill="#008000" stroke="#008000" stroke-width=".21"/>
<circle cx="113.6" cy="100.4" r=".38" fill="#fff" stroke="#000" stroke-width=".21"/>
<circle cx="116.6" cy="97.3" r=".68" fill="#008000" stroke="#008000" stroke-width=".21"/>
<circle cx="116.6" cy="97.3" r=".38" fill="#fff" stroke="#000" stroke-width=".21"/>
<circle cx="113.2" cy="95" r=".68" fill="#008000" stroke="#008000" stroke-width=".21"/>
<circle cx="113.2" cy="95" r=".38" fill="#fff" stroke="#000" stroke-width=".21"/>
<circle cx="144.4" cy="53.8" r=".76" fill="#008000" stroke="#008000" stroke-width=".21"/>
<circle cx="144.4" cy="53.8" r=".44" fill="#fff" stroke="#000" stroke-width=".21"/>
<circle cx="193.3" cy="149.3" r=".68" fill="#008000" stroke="#008000" stroke-width=".21"/>
<circle cx="193.3" cy="149.3" r=".38" fill="#fff" stroke="#000" stroke-width=".21"/>
<circle cx="201.7" cy="146.7" r=".68" fill="#008000" stroke="#008000" stroke-width=".21"/>
<circle cx="201.7" cy="146.7" r=".38" fill="#fff" stroke="#000" stroke-width=".21"/>
<circle cx="171.2" cy="134.6" r=".68" fill="#008000" stroke="#008000" stroke-width=".21"/>
<circle cx="171.2" cy="134.6" r=".38" fill="#fff" stroke="#000" stroke-width=".21"/>
<circle cx="171.3" cy="127.9" r=".68" fill="#008000" stroke="#008000" stroke-width=".21"/>
<circle cx="171.3" cy="127.9" r=".38" fill="#fff" stroke="#000" stroke-width=".21"/>
<circle cx="119.4" cy="88.2" r=".76" fill="#008000" stroke="#008000" stroke-width=".21"/>
<circle cx="119.4" cy="88.2" r=".47" fill="#fff" stroke="#000" stroke-width=".21"/>
<circle cx="111.5" cy="101" r=".68" fill="#008000" stroke="#008000" stroke-width=".21"/>
<circle cx="111.5" cy="101" r=".38" fill="#fff" stroke="#000" stroke-width=".21"/>
<circle cx="114.2" cy="117.4" r=".68" fill="#008000" stroke="#008000" stroke-width=".21"/>
<circle cx="114.2" cy="117.4" r=".38" fill="#fff" stroke="#000" stroke-width=".21"/>
<circle cx="117.2" cy="120.5" r=".68" fill="#008000" stroke="#008000" stroke-width=".21"/>
<circle cx="117.2" cy="120.5" r=".38" fill="#fff" stroke="#000" stroke-width=".21"/>
<circle cx="116.3" cy="127.8" r=".68" fill="#008000" stroke="#008000" stroke-width=".21"/>
<circle cx="116.3" cy="127.8" r=".38" fill="#fff" stroke="#000" stroke-width=".21"/>
<circle cx="176.6" cy="134.5" r=".68" fill="#008000" stroke="#008000" stroke-width=".21"/>
<circle cx="176.6" cy="134.5" r=".38" fill="#fff" stroke="#000" stroke-width=".21"/>
<circle cx="175.3" cy="109.7" r=".68" fill="#008000" stroke="#008000" stroke-width=".21"/>
<circle cx="175.3" cy="109.7" r=".38" fill="#fff" stroke="#000" stroke-width=".21"/>
<circle cx="178.8" cy="113.8" r=".76" fill="#008000" stroke="#008000" stroke-width=".21"/>
<circle cx="178.8" cy="113.8" r=".47" fill="#fff" stroke="#000" stroke-width=".21"/>
<circle cx="186.7" cy="127.5" r=".68" fill="#008000" stroke="#008000" stroke-width=".21"/>
<circle cx="186.7" cy="127.5" r=".38" fill="#fff" stroke="#000" stroke-width=".21"/>
<circle cx="182.8" cy="141.2" r=".68" fill="#008000" stroke="#008000" stroke-width=".21"/>
<circle cx="182.8" cy="141.2" r=".38" fill="#fff" stroke="#000" stroke-width=".21"/>
<circle cx="175.7" cy="164.7" r=".76" fill="#008000" stroke="#008000" stroke-width=".21"/>
<circle cx="175.7" cy="164.7" r=".47" fill="#fff" stroke="#000" stroke-width=".21"/>
<circle cx="123.3" cy="82.1" r=".68" fill="#008000" stroke="#008000" stroke-width=".21"/>
<circle cx="123.3" cy="82.1" r=".38" fill="#fff" stroke="#000" stroke-width=".21"/>
<circle cx="131.1" cy="111.4" r=".68" fill="#008000" stroke="#008000" stroke-width=".21"/>
<circle cx="131.1" cy="111.4" r=".38" fill="#fff" stroke="#000" stroke-width=".21"/>
<circle cx="139.6" cy="127.3" r=".68" fill="#008000" stroke="#008000" stroke-width=".21"/>
<circle cx="139.6" cy="127.3" r=".38" fill="#fff" stroke="#000" stroke-width=".21"/>
<circle cx="161.7" cy="124.1" r=".76" fill="#008000" stroke="#008000" stroke-width=".21"/>
<circle cx="161.7" cy="124.1" r=".47" fill="#fff" stroke="#000" stroke-width=".21"/>
<circle cx="161.4" cy="118" r=".76" fill="#008000" stroke="#008000" stroke-width=".21"/>
<circle cx="161.4" cy="118" r=".47" fill="#fff" stroke="#000" stroke-width=".21"/>
<circle cx="165.7" cy="113.8" r=".76" fill="#008000" stroke="#008000" stroke-width=".21"/>
<circle cx="165.7" cy="113.8" r=".47" fill="#fff" stroke="#000" stroke-width=".21"/>
<circle cx="131.9" cy="134.3" r=".68" fill="#008000" stroke="#008000" stroke-width=".21"/>
<circle cx="131.9" cy="134.3" r=".38" fill="#fff" stroke="#000" stroke-width=".21"/>
<circle cx="129.2" cy="115.3" r=".68" fill="#008000" stroke="#008000" stroke-width=".21"/>
<circle cx="129.2" cy="115.3" r=".38" fill="#fff" stroke="#000" stroke-width=".21"/>
<circle cx="126.4" cy="134.2" r=".68" fill="#008000" stroke="#008000" stroke-width=".21"/>
<circle cx="126.4" cy="134.2" r=".38" fill="#fff" stroke="#000" stroke-width=".21"/>
<circle cx="126.4" cy="127.7" r=".68" fill="#008000" stroke="#008000" stroke-width=".21"/>
<circle cx="126.4" cy="127.7" r=".38" fill="#fff" stroke="#000" stroke-width=".21"/>
<circle cx="137.4" cy="134.5" r=".68" fill="#008000" stroke="#008000" stroke-width=".21"/>
<circle cx="137.4" cy="134.5" r=".38" fill="#fff" stroke="#000" stroke-width=".21"/>
<circle cx="137.5" cy="128" r=".68" fill="#008000" stroke="#008000" stroke-width=".21"/>
<circle cx="137.5" cy="128" r=".38" fill="#fff" stroke="#000" stroke-width=".21"/>
<circle cx="135" cy="120.3" r=".68" fill="#008000" stroke="#008000" stroke-width=".21"/>
<circle cx="135" cy="120.3" r=".38" fill="#fff" stroke="#000" stroke-width=".21"/>
<circle cx="139.3" cy="116.1" r=".68" fill="#008000" stroke="#008000" stroke-width=".21"/>
<circle cx="139.3" cy="116.1" r=".38" fill="#fff" stroke="#000" stroke-width=".21"/>
<circle cx="137.2" cy="113.5" r=".68" fill="#008000" stroke="#008000" stroke-width=".21"/>
<circle cx="137.2" cy="113.5" r=".38" fill="#fff" stroke="#000" stroke-width=".21"/>
<circle cx="131" cy="88.3" r=".68" fill="#008000" stroke="#008000" stroke-width=".21"/>
<circle cx="131" cy="88.3" r=".38" fill="#fff" stroke="#000" stroke-width=".21"/>
<circle cx="129.8" cy="82.2" r=".68" fill="#008000" stroke="#008000" stroke-width=".21"/>
<circle cx="129.8" cy="82.2" r=".38" fill="#fff" stroke="#000" stroke-width=".21"/>
<circle cx="123.4" cy="39.5" r=".76" fill="#008000" stroke="#008000" stroke-width=".21"/>
<circle cx="123.4" cy="39.5" r=".47" fill="#fff" stroke="#000" stroke-width=".21"/>
<circle cx="129.7" cy="60.7" r=".68" fill="#008000" stroke="#008000" stroke-width=".21"/>
<circle cx="129.7" cy="60.7" r=".38" fill="#fff" stroke="#000" stroke-width=".21"/>
<circle cx="133.6" cy="62.8" r=".68" fill="#008000" stroke="#008000" stroke-width=".21"/>
<circle cx="133.6" cy="62.8" r=".38" fill="#fff" stroke="#000" stroke-width=".21"/>
<circle cx="133.6" cy="67.6" r=".68" fill="#008000" stroke="#008000" stroke-width=".21"/>
<circle cx="133.6" cy="67.6" r=".38" fill="#fff" stroke="#000" stroke-width=".21"/>
<circle cx="190.5" cy="101.4" r=".68" fill="#008000" stroke="#008000" stroke-width=".21"/>
<circle cx="190.5" cy="101.4" r=".38" fill="#fff" stroke="#000" stroke-width=".21"/>
<circle cx="146.7" cy="95.3" r=".68" fill="#008000" stroke="#008000" stroke-width=".21"/>
<circle cx="146.7" cy="95.3" r=".38" fill="#fff" stroke="#000" stroke-width=".21"/>
<circle cx="170.9" cy="61" r=".68" fill="#008000" stroke="#008000" stroke-width=".21"/>
<circle cx="170.9" cy="61" r=".38" fill="#fff" stroke="#000" stroke-width=".21"/>
<circle cx="171.5" cy="64.7" r=".68" fill="#008000" stroke="#008000" stroke-width=".21"/>
<circle cx="171.5" cy="64.7" r=".38" fill="#fff" stroke="#000" stroke-width=".21"/>
<circle cx="194.3" cy="64.7" r=".68" fill="#008000" stroke="#008000" stroke-width=".21"/>
<circle cx="194.3" cy="64.7" r=".38" fill="#fff" stroke="#000" stroke-width=".21"/>
<circle cx="199.2" cy="69.6" r=".68" fill="#008000" stroke="#008000" stroke-width=".21"/>
<circle cx="199.2" cy="69.6" r=".38" fill="#fff" stroke="#000" stroke-width=".21"/>
<circle cx="192.8" cy="88.4" r=".68" fill="#008000" stroke="#008000" stroke-width=".21"/>
<circle cx="192.8" cy="88.4" r=".38" fill="#fff" stroke="#000" stroke-width=".21"/>
<circle cx="165.1" cy="85.3" r=".68" fill="#008000" stroke="#008000" stroke-width=".21"/>
<circle cx="165.1" cy="85.3" r=".38" fill="#fff" stroke="#000" stroke-width=".21"/>
<circle cx="161.3" cy="85.5" r=".68" fill="#008000" stroke="#008000" stroke-width=".21"/>
<circle cx="161.3" cy="85.5" r=".38" fill="#fff" stroke="#000" stroke-width=".21"/>
<circle cx="156.8" cy="80.9" r=".68" fill="#008000" stroke="#008000" stroke-width=".21"/>
<circle cx="156.8" cy="80.9" r=".38" fill="#fff" stroke="#000" stroke-width=".21"/>
<circle cx="149.5" cy="80.9" r=".68" fill="#008000" stroke="#008000" stroke-width=".21"/>
<circle cx="149.5" cy="80.9" r=".38" fill="#fff" stroke="#000" stroke-width=".21"/>
<circle cx="136.5" cy="83.8" r=".68" fill="#008000" stroke="#008000" stroke-width=".21"/>
<circle cx="136.5" cy="83.8" r=".38" fill="#fff" stroke="#000" stroke-width=".21"/>
<circle cx="133.6" cy="83.9" r=".68" fill="#008000" stroke="#008000" stroke-width=".21"/>
<circle cx="133.6" cy="83.9" r=".38" fill="#fff" stroke="#000" stroke-width=".21"/>
<circle cx="133.6" cy="77.6" r=".68" fill="#008000" stroke="#008000" stroke-width=".21"/>
<circle cx="133.6" cy="77.6" r=".38" fill="#fff" stroke="#000" stroke-width=".21"/>
<circle cx="129.8" cy="77.7" r=".68" fill="#008000" stroke="#008000" stroke-width=".21"/>
<circle cx="129.8" cy="77.7" r=".38" fill="#fff" stroke="#000" stroke-width=".21"/>
<circle cx="124.6" cy="77.7" r=".68" fill="#008000" stroke="#008000" stroke-width=".21"/>
<circle cx="124.6" cy="77.7" r=".38" fill="#fff" stroke="#000" stroke-width=".21"/>
<circle cx="117.8" cy="71.7" r=".68" fill="#008000" stroke="#008000" stroke-width=".21"/>
<circle cx="117.8" cy="71.7" r=".38" fill="#fff" stroke="#000" stroke-width=".21"/>
<circle cx="154.7" cy="134.3" r=".68" fill="#008000" stroke="#008000" stroke-width=".21"/>
<circle cx="154.7" cy="134.3" r=".38" fill="#fff" stroke="#000" stroke-width=".21"/>
<circle cx="169.5" cy="107.5" r=".68" fill="#008000" stroke="#008000" stroke-width=".21"/>
<circle cx="169.5" cy="107.5" r=".38" fill="#fff" stroke="#000" stroke-width=".21"/>
<circle cx="106" cy="120.7" r=".68" fill="#008000" stroke="#008000" stroke-width=".21"/>
<circle cx="106" cy="120.7" r=".38" fill="#fff" stroke="#000" stroke-width=".21"/>
<circle cx="130.3" cy="125.9" r=".68" fill="#008000" stroke="#008000" stroke-width=".21"/>
<circle cx="130.3" cy="125.9" r=".38" fill="#fff" stroke="#000" stroke-width=".21"/>
<circle cx="133.8" cy="126" r=".68" fill="#008000" stroke="#008000" stroke-width=".21"/>
<circle cx="133.8" cy="126" r=".38" fill="#fff" stroke="#000" stroke-width=".21"/>
<circle cx="144.6" cy="126" r=".68" fill="#008000" stroke="#008000" stroke-width=".21"/>
<circle cx="144.6" cy="126" r=".38" fill="#fff" stroke="#000" stroke-width=".21"/>
<circle cx="147.5" cy="125.9" r=".68" fill="#008000" stroke="#008000" stroke-width=".21"/>
<circle cx="147.5" cy="125.9" r=".38" fill="#fff" stroke="#000" stroke-width=".21"/>
<circle cx="165.8" cy="134.4" r=".68" fill="#008000" stroke="#008000" stroke-width=".21"/>
<circle cx="165.8" cy="134.4" r=".38" fill="#fff" stroke="#000" stroke-width=".21"/>
<circle cx="172.3" cy="108.6" r=".68" fill="#008000" stroke="#008000" stroke-width=".21"/>
<circle cx="172.3" cy="108.6" r=".38" fill="#fff" stroke="#000" stroke-width=".21"/>
<circle cx="154" cy="113.6" r=".76" fill="#008000" stroke="#008000" stroke-width=".21"/>
<circle cx="154" cy="113.6" r=".44" fill="#fff" stroke="#000" stroke-width=".21"/>
<circle cx="147.5" cy="113.6" r=".68" fill="#008000" stroke="#008000" stroke-width=".21"/>
<circle cx="147.5" cy="113.6" r=".38" fill="#fff" stroke="#000" stroke-width=".21"/>
<circle cx="144.7" cy="113.7" r=".68" fill="#008000" stroke="#008000" stroke-width=".21"/>
<circle cx="144.7" cy="113.7" r=".38" fill="#fff" stroke="#000" stroke-width=".21"/>
<circle cx="133.5" cy="117.7" r=".68" fill="#008000" stroke="#008000" stroke-width=".21"/>
<circle cx="133.5" cy="117.7" r=".38" fill="#fff" stroke="#000" stroke-width=".21"/>
<circle cx="128.5" cy="117.7" r=".68" fill="#008000" stroke="#008000" stroke-width=".21"/>
<circle cx="128.5" cy="117.7" r=".38" fill="#fff" stroke="#000" stroke-width=".21"/>
<circle cx="115.5" cy="105.4" r=".76" fill="#008000" stroke="#008000" stroke-width=".21"/>
<circle cx="115.5" cy="105.4" r=".44" fill="#fff" stroke="#000" stroke-width=".21"/>
<circle cx="119.1" cy="100.4" r=".68" fill="#008000" stroke="#008000" stroke-width=".21"/>
<circle cx="119.1" cy="100.4" r=".38" fill="#fff" stroke="#000" stroke-width=".21"/>
<circle cx="126.8" cy="67.7" r=".68" fill="#008000" stroke="#008000" stroke-width=".21"/>
<circle cx="126.8" cy="67.7" r=".38" fill="#fff" stroke="#000" stroke-width=".21"/>
<circle cx="124.6" cy="70.6" r=".68" fill="#008000" stroke="#008000" stroke-width=".21"/>
<circle cx="124.6" cy="70.6" r=".38" fill="#fff" stroke="#000" stroke-width=".21"/>
<circle cx="116" cy="69" r=".68" fill="#008000" stroke="#008000" stroke-width=".21"/>
<circle cx="116" cy="69" r=".38" fill="#fff" stroke="#000" stroke-width=".21"/>
<circle cx="160.2" cy="134.5" r=".68" fill="#008000" stroke="#008000" stroke-width=".21"/>
<circle cx="160.2" cy="134.5" r=".38" fill="#fff" stroke="#000" stroke-width=".21"/>
<circle cx="160.2" cy="128" r=".68" fill="#008000" stroke="#008000" stroke-width=".21"/>
<circle cx="160.2" cy="128" r=".38" fill="#fff" stroke="#000" stroke-width=".21"/>
<circle cx="110.1" cy="117.8" r=".68" fill="#008000" stroke="#008000" stroke-width=".21"/>
<circle cx="110.1" cy="117.8" r=".38" fill="#fff" stroke="#000" stroke-width=".21"/>
<circle cx="130.2" cy="121.9" r=".68" fill="#008000" stroke="#008000" stroke-width=".21"/>
<circle cx="130.2" cy="121.9" r=".38" fill="#fff" stroke="#000" stroke-width=".21"/>
<circle cx="134" cy="122" r=".68" fill="#008000" stroke="#008000" stroke-width=".21"/>
<circle cx="134" cy="122" r=".38" fill="#fff" stroke="#000" stroke-width=".21"/>
<circle cx="144.7" cy="121.9" r=".68" fill="#008000" stroke="#008000" stroke-width=".21"/>
<circle cx="144.7" cy="121.9" r=".38" fill="#fff" stroke="#000" stroke-width=".21"/>
<circle cx="147.5" cy="122" r=".68" fill="#008000" stroke="#008000" stroke-width=".21"/>
<circle cx="147.5" cy="122" r=".38" fill="#fff" stroke="#000" stroke-width=".21"/>
<circle cx="151.2" cy="124.2" r=".76" fill="#008000" stroke="#008000" stroke-width=".21"/>
<circle cx="151.2" cy="124.2" r=".44" fill="#fff" stroke="#000" stroke-width=".21"/>
<circle cx="149" cy="134.3" r=".68" fill="#008000" stroke="#008000" stroke-width=".21"/>
<circle cx="149" cy="134.3" r=".38" fill="#fff" stroke="#000" stroke-width=".21"/>
<circle cx="149" cy="128" r=".68" fill="#008000" stroke="#008000" stroke-width=".21"/>
<circle cx="149" cy="128" r=".38" fill="#fff" stroke="#000" stroke-width=".21"/>
<circle cx="108.3" cy="119.3" r=".68" fill="#008000" stroke="#008000" stroke-width=".21"/>
<circle cx="108.3" cy="119.3" r=".38" fill="#fff" stroke="#000" stroke-width=".21"/>
<circle cx="130.2" cy="124.2" r=".76" fill="#008000" stroke="#008000" stroke-width=".21"/>
<circle cx="130.2" cy="124.2" r=".44" fill="#fff" stroke="#000" stroke-width=".21"/>
<circle cx="134.1" cy="124.1" r=".68" fill="#008000" stroke="#008000" stroke-width=".21"/>
<circle cx="134.1" cy="124.1" r=".38" fill="#fff" stroke="#000" stroke-width=".21"/>
<circle cx="144.5" cy="124" r=".68" fill="#008000" stroke="#008000" stroke-width=".21"/>
<circle cx="144.5" cy="124" r=".38" fill="#fff" stroke="#000" stroke-width=".21"/>
<circle cx="192" cy="103.5" r=".68" fill="#008000" stroke="#008000" stroke-width=".21"/>
<circle cx="192" cy="103.5" r=".38" fill="#fff" stroke="#000" stroke-width=".21"/>
<circle cx="159.9" cy="65.6" r=".68" fill="#008000" stroke="#008000" stroke-width=".21"/>
<circle cx="159.9" cy="65.6" r=".38" fill="#fff" stroke="#000" stroke-width=".21"/>
<circle cx="165.1" cy="88.2" r=".68" fill="#008000" stroke="#008000" stroke-width=".21"/>
<circle cx="165.1" cy="88.2" r=".38" fill="#fff" stroke="#000" stroke-width=".21"/>
<circle cx="169.3" cy="94.9" r=".76" fill="#008000" stroke="#008000" stroke-width=".21"/>
<circle cx="169.3" cy="94.9" r=".47" fill="#fff" stroke="#000" stroke-width=".21"/>
<circle cx="136.8" cy="107.9" r=".68" fill="#008000" stroke="#008000" stroke-width=".21"/>
<circle cx="136.8" cy="107.9" r=".38" fill="#fff" stroke="#000" stroke-width=".21"/>
<circle cx="120.8" cy="112.9" r=".68" fill="#008000" stroke="#008000" stroke-width=".21"/>
<circle cx="120.8" cy="112.9" r=".38" fill="#fff" stroke="#000" stroke-width=".21"/>
<circle cx="182.4" cy="134.3" r=".68" fill="#008000" stroke="#008000" stroke-width=".21"/>
<circle cx="182.4" cy="134.3" r=".38" fill="#fff" stroke="#000" stroke-width=".21"/>
<circle cx="182.3" cy="127.7" r=".68" fill="#008000" stroke="#008000" stroke-width=".21"/>
<circle cx="182.3" cy="127.7" r=".38" fill="#fff" stroke="#000" stroke-width=".21"/>
<circle cx="102.6" cy="91.5" r=".68" fill="#008000" stroke="#008000" stroke-width=".21"/>
<circle cx="102.6" cy="91.5" r=".38" fill="#fff" stroke="#000" stroke-width=".21"/>
<circle cx="111.5" cy="131.7" r=".68" fill="#008000" stroke="#008000" stroke-width=".21"/>
<circle cx="111.5" cy="131.7" r=".38" fill="#fff" stroke="#000" stroke-width=".21"/>
<circle cx="143.3" cy="134.5" r=".68" fill="#008000" stroke="#008000" stroke-width=".21"/>
<circle cx="143.3" cy="134.5" r=".38" fill="#fff" stroke="#000" stroke-width=".21"/>
<circle cx="143.2" cy="127.4" r=".76" fill="#008000" stroke="#008000" stroke-width=".21"/>
<circle cx="143.2" cy="127.4" r=".44" fill="#fff" stroke="#000" stroke-width=".21"/>
<circle cx="118" cy="114.2" r=".68" fill="#008000" stroke="#008000" stroke-width=".21"/>
<circle cx="118" cy="114.2" r=".38" fill="#fff" stroke="#000" stroke-width=".21"/>
<circle cx="138.9" cy="107.9" r=".68" fill="#008000" stroke="#008000" stroke-width=".21"/>
<circle cx="138.9" cy="107.9" r=".38" fill="#fff" stroke="#000" stroke-width=".21"/>
<circle cx="129.7" cy="108.2" r=".68" fill="#008000" stroke="#008000" stroke-width=".21"/>
<circle cx="129.7" cy="108.2" r=".38" fill="#fff" stroke="#000" stroke-width=".21"/>
<circle cx="100.9" cy="117.1" r=".68" fill="#008000" stroke="#008000" stroke-width=".21"/>
<circle cx="100.9" cy="117.1" r=".38" fill="#fff" stroke="#000" stroke-width=".21"/>
<circle cx="118" cy="110.8" r=".44" fill="#008000" stroke="#008000" stroke-width=".21"/>
<circle cx="118" cy="110.8" r=".15" fill="#fff" stroke="#000" stroke-width=".21"/>
<circle cx="103.4" cy="114.6" r=".68" fill="#008000" stroke="#008000" stroke-width=".21"/>
<circle cx="103.4" cy="114.6" r=".38" fill="#fff" stroke="#000" stroke-width=".21"/>
<circle cx="103" cy="125.5" r=".68" fill="#008000" stroke="#008000" stroke-width=".21"/>
<circle cx="103" cy="125.5" r=".38" fill="#fff" stroke="#000" stroke-width=".21"/>
<circle cx="98.8" cy="125.6" r=".68" fill="#008000" stroke="#008000" stroke-width=".21"/>
<circle cx="98.8" cy="125.6" r=".38" fill="#fff" stroke="#000" stroke-width=".21"/>
<circle cx="180" cy="56.2" r=".68" fill="#008000" stroke="#008000" stroke-width=".21"/>
<circle cx="180" cy="56.2" r=".38" fill="#fff" stroke="#000" stroke-width=".21"/>
<circle cx="178.5" cy="53.4" r=".68" fill="#008000" stroke="#008000" stroke-width=".21"/>
<circle cx="178.5" cy="53.4" r=".38" fill="#fff" stroke="#000" stroke-width=".21"/>
<circle cx="159.9" cy="61.4" r=".76" fill="#008000" stroke="#008000" stroke-width=".21"/>
<circle cx="159.9" cy="61.4" r=".47" fill="#fff" stroke="#000" stroke-width=".21"/>
<circle cx="158.1" cy="70.3" r=".76" fill="#008000" stroke="#008000" stroke-width=".21"/>
<circle cx="158.1" cy="70.3" r=".47" fill="#fff" stroke="#000" stroke-width=".21"/>
<circle cx="160.8" cy="106.4" r=".76" fill="#008000" stroke="#008000" stroke-width=".21"/>
<circle cx="160.8" cy="106.4" r=".47" fill="#fff" stroke="#000" stroke-width=".21"/>
<circle cx="157.6" cy="43.1" r=".76" fill="#008000" stroke="#008000" stroke-width=".21"/>
<circle cx="157.6" cy="43.1" r=".44" fill="#fff" stroke="#000" stroke-width=".21"/>
<circle cx="177.5" cy="109.3" r=".76" fill="#008000" stroke="#008000" stroke-width=".21"/>
<circle cx="177.5" cy="109.3" r=".44" fill="#fff" stroke="#000" stroke-width=".21"/>
<circle cx="153.4" cy="83" r=".68" fill="#008000" stroke="#008000" stroke-width=".21"/>
<circle cx="153.4" cy="83" r=".38" fill="#fff" stroke="#000" stroke-width=".21"/>
<circle cx="167.5" cy="85.1" r=".68" fill="#008000" stroke="#008000" stroke-width=".21"/>
<circle cx="167.5" cy="85.1" r=".38" fill="#fff" stroke="#000" stroke-width=".21"/>
<circle cx="196.3" cy="88.4" r=".68" fill="#008000" stroke="#008000" stroke-width=".21"/>
<circle cx="196.3" cy="88.4" r=".38" fill="#fff" stroke="#000" stroke-width=".21"/>
<circle cx="207" cy="96.4" r=".68" fill="#008000" stroke="#008000" stroke-width=".21"/>
<circle cx="207" cy="96.4" r=".38" fill="#fff" stroke="#000" stroke-width=".21"/>
<circle cx="186.6" cy="149.9" r=".68" fill="#008000" stroke="#008000" stroke-width=".21"/>
<circle cx="186.6" cy="149.9" r=".38" fill="#fff" stroke="#000" stroke-width=".21"/>
<circle cx="130.9" cy="93.9" r=".68" fill="#008000" stroke="#008000" stroke-width=".21"/>
<circle cx="130.9" cy="93.9" r=".38" fill="#fff" stroke="#000" stroke-width=".21"/>
<circle cx="153.1" cy="93.7" r=".68" fill="#008000" stroke="#008000" stroke-width=".21"/>
<circle cx="153.1" cy="93.7" r=".38" fill="#fff" stroke="#000" stroke-width=".21"/>
<circle cx="153.1" cy="88.5" r=".68" fill="#008000" stroke="#008000" stroke-width=".21"/>
<circle cx="153.1" cy="88.5" r=".38" fill="#fff" stroke="#000" stroke-width=".21"/>
<circle cx="142.5" cy="82.4" r=".68" fill="#008000" stroke="#008000" stroke-width=".21"/>
<circle cx="142.5" cy="82.4" r=".38" fill="#fff" stroke="#000" stroke-width=".21"/>
<circle cx="159.4" cy="58.9" r=".68" fill="#008000" stroke="#008000" stroke-width=".21"/>
<circle cx="159.4" cy="58.9" r=".38" fill="#fff" stroke="#000" stroke-width=".21"/>
<circle cx="212.2" cy="129.4" r=".68" fill="#008000" stroke="#008000" stroke-width=".21"/>
<circle cx="212.2" cy="129.4" r=".38" fill="#fff" stroke="#000" stroke-width=".21"/>
<circle cx="185.4" cy="146.9" r=".68" fill="#008000" stroke="#008000" stroke-width=".21"/>
<circle cx="185.4" cy="146.9" r=".38" fill="#fff" stroke="#000" stroke-width=".21"/>
<circle cx="156.6" cy="76.8" r=".68" fill="#008000" stroke="#008000" stroke-width=".21"/>
<circle cx="156.6" cy="76.8" r=".38" fill="#fff" stroke="#000" stroke-width=".21"/>
<circle cx="100.1" cy="142.7" r=".68" fill="#008000" stroke="#008000" stroke-width=".21"/>
<circle cx="100.1" cy="142.7" r=".38" fill="#fff" stroke="#000" stroke-width=".21"/>
<circle cx="110.6" cy="136.5" r=".68" fill="#008000" stroke="#008000" stroke-width=".21"/>
<circle cx="110.6" cy="136.5" r=".38" fill="#fff" stroke="#000" stroke-width=".21"/>
<circle cx="149.4" cy="76" r=".68" fill="#008000" stroke="#008000" stroke-width=".21"/>
<circle cx="149.4" cy="76" r=".38" fill="#fff" stroke="#000" stroke-width=".21"/>
<circle cx="143.3" cy="73.9" r=".68" fill="#008000" stroke="#008000" stroke-width=".21"/>
<circle cx="143.3" cy="73.9" r=".38" fill="#fff" stroke="#000" stroke-width=".21"/>
<circle cx="143.4" cy="65.6" r=".68" fill="#008000" stroke="#008000" stroke-width=".21"/>
<circle cx="143.4" cy="65.6" r=".38" fill="#fff" stroke="#000" stroke-width=".21"/>
<circle cx="137.6" cy="65.6" r=".68" fill="#008000" stroke="#008000" stroke-width=".21"/>
<circle cx="137.6" cy="65.6" r=".38" fill="#fff" stroke="#000" stroke-width=".21"/>
<circle cx="129.7" cy="68.2" r=".68" fill="#008000" stroke="#008000" stroke-width=".21"/>
<circle cx="129.7" cy="68.2" r=".38" fill="#fff" stroke="#000" stroke-width=".21"/>
<circle cx="124.6" cy="74.9" r=".68" fill="#008000" stroke="#008000" stroke-width=".21"/>
<circle cx="124.6" cy="74.9" r=".38" fill="#fff" stroke="#000" stroke-width=".21"/>
<circle cx="182.6" cy="70.4" r=".68" fill="#008000" stroke="#008000" stroke-width=".21"/>
<circle cx="182.6" cy="70.4" r=".38" fill="#fff" stroke="#000" stroke-width=".21"/>
<circle cx="182.5" cy="76.6" r=".68" fill="#008000" stroke="#008000" stroke-width=".21"/>
<circle cx="182.5" cy="76.6" r=".38" fill="#fff" stroke="#000" stroke-width=".21"/>
<circle cx="182.5" cy="79.4" r=".68" fill="#008000" stroke="#008000" stroke-width=".21"/>
<circle cx="182.5" cy="79.4" r=".38" fill="#fff" stroke="#000" stroke-width=".21"/>
<circle cx="194.1" cy="136.4" r=".68" fill="#008000" stroke="#008000" stroke-width=".21"/>
<circle cx="194.1" cy="136.4" r=".38" fill="#fff" stroke="#000" stroke-width=".21"/>
<circle cx="195" cy="114.4" r=".68" fill="#008000" stroke="#008000" stroke-width=".21"/>
<circle cx="195" cy="114.4" r=".38" fill="#fff" stroke="#000" stroke-width=".21"/>
<circle cx="175.1" cy="62.7" r=".68" fill="#008000" stroke="#008000" stroke-width=".21"/>
<circle cx="175.1" cy="62.7" r=".38" fill="#fff" stroke="#000" stroke-width=".21"/>
<circle cx="179.5" cy="62.5" r=".68" fill="#008000" stroke="#008000" stroke-width=".21"/>
<circle cx="179.5" cy="62.5" r=".38" fill="#fff" stroke="#000" stroke-width=".21"/>
<circle cx="179.6" cy="70.3" r=".68" fill="#008000" stroke="#008000" stroke-width=".21"/>
<circle cx="179.6" cy="70.3" r=".38" fill="#fff" stroke="#000" stroke-width=".21"/>
<circle cx="179.6" cy="76.6" r=".68" fill="#008000" stroke="#008000" stroke-width=".21"/>
<circle cx="179.6" cy="76.6" r=".38" fill="#fff" stroke="#000" stroke-width=".21"/>
<circle cx="179.6" cy="79.4" r=".68" fill="#008000" stroke="#008000" stroke-width=".21"/>
<circle cx="179.6" cy="79.4" r=".38" fill="#fff" stroke="#000" stroke-width=".21"/>
<circle cx="179.5" cy="93.8" r=".76" fill="#008000" stroke="#008000" stroke-width=".21"/>
<circle cx="179.5" cy="93.8" r=".44" fill="#fff" stroke="#000" stroke-width=".21"/>
<circle cx="189.3" cy="93.9" r=".68" fill="#008000" stroke="#008000" stroke-width=".21"/>
<circle cx="189.3" cy="93.9" r=".38" fill="#fff" stroke="#000" stroke-width=".21"/>
<circle cx="187.7" cy="70.2" r=".68" fill="#008000" stroke="#008000" stroke-width=".21"/>
<circle cx="187.7" cy="70.2" r=".38" fill="#fff" stroke="#000" stroke-width=".21"/>
<circle cx="187.7" cy="76.7" r=".68" fill="#008000" stroke="#008000" stroke-width=".21"/>
<circle cx="187.7" cy="76.7" r=".38" fill="#fff" stroke="#000" stroke-width=".21"/>
<circle cx="187.7" cy="79.4" r=".68" fill="#008000" stroke="#008000" stroke-width=".21"/>
<circle cx="187.7" cy="79.4" r=".38" fill="#fff" stroke="#000" stroke-width=".21"/>
<circle cx="192.3" cy="70.2" r=".68" fill="#008000" stroke="#008000" stroke-width=".21"/>
<circle cx="192.3" cy="70.2" r=".38" fill="#fff" stroke="#000" stroke-width=".21"/>
<circle cx="192.2" cy="76.6" r=".68" fill="#008000" stroke="#008000" stroke-width=".21"/>
<circle cx="192.2" cy="76.6" r=".38" fill="#fff" stroke="#000" stroke-width=".21"/>
<circle cx="192.2" cy="79.4" r=".68" fill="#008000" stroke="#008000" stroke-width=".21"/>
<circle cx="192.2" cy="79.4" r=".38" fill="#fff" stroke="#000" stroke-width=".21"/>
<circle cx="167.5" cy="74.4" r=".68" fill="#008000" stroke="#008000" stroke-width=".21"/>
<circle cx="167.5" cy="74.4" r=".38" fill="#fff" stroke="#000" stroke-width=".21"/>
<circle cx="159.7" cy="75.1" r=".68" fill="#008000" stroke="#008000" stroke-width=".21"/>
<circle cx="159.7" cy="75.1" r=".38" fill="#fff" stroke="#000" stroke-width=".21"/>
<circle cx="130.1" cy="146.5" r=".68" fill="#008000" stroke="#008000" stroke-width=".21"/>
<circle cx="130.1" cy="146.5" r=".38" fill="#fff" stroke="#000" stroke-width=".21"/>
<circle cx="147.9" cy="105.1" r=".68" fill="#008000" stroke="#008000" stroke-width=".21"/>
<circle cx="147.9" cy="105.1" r=".38" fill="#fff" stroke="#000" stroke-width=".21"/>
<circle cx="168.1" cy="104.5" r=".76" fill="#008000" stroke="#008000" stroke-width=".21"/>
<circle cx="168.1" cy="104.5" r=".44" fill="#fff" stroke="#000" stroke-width=".21"/>
<circle cx="187.6" cy="104.2" r=".68" fill="#008000" stroke="#008000" stroke-width=".21"/>
<circle cx="187.6" cy="104.2" r=".38" fill="#fff" stroke="#000" stroke-width=".21"/>
<circle cx="133" cy="88.5" r=".68" fill="#008000" stroke="#008000" stroke-width=".21"/>
<circle cx="133" cy="88.5" r=".38" fill="#fff" stroke="#000" stroke-width=".21"/>
<circle cx="143.8" cy="110.7" r=".68" fill="#008000" stroke="#008000" stroke-width=".21"/>
<circle cx="143.8" cy="110.7" r=".38" fill="#fff" stroke="#000" stroke-width=".21"/>
<circle cx="147.3" cy="109" r=".68" fill="#008000" stroke="#008000" stroke-width=".21"/>
<circle cx="147.3" cy="109" r=".38" fill="#fff" stroke="#000" stroke-width=".21"/>
<circle cx="188.8" cy="144.5" r=".68" fill="#008000" stroke="#008000" stroke-width=".21"/>
<circle cx="188.8" cy="144.5" r=".38" fill="#fff" stroke="#000" stroke-width=".21"/>
<circle cx="192" cy="121.6" r=".68" fill="#008000" stroke="#008000" stroke-width=".21"/>
<circle cx="192" cy="121.6" r=".38" fill="#fff" stroke="#000" stroke-width=".21"/>
<circle cx="127.2" cy="145.4" r=".68" fill="#008000" stroke="#008000" stroke-width=".21"/>
<circle cx="127.2" cy="145.4" r=".38" fill="#fff" stroke="#000" stroke-width=".21"/>
<circle cx="150.5" cy="103.6" r=".68" fill="#008000" stroke="#008000" stroke-width=".21"/>
<circle cx="150.5" cy="103.6" r=".38" fill="#fff" stroke="#000" stroke-width=".21"/>
<circle cx="164.9" cy="102.8" r=".76" fill="#008000" stroke="#008000" stroke-width=".21"/>
<circle cx="164.9" cy="102.8" r=".44" fill="#fff" stroke="#000" stroke-width=".21"/>
<circle cx="138" cy="88.4" r=".68" fill="#008000" stroke="#008000" stroke-width=".21"/>
<circle cx="138" cy="88.4" r=".38" fill="#fff" stroke="#000" stroke-width=".21"/>
<circle cx="153.8" cy="97.9" r=".68" fill="#008000" stroke="#008000" stroke-width=".21"/>
<circle cx="153.8" cy="97.9" r=".38" fill="#fff" stroke="#000" stroke-width=".21"/>
<circle cx="161.2" cy="95.6" r=".76" fill="#008000" stroke="#008000" stroke-width=".21"/>
<circle cx="161.2" cy="95.6" r=".47" fill="#fff" stroke="#000" stroke-width=".21"/>
<circle cx="188.9" cy="102.5" r=".68" fill="#008000" stroke="#008000" stroke-width=".21"/>
<circle cx="188.9" cy="102.5" r=".38" fill="#fff" stroke="#000" stroke-width=".21"/>
<circle cx="168.3" cy="102.4" r=".76" fill="#008000" stroke="#008000" stroke-width=".21"/>
<circle cx="168.3" cy="102.4" r=".44" fill="#fff" stroke="#000" stroke-width=".21"/>
<circle cx="155.3" cy="88.2" r=".68" fill="#008000" stroke="#008000" stroke-width=".21"/>
<circle cx="155.3" cy="88.2" r=".38" fill="#fff" stroke="#000" stroke-width=".21"/>
<circle cx="207.8" cy="128" r=".68" fill="#008000" stroke="#008000" stroke-width=".21"/>
<circle cx="207.8" cy="128" r=".38" fill="#fff" stroke="#000" stroke-width=".21"/>
<circle cx="202.1" cy="155.3" r=".68" fill="#008000" stroke="#008000" stroke-width=".21"/>
<circle cx="202.1" cy="155.3" r=".38" fill="#fff" stroke="#000" stroke-width=".21"/>
<circle cx="196.1" cy="155.2" r=".68" fill="#008000" stroke="#008000" stroke-width=".21"/>
<circle cx="196.1" cy="155.2" r=".38" fill="#fff" stroke="#000" stroke-width=".21"/>
<circle cx="142.9" cy="169.5" r=".68" fill="#008000" stroke="#008000" stroke-width=".21"/>
<circle cx="142.9" cy="169.5" r=".38" fill="#fff" stroke="#000" stroke-width=".21"/>
<circle cx="109.3" cy="168.7" r=".68" fill="#008000" stroke="#008000" stroke-width=".21"/>
<circle cx="109.3" cy="168.7" r=".38" fill="#fff" stroke="#000" stroke-width=".21"/>
<circle cx="104.4" cy="112.6" r=".68" fill="#008000" stroke="#008000" stroke-width=".21"/>
<circle cx="104.4" cy="112.6" r=".38" fill="#fff" stroke="#000" stroke-width=".21"/>
<circle cx="117.9" cy="108.6" r=".68" fill="#008000" stroke="#008000" stroke-width=".21"/>
<circle cx="117.9" cy="108.6" r=".38" fill="#fff" stroke="#000" stroke-width=".21"/>
<circle cx="120.4" cy="106.5" r=".68" fill="#008000" stroke="#008000" stroke-width=".21"/>
<circle cx="120.4" cy="106.5" r=".38" fill="#fff" stroke="#000" stroke-width=".21"/>
<circle cx="131.6" cy="100.3" r=".68" fill="#008000" stroke="#008000" stroke-width=".21"/>
<circle cx="131.6" cy="100.3" r=".38" fill="#fff" stroke="#000" stroke-width=".21"/>
<circle cx="141.4" cy="100.8" r=".76" fill="#008000" stroke="#008000" stroke-width=".21"/>
<circle cx="141.4" cy="100.8" r=".47" fill="#fff" stroke="#000" stroke-width=".21"/>
<circle cx="135.2" cy="88.2" r=".68" fill="#008000" stroke="#008000" stroke-width=".21"/>
<circle cx="135.2" cy="88.2" r=".38" fill="#fff" stroke="#000" stroke-width=".21"/>
<circle cx="132.7" cy="53.6" r=".76" fill="#008000" stroke="#008000" stroke-width=".21"/>
<circle cx="132.7" cy="53.6" r=".47" fill="#fff" stroke="#000" stroke-width=".21"/>
<circle cx="137.6" cy="63.2" r=".68" fill="#008000" stroke="#008000" stroke-width=".21"/>
<circle cx="137.6" cy="63.2" r=".38" fill="#fff" stroke="#000" stroke-width=".21"/>
<circle cx="142.6" cy="63.3" r=".68" fill="#008000" stroke="#008000" stroke-width=".21"/>
<circle cx="142.6" cy="63.3" r=".38" fill="#fff" stroke="#000" stroke-width=".21"/>
<circle cx="142.4" cy="55.1" r=".68" fill="#008000" stroke="#008000" stroke-width=".21"/>
<circle cx="142.4" cy="55.1" r=".38" fill="#fff" stroke="#000" stroke-width=".21"/>
<circle cx="107" cy="141.2" r=".68" fill="#008000" stroke="#008000" stroke-width=".21"/>
<circle cx="107" cy="141.2" r=".38" fill="#fff" stroke="#000" stroke-width=".21"/>
<circle cx="104.2" cy="138.1" r=".68" fill="#008000" stroke="#008000" stroke-width=".21"/>
<circle cx="104.2" cy="138.1" r=".38" fill="#fff" stroke="#000" stroke-width=".21"/>
<circle cx="184.8" cy="101.7" r=".68" fill="#008000" stroke="#008000" stroke-width=".21"/>
<circle cx="184.8" cy="101.7" r=".38" fill="#fff" stroke="#000" stroke-width=".21"/>
<circle cx="118.2" cy="95.8" r=".68" fill="#008000" stroke="#008000" stroke-width=".21"/>
<circle cx="118.2" cy="95.8" r=".38" fill="#fff" stroke="#000" stroke-width=".21"/>
<circle cx="121.8" cy="87.8" r=".76" fill="#008000" stroke="#008000" stroke-width=".21"/>
<circle cx="121.8" cy="87.8" r=".44" fill="#fff" stroke="#000" stroke-width=".21"/>
<circle cx="170.8" cy="69.8" r=".68" fill="#008000" stroke="#008000" stroke-width=".21"/>
<circle cx="170.8" cy="69.8" r=".38" fill="#fff" stroke="#000" stroke-width=".21"/>
<circle cx="171.3" cy="76.5" r=".68" fill="#008000" stroke="#008000" stroke-width=".21"/>
<circle cx="171.3" cy="76.5" r=".38" fill="#fff" stroke="#000" stroke-width=".21"/>
<circle cx="171.3" cy="79.4" r=".68" fill="#008000" stroke="#008000" stroke-width=".21"/>
<circle cx="171.3" cy="79.4" r=".38" fill="#fff" stroke="#000" stroke-width=".21"/>
<circle cx="193.5" cy="101.1" r=".68" fill="#008000" stroke="#008000" stroke-width=".21"/>
<circle cx="193.5" cy="101.1" r=".38" fill="#fff" stroke="#000" stroke-width=".21"/>
<circle cx="171.2" cy="95.8" r=".76" fill="#008000" stroke="#008000" stroke-width=".21"/>
<circle cx="171.2" cy="95.8" r=".44" fill="#fff" stroke="#000" stroke-width=".21"/>
<circle cx="173.8" cy="72.2" r=".68" fill="#008000" stroke="#008000" stroke-width=".21"/>
<circle cx="173.8" cy="72.2" r=".38" fill="#fff" stroke="#000" stroke-width=".21"/>
<circle cx="173.8" cy="76.5" r=".68" fill="#008000" stroke="#008000" stroke-width=".21"/>
<circle cx="173.8" cy="76.5" r=".38" fill="#fff" stroke="#000" stroke-width=".21"/>
<circle cx="173.8" cy="79.4" r=".68" fill="#008000" stroke="#008000" stroke-width=".21"/>
<circle cx="173.8" cy="79.4" r=".38" fill="#fff" stroke="#000" stroke-width=".21"/>
<circle cx="196.2" cy="102.1" r=".68" fill="#008000" stroke="#008000" stroke-width=".21"/>
<circle cx="196.2" cy="102.1" r=".38" fill="#fff" stroke="#000" stroke-width=".21"/>
<circle cx="173.8" cy="94.8" r=".76" fill="#008000" stroke="#008000" stroke-width=".21"/>
<circle cx="173.8" cy="94.8" r=".44" fill="#fff" stroke="#000" stroke-width=".21"/>
<circle cx="176.9" cy="70.4" r=".68" fill="#008000" stroke="#008000" stroke-width=".21"/>
<circle cx="176.9" cy="70.4" r=".38" fill="#fff" stroke="#000" stroke-width=".21"/>
<circle cx="176.9" cy="76.7" r=".68" fill="#008000" stroke="#008000" stroke-width=".21"/>
<circle cx="176.9" cy="76.7" r=".38" fill="#fff" stroke="#000" stroke-width=".21"/>
<circle cx="176.9" cy="79.4" r=".68" fill="#008000" stroke="#008000" stroke-width=".21"/>
<circle cx="176.9" cy="79.4" r=".38" fill="#fff" stroke="#000" stroke-width=".21"/>
<circle cx="198.1" cy="102.1" r=".68" fill="#008000" stroke="#008000" stroke-width=".21"/>
<circle cx="198.1" cy="102.1" r=".38" fill="#fff" stroke="#000" stroke-width=".21"/>
<circle cx="177.5" cy="94.1" r=".76" fill="#008000" stroke="#008000" stroke-width=".21"/>
<circle cx="177.5" cy="94.1" r=".44" fill="#fff" stroke="#000" stroke-width=".21"/>
<circle cx="205.6" cy="120.2" r=".68" fill="#008000" stroke="#008000" stroke-width=".21"/>
<circle cx="205.6" cy="120.2" r=".38" fill="#fff" stroke="#000" stroke-width=".21"/>
<circle cx="208.2" cy="122.2" r=".68" fill="#008000" stroke="#008000" stroke-width=".21"/>
<circle cx="208.2" cy="122.2" r=".38" fill="#fff" stroke="#000" stroke-width=".21"/>
<circle cx="104.5" cy="102.5" r=".68" fill="#008000" stroke="#008000" stroke-width=".21"/>
<circle cx="104.5" cy="102.5" r=".38" fill="#fff" stroke="#000" stroke-width=".21"/>
<circle cx="113.9" cy="82.4" r=".68" fill="#008000" stroke="#008000" stroke-width=".21"/>
<circle cx="113.9" cy="82.4" r=".38" fill="#fff" stroke="#000" stroke-width=".21"/>
<circle cx="102.7" cy="139.3" r=".68" fill="#008000" stroke="#008000" stroke-width=".21"/>
<circle cx="102.7" cy="139.3" r=".38" fill="#fff" stroke="#000" stroke-width=".21"/>
<circle cx="149.5" cy="145.7" r=".68" fill="#008000" stroke="#008000" stroke-width=".21"/>
<circle cx="149.5" cy="145.7" r=".38" fill="#fff" stroke="#000" stroke-width=".21"/>
<circle cx="210.5" cy="113.8" r=".68" fill="#008000" stroke="#008000" stroke-width=".21"/>
<circle cx="210.5" cy="113.8" r=".38" fill="#fff" stroke="#000" stroke-width=".21"/>
<circle cx="199.2" cy="164.7" r=".68" fill="#008000" stroke="#008000" stroke-width=".21"/>
<circle cx="199.2" cy="164.7" r=".38" fill="#fff" stroke="#000" stroke-width=".21"/>
<circle cx="194.4" cy="160.4" r=".68" fill="#008000" stroke="#008000" stroke-width=".21"/>
<circle cx="194.4" cy="160.4" r=".38" fill="#fff" stroke="#000" stroke-width=".21"/>
<circle cx="191" cy="87.5" r=".68" fill="#008000" stroke="#008000" stroke-width=".21"/>
<circle cx="191" cy="87.5" r=".38" fill="#fff" stroke="#000" stroke-width=".21"/>
<circle cx="169.7" cy="87.3" r=".68" fill="#008000" stroke="#008000" stroke-width=".21"/>
<circle cx="169.7" cy="87.3" r=".38" fill="#fff" stroke="#000" stroke-width=".21"/>
<circle cx="149.5" cy="79.1" r=".68" fill="#008000" stroke="#008000" stroke-width=".21"/>
<circle cx="149.5" cy="79.1" r=".38" fill="#fff" stroke="#000" stroke-width=".21"/>
<circle cx="199.5" cy="107.4" r=".76" fill="#008000" stroke="#008000" stroke-width=".21"/>
<circle cx="199.5" cy="107.4" r=".47" fill="#fff" stroke="#000" stroke-width=".21"/>
<circle cx="180" cy="107.4" r=".68" fill="#008000" stroke="#008000" stroke-width=".21"/>
<circle cx="180" cy="107.4" r=".38" fill="#fff" stroke="#000" stroke-width=".21"/>
<circle cx="151.5" cy="65.6" r=".68" fill="#008000" stroke="#008000" stroke-width=".21"/>
<circle cx="151.5" cy="65.6" r=".38" fill="#fff" stroke="#000" stroke-width=".21"/>
<circle cx="151.4" cy="83" r=".68" fill="#008000" stroke="#008000" stroke-width=".21"/>
<circle cx="151.4" cy="83" r=".38" fill="#fff" stroke="#000" stroke-width=".21"/>
<circle cx="108.9" cy="88.2" r=".68" fill="#008000" stroke="#008000" stroke-width=".21"/>
<circle cx="108.9" cy="88.2" r=".38" fill="#fff" stroke="#000" stroke-width=".21"/>
<circle cx="108.9" cy="83.9" r=".68" fill="#008000" stroke="#008000" stroke-width=".21"/>
<circle cx="108.9" cy="83.9" r=".38" fill="#fff" stroke="#000" stroke-width=".21"/>
<circle cx="174.9" cy="67.8" r=".68" fill="#008000" stroke="#008000" stroke-width=".21"/>
<circle cx="174.9" cy="67.8" r=".38" fill="#fff" stroke="#000" stroke-width=".21"/>
<circle cx="151.7" cy="58.4" r=".68" fill="#008000" stroke="#008000" stroke-width=".21"/>
<circle cx="151.7" cy="58.4" r=".38" fill="#fff" stroke="#000" stroke-width=".21"/>
<circle cx="151.7" cy="62.2" r=".68" fill="#008000" stroke="#008000" stroke-width=".21"/>
<circle cx="151.7" cy="62.2" r=".38" fill="#fff" stroke="#000" stroke-width=".21"/>
<circle cx="209.6" cy="66.2" r=".68" fill="#008000" stroke="#008000" stroke-width=".21"/>
<circle cx="209.6" cy="66.2" r=".38" fill="#fff" stroke="#000" stroke-width=".21"/>
<circle cx="195.9" cy="43.7" r=".76" fill="#008000" stroke="#008000" stroke-width=".21"/>
<circle cx="195.9" cy="43.7" r=".47" fill="#fff" stroke="#000" stroke-width=".21"/>
<circle cx="161.2" cy="76.3" r=".68" fill="#008000" stroke="#008000" stroke-width=".21"/>
<circle cx="161.2" cy="76.3" r=".38" fill="#fff" stroke="#000" stroke-width=".21"/>
<circle cx="199.4" cy="158.1" r=".68" fill="#008000" stroke="#008000" stroke-width=".21"/>
<circle cx="199.4" cy="158.1" r=".38" fill="#fff" stroke="#000" stroke-width=".21"/>
<circle cx="178.1" cy="164.7" r=".76" fill="#008000" stroke="#008000" stroke-width=".21"/>
<circle cx="178.1" cy="164.7" r=".47" fill="#fff" stroke="#000" stroke-width=".21"/>
<circle cx="189.6" cy="165.3" r=".68" fill="#008000" stroke="#008000" stroke-width=".21"/>
<circle cx="189.6" cy="165.3" r=".38" fill="#fff" stroke="#000" stroke-width=".21"/>
<circle cx="146.1" cy="167.7" r=".68" fill="#008000" stroke="#008000" stroke-width=".21"/>
<circle cx="146.1" cy="167.7" r=".38" fill="#fff" stroke="#000" stroke-width=".21"/>
<circle cx="112.4" cy="167.1" r=".68" fill="#008000" stroke="#008000" stroke-width=".21"/>
<circle cx="112.4" cy="167.1" r=".38" fill="#fff" stroke="#000" stroke-width=".21"/>
<circle cx="112.4" cy="158.6" r=".68" fill="#008000" stroke="#008000" stroke-width=".21"/>
<circle cx="112.4" cy="158.6" r=".38" fill="#fff" stroke="#000" stroke-width=".21"/>
<circle cx="113.7" cy="105.5" r=".68" fill="#008000" stroke="#008000" stroke-width=".21"/>
<circle cx="113.7" cy="105.5" r=".38" fill="#fff" stroke="#000" stroke-width=".21"/>
<circle cx="115.7" cy="100.4" r=".68" fill="#008000" stroke="#008000" stroke-width=".21"/>
<circle cx="115.7" cy="100.4" r=".38" fill="#fff" stroke="#000" stroke-width=".21"/>
<circle cx="111.7" cy="96.7" r=".68" fill="#008000" stroke="#008000" stroke-width=".21"/>
<circle cx="111.7" cy="96.7" r=".38" fill="#fff" stroke="#000" stroke-width=".21"/>
<circle cx="111.9" cy="83.8" r=".68" fill="#008000" stroke="#008000" stroke-width=".21"/>
<circle cx="111.9" cy="83.8" r=".38" fill="#fff" stroke="#000" stroke-width=".21"/>
<circle cx="94.6" cy="37.8" r="3.2" fill="#008000" stroke="#008000" stroke-width=".21"/>
<circle cx="94.6" cy="37.8" r="2.39" fill="#fff" stroke="#000" stroke-width=".21"/>
<circle cx="205" cy="37.8" r="3.2" fill="#008000" stroke="#008000" stroke-width=".21"/>
<circle cx="205" cy="37.8" r="2.39" fill="#fff" stroke="#000" stroke-width=".21"/>
<circle cx="208.8" cy="166.3" r="3.2" fill="#008000" stroke="#008000" stroke-width=".21"/>
<circle cx="208.8" cy="166.3" r="2.39" fill="#fff" stroke="#000" stroke-width=".21"/>
<circle cx="88.9" cy="166.3" r="3.2" fill="#008000" stroke="#008000" stroke-width=".21"/>
<circle cx="88.9" cy="166.3" r="2.39" fill="#fff" stroke="#000" stroke-width=".21"/>
<circle cx="199.5" cy="162.4" r=".68" fill="#008000" stroke="#008000" stroke-width=".21"/>
<circle cx="199.5" cy="162.4" r=".38" fill="#fff" stroke="#000" stroke-width=".21"/>
<g fill="#800000" stroke="#800000" stroke-width=".21">
<path d="M153.2 102.2h1.5v.5h-1.5z"/>
<path d="M153.2 103.2h1.5v.4h-1.5z"/>
<path d="M153.2 104.1h1.5v.5h-1.5z"/>
<path d="M153.2 105.1h1.5v.5h-1.5z"/>
<path d="M153.2 106.1h1.5v.5h-1.5z"/>
<path d="M153.2 107.1h1.5v.4h-1.5z"/>
<path d="M153.2 108h1.5v.5h-1.5z"/>
<path d="M153.2 109h1.5v.5h-1.5z"/>
<path d="M153.2 110h1.5v.4h-1.5z"/>
<path d="M153.2 111h1.5v.4h-1.5z"/>
<path d="M161.9 111h1.5v.4h-1.5z"/>
<path d="M161.9 110h1.5v.4h-1.5z"/>
<path d="M161.9 109h1.5v.5h-1.5z"/>
<path d="M161.9 108h1.5v.5h-1.5z"/>
<path d="M161.9 107.1h1.5v.4h-1.5z"/>
<path d="M161.9 106.1h1.5v.5h-1.5z"/>
<path d="M161.9 105.1h1.5v.5h-1.5z"/>
<path d="M161.9 104.1h1.5v.5h-1.5z"/>
<path d="M161.9 103.2h1.5v.4h-1.5z"/>
<path d="M161.9 102.2h1.5v.5h-1.5z"/>
<path d="M124.1 102h1.5v.4h-1.5z"/>
<path d="M124.1 103h1.5v.4h-1.5z"/>
<path d="M124.1 103.9h1.5v.5h-1.5z"/>
<path d="M124.1 104.9h1.5v.5h-1.5z"/>
<path d="M124.1 105.9h1.5v.4h-1.5z"/>
<path d="M124.1 106.9h1.5v.4h-1.5z"/>
<path d="M124.1 107.8h1.5v.5h-1.5z"/>
<path d="M124.1 108.8h1.5v.5h-1.5z"/>
<path d="M124.1 109.8h1.5v.5h-1.5z"/>
<path d="M124.1 110.8h1.5v.4h-1.5z"/>
<path d="M132.9 110.8h1.4v.4h-1.4z"/>
<path d="M132.9 109.8h1.4v.5h-1.4z"/>
<path d="M132.9 108.8h1.4v.5h-1.4z"/>
<path d="M132.9 107.8h1.4v.5h-1.4z"/>
<path d="M132.9 106.9h1.4v.4h-1.4z"/>
<path d="M132.9 105.9h1.4v.4h-1.4z"/>
<path d="M132.9 104.9h1.4v.5h-1.4z"/>
<path d="M132.9 103.9h1.4v.5h-1.4z"/>
<path d="M132.9 103h1.4v.4h-1.4z"/>
<path d="M132.9 102h1.4v.4h-1.4z"/>
<path d="M109.1 128.4h2v2.2h-2z"/>
<path d="M111.7 128.4h1.9v2.2h-1.9z"/>
<path d="M91.1 130.5h2.2v1.9h-2.2z"/>
<path d="M91.1 127.9h2.2v1.9h-2.2z"/>
<path d="M178.3 135.9h2.2v2h-2.2z"/>
<path d="M178.3 138.5h2.2v1.9h-2.2z"/>
<path d="M172.7 135.9h2.3v2h-2.3z"/>
<path d="M172.7 138.5h2.3v1.9h-2.3z"/>
<path d="M167.2 135.9h2.2v2h-2.2z"/>
<path d="M167.2 138.5h2.2v1.9h-2.2z"/>
<path d="M161.6 135.9h2.3v2h-2.3z"/>
<path d="M161.6 138.5h2.3v1.9h-2.3z"/>
<path d="M156.1 135.9h2.2v2h-2.2z"/>
<path d="M156.1 138.5h2.2v1.9h-2.2z"/>
<path d="M150.6 135.9h2.2v2h-2.2z"/>
<path d="M150.6 138.5h2.2v1.9h-2.2z"/>
<path d="M145.1 135.9h2.2v2h-2.2z"/>
<path d="M145.1 138.5h2.2v1.9h-2.2z"/>
<path d="M183.8 135.9h2.3v1.9h-2.3z"/>
<path d="M183.8 138.4h2.3v2h-2.3z"/>
<path d="M183.8 128.4h2.3v1.9h-2.3z"/>
<path d="M183.8 130.9h2.3v2h-2.3z"/>
<path d="M178.3 128.4h2.3v1.9h-2.3z"/>
<path d="M178.3 130.9h2.3v2h-2.3z"/>
<path d="M172.7 128.4h2.3v1.9h-2.3z"/>
<path d="M172.7 130.9h2.3v1.9h-2.3z"/>
<path d="M167.2 128.4h2.2v1.9h-2.2z"/>
<path d="M167.2 130.9h2.2v2h-2.2z"/>
<path d="M161.6 128.4h2.3v1.9h-2.3z"/>
<path d="M161.6 130.9h2.3v2h-2.3z"/>
<path d="M156.1 128.4h2.3v1.9h-2.3z"/>
<path d="M156.1 130.9h2.3v2h-2.3z"/>
<path d="M150.6 128.4h2.2v1.9h-2.2z"/>
<path d="M150.6 130.9h2.2v2h-2.2z"/>
<path d="M145.1 128.4h2.2v1.9h-2.2z"/>
<path d="M145.1 130.9h2.2v2h-2.2z"/>
<path d="M117.6 128.5h2.3v2h-2.3z"/>
<path d="M117.6 126h2.3v1.9h-2.3z"/>
<path d="M112 136h2.2v1.9h-2.2z"/>
<path d="M112 138.5h2.2v2h-2.2z"/>
<path d="M111.5 124.7h2.3v1.9h-2.3z"/>
<path d="M111.5 122.1h2.3v2h-2.3z"/>
<path d="M89.2 116h2.3v1.9h-2.3z"/>
<path d="M89.2 118.6h2.3v1.9h-2.3z"/>
<path d="M117.5 136h2.2v1.9h-2.2z"/>
<path d="M117.5 138.5h2.2v2h-2.2z"/>
<path d="M133.6 136h2.2v1.9h-2.2z"/>
<path d="M133.6 138.6h2.2v1.9h-2.2z"/>
<path d="M128.1 136h2.2v2h-2.2z"/>
<path d="M128.1 138.6h2.2v1.9h-2.2z"/>
<path d="M122.5 136h2.3v2h-2.3z"/>
<path d="M122.5 138.6h2.3v1.9h-2.3z"/>
<path d="M139.1 136h2.3v1.9h-2.3z"/>
<path d="M139.1 138.6h2.3v1.9h-2.3z"/>
<path d="M139.1 128.5h2.3v2h-2.3z"/>
<path d="M139.1 131.1h2.3v1.9h-2.3z"/>
<path d="M133.6 128.5h2.2v2h-2.2z"/>
<path d="M133.6 131.1h2.2v2h-2.2z"/>
<path d="M128.1 128.5h2.2v2h-2.2z"/>
<path d="M128.1 131.1h2.2v2h-2.2z"/>
<path d="M122.6 128.6h2.2v1.9h-2.2z"/>
<path d="M122.6 131.1h2.2v2h-2.2z"/>
<path d="M102.3 118.8h1v.7h-1z"/>
<path d="M100.3 118.8h1.1v.7h-1.1z"/>
<path d="M148.6 149.2h1.8v.8h-1.8z"/>
<path d="M148.6 150.6h1.8v.8h-1.8z"/>
<path d="M148.6 152h1.8v.8h-1.8z"/>
<path d="M152.5 152h1.8v.8h-1.8z"/>
<path d="M152.5 149.2h1.8v.8h-1.8z"/>
<path d="M123.9 165h1v3h-1z"/>
<path d="M125.8 165h1v3h-1z"/>
<path d="M127.7 165h1v3h-1z"/>
<path d="M129.6 165h1v3h-1z"/>
<path d="M131.5 165h1v3h-1z"/>
<path d="M133.4 165h1v3h-1z"/>
<path d="M135.3 165h1v3h-1z"/>
<path d="M137.2 165h1v3h-1z"/>
<path d="M137.2 149.9h1v3h-1z"/>
<path d="M135.3 149.9h1v3h-1z"/>
<path d="M133.4 149.9h1v3h-1z"/>
<path d="M131.5 149.9h1v3h-1z"/>
<path d="M129.6 149.9h1v3h-1z"/>
<path d="M127.7 149.9h1v3h-1z"/>
<path d="M125.8 149.9h1v3h-1z"/>
<path d="M123.9 149.9h1v3h-1z"/>
<path d="M139.1 165h1v3h-1z"/>
<path d="M141.1 165h.9v3h-.9z"/>
<path d="M139.1 149.9h1v3h-1z"/>
<path d="M141.1 149.9h.9v3h-.9z"/>
<path d="M109.9 143.7h2v2.3h-2z"/>
<path d="M112.5 143.7h1.9v2.3h-1.9z"/>
<path d="M173.8 153.7h5.9v5.9h-5.9z"/>
<path d="M186.7 154.3h4.8v4.7h-4.8z"/>
<path d="M162.1 154.3h4.8v4.7h-4.8z"/>
<path d="M144.7 149.1h2.2v1.9h-2.2z"/>
<path d="M144.7 151.6h2.2v2h-2.2z"/>
<path d="M156 148.6h2.2v2h-2.2z"/>
<path d="M156 151.2h2.2v1.9h-2.2z"/>
<path d="M114.6 109.2h2.2v1.9h-2.2z"/>
<path d="M114.6 111.7h2.2v1.9h-2.2z"/>
</g>
<g fill="none" stroke="#800000" stroke-width=".61">
<path d="M123.4 39.5v2.4l1 1.4h1.6l1.3 1.1v6.4l2.5 2.8-.1 7.1M133 37.5l-1.9 2 .1 46.9 1.8 2.1M136.8 37.5l-1.8 1.9v46l3 3M140.6 37.5l-.2 .1-3.3 3.3v.4l-.3 .1 1.9 1.7-.1 3-.8 .8M144.4 37.5l2 2.1v12.6l-3.9 .1-.1 2.8M159.6 37.5h-3.8v3.9M167.3 37.5l-1.8 1.9h-7.2l-.7 .7 .1 3.1M169.7 39.4h7v3.9h3l2.1 2.2 .7-.4M186.3 37.5v3.9M102.5 41.4h-2.3l-2.4 2.4v38.6l10.3 10.3v26.4l.2 .2M106.3 41.4v-.3l-1.5-1.6h-4.7l-4 4v39.5l9.9 9.9v27.8M106.3 45.1l-1.8 1.9v9.3"/>
<path d="M110.1 41.4h.1M110.1 41.4l-1.8 1.8h-7.4l-1.8 1.7v36.3l10.9 10.9 .1 25.7M110.1 45.1l-1.9 1.9v11.4M110.1 49h.1M110.2 49v32.3l1.7 1.7v.8M112.4 53.7l-.1 22.5M113.9 41.4v.2l-1.8 1.7v2.7l1.2 1.2h2.5v21.6l.2 .2M113.9 49h.1M114 49l-.1 33.4M117.8 41.4l1.9 2.1v15.2l.2-.2v24.3l.7 .8v3.4l-1.2 1.2M117.8 49h.1M117.8 49v22.7"/>
<path d="M121.6 41.4l1.9 2.5 .1 9.7-.6 .7v26.3l.3 .4v1.1h-.2h.5M121.6 49v33.6l.2 .2v5M132.7 53.6l-.5 .4v31.2l3 3M137.2 52.9l-1.1 .2 .3 26.6h-.2h.3M137.8 46.9l.2 .1h3.6l1.8 1.9 1 .1v-.1M137.8 46.9l-1.1 1 .1 1.1v-.3M140.5 48.9v6.7l2 2 2.4 .1v11.6l-1.8 1.7h-1.7l-.8 1.2v5.3l1.7 1.6h7.2M140.5 48.9h.2l-.1 .1M140.6 45.1h3.8M140.6 48.7l-.1 .2M151.7 58.4v3.8M152 45.1l2 2v14.7"/>
<path d="M152.1 49l-.1 4.3-.4 .5h-7.2M159.4 58.9l-2.8 5.7v12.2M159.6 41.4l1.9 1.8v12.4M159.7 45.1l-2 2v3.4l-.6 .6v9.1l-1.9 3.7v21.5l.1 2.8M161.5 55.6l-.1 .7M161.5 55.6l-.3 20.7M163.4 41.4l2 1.9v29l2.1 2.1M167.3 45.1l1.9 2v21.8l1 .9h.6M171.1 45.1l2 2v22.7l.7 .7v1.7M174.9 49v13.5l.2 .2M174.9 45.1l2 2v23.3M178.5 53.4v1.3l1.5 1.5"/>
<path d="M182.5 45.1l3.8 3.9 3.8-3.9 3.8 3.9 3.8-3.9M182.5 45.1l-3.8 3.9M182.5 49l.1 21.4M190.1 49l-2.4 2.4v18.8M195.9 43.7v-7.9h-79l-1 1.1v6.1l1.9 2.1M197.7 49l-5.5 5.5 .1 15.7M117.8 69.4v.2M124.6 77.7h5.2M124.7 79.6l5.1 .1M126.8 67.7l-2.2 2.9M129.7 68.2l-5.1 6.7M133.6 62.8v4.8"/>
<path d="M133.6 77.6v6.3M137.6 63.2l5 .1M143.3 73.9l4.1 .1 2 2M143.4 65.6h-5.8M151.5 65.6l-.1 17.4M159.7 75.1v5.3l3.2 3.2h45.4l3.3 3.3M159.9 65.6l-.1 .4v6.1l-1.8 2.2v1.2l.7 .7v4.7l6.4 6.3v1M159.9 61.4h.1M170.9 61l.6 .7v3M171.3 76.5v2.9M173.8 76.5v2.9M174.9 67.8h.1"/>
<path d="M175 67.8l.2 .2v3.6l.5 .6 38 .1 .6 1v28.7l-2.7 2.9M176.9 76.7v2.7M176.9 68.1h.1M179.5 62.5l.1 7.8M179.6 76.6v2.8M182.5 76.6v2.8M182.6 67.6h.1M187.7 76.7v2.7M187.7 68v.1M192.2 76.6v2.8M194.3 64.7l4.9 4.9M209.6 66.2h4.9l1.2 1.3-.1 39.2-4 4.2"/>
<path d="M102.6 91.5l2.2 2.2v6.4l-4.8 4.2h-14.2l-3 2.7v30.4l3.2 3.7 17.5-.1 5.2-5.2 2.8-2.5v-1.6M111.7 96.7v2.1h27.6l.3-.2M113.2 95l.7-.4 2.7 2.7M118.2 95.8l27.2 .1 2.4 4.6h31.1l1.3 1.3 4.6-.1M129.8 82.2v5.4l1.2 .7M142.5 82.4l6.1 5.9h4.3l.2 .2M146.7 95.3l4 4.1h29l1 1h7.9l1.9 1M149.5 80.9h-10.1l-2.9 2.9M153.1 93.7l-22.2 .2M153.4 81.2v.4M156.8 80.9l4.5 4.6M161.2 95.6l-1.3 2.3h-6.1"/>
<path d="M165.1 85.3l3.6 3.6 23.5 .1 .6-.6M167.5 85.1l.3 .3M169.3 94.9l-.1 1.6 2 1.9h9.3l.7 .6h9.3l1.4 1.4 .1 3.1M169.7 87.3h21.2l.1 .2M171.2 95.8l1.5 1.5h20.3l.4 .5 .1 3.3M173.8 94.8l1.4 1.4h20.5l.4 .5 .1 5.4M177.5 94.1l1.1 1.2h19.2l.3 .1v6.7M179.5 93.8l9.8 .1M196.3 88.4h.1M203.4 97h-1.9l-.2-.3-1.5 1.5v6.4M203.4 98.9l.1-.1 .3 .3h.3l4.9 4.9v8.2l1.5 1.6M90.4 119.5l-.1 11.2 1.9 .7 6.7-.1"/>
<path d="M93.7 116.6l-.4 .4M100.9 117.1v12.1l-.4 .3M103.3 114.6l.2-.2-.1 .2M104.4 112.6l-1-1.4-1.7-.1h-13.4l-1.3 1-.2 23 2.8 2.8h10.6l1.5-1.5h2l.5 1.7M104.5 102.5v.4l-3.6 2.8h-14.6l-2.1 1.9-.1 28.8 2.9 3.4h15.3l.4-.5M111.5 101l-.4 .3v13.1l3.1 3M113.6 100.4v.6l-1.5 1.5 .1 10.1 3.2-.1 .3 .4M115.7 112.7v7.3l-3.1 3.1h-8l-.2-.3h-1.6v-3.6M115.7 100.4l-2 2.6v2.5M117.9 108.6l-.1 .1M119.1 100.4l-3.6 3.4v1.6M120.4 106.5h-.1"/>
<path d="M120.8 112.9v12l-2 2.1M122.2 115.7l4.3 4.3-.1 7.7M122.3 105l-.1 .1h-4.2l-2.3 2.3v2.7M124.8 103.2h1M129.9 102.2l-.1 .1M131.1 111.4l.4 .5v1.1l7.4 7.1v6l.7 1.2M131.6 100.3l.4 1h9l.4-.5M133.5 117.7h-5M133.6 109.1h-2.6l-1.8 1.2v5M133.6 111h.1M137.2 113.5l2.1 1.8v.8M141.6 107.3l-2.7 .6"/>
<path d="M143.4 103.2h1.8l.4 .4h4.9M147.3 109l-1.7 1.7h-1.8M147.5 113.6l-2.8 .1M150.3 108.2l-1.3 1.4v18.4M151.1 109.2l-1 1.1v5.2l2.5 2.7h6l1.6 1.6v5.2M151.2 111.1h.1M151.7 110.2l-.5 .6v4.4l1.3 1.3h16.3l2.5 2.3v9.1M152.4 111.2l-.3 .3v3.2l.7 .7h26.1l3.5 3.4-.1 8.9M153.9 104.4h.1M157.8 111.6v1.7l-.3 .3h-3.5M161.4 118v5.8l.3 .3M162.7 109.2l-.1 .1"/>
<path d="M162.7 106.3h-1.9v.1M164.9 102.8l-.1 .6M165.7 113.8v-2.6h18.8l3.5 3.5 .2 19.7h-3.3M167.8 107.3l1.5-1.4h26.9l1.2-1.3h6l.1-.3 1.5 1.5v9.1l-1.5 1.3-.1-.2h-1.9l-.2-.1-1.6 .8 .2 16.5h1.6l-.2 .1 .2 1.8h-1.6l-.1 4.6 .9 .9h.5l.3 .3 .2 5.8M168.3 102.4l.7 .7h16.8l3.1-.6M169.5 107.5l-.7 .8M172.3 108.6l-.6 .6M175.3 109.7l-.5 .5M178.8 113.8l8.2 8.2v5.2l-.3 .3M180 107.4l.3-.3h7.4l1 1.4h9.6l1.2-1.1M187.6 104.2l-17.1-.1-.5 .5h-1.6l-1-.2M190.5 112.5l.5 .4-.1-.1"/>
<path d="M195 114.4l-.9 .9v21.1M201.4 112.1l.1 .1M201.5 104.6h-.1M211.6 116.9l3.4 3.4 .1 39.2-1.7 2.2h-13.2l-.7 .7v-.3M92.2 128.9l.6 .6h17.3M103 125.5v.1M110.6 136.5l-.7-.2-6.4 6-3.1 .1-.3 .3M112.6 125.6v.1M113.1 139.5h5.5M113.1 137l-.6-.1-1.6 1.6v6.3M115.8 139.5l-.2 .1 .2 .2v4.2l-.9 .9h-1.4M117.2 120.5v2.7l-.3 .3v3.7l-.6 .6"/>
<path d="M118.6 139.5h.1M118.8 129.5h-6.2l.7 .2M123.7 139.5v.1M123.7 137h.1M123.7 129.5h.1M123.7 132.1v4.9M123.7 134.2h2.7M129.2 129.5h.1M129.2 139.5v.1M130.2 124.2h3.8M130.2 121.9l3.8 .1M130.3 125.9l3.5 .1"/>
<path d="M131.9 134.3h-2.7v-2.2v4.9M134.1 124.1l-.1 .1M134.7 129.5h.1M134.7 139.5v.1M134.7 134.5h2.7M134.7 132.1v4.9M135 120.3l.5-.5v-.7l2 2v6.9M140.2 132.1v4.9M140.2 139.4v.1M140.2 132.1h.1M140.2 134.5h3.1M144.5 124h4.4l.1 .1"/>
<path d="M144.5 125.9l.1 .1M144.5 125.9h3M144.7 121.9l.2 .1h2.6M146.2 133.1v3.8M146.2 131.9v2.4h2.8M150.9 139.4v.2h.8v-.2M151.2 124.2l.8 .8h8.2M151.7 129.3v.1M151.7 131.9v5M151.7 136.9h.1M151.7 134.3h3M157.2 139.4v10.2h-3.8"/>
<path d="M157.2 129.3v.1M160.2 134.5h-3v-2.6v5M160.2 125v3M162.8 129.3h.1M162.8 131.9v5M162.8 139.4h.1M162.8 131.9h.1M162.8 134.4h3M168.3 129.3h.1M168.3 131.9v5M168.3 139.4v.1M168.3 131.9h.1"/>
<path d="M168.3 134.6h2.9M173.8 129.3h.1M173.8 131.9l.1 5M173.8 131.9h.1M173.8 134.5h2.8M173.9 139.4v.1M179.4 134.3h3M179.4 139.4h.1M179.4 129.3h.1M179.4 131.9v5M184.9 131.9v5M184.9 131.9h.1"/>
<path d="M184.9 139.4h1.6M185 129.3h-44.8v.2h-18.3l-.9 1v1.9l-1.3 1.3h-4.1M185 129.3h.1M192 121.6v18.2l-3.2 4.7M203.4 125.6h2.6l7.9 1.6-.1 30.4-2.6 2.6h-12.3l-1.2-1.6v-9.1l-1.6-2.2h-2.9l-2.5 2.6h-4.1M205.6 120.2l2.6 2M207.8 128l3.3 3.6v23.1l-1 1h-7.9l-.1-.4M212.2 129.4v26l-1.5 1.5-10 .1-.7-1.5v-7.5l-2.9-3.1h-5.2l-2 2.1-4.5-.1M107 141.2l.7 .1 .4 .3v25.8l.8 1.3h.4M110.9 144.9v22.9l1.7 1.7h16.7l.8-.8v-2.2M110.9 144.8v.1M112.4 158.6l-.3 .3v7.9l.3 .3"/>
<path d="M115.8 143.9h13.9l4.2 4.2M127.2 145.4l1 1.5v4.5M130.1 146.5v4.9M132 151.4l.1 3.1 2.2 2.2h30.2v8.8l1.6 1h20.9l.8-1 1.3-8.8M133.9 148.1l.1-.2h8.3l.8 .8v2.7l1.3 1.2h3.2v-1.6h7.7v1.1h17l4.5 4.6M133.9 148.1v3.3M149.5 145.7v3.9h-3.2l-.5 .5M157.1 149.6h.1M176.8 156.6v.1M181.5 151.8l-4.7 4.8M182.8 141.2l.7 .9v14.6l-7.8 8M193.3 149.3l-2.6 2.5h-3.1"/>
<path d="M196.1 155.2l-3.4 4.3v6.6l-1.7 .1v.8l-3 2.3h-44.7l-.4 .2M199.4 158.1l-.4-.6v-8.7l-2.4-2.8-3.8 .1-2.1 2.1h-5.9v9.2l-6.7 6.8v.5M201.5 140.8l-.2 .1M189.6 165.3l-.1 1.2-1.5 1.3-41.9-.1M194.4 160.4v4.2l4.8 .1"/>
</g>
<g fill="none" stroke="#800000" stroke-width=".47">
<path d="M130 98.8l-.1 3.4M120.3 106.5l-2.5 2.2M124.8 109h-2.1l-.5 .6v6.1M124.8 111h-1l-.2 .3v4.1l3.7 3.7h8.2M124.8 104.2v.9h-2.6M125.8 103.2l1.1 1v1.9M129.7 108.2l-1.1-1.1h-4.8l-.9 .9h-.5l-1.7 1.7v.9l-2.7 2.6v1M129.7 102.2l.1 .1M133.6 111h7.6v14.4l2 2M133.6 107.1h2.6l.6 .8M133.6 106.1h-10.1l-.9 1h-.9l-3.7 3.7M133.6 104.2h8.9l1.1 .9h4.3"/>
<path d="M133.6 103.2h9.8M141.6 107.3h12.3M150.3 108.2h3.6M151.1 109.2h2.8M151.7 110.2h2.1M152.4 111.2h1.5M153.9 103.4h-1.9v2.9h8.8M155.6 102.4v2h-1.7v.9M162.7 107.3h5.1M162.7 110.2h12.1M162.7 111.2h3M162.7 108.3h6.1"/>
<path d="M162.7 103.4h2.1M162.7 104.4h4.7M162.7 102.4h-8.8l-.2-.2h-30.3l-1.1 1.2v1.6M171.7 109.2l-11.5 .1-2.4 2.3"/>
</g>
<path d="M197.7 37.5l3.1 3.1v3.6l6.2 6.2v14.9l-3.7 3.7h-1.2M163.5 49v29.5l1.2 2.9h37.3l.1-.4M167.3 49l.1 21 4.6 4.3 25.4 .1 .7 .6h4" fill="none" stroke="#800000" stroke-width="1.9"/>
<g fill="none" stroke="#800000" stroke-width="1.2">
<path d="M104.5 56.3v27l2.6 2.5h3.3l4.3 4.3 52.2 .3M108.2 58.4l.1 24.9 .6 .6M148.2 45.1h3.8M154 61.8l-.6 1v20.2M160 61.4l-1.9 3.8v5.1M108.9 88.2l4.5 3.8 93.4 .1 4.6 4.8 .2 2M166.5 90.2l.4 .2M166.9 90.4h42l2.7 2.5M167.8 85.4h24.5l4 3M201.5 95.1h4.2l1.3 1.3M90.4 117h2.9M103.4 114.5l-4.4 .1-2 2h-3.3v9h5.1"/>
<path d="M177.5 109.3h9.1l1.8 1.8h.7l1.4 1.4M201.4 112.1h-9.9l-1.4 1.4v22.9l-3.6 3M103 125.6h9.6M112.6 125.7v3.8M113.7 129.5v6.8l-.6 .6h5.5l.1 .2h1.7l1 1v1.3l18.8 .1M140.2 139.4h10.7M151.7 139.4h11.1M162.8 139.4h16.6M179.4 139.4h5.5"/>
</g>
<path d="M108.9 88.2h.1" fill="none" stroke="#800000" stroke-width="1.5"/>
<circle cx="203.4" cy="140.8" r=".91" fill="#008000" stroke="#008000" stroke-width=".21"/>
<circle cx="203.4" cy="140.8" r=".53" fill="#fff" stroke="#000" stroke-width=".21"/>
<circle cx="201.5" cy="140.8" r=".91" fill="#008000" stroke="#008000" stroke-width=".21"/>
<circle cx="201.5" cy="140.8" r=".53" fill="#fff" stroke="#000" stroke-width=".21"/>
<circle cx="203.4" cy="138.9" r=".91" fill="#008000" stroke="#008000" stroke-width=".21"/>
<circle cx="203.4" cy="138.9" r=".53" fill="#fff" stroke="#000" stroke-width=".21"/>
<circle cx="201.5" cy="138.9" r=".91" fill="#008000" stroke="#008000" stroke-width=".21"/>
<circle cx="201.5" cy="138.9" r=".53" fill="#fff" stroke="#000" stroke-width=".21"/>
<circle cx="203.4" cy="137" r=".91" fill="#008000" stroke="#008000" stroke-width=".21"/>
<circle cx="203.4" cy="137" r=".53" fill="#fff" stroke="#000" stroke-width=".21"/>
<circle cx="201.5" cy="137" r=".91" fill="#008000" stroke="#008000" stroke-width=".21"/>
<circle cx="201.5" cy="137" r=".53" fill="#fff" stroke="#000" stroke-width=".21"/>
<circle cx="203.4" cy="135.1" r=".91" fill="#008000" stroke="#008000" stroke-width=".21"/>
<circle cx="203.4" cy="135.1" r=".53" fill="#fff" stroke="#000" stroke-width=".21"/>
<circle cx="201.5" cy="135.1" r=".91" fill="#008000" stroke="#008000" stroke-width=".21"/>
<circle cx="201.5" cy="135.1" r=".53" fill="#fff" stroke="#000" stroke-width=".21"/>
<circle cx="203.4" cy="133.2" r=".91" fill="#008000" stroke="#008000" stroke-width=".21"/>
<circle cx="203.4" cy="133.2" r=".53" fill="#fff" stroke="#000" stroke-width=".21"/>
<circle cx="201.5" cy="133.2" r=".91" fill="#008000" stroke="#008000" stroke-width=".21"/>
<circle cx="201.5" cy="133.2" r=".53" fill="#fff" stroke="#000" stroke-width=".21"/>
<circle cx="203.4" cy="131.3" r=".91" fill="#008000" stroke="#008000" stroke-width=".21"/>
<circle cx="203.4" cy="131.3" r=".53" fill="#fff" stroke="#000" stroke-width=".21"/>
<circle cx="201.5" cy="131.3" r=".91" fill="#008000" stroke="#008000" stroke-width=".21"/>
<circle cx="201.5" cy="131.3" r=".53" fill="#fff" stroke="#000" stroke-width=".21"/>
<circle cx="203.4" cy="129.4" r=".91" fill="#008000" stroke="#008000" stroke-width=".21"/>
<circle cx="203.4" cy="129.4" r=".53" fill="#fff" stroke="#000" stroke-width=".21"/>
<circle cx="201.5" cy="129.4" r=".91" fill="#008000" stroke="#008000" stroke-width=".21"/>
<circle cx="201.5" cy="129.4" r=".53" fill="#fff" stroke="#000" stroke-width=".21"/>
<circle cx="203.4" cy="127.5" r=".91" fill="#008000" stroke="#008000" stroke-width=".21"/>
<circle cx="203.4" cy="127.5" r=".53" fill="#fff" stroke="#000" stroke-width=".21"/>
<circle cx="201.5" cy="127.5" r=".91" fill="#008000" stroke="#008000" stroke-width=".21"/>
<circle cx="201.5" cy="127.5" r=".53" fill="#fff" stroke="#000" stroke-width=".21"/>
<circle cx="203.4" cy="125.6" r=".91" fill="#008000" stroke="#008000" stroke-width=".21"/>
<circle cx="203.4" cy="125.6" r=".53" fill="#fff" stroke="#000" stroke-width=".21"/>
<circle cx="201.5" cy="125.6" r=".91" fill="#008000" stroke="#008000" stroke-width=".21"/>
<circle cx="201.5" cy="125.6" r=".53" fill="#fff" stroke="#000" stroke-width=".21"/>
<circle cx="203.4" cy="123.7" r=".91" fill="#008000" stroke="#008000" stroke-width=".21"/>
<circle cx="203.4" cy="123.7" r=".53" fill="#fff" stroke="#000" stroke-width=".21"/>
<circle cx="201.5" cy="123.7" r=".91" fill="#008000" stroke="#008000" stroke-width=".21"/>
<circle cx="201.5" cy="123.7" r=".53" fill="#fff" stroke="#000" stroke-width=".21"/>
<circle cx="203.4" cy="121.8" r=".91" fill="#008000" stroke="#008000" stroke-width=".21"/>
<circle cx="203.4" cy="121.8" r=".53" fill="#fff" stroke="#000" stroke-width=".21"/>
<circle cx="201.5" cy="121.8" r=".91" fill="#008000" stroke="#008000" stroke-width=".21"/>
<circle cx="201.5" cy="121.8" r=".53" fill="#fff" stroke="#000" stroke-width=".21"/>
<circle cx="203.4" cy="119.8" r=".91" fill="#008000" stroke="#008000" stroke-width=".21"/>
<circle cx="203.4" cy="119.8" r=".53" fill="#fff" stroke="#000" stroke-width=".21"/>
<circle cx="201.5" cy="119.8" r=".91" fill="#008000" stroke="#008000" stroke-width=".21"/>
<circle cx="201.5" cy="119.8" r=".53" fill="#fff" stroke="#000" stroke-width=".21"/>
<circle cx="203.4" cy="117.9" r=".91" fill="#008000" stroke="#008000" stroke-width=".21"/>
<circle cx="203.4" cy="117.9" r=".53" fill="#fff" stroke="#000" stroke-width=".21"/>
<circle cx="201.5" cy="117.9" r=".91" fill="#008000" stroke="#008000" stroke-width=".21"/>
<circle cx="201.5" cy="117.9" r=".53" fill="#fff" stroke="#000" stroke-width=".21"/>
<circle cx="203.4" cy="116" r=".91" fill="#008000" stroke="#008000" stroke-width=".21"/>
<circle cx="203.4" cy="116" r=".53" fill="#fff" stroke="#000" stroke-width=".21"/>
<circle cx="201.5" cy="116" r=".91" fill="#008000" stroke="#008000" stroke-width=".21"/>
<circle cx="201.5" cy="116" r=".53" fill="#fff" stroke="#000" stroke-width=".21"/>
<circle cx="203.4" cy="114.1" r=".91" fill="#008000" stroke="#008000" stroke-width=".21"/>
<circle cx="203.4" cy="114.1" r=".53" fill="#fff" stroke="#000" stroke-width=".21"/>
<circle cx="201.5" cy="114.1" r=".91" fill="#008000" stroke="#008000" stroke-width=".21"/>
<circle cx="201.5" cy="114.1" r=".53" fill="#fff" stroke="#000" stroke-width=".21"/>
<circle cx="203.4" cy="112.2" r=".91" fill="#008000" stroke="#008000" stroke-width=".21"/>
<circle cx="203.4" cy="112.2" r=".53" fill="#fff" stroke="#000" stroke-width=".21"/>
<circle cx="201.5" cy="112.2" r=".91" fill="#008000" stroke="#008000" stroke-width=".21"/>
<circle cx="201.5" cy="112.2" r=".53" fill="#fff" stroke="#000" stroke-width=".21"/>
<circle cx="203.4" cy="110.3" r=".91" fill="#008000" stroke="#008000" stroke-width=".21"/>
<circle cx="203.4" cy="110.3" r=".53" fill="#fff" stroke="#000" stroke-width=".21"/>
<circle cx="201.5" cy="110.3" r=".91" fill="#008000" stroke="#008000" stroke-width=".21"/>
<circle cx="201.5" cy="110.3" r=".53" fill="#fff" stroke="#000" stroke-width=".21"/>
<circle cx="203.4" cy="108.4" r=".91" fill="#008000" stroke="#008000" stroke-width=".21"/>
<circle cx="203.4" cy="108.4" r=".53" fill="#fff" stroke="#000" stroke-width=".21"/>
<circle cx="201.5" cy="108.4" r=".91" fill="#008000" stroke="#008000" stroke-width=".21"/>
<circle cx="201.5" cy="108.4" r=".53" fill="#fff" stroke="#000" stroke-width=".21"/>
<circle cx="203.4" cy="106.5" r=".91" fill="#008000" stroke="#008000" stroke-width=".21"/>
<circle cx="203.4" cy="106.5" r=".53" fill="#fff" stroke="#000" stroke-width=".21"/>
<circle cx="201.5" cy="106.5" r=".91" fill="#008000" stroke="#008000" stroke-width=".21"/>
<circle cx="201.5" cy="106.5" r=".53" fill="#fff" stroke="#000" stroke-width=".21"/>
<circle cx="203.4" cy="104.6" r=".91" fill="#008000" stroke="#008000" stroke-width=".21"/>
<circle cx="203.4" cy="104.6" r=".53" fill="#fff" stroke="#000" stroke-width=".21"/>
<circle cx="201.5" cy="104.6" r=".91" fill="#008000" stroke="#008000" stroke-width=".21"/>
<circle cx="201.5" cy="104.6" r=".53" fill="#fff" stroke="#000" stroke-width=".21"/>
<circle cx="203.4" cy="102.7" r=".91" fill="#008000" stroke="#008000" stroke-width=".21"/>
<circle cx="203.4" cy="102.7" r=".53" fill="#fff" stroke="#000" stroke-width=".21"/>
<circle cx="201.5" cy="102.7" r=".91" fill="#008000" stroke="#008000" stroke-width=".21"/>
<circle cx="201.5" cy="102.7" r=".53" fill="#fff" stroke="#000" stroke-width=".21"/>
<circle cx="203.4" cy="100.8" r=".91" fill="#008000" stroke="#008000" stroke-width=".21"/>
<circle cx="203.4" cy="100.8" r=".53" fill="#fff" stroke="#000" stroke-width=".21"/>
<circle cx="201.5" cy="100.8" r=".91" fill="#008000" stroke="#008000" stroke-width=".21"/>
<circle cx="201.5" cy="100.8" r=".53" fill="#fff" stroke="#000" stroke-width=".21"/>
<circle cx="203.4" cy="98.9" r=".91" fill="#008000" stroke="#008000" stroke-width=".21"/>
<circle cx="203.4" cy="98.9" r=".53" fill="#fff" stroke="#000" stroke-width=".21"/>
<circle cx="201.5" cy="98.9" r=".91" fill="#008000" stroke="#008000" stroke-width=".21"/>
<circle cx="201.5" cy="98.9" r=".53" fill="#fff" stroke="#000" stroke-width=".21"/>
<circle cx="203.4" cy="97" r=".91" fill="#008000" stroke="#008000" stroke-width=".21"/>
<circle cx="203.4" cy="97" r=".53" fill="#fff" stroke="#000" stroke-width=".21"/>
<circle cx="201.5" cy="97" r=".91" fill="#008000" stroke="#008000" stroke-width=".21"/>
<circle cx="201.5" cy="97" r=".53" fill="#fff" stroke="#000" stroke-width=".21"/>
<circle cx="203.4" cy="95.1" r=".91" fill="#008000" stroke="#008000" stroke-width=".21"/>
<circle cx="203.4" cy="95.1" r=".53" fill="#fff" stroke="#000" stroke-width=".21"/>
<circle cx="201.5" cy="95.1" r=".91" fill="#008000" stroke="#008000" stroke-width=".21"/>
<circle cx="201.5" cy="95.1" r=".53" fill="#fff" stroke="#000" stroke-width=".21"/>
<circle cx="102.5" cy="41.4" r="1.14" fill="#008000" stroke="#008000" stroke-width=".21"/>
<circle cx="102.5" cy="41.4" r=".76" fill="#fff" stroke="#000" stroke-width=".21"/>
<circle cx="102.5" cy="37.5" r="1.14" fill="#008000" stroke="#008000" stroke-width=".21"/>
<circle cx="102.5" cy="37.5" r=".76" fill="#fff" stroke="#000" stroke-width=".21"/>
<circle cx="106.3" cy="41.4" r="1.14" fill="#008000" stroke="#008000" stroke-width=".21"/>
<circle cx="106.3" cy="41.4" r=".76" fill="#fff" stroke="#000" stroke-width=".21"/>
<circle cx="106.3" cy="37.5" r="1.14" fill="#008000" stroke="#008000" stroke-width=".21"/>
<circle cx="106.3" cy="37.5" r=".76" fill="#fff" stroke="#000" stroke-width=".21"/>
<circle cx="110.1" cy="41.4" r="1.14" fill="#008000" stroke="#008000" stroke-width=".21"/>
<circle cx="110.1" cy="41.4" r=".76" fill="#fff" stroke="#000" stroke-width=".21"/>
<circle cx="110.1" cy="37.5" r="1.14" fill="#008000" stroke="#008000" stroke-width=".21"/>
<circle cx="110.1" cy="37.5" r=".76" fill="#fff" stroke="#000" stroke-width=".21"/>
<circle cx="113.9" cy="41.4" r="1.14" fill="#008000" stroke="#008000" stroke-width=".21"/>
<circle cx="113.9" cy="41.4" r=".76" fill="#fff" stroke="#000" stroke-width=".21"/>
<circle cx="113.9" cy="37.5" r="1.14" fill="#008000" stroke="#008000" stroke-width=".21"/>
<circle cx="113.9" cy="37.5" r=".76" fill="#fff" stroke="#000" stroke-width=".21"/>
<circle cx="117.8" cy="41.4" r="1.14" fill="#008000" stroke="#008000" stroke-width=".21"/>
<circle cx="117.8" cy="41.4" r=".76" fill="#fff" stroke="#000" stroke-width=".21"/>
<circle cx="117.8" cy="37.5" r="1.14" fill="#008000" stroke="#008000" stroke-width=".21"/>
<circle cx="117.8" cy="37.5" r=".76" fill="#fff" stroke="#000" stroke-width=".21"/>
<circle cx="121.6" cy="41.4" r="1.14" fill="#008000" stroke="#008000" stroke-width=".21"/>
<circle cx="121.6" cy="41.4" r=".76" fill="#fff" stroke="#000" stroke-width=".21"/>
<circle cx="121.6" cy="37.5" r="1.14" fill="#008000" stroke="#008000" stroke-width=".21"/>
<circle cx="121.6" cy="37.5" r=".76" fill="#fff" stroke="#000" stroke-width=".21"/>
<circle cx="125.4" cy="41.4" r="1.14" fill="#008000" stroke="#008000" stroke-width=".21"/>
<circle cx="125.4" cy="41.4" r=".76" fill="#fff" stroke="#000" stroke-width=".21"/>
<circle cx="125.4" cy="37.5" r="1.14" fill="#008000" stroke="#008000" stroke-width=".21"/>
<circle cx="125.4" cy="37.5" r=".76" fill="#fff" stroke="#000" stroke-width=".21"/>
<circle cx="129.2" cy="41.4" r="1.14" fill="#008000" stroke="#008000" stroke-width=".21"/>
<circle cx="129.2" cy="41.4" r=".76" fill="#fff" stroke="#000" stroke-width=".21"/>
<circle cx="129.2" cy="37.5" r="1.14" fill="#008000" stroke="#008000" stroke-width=".21"/>
<circle cx="129.2" cy="37.5" r=".76" fill="#fff" stroke="#000" stroke-width=".21"/>
<circle cx="133" cy="41.4" r="1.14" fill="#008000" stroke="#008000" stroke-width=".21"/>
<circle cx="133" cy="41.4" r=".76" fill="#fff" stroke="#000" stroke-width=".21"/>
<circle cx="133" cy="37.5" r="1.14" fill="#008000" stroke="#008000" stroke-width=".21"/>
<circle cx="133" cy="37.5" r=".76" fill="#fff" stroke="#000" stroke-width=".21"/>
<circle cx="136.8" cy="41.4" r="1.14" fill="#008000" stroke="#008000" stroke-width=".21"/>
<circle cx="136.8" cy="41.4" r=".76" fill="#fff" stroke="#000" stroke-width=".21"/>
<circle cx="136.8" cy="37.5" r="1.14" fill="#008000" stroke="#008000" stroke-width=".21"/>
<circle cx="136.8" cy="37.5" r=".76" fill="#fff" stroke="#000" stroke-width=".21"/>
<circle cx="140.6" cy="41.4" r="1.14" fill="#008000" stroke="#008000" stroke-width=".21"/>
<circle cx="140.6" cy="41.4" r=".76" fill="#fff" stroke="#000" stroke-width=".21"/>
<circle cx="140.6" cy="37.5" r="1.14" fill="#008000" stroke="#008000" stroke-width=".21"/>
<circle cx="140.6" cy="37.5" r=".76" fill="#fff" stroke="#000" stroke-width=".21"/>
<circle cx="144.4" cy="41.4" r="1.14" fill="#008000" stroke="#008000" stroke-width=".21"/>
<circle cx="144.4" cy="41.4" r=".76" fill="#fff" stroke="#000" stroke-width=".21"/>
<circle cx="144.4" cy="37.5" r="1.14" fill="#008000" stroke="#008000" stroke-width=".21"/>
<circle cx="144.4" cy="37.5" r=".76" fill="#fff" stroke="#000" stroke-width=".21"/>
<circle cx="148.2" cy="41.4" r="1.14" fill="#008000" stroke="#008000" stroke-width=".21"/>
<circle cx="148.2" cy="41.4" r=".76" fill="#fff" stroke="#000" stroke-width=".21"/>
<circle cx="148.2" cy="37.5" r="1.14" fill="#008000" stroke="#008000" stroke-width=".21"/>
<circle cx="148.2" cy="37.5" r=".76" fill="#fff" stroke="#000" stroke-width=".21"/>
<circle cx="152" cy="41.4" r="1.14" fill="#008000" stroke="#008000" stroke-width=".21"/>
<circle cx="152" cy="41.4" r=".76" fill="#fff" stroke="#000" stroke-width=".21"/>
<circle cx="152" cy="37.5" r="1.14" fill="#008000" stroke="#008000" stroke-width=".21"/>
<circle cx="152" cy="37.5" r=".76" fill="#fff" stroke="#000" stroke-width=".21"/>
<circle cx="155.8" cy="41.4" r="1.14" fill="#008000" stroke="#008000" stroke-width=".21"/>
<circle cx="155.8" cy="41.4" r=".76" fill="#fff" stroke="#000" stroke-width=".21"/>
<circle cx="155.8" cy="37.5" r="1.14" fill="#008000" stroke="#008000" stroke-width=".21"/>
<circle cx="155.8" cy="37.5" r=".76" fill="#fff" stroke="#000" stroke-width=".21"/>
<circle cx="159.6" cy="41.4" r="1.14" fill="#008000" stroke="#008000" stroke-width=".21"/>
<circle cx="159.6" cy="41.4" r=".76" fill="#fff" stroke="#000" stroke-width=".21"/>
<circle cx="159.6" cy="37.5" r="1.14" fill="#008000" stroke="#008000" stroke-width=".21"/>
<circle cx="159.6" cy="37.5" r=".76" fill="#fff" stroke="#000" stroke-width=".21"/>
<circle cx="163.4" cy="41.4" r="1.14" fill="#008000" stroke="#008000" stroke-width=".21"/>
<circle cx="163.4" cy="41.4" r=".76" fill="#fff" stroke="#000" stroke-width=".21"/>
<circle cx="163.4" cy="37.5" r="1.14" fill="#008000" stroke="#008000" stroke-width=".21"/>
<circle cx="163.4" cy="37.5" r=".76" fill="#fff" stroke="#000" stroke-width=".21"/>
<circle cx="167.3" cy="41.4" r="1.14" fill="#008000" stroke="#008000" stroke-width=".21"/>
<circle cx="167.3" cy="41.4" r=".76" fill="#fff" stroke="#000" stroke-width=".21"/>
<circle cx="167.3" cy="37.5" r="1.14" fill="#008000" stroke="#008000" stroke-width=".21"/>
<circle cx="167.3" cy="37.5" r=".76" fill="#fff" stroke="#000" stroke-width=".21"/>
<circle cx="171.1" cy="41.4" r="1.14" fill="#008000" stroke="#008000" stroke-width=".21"/>
<circle cx="171.1" cy="41.4" r=".76" fill="#fff" stroke="#000" stroke-width=".21"/>
<circle cx="171.1" cy="37.5" r="1.14" fill="#008000" stroke="#008000" stroke-width=".21"/>
<circle cx="171.1" cy="37.5" r=".76" fill="#fff" stroke="#000" stroke-width=".21"/>
<circle cx="174.9" cy="41.4" r="1.14" fill="#008000" stroke="#008000" stroke-width=".21"/>
<circle cx="174.9" cy="41.4" r=".76" fill="#fff" stroke="#000" stroke-width=".21"/>
<circle cx="174.9" cy="37.5" r="1.14" fill="#008000" stroke="#008000" stroke-width=".21"/>
<circle cx="174.9" cy="37.5" r=".76" fill="#fff" stroke="#000" stroke-width=".21"/>
<circle cx="178.7" cy="41.4" r="1.14" fill="#008000" stroke="#008000" stroke-width=".21"/>
<circle cx="178.7" cy="41.4" r=".76" fill="#fff" stroke="#000" stroke-width=".21"/>
<circle cx="178.7" cy="37.5" r="1.14" fill="#008000" stroke="#008000" stroke-width=".21"/>
<circle cx="178.7" cy="37.5" r=".76" fill="#fff" stroke="#000" stroke-width=".21"/>
<circle cx="182.5" cy="41.4" r="1.14" fill="#008000" stroke="#008000" stroke-width=".21"/>
<circle cx="182.5" cy="41.4" r=".76" fill="#fff" stroke="#000" stroke-width=".21"/>
<circle cx="182.5" cy="37.5" r="1.14" fill="#008000" stroke="#008000" stroke-width=".21"/>
<circle cx="182.5" cy="37.5" r=".76" fill="#fff" stroke="#000" stroke-width=".21"/>
<circle cx="186.3" cy="41.4" r="1.14" fill="#008000" stroke="#008000" stroke-width=".21"/>
<circle cx="186.3" cy="41.4" r=".76" fill="#fff" stroke="#000" stroke-width=".21"/>
<circle cx="186.3" cy="37.5" r="1.14" fill="#008000" stroke="#008000" stroke-width=".21"/>
<circle cx="186.3" cy="37.5" r=".76" fill="#fff" stroke="#000" stroke-width=".21"/>
<circle cx="190.1" cy="41.4" r="1.14" fill="#008000" stroke="#008000" stroke-width=".21"/>
<circle cx="190.1" cy="41.4" r=".76" fill="#fff" stroke="#000" stroke-width=".21"/>
<circle cx="190.1" cy="37.5" r="1.14" fill="#008000" stroke="#008000" stroke-width=".21"/>
<circle cx="190.1" cy="37.5" r=".76" fill="#fff" stroke="#000" stroke-width=".21"/>
<circle cx="193.9" cy="41.4" r="1.14" fill="#008000" stroke="#008000" stroke-width=".21"/>
<circle cx="193.9" cy="41.4" r=".76" fill="#fff" stroke="#000" stroke-width=".21"/>
<circle cx="193.9" cy="37.5" r="1.14" fill="#008000" stroke="#008000" stroke-width=".21"/>
<circle cx="193.9" cy="37.5" r=".76" fill="#fff" stroke="#000" stroke-width=".21"/>
<circle cx="197.7" cy="41.4" r="1.14" fill="#008000" stroke="#008000" stroke-width=".21"/>
<circle cx="197.7" cy="41.4" r=".76" fill="#fff" stroke="#000" stroke-width=".21"/>
<circle cx="197.7" cy="37.5" r="1.14" fill="#008000" stroke="#008000" stroke-width=".21"/>
<circle cx="197.7" cy="37.5" r=".76" fill="#fff" stroke="#000" stroke-width=".21"/>
<circle cx="102.5" cy="49" r="1.14" fill="#008000" stroke="#008000" stroke-width=".21"/>
<circle cx="102.5" cy="49" r=".76" fill="#fff" stroke="#000" stroke-width=".21"/>
<circle cx="102.5" cy="45.1" r="1.14" fill="#008000" stroke="#008000" stroke-width=".21"/>
<circle cx="102.5" cy="45.1" r=".76" fill="#fff" stroke="#000" stroke-width=".21"/>
<circle cx="106.3" cy="49" r="1.14" fill="#008000" stroke="#008000" stroke-width=".21"/>
<circle cx="106.3" cy="49" r=".76" fill="#fff" stroke="#000" stroke-width=".21"/>
<circle cx="106.3" cy="45.1" r="1.14" fill="#008000" stroke="#008000" stroke-width=".21"/>
<circle cx="106.3" cy="45.1" r=".76" fill="#fff" stroke="#000" stroke-width=".21"/>
<circle cx="110.1" cy="49" r="1.14" fill="#008000" stroke="#008000" stroke-width=".21"/>
<circle cx="110.1" cy="49" r=".76" fill="#fff" stroke="#000" stroke-width=".21"/>
<circle cx="110.1" cy="45.1" r="1.14" fill="#008000" stroke="#008000" stroke-width=".21"/>
<circle cx="110.1" cy="45.1" r=".76" fill="#fff" stroke="#000" stroke-width=".21"/>
<circle cx="113.9" cy="49" r="1.14" fill="#008000" stroke="#008000" stroke-width=".21"/>
<circle cx="113.9" cy="49" r=".76" fill="#fff" stroke="#000" stroke-width=".21"/>
<circle cx="113.9" cy="45.1" r="1.14" fill="#008000" stroke="#008000" stroke-width=".21"/>
<circle cx="113.9" cy="45.1" r=".76" fill="#fff" stroke="#000" stroke-width=".21"/>
<circle cx="117.8" cy="49" r="1.14" fill="#008000" stroke="#008000" stroke-width=".21"/>
<circle cx="117.8" cy="49" r=".76" fill="#fff" stroke="#000" stroke-width=".21"/>
<circle cx="117.8" cy="45.1" r="1.14" fill="#008000" stroke="#008000" stroke-width=".21"/>
<circle cx="117.8" cy="45.1" r=".76" fill="#fff" stroke="#000" stroke-width=".21"/>
<circle cx="121.6" cy="49" r="1.14" fill="#008000" stroke="#008000" stroke-width=".21"/>
<circle cx="121.6" cy="49" r=".76" fill="#fff" stroke="#000" stroke-width=".21"/>
<circle cx="121.6" cy="45.1" r="1.14" fill="#008000" stroke="#008000" stroke-width=".21"/>
<circle cx="121.6" cy="45.1" r=".76" fill="#fff" stroke="#000" stroke-width=".21"/>
<circle cx="125.4" cy="49" r="1.14" fill="#008000" stroke="#008000" stroke-width=".21"/>
<circle cx="125.4" cy="49" r=".76" fill="#fff" stroke="#000" stroke-width=".21"/>
<circle cx="125.4" cy="45.1" r="1.14" fill="#008000" stroke="#008000" stroke-width=".21"/>
<circle cx="125.4" cy="45.1" r=".76" fill="#fff" stroke="#000" stroke-width=".21"/>
<circle cx="129.2" cy="49" r="1.14" fill="#008000" stroke="#008000" stroke-width=".21"/>
<circle cx="129.2" cy="49" r=".76" fill="#fff" stroke="#000" stroke-width=".21"/>
<circle cx="129.2" cy="45.1" r="1.14" fill="#008000" stroke="#008000" stroke-width=".21"/>
<circle cx="129.2" cy="45.1" r=".76" fill="#fff" stroke="#000" stroke-width=".21"/>
<circle cx="133" cy="49" r="1.14" fill="#008000" stroke="#008000" stroke-width=".21"/>
<circle cx="133" cy="49" r=".76" fill="#fff" stroke="#000" stroke-width=".21"/>
<circle cx="133" cy="45.1" r="1.14" fill="#008000" stroke="#008000" stroke-width=".21"/>
<circle cx="133" cy="45.1" r=".76" fill="#fff" stroke="#000" stroke-width=".21"/>
<circle cx="136.8" cy="49" r="1.14" fill="#008000" stroke="#008000" stroke-width=".21"/>
<circle cx="136.8" cy="49" r=".76" fill="#fff" stroke="#000" stroke-width=".21"/>
<circle cx="136.8" cy="45.1" r="1.14" fill="#008000" stroke="#008000" stroke-width=".21"/>
<circle cx="136.8" cy="45.1" r=".76" fill="#fff" stroke="#000" stroke-width=".21"/>
<circle cx="140.6" cy="49" r="1.14" fill="#008000" stroke="#008000" stroke-width=".21"/>
<circle cx="140.6" cy="49" r=".76" fill="#fff" stroke="#000" stroke-width=".21"/>
<circle cx="140.6" cy="45.1" r="1.14" fill="#008000" stroke="#008000" stroke-width=".21"/>
<circle cx="140.6" cy="45.1" r=".76" fill="#fff" stroke="#000" stroke-width=".21"/>
<circle cx="144.4" cy="49" r="1.14" fill="#008000" stroke="#008000" stroke-width=".21"/>
<circle cx="144.4" cy="49" r=".76" fill="#fff" stroke="#000" stroke-width=".21"/>
<circle cx="144.4" cy="45.1" r="1.14" fill="#008000" stroke="#008000" stroke-width=".21"/>
<circle cx="144.4" cy="45.1" r=".76" fill="#fff" stroke="#000" stroke-width=".21"/>
<circle cx="148.2" cy="49" r="1.14" fill="#008000" stroke="#008000" stroke-width=".21"/>
<circle cx="148.2" cy="49" r=".76" fill="#fff" stroke="#000" stroke-width=".21"/>
<circle cx="148.2" cy="45.1" r="1.14" fill="#008000" stroke="#008000" stroke-width=".21"/>
<circle cx="148.2" cy="45.1" r=".76" fill="#fff" stroke="#000" stroke-width=".21"/>
<circle cx="152" cy="49" r="1.14" fill="#008000" stroke="#008000" stroke-width=".21"/>
<circle cx="152" cy="49" r=".76" fill="#fff" stroke="#000" stroke-width=".21"/>
<circle cx="152" cy="45.1" r="1.14" fill="#008000" stroke="#008000" stroke-width=".21"/>
<circle cx="152" cy="45.1" r=".76" fill="#fff" stroke="#000" stroke-width=".21"/>
<circle cx="155.9" cy="49" r="1.14" fill="#008000" stroke="#008000" stroke-width=".21"/>
<circle cx="155.9" cy="49" r=".76" fill="#fff" stroke="#000" stroke-width=".21"/>
<circle cx="155.9" cy="45.1" r="1.14" fill="#008000" stroke="#008000" stroke-width=".21"/>
<circle cx="155.9" cy="45.1" r=".76" fill="#fff" stroke="#000" stroke-width=".21"/>
<circle cx="159.7" cy="49" r="1.14" fill="#008000" stroke="#008000" stroke-width=".21"/>
<circle cx="159.7" cy="49" r=".76" fill="#fff" stroke="#000" stroke-width=".21"/>
<circle cx="159.7" cy="45.1" r="1.14" fill="#008000" stroke="#008000" stroke-width=".21"/>
<circle cx="159.7" cy="45.1" r=".76" fill="#fff" stroke="#000" stroke-width=".21"/>
<circle cx="163.5" cy="49" r="1.14" fill="#008000" stroke="#008000" stroke-width=".21"/>
<circle cx="163.5" cy="49" r=".76" fill="#fff" stroke="#000" stroke-width=".21"/>
<circle cx="163.5" cy="45.1" r="1.14" fill="#008000" stroke="#008000" stroke-width=".21"/>
<circle cx="163.5" cy="45.1" r=".76" fill="#fff" stroke="#000" stroke-width=".21"/>
<circle cx="167.3" cy="49" r="1.14" fill="#008000" stroke="#008000" stroke-width=".21"/>
<circle cx="167.3" cy="49" r=".76" fill="#fff" stroke="#000" stroke-width=".21"/>
<circle cx="167.3" cy="45.1" r="1.14" fill="#008000" stroke="#008000" stroke-width=".21"/>
<circle cx="167.3" cy="45.1" r=".76" fill="#fff" stroke="#000" stroke-width=".21"/>
<circle cx="171.1" cy="49" r="1.14" fill="#008000" stroke="#008000" stroke-width=".21"/>
<circle cx="171.1" cy="49" r=".76" fill="#fff" stroke="#000" stroke-width=".21"/>
<circle cx="171.1" cy="45.1" r="1.14" fill="#008000" stroke="#008000" stroke-width=".21"/>
<circle cx="171.1" cy="45.1" r=".76" fill="#fff" stroke="#000" stroke-width=".21"/>
<circle cx="174.9" cy="49" r="1.14" fill="#008000" stroke="#008000" stroke-width=".21"/>
<circle cx="174.9" cy="49" r=".76" fill="#fff" stroke="#000" stroke-width=".21"/>
<circle cx="174.9" cy="45.1" r="1.14" fill="#008000" stroke="#008000" stroke-width=".21"/>
<circle cx="174.9" cy="45.1" r=".76" fill="#fff" stroke="#000" stroke-width=".21"/>
<circle cx="178.7" cy="49" r="1.14" fill="#008000" stroke="#008000" stroke-width=".21"/>
<circle cx="178.7" cy="49" r=".76" fill="#fff" stroke="#000" stroke-width=".21"/>
<circle cx="178.7" cy="45.1" r="1.14" fill="#008000" stroke="#008000" stroke-width=".21"/>
<circle cx="178.7" cy="45.1" r=".76" fill="#fff" stroke="#000" stroke-width=".21"/>
<circle cx="182.5" cy="49" r="1.14" fill="#008000" stroke="#008000" stroke-width=".21"/>
<circle cx="182.5" cy="49" r=".76" fill="#fff" stroke="#000" stroke-width=".21"/>
<circle cx="182.5" cy="45.1" r="1.14" fill="#008000" stroke="#008000" stroke-width=".21"/>
<circle cx="182.5" cy="45.1" r=".76" fill="#fff" stroke="#000" stroke-width=".21"/>
<circle cx="186.3" cy="49" r="1.14" fill="#008000" stroke="#008000" stroke-width=".21"/>
<circle cx="186.3" cy="49" r=".76" fill="#fff" stroke="#000" stroke-width=".21"/>
<circle cx="186.3" cy="45.1" r="1.14" fill="#008000" stroke="#008000" stroke-width=".21"/>
<circle cx="186.3" cy="45.1" r=".76" fill="#fff" stroke="#000" stroke-width=".21"/>
<circle cx="190.1" cy="49" r="1.14" fill="#008000" stroke="#008000" stroke-width=".21"/>
<circle cx="190.1" cy="49" r=".76" fill="#fff" stroke="#000" stroke-width=".21"/>
<circle cx="190.1" cy="45.1" r="1.14" fill="#008000" stroke="#008000" stroke-width=".21"/>
<circle cx="190.1" cy="45.1" r=".76" fill="#fff" stroke="#000" stroke-width=".21"/>
<circle cx="193.9" cy="49" r="1.14" fill="#008000" stroke="#008000" stroke-width=".21"/>
<circle cx="193.9" cy="49" r=".76" fill="#fff" stroke="#000" stroke-width=".21"/>
<circle cx="193.9" cy="45.1" r="1.14" fill="#008000" stroke="#008000" stroke-width=".21"/>
<circle cx="193.9" cy="45.1" r=".76" fill="#fff" stroke="#000" stroke-width=".21"/>
<circle cx="197.7" cy="49" r="1.14" fill="#008000" stroke="#008000" stroke-width=".21"/>
<circle cx="197.7" cy="49" r=".76" fill="#fff" stroke="#000" stroke-width=".21"/>
<circle cx="197.7" cy="45.1" r="1.14" fill="#008000" stroke="#008000" stroke-width=".21"/>
<circle cx="197.7" cy="45.1" r=".76" fill="#fff" stroke="#000" stroke-width=".21"/>
<circle cx="202.1" cy="81" r="1.8" fill="#008000" stroke="#008000" stroke-width=".21"/>
<circle cx="202.1" cy="81" r="1.21" fill="#fff" stroke="#000" stroke-width=".21"/>
<circle cx="202.1" cy="75" r="1.8" fill="#008000" stroke="#008000" stroke-width=".21"/>
<circle cx="202.1" cy="75" r="1.21" fill="#fff" stroke="#000" stroke-width=".21"/>
<circle cx="202.1" cy="69" r="1.8" fill="#008000" stroke="#008000" stroke-width=".21"/>
<circle cx="202.1" cy="69" r="1.21" fill="#fff" stroke="#000" stroke-width=".21"/>
<circle cx="202.1" cy="63" r="1.8" fill="#008000" stroke="#008000" stroke-width=".21"/>
<circle cx="202.1" cy="63" r="1.21" fill="#fff" stroke="#000" stroke-width=".21"/>
<circle cx="202.1" cy="87" r="2.41" fill="#008000" stroke="#008000" stroke-width=".21"/>
<circle cx="202.1" cy="87" r="1.65" fill="#fff" stroke="#000" stroke-width=".21"/>
<circle cx="202.1" cy="57" r="2.41" fill="#008000" stroke="#008000" stroke-width=".21"/>
<circle cx="202.1" cy="57" r="1.65" fill="#fff" stroke="#000" stroke-width=".21"/>
<circle cx="211.6" cy="62.9" r="1.8" fill="#008000" stroke="#008000" stroke-width=".21"/>
<circle cx="211.6" cy="62.9" r="1.21" fill="#fff" stroke="#000" stroke-width=".21"/>
<circle cx="211.6" cy="68.9" r="1.8" fill="#008000" stroke="#008000" stroke-width=".21"/>
<circle cx="211.6" cy="68.9" r="1.21" fill="#fff" stroke="#000" stroke-width=".21"/>
<circle cx="211.6" cy="74.9" r="1.8" fill="#008000" stroke="#008000" stroke-width=".21"/>
<circle cx="211.6" cy="74.9" r="1.21" fill="#fff" stroke="#000" stroke-width=".21"/>
<circle cx="211.6" cy="80.9" r="1.8" fill="#008000" stroke="#008000" stroke-width=".21"/>
<circle cx="211.6" cy="80.9" r="1.21" fill="#fff" stroke="#000" stroke-width=".21"/>
<circle cx="211.6" cy="86.9" r="1.8" fill="#008000" stroke="#008000" stroke-width=".21"/>
<circle cx="211.6" cy="86.9" r="1.21" fill="#fff" stroke="#000" stroke-width=".21"/>
<circle cx="211.6" cy="92.9" r="1.8" fill="#008000" stroke="#008000" stroke-width=".21"/>
<circle cx="211.6" cy="92.9" r="1.21" fill="#fff" stroke="#000" stroke-width=".21"/>
<circle cx="211.6" cy="98.9" r="1.8" fill="#008000" stroke="#008000" stroke-width=".21"/>
<circle cx="211.6" cy="98.9" r="1.21" fill="#fff" stroke="#000" stroke-width=".21"/>
<circle cx="211.6" cy="104.9" r="1.8" fill="#008000" stroke="#008000" stroke-width=".21"/>
<circle cx="211.6" cy="104.9" r="1.21" fill="#fff" stroke="#000" stroke-width=".21"/>
<circle cx="211.6" cy="110.9" r="1.8" fill="#008000" stroke="#008000" stroke-width=".21"/>
<circle cx="211.6" cy="110.9" r="1.21" fill="#fff" stroke="#000" stroke-width=".21"/>
<circle cx="211.6" cy="116.9" r="1.8" fill="#008000" stroke="#008000" stroke-width=".21"/>
<circle cx="211.6" cy="116.9" r="1.21" fill="#fff" stroke="#000" stroke-width=".21"/>
<circle cx="211.6" cy="56.9" r="2.41" fill="#008000" stroke="#008000" stroke-width=".21"/>
<circle cx="211.6" cy="56.9" r="1.65" fill="#fff" stroke="#000" stroke-width=".21"/>
<circle cx="211.6" cy="122.9" r="2.41" fill="#008000" stroke="#008000" stroke-width=".21"/>
<circle cx="211.6" cy="122.9" r="1.65" fill="#fff" stroke="#000" stroke-width=".21"/>
<path d="M143.4 97.6v1.9" fill="none" stroke="#008000" stroke-width="2"/>
<circle cx="143.4" cy="98.6" r=".61" fill="#fff" stroke="#000" stroke-width=".21"/>
<path d="M139.6 97.6v1.9" fill="none" stroke="#008000" stroke-width="2"/>
<circle cx="139.6" cy="98.6" r=".61" fill="#fff" stroke="#000" stroke-width=".21"/>
<circle cx="115.6" cy="133.7" r=".68" fill="#008000" stroke="#008000" stroke-width=".21"/>
<circle cx="115.6" cy="133.7" r=".38" fill="#fff" stroke="#000" stroke-width=".21"/>
<path d="M115 139h1.4v1.4h-1.4z" fill="#008000" stroke="#008000" stroke-width=".21"/>
<circle cx="115.7" cy="139.7" r=".38" fill="#fff" stroke="#000" stroke-width=".21"/>
<circle cx="104.4" cy="122.8" r=".68" fill="#008000" stroke="#008000" stroke-width=".21"/>
<circle cx="104.4" cy="122.8" r=".38" fill="#fff" stroke="#000" stroke-width=".21"/>
<path d="M98.2 130.7h1.3v1.3h-1.3z" fill="#008000" stroke="#008000" stroke-width=".21"/>
<circle cx="98.9" cy="131.3" r=".38" fill="#fff" stroke="#000" stroke-width=".21"/>
<circle cx="187.6" cy="151.8" r=".68" fill="#008000" stroke="#008000" stroke-width=".21"/>
<circle cx="187.6" cy="151.8" r=".38" fill="#fff" stroke="#000" stroke-width=".21"/>
<circle cx="181.5" cy="151.8" r=".68" fill="#008000" stroke="#008000" stroke-width=".21"/>
<circle cx="181.5" cy="151.8" r=".38" fill="#fff" stroke="#000" stroke-width=".21"/>
<circle cx="169.7" cy="39.4" r=".68" fill="#008000" stroke="#008000" stroke-width=".21"/>
<circle cx="169.7" cy="39.4" r=".38" fill="#fff" stroke="#000" stroke-width=".21"/>
<circle cx="137.2" cy="52.9" r=".76" fill="#008000" stroke="#008000" stroke-width=".21"/>
<circle cx="137.2" cy="52.9" r=".47" fill="#fff" stroke="#000" stroke-width=".21"/>
<circle cx="112.4" cy="53.7" r=".76" fill="#008000" stroke="#008000" stroke-width=".21"/>
<circle cx="112.4" cy="53.7" r=".47" fill="#fff" stroke="#000" stroke-width=".21"/>
<circle cx="112.3" cy="76.2" r=".68" fill="#008000" stroke="#008000" stroke-width=".21"/>
<circle cx="112.3" cy="76.2" r=".38" fill="#fff" stroke="#000" stroke-width=".21"/>
<circle cx="124.7" cy="79.6" r=".68" fill="#008000" stroke="#008000" stroke-width=".21"/>
<circle cx="124.7" cy="79.6" r=".38" fill="#fff" stroke="#000" stroke-width=".21"/>
<circle cx="129.8" cy="79.7" r=".68" fill="#008000" stroke="#008000" stroke-width=".21"/>
<circle cx="129.8" cy="79.7" r=".38" fill="#fff" stroke="#000" stroke-width=".21"/>
<circle cx="136.5" cy="79.7" r=".68" fill="#008000" stroke="#008000" stroke-width=".21"/>
<circle cx="136.5" cy="79.7" r=".38" fill="#fff" stroke="#000" stroke-width=".21"/>
<circle cx="113.6" cy="100.4" r=".68" fill="#008000" stroke="#008000" stroke-width=".21"/>
<circle cx="113.6" cy="100.4" r=".38" fill="#fff" stroke="#000" stroke-width=".21"/>
<circle cx="116.6" cy="97.3" r=".68" fill="#008000" stroke="#008000" stroke-width=".21"/>
<circle cx="116.6" cy="97.3" r=".38" fill="#fff" stroke="#000" stroke-width=".21"/>
<circle cx="113.2" cy="95" r=".68" fill="#008000" stroke="#008000" stroke-width=".21"/>
<circle cx="113.2" cy="95" r=".38" fill="#fff" stroke="#000" stroke-width=".21"/>
<circle cx="144.4" cy="53.8" r=".76" fill="#008000" stroke="#008000" stroke-width=".21"/>
<circle cx="144.4" cy="53.8" r=".44" fill="#fff" stroke="#000" stroke-width=".21"/>
<circle cx="193.3" cy="149.3" r=".68" fill="#008000" stroke="#008000" stroke-width=".21"/>
<circle cx="193.3" cy="149.3" r=".38" fill="#fff" stroke="#000" stroke-width=".21"/>
<circle cx="201.7" cy="146.7" r=".68" fill="#008000" stroke="#008000" stroke-width=".21"/>
<circle cx="201.7" cy="146.7" r=".38" fill="#fff" stroke="#000" stroke-width=".21"/>
<circle cx="171.2" cy="134.6" r=".68" fill="#008000" stroke="#008000" stroke-width=".21"/>
<circle cx="171.2" cy="134.6" r=".38" fill="#fff" stroke="#000" stroke-width=".21"/>
<circle cx="171.3" cy="127.9" r=".68" fill="#008000" stroke="#008000" stroke-width=".21"/>
<circle cx="171.3" cy="127.9" r=".38" fill="#fff" stroke="#000" stroke-width=".21"/>
<circle cx="119.4" cy="88.2" r=".76" fill="#008000" stroke="#008000" stroke-width=".21"/>
<circle cx="119.4" cy="88.2" r=".47" fill="#fff" stroke="#000" stroke-width=".21"/>
<circle cx="111.5" cy="101" r=".68" fill="#008000" stroke="#008000" stroke-width=".21"/>
<circle cx="111.5" cy="101" r=".38" fill="#fff" stroke="#000" stroke-width=".21"/>
<circle cx="114.2" cy="117.4" r=".68" fill="#008000" stroke="#008000" stroke-width=".21"/>
<circle cx="114.2" cy="117.4" r=".38" fill="#fff" stroke="#000" stroke-width=".21"/>
<circle cx="117.2" cy="120.5" r=".68" fill="#008000" stroke="#008000" stroke-width=".21"/>
<circle cx="117.2" cy="120.5" r=".38" fill="#fff" stroke="#000" stroke-width=".21"/>
<circle cx="116.3" cy="127.8" r=".68" fill="#008000" stroke="#008000" stroke-width=".21"/>
<circle cx="116.3" cy="127.8" r=".38" fill="#fff" stroke="#000" stroke-width=".21"/>
<circle cx="176.6" cy="134.5" r=".68" fill="#008000" stroke="#008000" stroke-width=".21"/>
<circle cx="176.6" cy="134.5" r=".38" fill="#fff" stroke="#000" stroke-width=".21"/>
<circle cx="175.3" cy="109.7" r=".68" fill="#008000" stroke="#008000" stroke-width=".21"/>
<circle cx="175.3" cy="109.7" r=".38" fill="#fff" stroke="#000" stroke-width=".21"/>
<circle cx="178.8" cy="113.8" r=".76" fill="#008000" stroke="#008000" stroke-width=".21"/>
<circle cx="178.8" cy="113.8" r=".47" fill="#fff" stroke="#000" stroke-width=".21"/>
<circle cx="186.7" cy="127.5" r=".68" fill="#008000" stroke="#008000" stroke-width=".21"/>
<circle cx="186.7" cy="127.5" r=".38" fill="#fff" stroke="#000" stroke-width=".21"/>
<circle cx="182.8" cy="141.2" r=".68" fill="#008000" stroke="#008000" stroke-width=".21"/>
<circle cx="182.8" cy="141.2" r=".38" fill="#fff" stroke="#000" stroke-width=".21"/>
<circle cx="175.7" cy="164.7" r=".76" fill="#008000" stroke="#008000" stroke-width=".21"/>
<circle cx="175.7" cy="164.7" r=".47" fill="#fff" stroke="#000" stroke-width=".21"/>
<circle cx="123.3" cy="82.1" r=".68" fill="#008000" stroke="#008000" stroke-width=".21"/>
<circle cx="123.3" cy="82.1" r=".38" fill="#fff" stroke="#000" stroke-width=".21"/>
<circle cx="131.1" cy="111.4" r=".68" fill="#008000" stroke="#008000" stroke-width=".21"/>
<circle cx="131.1" cy="111.4" r=".38" fill="#fff" stroke="#000" stroke-width=".21"/>
<circle cx="139.6" cy="127.3" r=".68" fill="#008000" stroke="#008000" stroke-width=".21"/>
<circle cx="139.6" cy="127.3" r=".38" fill="#fff" stroke="#000" stroke-width=".21"/>
<circle cx="161.7" cy="124.1" r=".76" fill="#008000" stroke="#008000" stroke-width=".21"/>
<circle cx="161.7" cy="124.1" r=".47" fill="#fff" stroke="#000" stroke-width=".21"/>
<circle cx="161.4" cy="118" r=".76" fill="#008000" stroke="#008000" stroke-width=".21"/>
<circle cx="161.4" cy="118" r=".47" fill="#fff" stroke="#000" stroke-width=".21"/>
<circle cx="165.7" cy="113.8" r=".76" fill="#008000" stroke="#008000" stroke-width=".21"/>
<circle cx="165.7" cy="113.8" r=".47" fill="#fff" stroke="#000" stroke-width=".21"/>
<circle cx="131.9" cy="134.3" r=".68" fill="#008000" stroke="#008000" stroke-width=".21"/>
<circle cx="131.9" cy="134.3" r=".38" fill="#fff" stroke="#000" stroke-width=".21"/>
<circle cx="129.2" cy="115.3" r=".68" fill="#008000" stroke="#008000" stroke-width=".21"/>
<circle cx="129.2" cy="115.3" r=".38" fill="#fff" stroke="#000" stroke-width=".21"/>
<circle cx="126.4" cy="134.2" r=".68" fill="#008000" stroke="#008000" stroke-width=".21"/>
<circle cx="126.4" cy="134.2" r=".38" fill="#fff" stroke="#000" stroke-width=".21"/>
<circle cx="126.4" cy="127.7" r=".68" fill="#008000" stroke="#008000" stroke-width=".21"/>
<circle cx="126.4" cy="127.7" r=".38" fill="#fff" stroke="#000" stroke-width=".21"/>
<circle cx="137.4" cy="134.5" r=".68" fill="#008000" stroke="#008000" stroke-width=".21"/>
<circle cx="137.4" cy="134.5" r=".38" fill="#fff" stroke="#000" stroke-width=".21"/>
<circle cx="137.5" cy="128" r=".68" fill="#008000" stroke="#008000" stroke-width=".21"/>
<circle cx="137.5" cy="128" r=".38" fill="#fff" stroke="#000" stroke-width=".21"/>
<circle cx="135" cy="120.3" r=".68" fill="#008000" stroke="#008000" stroke-width=".21"/>
<circle cx="135" cy="120.3" r=".38" fill="#fff" stroke="#000" stroke-width=".21"/>
<circle cx="139.3" cy="116.1" r=".68" fill="#008000" stroke="#008000" stroke-width=".21"/>
<circle cx="139.3" cy="116.1" r=".38" fill="#fff" stroke="#000" stroke-width=".21"/>
<circle cx="137.2" cy="113.5" r=".68" fill="#008000" stroke="#008000" stroke-width=".21"/>
<circle cx="137.2" cy="113.5" r=".38" fill="#fff" stroke="#000" stroke-width=".21"/>
<circle cx="131" cy="88.3" r=".68" fill="#008000" stroke="#008000" stroke-width=".21"/>
<circle cx="131" cy="88.3" r=".38" fill="#fff" stroke="#000" stroke-width=".21"/>
<circle cx="129.8" cy="82.2" r=".68" fill="#008000" stroke="#008000" stroke-width=".21"/>
<circle cx="129.8" cy="82.2" r=".38" fill="#fff" stroke="#000" stroke-width=".21"/>
<circle cx="123.4" cy="39.5" r=".76" fill="#008000" stroke="#008000" stroke-width=".21"/>
<circle cx="123.4" cy="39.5" r=".47" fill="#fff" stroke="#000" stroke-width=".21"/>
<circle cx="129.7" cy="60.7" r=".68" fill="#008000" stroke="#008000" stroke-width=".21"/>
<circle cx="129.7" cy="60.7" r=".38" fill="#fff" stroke="#000" stroke-width=".21"/>
<circle cx="133.6" cy="62.8" r=".68" fill="#008000" stroke="#008000" stroke-width=".21"/>
<circle cx="133.6" cy="62.8" r=".38" fill="#fff" stroke="#000" stroke-width=".21"/>
<circle cx="133.6" cy="67.6" r=".68" fill="#008000" stroke="#008000" stroke-width=".21"/>
<circle cx="133.6" cy="67.6" r=".38" fill="#fff" stroke="#000" stroke-width=".21"/>
<circle cx="190.5" cy="101.4" r=".68" fill="#008000" stroke="#008000" stroke-width=".21"/>
<circle cx="190.5" cy="101.4" r=".38" fill="#fff" stroke="#000" stroke-width=".21"/>
<circle cx="146.7" cy="95.3" r=".68" fill="#008000" stroke="#008000" stroke-width=".21"/>
<circle cx="146.7" cy="95.3" r=".38" fill="#fff" stroke="#000" stroke-width=".21"/>
<circle cx="170.9" cy="61" r=".68" fill="#008000" stroke="#008000" stroke-width=".21"/>
<circle cx="170.9" cy="61" r=".38" fill="#fff" stroke="#000" stroke-width=".21"/>
<circle cx="171.5" cy="64.7" r=".68" fill="#008000" stroke="#008000" stroke-width=".21"/>
<circle cx="171.5" cy="64.7" r=".38" fill="#fff" stroke="#000" stroke-width=".21"/>
<circle cx="194.3" cy="64.7" r=".68" fill="#008000" stroke="#008000" stroke-width=".21"/>
<circle cx="194.3" cy="64.7" r=".38" fill="#fff" stroke="#000" stroke-width=".21"/>
<circle cx="199.2" cy="69.6" r=".68" fill="#008000" stroke="#008000" stroke-width=".21"/>
<circle cx="199.2" cy="69.6" r=".38" fill="#fff" stroke="#000" stroke-width=".21"/>
<circle cx="192.8" cy="88.4" r=".68" fill="#008000" stroke="#008000" stroke-width=".21"/>
<circle cx="192.8" cy="88.4" r=".38" fill="#fff" stroke="#000" stroke-width=".21"/>
<circle cx="165.1" cy="85.3" r=".68" fill="#008000" stroke="#008000" stroke-width=".21"/>
<circle cx="165.1" cy="85.3" r=".38" fill="#fff" stroke="#000" stroke-width=".21"/>
<circle cx="161.3" cy="85.5" r=".68" fill="#008000" stroke="#008000" stroke-width=".21"/>
<circle cx="161.3" cy="85.5" r=".38" fill="#fff" stroke="#000" stroke-width=".21"/>
<circle cx="156.8" cy="80.9" r=".68" fill="#008000" stroke="#008000" stroke-width=".21"/>
<circle cx="156.8" cy="80.9" r=".38" fill="#fff" stroke="#000" stroke-width=".21"/>
<circle cx="149.5" cy="80.9" r=".68" fill="#008000" stroke="#008000" stroke-width=".21"/>
<circle cx="149.5" cy="80.9" r=".38" fill="#fff" stroke="#000" stroke-width=".21"/>
<circle cx="136.5" cy="83.8" r=".68" fill="#008000" stroke="#008000" stroke-width=".21"/>
<circle cx="136.5" cy="83.8" r=".38" fill="#fff" stroke="#000" stroke-width=".21"/>
<circle cx="133.6" cy="83.9" r=".68" fill="#008000" stroke="#008000" stroke-width=".21"/>
<circle cx="133.6" cy="83.9" r=".38" fill="#fff" stroke="#000" stroke-width=".21"/>
<circle cx="133.6" cy="77.6" r=".68" fill="#008000" stroke="#008000" stroke-width=".21"/>
<circle cx="133.6" cy="77.6" r=".38" fill="#fff" stroke="#000" stroke-width=".21"/>
<circle cx="129.8" cy="77.7" r=".68" fill="#008000" stroke="#008000" stroke-width=".21"/>
<circle cx="129.8" cy="77.7" r=".38" fill="#fff" stroke="#000" stroke-width=".21"/>
<circle cx="124.6" cy="77.7" r=".68" fill="#008000" stroke="#008000" stroke-width=".21"/>
<circle cx="124.6" cy="77.7" r=".38" fill="#fff" stroke="#000" stroke-width=".21"/>
<circle cx="117.8" cy="71.7" r=".68" fill="#008000" stroke="#008000" stroke-width=".21"/>
<circle cx="117.8" cy="71.7" r=".38" fill="#fff" stroke="#000" stroke-width=".21"/>
<circle cx="154.7" cy="134.3" r=".68" fill="#008000" stroke="#008000" stroke-width=".21"/>
<circle cx="154.7" cy="134.3" r=".38" fill="#fff" stroke="#000" stroke-width=".21"/>
<circle cx="169.5" cy="107.5" r=".68" fill="#008000" stroke="#008000" stroke-width=".21"/>
<circle cx="169.5" cy="107.5" r=".38" fill="#fff" stroke="#000" stroke-width=".21"/>
<circle cx="106" cy="120.7" r=".68" fill="#008000" stroke="#008000" stroke-width=".21"/>
<circle cx="106" cy="120.7" r=".38" fill="#fff" stroke="#000" stroke-width=".21"/>
<circle cx="130.3" cy="125.9" r=".68" fill="#008000" stroke="#008000" stroke-width=".21"/>
<circle cx="130.3" cy="125.9" r=".38" fill="#fff" stroke="#000" stroke-width=".21"/>
<circle cx="133.8" cy="126" r=".68" fill="#008000" stroke="#008000" stroke-width=".21"/>
<circle cx="133.8" cy="126" r=".38" fill="#fff" stroke="#000" stroke-width=".21"/>
<circle cx="144.6" cy="126" r=".68" fill="#008000" stroke="#008000" stroke-width=".21"/>
<circle cx="144.6" cy="126" r=".38" fill="#fff" stroke="#000" stroke-width=".21"/>
<circle cx="147.5" cy="125.9" r=".68" fill="#008000" stroke="#008000" stroke-width=".21"/>
<circle cx="147.5" cy="125.9" r=".38" fill="#fff" stroke="#000" stroke-width=".21"/>
<circle cx="165.8" cy="134.4" r=".68" fill="#008000" stroke="#008000" stroke-width=".21"/>
<circle cx="165.8" cy="134.4" r=".38" fill="#fff" stroke="#000" stroke-width=".21"/>
<circle cx="172.3" cy="108.6" r=".68" fill="#008000" stroke="#008000" stroke-width=".21"/>
<circle cx="172.3" cy="108.6" r=".38" fill="#fff" stroke="#000" stroke-width=".21"/>
<circle cx="154" cy="113.6" r=".76" fill="#008000" stroke="#008000" stroke-width=".21"/>
<circle cx="154" cy="113.6" r=".44" fill="#fff" stroke="#000" stroke-width=".21"/>
<circle cx="147.5" cy="113.6" r=".68" fill="#008000" stroke="#008000" stroke-width=".21"/>
<circle cx="147.5" cy="113.6" r=".38" fill="#fff" stroke="#000" stroke-width=".21"/>
<circle cx="144.7" cy="113.7" r=".68" fill="#008000" stroke="#008000" stroke-width=".21"/>
<circle cx="144.7" cy="113.7" r=".38" fill="#fff" stroke="#000" stroke-width=".21"/>
<circle cx="133.5" cy="117.7" r=".68" fill="#008000" stroke="#008000" stroke-width=".21"/>
<circle cx="133.5" cy="117.7" r=".38" fill="#fff" stroke="#000" stroke-width=".21"/>
<circle cx="128.5" cy="117.7" r=".68" fill="#008000" stroke="#008000" stroke-width=".21"/>
<circle cx="128.5" cy="117.7" r=".38" fill="#fff" stroke="#000" stroke-width=".21"/>
<circle cx="115.5" cy="105.4" r=".76" fill="#008000" stroke="#008000" stroke-width=".21"/>
<circle cx="115.5" cy="105.4" r=".44" fill="#fff" stroke="#000" stroke-width=".21"/>
<circle cx="119.1" cy="100.4" r=".68" fill="#008000" stroke="#008000" stroke-width=".21"/>
<circle cx="119.1" cy="100.4" r=".38" fill="#fff" stroke="#000" stroke-width=".21"/>
<circle cx="126.8" cy="67.7" r=".68" fill="#008000" stroke="#008000" stroke-width=".21"/>
<circle cx="126.8" cy="67.7" r=".38" fill="#fff" stroke="#000" stroke-width=".21"/>
<circle cx="124.6" cy="70.6" r=".68" fill="#008000" stroke="#008000" stroke-width=".21"/>
<circle cx="124.6" cy="70.6" r=".38" fill="#fff" stroke="#000" stroke-width=".21"/>
<circle cx="116" cy="69" r=".68" fill="#008000" stroke="#008000" stroke-width=".21"/>
<circle cx="116" cy="69" r=".38" fill="#fff" stroke="#000" stroke-width=".21"/>
<circle cx="160.2" cy="134.5" r=".68" fill="#008000" stroke="#008000" stroke-width=".21"/>
<circle cx="160.2" cy="134.5" r=".38" fill="#fff" stroke="#000" stroke-width=".21"/>
<circle cx="160.2" cy="128" r=".68" fill="#008000" stroke="#008000" stroke-width=".21"/>
<circle cx="160.2" cy="128" r=".38" fill="#fff" stroke="#000" stroke-width=".21"/>
<circle cx="110.1" cy="117.8" r=".68" fill="#008000" stroke="#008000" stroke-width=".21"/>
<circle cx="110.1" cy="117.8" r=".38" fill="#fff" stroke="#000" stroke-width=".21"/>
<circle cx="130.2" cy="121.9" r=".68" fill="#008000" stroke="#008000" stroke-width=".21"/>
<circle cx="130.2" cy="121.9" r=".38" fill="#fff" stroke="#000" stroke-width=".21"/>
<circle cx="134" cy="122" r=".68" fill="#008000" stroke="#008000" stroke-width=".21"/>
<circle cx="134" cy="122" r=".38" fill="#fff" stroke="#000" stroke-width=".21"/>
<circle cx="144.7" cy="121.9" r=".68" fill="#008000" stroke="#008000" stroke-width=".21"/>
<circle cx="144.7" cy="121.9" r=".38" fill="#fff" stroke="#000" stroke-width=".21"/>
<circle cx="147.5" cy="122" r=".68" fill="#008000" stroke="#008000" stroke-width=".21"/>
<circle cx="147.5" cy="122" r=".38" fill="#fff" stroke="#000" stroke-width=".21"/>
<circle cx="151.2" cy="124.2" r=".76" fill="#008000" stroke="#008000" stroke-width=".21"/>
<circle cx="151.2" cy="124.2" r=".44" fill="#fff" stroke="#000" stroke-width=".21"/>
<circle cx="149" cy="134.3" r=".68" fill="#008000" stroke="#008000" stroke-width=".21"/>
<circle cx="149" cy="134.3" r=".38" fill="#fff" stroke="#000" stroke-width=".21"/>
<circle cx="149" cy="128" r=".68" fill="#008000" stroke="#008000" stroke-width=".21"/>
<circle cx="149" cy="128" r=".38" fill="#fff" stroke="#000" stroke-width=".21"/>
<circle cx="108.3" cy="119.3" r=".68" fill="#008000" stroke="#008000" stroke-width=".21"/>
<circle cx="108.3" cy="119.3" r=".38" fill="#fff" stroke="#000" stroke-width=".21"/>
<circle cx="130.2" cy="124.2" r=".76" fill="#008000" stroke="#008000" stroke-width=".21"/>
<circle cx="130.2" cy="124.2" r=".44" fill="#fff" stroke="#000" stroke-width=".21"/>
<circle cx="134.1" cy="124.1" r=".68" fill="#008000" stroke="#008000" stroke-width=".21"/>
<circle cx="134.1" cy="124.1" r=".38" fill="#fff" stroke="#000" stroke-width=".21"/>
<circle cx="144.5" cy="124" r=".68" fill="#008000" stroke="#008000" stroke-width=".21"/>
<circle cx="144.5" cy="124" r=".38" fill="#fff" stroke="#000" stroke-width=".21"/>
<circle cx="192" cy="103.5" r=".68" fill="#008000" stroke="#008000" stroke-width=".21"/>
<circle cx="192" cy="103.5" r=".38" fill="#fff" stroke="#000" stroke-width=".21"/>
<circle cx="159.9" cy="65.6" r=".68" fill="#008000" stroke="#008000" stroke-width=".21"/>
<circle cx="159.9" cy="65.6" r=".38" fill="#fff" stroke="#000" stroke-width=".21"/>
<circle cx="165.1" cy="88.2" r=".68" fill="#008000" stroke="#008000" stroke-width=".21"/>
<circle cx="165.1" cy="88.2" r=".38" fill="#fff" stroke="#000" stroke-width=".21"/>
<circle cx="169.3" cy="94.9" r=".76" fill="#008000" stroke="#008000" stroke-width=".21"/>
<circle cx="169.3" cy="94.9" r=".47" fill="#fff" stroke="#000" stroke-width=".21"/>
<circle cx="136.8" cy="107.9" r=".68" fill="#008000" stroke="#008000" stroke-width=".21"/>
<circle cx="136.8" cy="107.9" r=".38" fill="#fff" stroke="#000" stroke-width=".21"/>
<circle cx="120.8" cy="112.9" r=".68" fill="#008000" stroke="#008000" stroke-width=".21"/>
<circle cx="120.8" cy="112.9" r=".38" fill="#fff" stroke="#000" stroke-width=".21"/>
<circle cx="182.4" cy="134.3" r=".68" fill="#008000" stroke="#008000" stroke-width=".21"/>
<circle cx="182.4" cy="134.3" r=".38" fill="#fff" stroke="#000" stroke-width=".21"/>
<circle cx="182.3" cy="127.7" r=".68" fill="#008000" stroke="#008000" stroke-width=".21"/>
<circle cx="182.3" cy="127.7" r=".38" fill="#fff" stroke="#000" stroke-width=".21"/>
<circle cx="102.6" cy="91.5" r=".68" fill="#008000" stroke="#008000" stroke-width=".21"/>
<circle cx="102.6" cy="91.5" r=".38" fill="#fff" stroke="#000" stroke-width=".21"/>
<circle cx="111.5" cy="131.7" r=".68" fill="#008000" stroke="#008000" stroke-width=".21"/>
<circle cx="111.5" cy="131.7" r=".38" fill="#fff" stroke="#000" stroke-width=".21"/>
<circle cx="143.3" cy="134.5" r=".68" fill="#008000" stroke="#008000" stroke-width=".21"/>
<circle cx="143.3" cy="134.5" r=".38" fill="#fff" stroke="#000" stroke-width=".21"/>
<circle cx="143.2" cy="127.4" r=".76" fill="#008000" stroke="#008000" stroke-width=".21"/>
<circle cx="143.2" cy="127.4" r=".44" fill="#fff" stroke="#000" stroke-width=".21"/>
<circle cx="118" cy="114.2" r=".68" fill="#008000" stroke="#008000" stroke-width=".21"/>
<circle cx="118" cy="114.2" r=".38" fill="#fff" stroke="#000" stroke-width=".21"/>
<circle cx="138.9" cy="107.9" r=".68" fill="#008000" stroke="#008000" stroke-width=".21"/>
<circle cx="138.9" cy="107.9" r=".38" fill="#fff" stroke="#000" stroke-width=".21"/>
<circle cx="129.7" cy="108.2" r=".68" fill="#008000" stroke="#008000" stroke-width=".21"/>
<circle cx="129.7" cy="108.2" r=".38" fill="#fff" stroke="#000" stroke-width=".21"/>
<circle cx="100.9" cy="117.1" r=".68" fill="#008000" stroke="#008000" stroke-width=".21"/>
<circle cx="100.9" cy="117.1" r=".38" fill="#fff" stroke="#000" stroke-width=".21"/>
<circle cx="118" cy="110.8" r=".44" fill="#008000" stroke="#008000" stroke-width=".21"/>
<circle cx="118" cy="110.8" r=".15" fill="#fff" stroke="#000" stroke-width=".21"/>
<circle cx="103.4" cy="114.6" r=".68" fill="#008000" stroke="#008000" stroke-width=".21"/>
<circle cx="103.4" cy="114.6" r=".38" fill="#fff" stroke="#000" stroke-width=".21"/>
<circle cx="103" cy="125.5" r=".68" fill="#008000" stroke="#008000" stroke-width=".21"/>
<circle cx="103" cy="125.5" r=".38" fill="#fff" stroke="#000" stroke-width=".21"/>
<path d="M98.1 124.9h1.3v1.4h-1.3z" fill="#008000" stroke="#008000" stroke-width=".21"/>
<circle cx="98.8" cy="125.6" r=".38" fill="#fff" stroke="#000" stroke-width=".21"/>
<circle cx="180" cy="56.2" r=".68" fill="#008000" stroke="#008000" stroke-width=".21"/>
<circle cx="180" cy="56.2" r=".38" fill="#fff" stroke="#000" stroke-width=".21"/>
<circle cx="178.5" cy="53.4" r=".68" fill="#008000" stroke="#008000" stroke-width=".21"/>
<circle cx="178.5" cy="53.4" r=".38" fill="#fff" stroke="#000" stroke-width=".21"/>
<circle cx="159.9" cy="61.4" r=".76" fill="#008000" stroke="#008000" stroke-width=".21"/>
<circle cx="159.9" cy="61.4" r=".47" fill="#fff" stroke="#000" stroke-width=".21"/>
<circle cx="158.1" cy="70.3" r=".76" fill="#008000" stroke="#008000" stroke-width=".21"/>
<circle cx="158.1" cy="70.3" r=".47" fill="#fff" stroke="#000" stroke-width=".21"/>
<circle cx="160.8" cy="106.4" r=".76" fill="#008000" stroke="#008000" stroke-width=".21"/>
<circle cx="160.8" cy="106.4" r=".47" fill="#fff" stroke="#000" stroke-width=".21"/>
<circle cx="157.6" cy="43.1" r=".76" fill="#008000" stroke="#008000" stroke-width=".21"/>
<circle cx="157.6" cy="43.1" r=".44" fill="#fff" stroke="#000" stroke-width=".21"/>
<circle cx="177.5" cy="109.3" r=".76" fill="#008000" stroke="#008000" stroke-width=".21"/>
<circle cx="177.5" cy="109.3" r=".44" fill="#fff" stroke="#000" stroke-width=".21"/>
<circle cx="153.4" cy="83" r=".68" fill="#008000" stroke="#008000" stroke-width=".21"/>
<circle cx="153.4" cy="83" r=".38" fill="#fff" stroke="#000" stroke-width=".21"/>
<circle cx="167.5" cy="85.1" r=".68" fill="#008000" stroke="#008000" stroke-width=".21"/>
<circle cx="167.5" cy="85.1" r=".38" fill="#fff" stroke="#000" stroke-width=".21"/>
<circle cx="196.3" cy="88.4" r=".68" fill="#008000" stroke="#008000" stroke-width=".21"/>
<circle cx="196.3" cy="88.4" r=".38" fill="#fff" stroke="#000" stroke-width=".21"/>
<circle cx="207" cy="96.4" r=".68" fill="#008000" stroke="#008000" stroke-width=".21"/>
<circle cx="207" cy="96.4" r=".38" fill="#fff" stroke="#000" stroke-width=".21"/>
<circle cx="186.6" cy="149.9" r=".68" fill="#008000" stroke="#008000" stroke-width=".21"/>
<circle cx="186.6" cy="149.9" r=".38" fill="#fff" stroke="#000" stroke-width=".21"/>
<circle cx="130.9" cy="93.9" r=".68" fill="#008000" stroke="#008000" stroke-width=".21"/>
<circle cx="130.9" cy="93.9" r=".38" fill="#fff" stroke="#000" stroke-width=".21"/>
<circle cx="153.1" cy="93.7" r=".68" fill="#008000" stroke="#008000" stroke-width=".21"/>
<circle cx="153.1" cy="93.7" r=".38" fill="#fff" stroke="#000" stroke-width=".21"/>
<circle cx="153.1" cy="88.5" r=".68" fill="#008000" stroke="#008000" stroke-width=".21"/>
<circle cx="153.1" cy="88.5" r=".38" fill="#fff" stroke="#000" stroke-width=".21"/>
<circle cx="142.5" cy="82.4" r=".68" fill="#008000" stroke="#008000" stroke-width=".21"/>
<circle cx="142.5" cy="82.4" r=".38" fill="#fff" stroke="#000" stroke-width=".21"/>
<circle cx="159.4" cy="58.9" r=".68" fill="#008000" stroke="#008000" stroke-width=".21"/>
<circle cx="159.4" cy="58.9" r=".38" fill="#fff" stroke="#000" stroke-width=".21"/>
<circle cx="212.2" cy="129.4" r=".68" fill="#008000" stroke="#008000" stroke-width=".21"/>
<circle cx="212.2" cy="129.4" r=".38" fill="#fff" stroke="#000" stroke-width=".21"/>
<circle cx="185.4" cy="146.9" r=".68" fill="#008000" stroke="#008000" stroke-width=".21"/>
<circle cx="185.4" cy="146.9" r=".38" fill="#fff" stroke="#000" stroke-width=".21"/>
<circle cx="156.6" cy="76.8" r=".68" fill="#008000" stroke="#008000" stroke-width=".21"/>
<circle cx="156.6" cy="76.8" r=".38" fill="#fff" stroke="#000" stroke-width=".21"/>
<circle cx="100.1" cy="142.7" r=".68" fill="#008000" stroke="#008000" stroke-width=".21"/>
<circle cx="100.1" cy="142.7" r=".38" fill="#fff" stroke="#000" stroke-width=".21"/>
<circle cx="110.6" cy="136.5" r=".68" fill="#008000" stroke="#008000" stroke-width=".21"/>
<circle cx="110.6" cy="136.5" r=".38" fill="#fff" stroke="#000" stroke-width=".21"/>
<circle cx="149.4" cy="76" r=".68" fill="#008000" stroke="#008000" stroke-width=".21"/>
<circle cx="149.4" cy="76" r=".38" fill="#fff" stroke="#000" stroke-width=".21"/>
<circle cx="143.3" cy="73.9" r=".68" fill="#008000" stroke="#008000" stroke-width=".21"/>
<circle cx="143.3" cy="73.9" r=".38" fill="#fff" stroke="#000" stroke-width=".21"/>
<circle cx="143.4" cy="65.6" r=".68" fill="#008000" stroke="#008000" stroke-width=".21"/>
<circle cx="143.4" cy="65.6" r=".38" fill="#fff" stroke="#000" stroke-width=".21"/>
<circle cx="137.6" cy="65.6" r=".68" fill="#008000" stroke="#008000" stroke-width=".21"/>
<circle cx="137.6" cy="65.6" r=".38" fill="#fff" stroke="#000" stroke-width=".21"/>
<circle cx="129.7" cy="68.2" r=".68" fill="#008000" stroke="#008000" stroke-width=".21"/>
<circle cx="129.7" cy="68.2" r=".38" fill="#fff" stroke="#000" stroke-width=".21"/>
<circle cx="124.6" cy="74.9" r=".68" fill="#008000" stroke="#008000" stroke-width=".21"/>
<circle cx="124.6" cy="74.9" r=".38" fill="#fff" stroke="#000" stroke-width=".21"/>
<circle cx="182.6" cy="70.4" r=".68" fill="#008000" stroke="#008000" stroke-width=".21"/>
<circle cx="182.6" cy="70.4" r=".38" fill="#fff" stroke="#000" stroke-width=".21"/>
<circle cx="182.5" cy="76.6" r=".68" fill="#008000" stroke="#008000" stroke-width=".21"/>
<circle cx="182.5" cy="76.6" r=".38" fill="#fff" stroke="#000" stroke-width=".21"/>
<circle cx="182.5" cy="79.4" r=".68" fill="#008000" stroke="#008000" stroke-width=".21"/>
<circle cx="182.5" cy="79.4" r=".38" fill="#fff" stroke="#000" stroke-width=".21"/>
<circle cx="194.1" cy="136.4" r=".68" fill="#008000" stroke="#008000" stroke-width=".21"/>
<circle cx="194.1" cy="136.4" r=".38" fill="#fff" stroke="#000" stroke-width=".21"/>
<circle cx="195" cy="114.4" r=".68" fill="#008000" stroke="#008000" stroke-width=".21"/>
<circle cx="195" cy="114.4" r=".38" fill="#fff" stroke="#000" stroke-width=".21"/>
<circle cx="175.1" cy="62.7" r=".68" fill="#008000" stroke="#008000" stroke-width=".21"/>
<circle cx="175.1" cy="62.7" r=".38" fill="#fff" stroke="#000" stroke-width=".21"/>
<circle cx="179.5" cy="62.5" r=".68" fill="#008000" stroke="#008000" stroke-width=".21"/>
<circle cx="179.5" cy="62.5" r=".38" fill="#fff" stroke="#000" stroke-width=".21"/>
<circle cx="179.6" cy="70.3" r=".68" fill="#008000" stroke="#008000" stroke-width=".21"/>
<circle cx="179.6" cy="70.3" r=".38" fill="#fff" stroke="#000" stroke-width=".21"/>
<circle cx="179.6" cy="76.6" r=".68" fill="#008000" stroke="#008000" stroke-width=".21"/>
<circle cx="179.6" cy="76.6" r=".38" fill="#fff" stroke="#000" stroke-width=".21"/>
<circle cx="179.6" cy="79.4" r=".68" fill="#008000" stroke="#008000" stroke-width=".21"/>
<circle cx="179.6" cy="79.4" r=".38" fill="#fff" stroke="#000" stroke-width=".21"/>
<circle cx="179.5" cy="93.8" r=".76" fill="#008000" stroke="#008000" stroke-width=".21"/>
<circle cx="179.5" cy="93.8" r=".44" fill="#fff" stroke="#000" stroke-width=".21"/>
<circle cx="189.3" cy="93.9" r=".68" fill="#008000" stroke="#008000" stroke-width=".21"/>
<circle cx="189.3" cy="93.9" r=".38" fill="#fff" stroke="#000" stroke-width=".21"/>
<circle cx="187.7" cy="70.2" r=".68" fill="#008000" stroke="#008000" stroke-width=".21"/>
<circle cx="187.7" cy="70.2" r=".38" fill="#fff" stroke="#000" stroke-width=".21"/>
<circle cx="187.7" cy="76.7" r=".68" fill="#008000" stroke="#008000" stroke-width=".21"/>
<circle cx="187.7" cy="76.7" r=".38" fill="#fff" stroke="#000" stroke-width=".21"/>
<circle cx="187.7" cy="79.4" r=".68" fill="#008000" stroke="#008000" stroke-width=".21"/>
<circle cx="187.7" cy="79.4" r=".38" fill="#fff" stroke="#000" stroke-width=".21"/>
<circle cx="192.3" cy="70.2" r=".68" fill="#008000" stroke="#008000" stroke-width=".21"/>
<circle cx="192.3" cy="70.2" r=".38" fill="#fff" stroke="#000" stroke-width=".21"/>
<circle cx="192.2" cy="76.6" r=".68" fill="#008000" stroke="#008000" stroke-width=".21"/>
<circle cx="192.2" cy="76.6" r=".38" fill="#fff" stroke="#000" stroke-width=".21"/>
<circle cx="192.2" cy="79.4" r=".68" fill="#008000" stroke="#008000" stroke-width=".21"/>
<circle cx="192.2" cy="79.4" r=".38" fill="#fff" stroke="#000" stroke-width=".21"/>
<circle cx="167.5" cy="74.4" r=".68" fill="#008000" stroke="#008000" stroke-width=".21"/>
<circle cx="167.5" cy="74.4" r=".38" fill="#fff" stroke="#000" stroke-width=".21"/>
<circle cx="159.7" cy="75.1" r=".68" fill="#008000" stroke="#008000" stroke-width=".21"/>
<circle cx="159.7" cy="75.1" r=".38" fill="#fff" stroke="#000" stroke-width=".21"/>
<circle cx="130.1" cy="146.5" r=".68" fill="#008000" stroke="#008000" stroke-width=".21"/>
<circle cx="130.1" cy="146.5" r=".38" fill="#fff" stroke="#000" stroke-width=".21"/>
<circle cx="147.9" cy="105.1" r=".68" fill="#008000" stroke="#008000" stroke-width=".21"/>
<circle cx="147.9" cy="105.1" r=".38" fill="#fff" stroke="#000" stroke-width=".21"/>
<circle cx="168.1" cy="104.5" r=".76" fill="#008000" stroke="#008000" stroke-width=".21"/>
<circle cx="168.1" cy="104.5" r=".44" fill="#fff" stroke="#000" stroke-width=".21"/>
<circle cx="187.6" cy="104.2" r=".68" fill="#008000" stroke="#008000" stroke-width=".21"/>
<circle cx="187.6" cy="104.2" r=".38" fill="#fff" stroke="#000" stroke-width=".21"/>
<circle cx="133" cy="88.5" r=".68" fill="#008000" stroke="#008000" stroke-width=".21"/>
<circle cx="133" cy="88.5" r=".38" fill="#fff" stroke="#000" stroke-width=".21"/>
<circle cx="143.8" cy="110.7" r=".68" fill="#008000" stroke="#008000" stroke-width=".21"/>
<circle cx="143.8" cy="110.7" r=".38" fill="#fff" stroke="#000" stroke-width=".21"/>
<circle cx="147.3" cy="109" r=".68" fill="#008000" stroke="#008000" stroke-width=".21"/>
<circle cx="147.3" cy="109" r=".38" fill="#fff" stroke="#000" stroke-width=".21"/>
<circle cx="188.8" cy="144.5" r=".68" fill="#008000" stroke="#008000" stroke-width=".21"/>
<circle cx="188.8" cy="144.5" r=".38" fill="#fff" stroke="#000" stroke-width=".21"/>
<circle cx="192" cy="121.6" r=".68" fill="#008000" stroke="#008000" stroke-width=".21"/>
<circle cx="192" cy="121.6" r=".38" fill="#fff" stroke="#000" stroke-width=".21"/>
<circle cx="127.2" cy="145.4" r=".68" fill="#008000" stroke="#008000" stroke-width=".21"/>
<circle cx="127.2" cy="145.4" r=".38" fill="#fff" stroke="#000" stroke-width=".21"/>
<circle cx="150.5" cy="103.6" r=".68" fill="#008000" stroke="#008000" stroke-width=".21"/>
<circle cx="150.5" cy="103.6" r=".38" fill="#fff" stroke="#000" stroke-width=".21"/>
<circle cx="164.9" cy="102.8" r=".76" fill="#008000" stroke="#008000" stroke-width=".21"/>
<circle cx="164.9" cy="102.8" r=".44" fill="#fff" stroke="#000" stroke-width=".21"/>
<circle cx="138" cy="88.4" r=".68" fill="#008000" stroke="#008000" stroke-width=".21"/>
<circle cx="138" cy="88.4" r=".38" fill="#fff" stroke="#000" stroke-width=".21"/>
<circle cx="153.8" cy="97.9" r=".68" fill="#008000" stroke="#008000" stroke-width=".21"/>
<circle cx="153.8" cy="97.9" r=".38" fill="#fff" stroke="#000" stroke-width=".21"/>
<circle cx="161.2" cy="95.6" r=".76" fill="#008000" stroke="#008000" stroke-width=".21"/>
<circle cx="161.2" cy="95.6" r=".47" fill="#fff" stroke="#000" stroke-width=".21"/>
<circle cx="188.9" cy="102.5" r=".68" fill="#008000" stroke="#008000" stroke-width=".21"/>
<circle cx="188.9" cy="102.5" r=".38" fill="#fff" stroke="#000" stroke-width=".21"/>
<circle cx="168.3" cy="102.4" r=".76" fill="#008000" stroke="#008000" stroke-width=".21"/>
<circle cx="168.3" cy="102.4" r=".44" fill="#fff" stroke="#000" stroke-width=".21"/>
<circle cx="155.3" cy="88.2" r=".68" fill="#008000" stroke="#008000" stroke-width=".21"/>
<circle cx="155.3" cy="88.2" r=".38" fill="#fff" stroke="#000" stroke-width=".21"/>
<circle cx="207.8" cy="128" r=".68" fill="#008000" stroke="#008000" stroke-width=".21"/>
<circle cx="207.8" cy="128" r=".38" fill="#fff" stroke="#000" stroke-width=".21"/>
<circle cx="202.1" cy="155.3" r=".68" fill="#008000" stroke="#008000" stroke-width=".21"/>
<circle cx="202.1" cy="155.3" r=".38" fill="#fff" stroke="#000" stroke-width=".21"/>
<circle cx="196.1" cy="155.2" r=".68" fill="#008000" stroke="#008000" stroke-width=".21"/>
<circle cx="196.1" cy="155.2" r=".38" fill="#fff" stroke="#000" stroke-width=".21"/>
<circle cx="142.9" cy="169.5" r=".68" fill="#008000" stroke="#008000" stroke-width=".21"/>
<circle cx="142.9" cy="169.5" r=".38" fill="#fff" stroke="#000" stroke-width=".21"/>
<circle cx="109.3" cy="168.7" r=".68" fill="#008000" stroke="#008000" stroke-width=".21"/>
<circle cx="109.3" cy="168.7" r=".38" fill="#fff" stroke="#000" stroke-width=".21"/>
<circle cx="104.4" cy="112.6" r=".68" fill="#008000" stroke="#008000" stroke-width=".21"/>
<circle cx="104.4" cy="112.6" r=".38" fill="#fff" stroke="#000" stroke-width=".21"/>
<circle cx="117.9" cy="108.6" r=".68" fill="#008000" stroke="#008000" stroke-width=".21"/>
<circle cx="117.9" cy="108.6" r=".38" fill="#fff" stroke="#000" stroke-width=".21"/>
<circle cx="120.4" cy="106.5" r=".68" fill="#008000" stroke="#008000" stroke-width=".21"/>
<circle cx="120.4" cy="106.5" r=".38" fill="#fff" stroke="#000" stroke-width=".21"/>
<circle cx="131.6" cy="100.3" r=".68" fill="#008000" stroke="#008000" stroke-width=".21"/>
<circle cx="131.6" cy="100.3" r=".38" fill="#fff" stroke="#000" stroke-width=".21"/>
<circle cx="141.4" cy="100.8" r=".76" fill="#008000" stroke="#008000" stroke-width=".21"/>
<circle cx="141.4" cy="100.8" r=".47" fill="#fff" stroke="#000" stroke-width=".21"/>
<circle cx="135.2" cy="88.2" r=".68" fill="#008000" stroke="#008000" stroke-width=".21"/>
<circle cx="135.2" cy="88.2" r=".38" fill="#fff" stroke="#000" stroke-width=".21"/>
<circle cx="132.7" cy="53.6" r=".76" fill="#008000" stroke="#008000" stroke-width=".21"/>
<circle cx="132.7" cy="53.6" r=".47" fill="#fff" stroke="#000" stroke-width=".21"/>
<circle cx="137.6" cy="63.2" r=".68" fill="#008000" stroke="#008000" stroke-width=".21"/>
<circle cx="137.6" cy="63.2" r=".38" fill="#fff" stroke="#000" stroke-width=".21"/>
<circle cx="142.6" cy="63.3" r=".68" fill="#008000" stroke="#008000" stroke-width=".21"/>
<circle cx="142.6" cy="63.3" r=".38" fill="#fff" stroke="#000" stroke-width=".21"/>
<circle cx="142.4" cy="55.1" r=".68" fill="#008000" stroke="#008000" stroke-width=".21"/>
<circle cx="142.4" cy="55.1" r=".38" fill="#fff" stroke="#000" stroke-width=".21"/>
<circle cx="107" cy="141.2" r=".68" fill="#008000" stroke="#008000" stroke-width=".21"/>
<circle cx="107" cy="141.2" r=".38" fill="#fff" stroke="#000" stroke-width=".21"/>
<circle cx="104.2" cy="138.1" r=".68" fill="#008000" stroke="#008000" stroke-width=".21"/>
<circle cx="104.2" cy="138.1" r=".38" fill="#fff" stroke="#000" stroke-width=".21"/>
<circle cx="184.8" cy="101.7" r=".68" fill="#008000" stroke="#008000" stroke-width=".21"/>
<circle cx="184.8" cy="101.7" r=".38" fill="#fff" stroke="#000" stroke-width=".21"/>
<circle cx="118.2" cy="95.8" r=".68" fill="#008000" stroke="#008000" stroke-width=".21"/>
<circle cx="118.2" cy="95.8" r=".38" fill="#fff" stroke="#000" stroke-width=".21"/>
<circle cx="121.8" cy="87.8" r=".76" fill="#008000" stroke="#008000" stroke-width=".21"/>
<circle cx="121.8" cy="87.8" r=".44" fill="#fff" stroke="#000" stroke-width=".21"/>
<circle cx="170.8" cy="69.8" r=".68" fill="#008000" stroke="#008000" stroke-width=".21"/>
<circle cx="170.8" cy="69.8" r=".38" fill="#fff" stroke="#000" stroke-width=".21"/>
<circle cx="171.3" cy="76.5" r=".68" fill="#008000" stroke="#008000" stroke-width=".21"/>
<circle cx="171.3" cy="76.5" r=".38" fill="#fff" stroke="#000" stroke-width=".21"/>
<circle cx="171.3" cy="79.4" r=".68" fill="#008000" stroke="#008000" stroke-width=".21"/>
<circle cx="171.3" cy="79.4" r=".38" fill="#fff" stroke="#000" stroke-width=".21"/>
<circle cx="193.5" cy="101.1" r=".68" fill="#008000" stroke="#008000" stroke-width=".21"/>
<circle cx="193.5" cy="101.1" r=".38" fill="#fff" stroke="#000" stroke-width=".21"/>
<circle cx="171.2" cy="95.8" r=".76" fill="#008000" stroke="#008000" stroke-width=".21"/>
<circle cx="171.2" cy="95.8" r=".44" fill="#fff" stroke="#000" stroke-width=".21"/>
<circle cx="173.8" cy="72.2" r=".68" fill="#008000" stroke="#008000" stroke-width=".21"/>
<circle cx="173.8" cy="72.2" r=".38" fill="#fff" stroke="#000" stroke-width=".21"/>
<circle cx="173.8" cy="76.5" r=".68" fill="#008000" stroke="#008000" stroke-width=".21"/>
<circle cx="173.8" cy="76.5" r=".38" fill="#fff" stroke="#000" stroke-width=".21"/>
<circle cx="173.8" cy="79.4" r=".68" fill="#008000" stroke="#008000" stroke-width=".21"/>
<circle cx="173.8" cy="79.4" r=".38" fill="#fff" stroke="#000" stroke-width=".21"/>
<circle cx="196.2" cy="102.1" r=".68" fill="#008000" stroke="#008000" stroke-width=".21"/>
<circle cx="196.2" cy="102.1" r=".38" fill="#fff" stroke="#000" stroke-width=".21"/>
<circle cx="173.8" cy="94.8" r=".76" fill="#008000" stroke="#008000" stroke-width=".21"/>
<circle cx="173.8" cy="94.8" r=".44" fill="#fff" stroke="#000" stroke-width=".21"/>
<circle cx="176.9" cy="70.4" r=".68" fill="#008000" stroke="#008000" stroke-width=".21"/>
<circle cx="176.9" cy="70.4" r=".38" fill="#fff" stroke="#000" stroke-width=".21"/>
<circle cx="176.9" cy="76.7" r=".68" fill="#008000" stroke="#008000" stroke-width=".21"/>
<circle cx="176.9" cy="76.7" r=".38" fill="#fff" stroke="#000" stroke-width=".21"/>
<circle cx="176.9" cy="79.4" r=".68" fill="#008000" stroke="#008000" stroke-width=".21"/>
<circle cx="176.9" cy="79.4" r=".38" fill="#fff" stroke="#000" stroke-width=".21"/>
<circle cx="198.1" cy="102.1" r=".68" fill="#008000" stroke="#008000" stroke-width=".21"/>
<circle cx="198.1" cy="102.1" r=".38" fill="#fff" stroke="#000" stroke-width=".21"/>
<circle cx="177.5" cy="94.1" r=".76" fill="#008000" stroke="#008000" stroke-width=".21"/>
<circle cx="177.5" cy="94.1" r=".44" fill="#fff" stroke="#000" stroke-width=".21"/>
<circle cx="205.6" cy="120.2" r=".68" fill="#008000" stroke="#008000" stroke-width=".21"/>
<circle cx="205.6" cy="120.2" r=".38" fill="#fff" stroke="#000" stroke-width=".21"/>
<circle cx="208.2" cy="122.2" r=".68" fill="#008000" stroke="#008000" stroke-width=".21"/>
<circle cx="208.2" cy="122.2" r=".38" fill="#fff" stroke="#000" stroke-width=".21"/>
<circle cx="104.5" cy="102.5" r=".68" fill="#008000" stroke="#008000" stroke-width=".21"/>
<circle cx="104.5" cy="102.5" r=".38" fill="#fff" stroke="#000" stroke-width=".21"/>
<circle cx="113.9" cy="82.4" r=".68" fill="#008000" stroke="#008000" stroke-width=".21"/>
<circle cx="113.9" cy="82.4" r=".38" fill="#fff" stroke="#000" stroke-width=".21"/>
<circle cx="102.7" cy="139.3" r=".68" fill="#008000" stroke="#008000" stroke-width=".21"/>
<circle cx="102.7" cy="139.3" r=".38" fill="#fff" stroke="#000" stroke-width=".21"/>
<circle cx="149.5" cy="145.7" r=".68" fill="#008000" stroke="#008000" stroke-width=".21"/>
<circle cx="149.5" cy="145.7" r=".38" fill="#fff" stroke="#000" stroke-width=".21"/>
<circle cx="210.5" cy="113.8" r=".68" fill="#008000" stroke="#008000" stroke-width=".21"/>
<circle cx="210.5" cy="113.8" r=".38" fill="#fff" stroke="#000" stroke-width=".21"/>
<circle cx="199.2" cy="164.7" r=".68" fill="#008000" stroke="#008000" stroke-width=".21"/>
<circle cx="199.2" cy="164.7" r=".38" fill="#fff" stroke="#000" stroke-width=".21"/>
<circle cx="194.4" cy="160.4" r=".68" fill="#008000" stroke="#008000" stroke-width=".21"/>
<circle cx="194.4" cy="160.4" r=".38" fill="#fff" stroke="#000" stroke-width=".21"/>
<circle cx="191" cy="87.5" r=".68" fill="#008000" stroke="#008000" stroke-width=".21"/>
<circle cx="191" cy="87.5" r=".38" fill="#fff" stroke="#000" stroke-width=".21"/>
<circle cx="169.7" cy="87.3" r=".68" fill="#008000" stroke="#008000" stroke-width=".21"/>
<circle cx="169.7" cy="87.3" r=".38" fill="#fff" stroke="#000" stroke-width=".21"/>
<circle cx="149.5" cy="79.1" r=".68" fill="#008000" stroke="#008000" stroke-width=".21"/>
<circle cx="149.5" cy="79.1" r=".38" fill="#fff" stroke="#000" stroke-width=".21"/>
<circle cx="199.5" cy="107.4" r=".76" fill="#008000" stroke="#008000" stroke-width=".21"/>
<circle cx="199.5" cy="107.4" r=".47" fill="#fff" stroke="#000" stroke-width=".21"/>
<circle cx="180" cy="107.4" r=".68" fill="#008000" stroke="#008000" stroke-width=".21"/>
<circle cx="180" cy="107.4" r=".38" fill="#fff" stroke="#000" stroke-width=".21"/>
<circle cx="151.5" cy="65.6" r=".68" fill="#008000" stroke="#008000" stroke-width=".21"/>
<circle cx="151.5" cy="65.6" r=".38" fill="#fff" stroke="#000" stroke-width=".21"/>
<circle cx="151.4" cy="83" r=".68" fill="#008000" stroke="#008000" stroke-width=".21"/>
<circle cx="151.4" cy="83" r=".38" fill="#fff" stroke="#000" stroke-width=".21"/>
<circle cx="108.9" cy="88.2" r=".68" fill="#008000" stroke="#008000" stroke-width=".21"/>
<circle cx="108.9" cy="88.2" r=".38" fill="#fff" stroke="#000" stroke-width=".21"/>
<circle cx="108.9" cy="83.9" r=".68" fill="#008000" stroke="#008000" stroke-width=".21"/>
<circle cx="108.9" cy="83.9" r=".38" fill="#fff" stroke="#000" stroke-width=".21"/>
<circle cx="174.9" cy="67.8" r=".68" fill="#008000" stroke="#008000" stroke-width=".21"/>
<circle cx="174.9" cy="67.8" r=".38" fill="#fff" stroke="#000" stroke-width=".21"/>
<circle cx="151.7" cy="58.4" r=".68" fill="#008000" stroke="#008000" stroke-width=".21"/>
<circle cx="151.7" cy="58.4" r=".38" fill="#fff" stroke="#000" stroke-width=".21"/>
<circle cx="151.7" cy="62.2" r=".68" fill="#008000" stroke="#008000" stroke-width=".21"/>
<circle cx="151.7" cy="62.2" r=".38" fill="#fff" stroke="#000" stroke-width=".21"/>
<circle cx="209.6" cy="66.2" r=".68" fill="#008000" stroke="#008000" stroke-width=".21"/>
<circle cx="209.6" cy="66.2" r=".38" fill="#fff" stroke="#000" stroke-width=".21"/>
<circle cx="195.9" cy="43.7" r=".76" fill="#008000" stroke="#008000" stroke-width=".21"/>
<circle cx="195.9" cy="43.7" r=".47" fill="#fff" stroke="#000" stroke-width=".21"/>
<circle cx="161.2" cy="76.3" r=".68" fill="#008000" stroke="#008000" stroke-width=".21"/>
<circle cx="161.2" cy="76.3" r=".38" fill="#fff" stroke="#000" stroke-width=".21"/>
<circle cx="199.4" cy="158.1" r=".68" fill="#008000" stroke="#008000" stroke-width=".21"/>
<circle cx="199.4" cy="158.1" r=".38" fill="#fff" stroke="#000" stroke-width=".21"/>
<circle cx="178.1" cy="164.7" r=".76" fill="#008000" stroke="#008000" stroke-width=".21"/>
<circle cx="178.1" cy="164.7" r=".47" fill="#fff" stroke="#000" stroke-width=".21"/>
<circle cx="189.6" cy="165.3" r=".68" fill="#008000" stroke="#008000" stroke-width=".21"/>
<circle cx="189.6" cy="165.3" r=".38" fill="#fff" stroke="#000" stroke-width=".21"/>
<circle cx="146.1" cy="167.7" r=".68" fill="#008000" stroke="#008000" stroke-width=".21"/>
<circle cx="146.1" cy="167.7" r=".38" fill="#fff" stroke="#000" stroke-width=".21"/>
<circle cx="112.4" cy="167.1" r=".68" fill="#008000" stroke="#008000" stroke-width=".21"/>
<circle cx="112.4" cy="167.1" r=".38" fill="#fff" stroke="#000" stroke-width=".21"/>
<circle cx="112.4" cy="158.6" r=".68" fill="#008000" stroke="#008000" stroke-width=".21"/>
<circle cx="112.4" cy="158.6" r=".38" fill="#fff" stroke="#000" stroke-width=".21"/>
<circle cx="113.7" cy="105.5" r=".68" fill="#008000" stroke="#008000" stroke-width=".21"/>
<circle cx="113.7" cy="105.5" r=".38" fill="#fff" stroke="#000" stroke-width=".21"/>
<circle cx="115.7" cy="100.4" r=".68" fill="#008000" stroke="#008000" stroke-width=".21"/>
<circle cx="115.7" cy="100.4" r=".38" fill="#fff" stroke="#000" stroke-width=".21"/>
<circle cx="111.7" cy="96.7" r=".68" fill="#008000" stroke="#008000" stroke-width=".21"/>
<circle cx="111.7" cy="96.7" r=".38" fill="#fff" stroke="#000" stroke-width=".21"/>
<circle cx="111.9" cy="83.8" r=".68" fill="#008000" stroke="#008000" stroke-width=".21"/>
<circle cx="111.9" cy="83.8" r=".38" fill="#fff" stroke="#000" stroke-width=".21"/>
<circle cx="94.6" cy="37.8" r="3.2" fill="#008000" stroke="#008000" stroke-width=".21"/>
<circle cx="94.6" cy="37.8" r="2.39" fill="#fff" stroke="#000" stroke-width=".21"/>
<circle cx="205" cy="37.8" r="3.2" fill="#008000" stroke="#008000" stroke-width=".21"/>
<circle cx="205" cy="37.8" r="2.39" fill="#fff" stroke="#000" stroke-width=".21"/>
<circle cx="208.8" cy="166.3" r="3.2" fill="#008000" stroke="#008000" stroke-width=".21"/>
<circle cx="208.8" cy="166.3" r="2.39" fill="#fff" stroke="#000" stroke-width=".21"/>
<circle cx="88.9" cy="166.3" r="3.2" fill="#008000" stroke="#008000" stroke-width=".21"/>
<circle cx="88.9" cy="166.3" r="2.39" fill="#fff" stroke="#000" stroke-width=".21"/>
<path d="M198.8 161.8h1.4v1.3h-1.4z" fill="#008000" stroke="#008000" stroke-width=".21"/>
<circle cx="199.5" cy="162.4" r=".38" fill="#fff" stroke="#000" stroke-width=".21"/>
<g fill="#800000" stroke="#800000" stroke-width=".21">
<path d="M108.4 128l6 .1z"/>
<path d="M114.3 128l.1 3z"/>
<path d="M108.4 131h6z"/>
<path d="M108.4 128v3z"/>
<path d="M90.7 127.2v5.9z"/>
<path d="M90.7 127.2h3z"/>
<path d="M93.6 127.2l.1 5.9z"/>
<path d="M90.7 133.1h3z"/>
<path d="M180.8 135.2l.1 6z"/>
<path d="M177.9 141.1h3z"/>
<path d="M177.9 135.2v6z"/>
<path d="M177.9 135.2h3z"/>
<path d="M175.3 135.2v6z"/>
<path d="M172.4 141.1h3z"/>
<path d="M172.3 135.2l.1 6z"/>
<path d="M172.3 135.2h3.1z"/>
<path d="M169.7 135.2l.1 6z"/>
<path d="M166.8 141.1h3z"/>
<path d="M166.8 135.2l.1 6z"/>
<path d="M166.8 135.2h3z"/>
<path d="M164.2 135.2l.1 6z"/>
<path d="M161.2 141.1h3.1z"/>
<path d="M161.2 135.2l.1 6z"/>
<path d="M161.2 135.2h3.1z"/>
<path d="M158.7 135.2v6z"/>
<path d="M155.7 141.1h3z"/>
<path d="M155.7 135.2l.1 6z"/>
<path d="M155.7 135.2h3z"/>
<path d="M153.1 135.2l.1 6z"/>
<path d="M150.2 141.1h3z"/>
<path d="M150.2 135.2l.1 6z"/>
<path d="M150.2 135.2h3z"/>
<path d="M147.6 135.2l.1 6z"/>
<path d="M144.7 141.1h3z"/>
<path d="M144.7 135.2v6z"/>
<path d="M144.7 135.2h3z"/>
<path d="M186.4 135.1v6z"/>
<path d="M183.4 141.1h3.1z"/>
<path d="M183.4 135.1l.1 6z"/>
<path d="M183.4 135.1l3.1 .1z"/>
<path d="M186.4 127.6v6z"/>
<path d="M183.4 133.6h3.1z"/>
<path d="M183.5 127.6v6z"/>
<path d="M183.5 127.6l3 .1z"/>
<path d="M180.9 127.6v6z"/>
<path d="M177.9 133.5l3 .1z"/>
<path d="M177.9 127.6l.1 6z"/>
<path d="M177.9 127.6l3 .1z"/>
<path d="M175.3 127.6v6z"/>
<path d="M172.3 133.5l3.1 .1z"/>
<path d="M172.3 127.6l.1 6z"/>
<path d="M172.3 127.6l3.1 .1z"/>
<path d="M169.8 127.6v6z"/>
<path d="M166.8 133.6h3z"/>
<path d="M166.8 127.6l.1 6z"/>
<path d="M166.8 127.6l3 .1z"/>
<path d="M164.2 127.6l.1 6z"/>
<path d="M161.2 133.5l3.1 .1z"/>
<path d="M161.2 127.6l.1 6z"/>
<path d="M161.2 127.6l3.1 .1z"/>
<path d="M158.7 127.6v6z"/>
<path d="M155.7 133.6h3z"/>
<path d="M155.7 127.6l.1 6z"/>
<path d="M155.7 127.6l3 .1z"/>
<path d="M153.1 127.6l.1 6z"/>
<path d="M150.2 133.6h3z"/>
<path d="M150.2 127.6v6z"/>
<path d="M150.2 127.6l3 .1z"/>
<path d="M147.6 127.7l.1 5.9z"/>
<path d="M144.7 133.6h3z"/>
<path d="M144.7 127.7v5.9z"/>
<path d="M144.7 127.7h3z"/>
<path d="M117.3 125.2v6z"/>
<path d="M117.3 125.2l3 .1z"/>
<path d="M120.2 125.2l.1 6z"/>
<path d="M117.3 131.2h3z"/>
<path d="M114.5 135.3l.1 5.9z"/>
<path d="M111.5 141.2h3.1z"/>
<path d="M111.5 135.3l.1 5.9z"/>
<path d="M111.5 135.3h3.1z"/>
<path d="M111.1 121.4l.1 6z"/>
<path d="M111.1 121.4h3.1z"/>
<path d="M114.1 121.4l.1 6z"/>
<path d="M111.1 127.3l3.1 .1z"/>
<path d="M91.8 115.3l.1 5.9z"/>
<path d="M88.9 121.2h3z"/>
<path d="M88.9 115.3v5.9z"/>
<path d="M88.9 115.3h3z"/>
<path d="M120 135.3l.1 5.9z"/>
<path d="M117.1 141.2h3z"/>
<path d="M117.1 135.3v5.9z"/>
<path d="M117.1 135.3h3z"/>
<path d="M136.1 135.3l.1 5.9z"/>
<path d="M133.2 141.2h3z"/>
<path d="M133.2 135.3l.1 5.9z"/>
<path d="M133.2 135.3h3z"/>
<path d="M130.6 135.3l.1 6z"/>
<path d="M127.7 141.2h3z"/>
<path d="M127.7 135.3v6z"/>
<path d="M127.7 135.3h3z"/>
<path d="M125.1 135.3l.1 6z"/>
<path d="M122.2 141.2h3z"/>
<path d="M122.2 135.3v6z"/>
<path d="M122.2 135.3h3z"/>
<path d="M141.7 135.3v5.9z"/>
<path d="M138.7 141.2h3.1z"/>
<path d="M138.7 135.3l.1 5.9z"/>
<path d="M138.7 135.3h3.1z"/>
<path d="M141.6 127.8l.1 6z"/>
<path d="M138.7 133.7l3 .1z"/>
<path d="M138.7 127.8l.1 6z"/>
<path d="M138.7 127.8h3z"/>
<path d="M136.1 127.8l.1 6z"/>
<path d="M133.2 133.7l3 .1z"/>
<path d="M133.2 127.8v6z"/>
<path d="M133.2 127.8l3 .1z"/>
<path d="M130.6 127.8l.1 6z"/>
<path d="M127.7 133.7l3 .1z"/>
<path d="M127.7 127.8v6z"/>
<path d="M127.7 127.8l3 .1z"/>
<path d="M125.1 127.8l.1 6z"/>
<path d="M122.2 133.8h3z"/>
<path d="M122.2 127.8v6z"/>
<path d="M122.2 127.8l3 .1z"/>
<path d="M109.2 143.4h6z"/>
<path d="M115.1 143.4l.1 3z"/>
<path d="M109.2 146.3h6z"/>
<path d="M109.2 143.4v3z"/>
<path d="M147.3 148.4v5.9z"/>
<path d="M144.3 154.3h3z"/>
<path d="M144.3 148.4l.1 5.9z"/>
<path d="M144.3 148.4h3z"/>
<path d="M158.5 147.9l.1 6z"/>
<path d="M155.6 153.8h3z"/>
<path d="M155.6 147.9v6z"/>
<path d="M155.6 147.9h3z"/>
<path d="M117.2 108.4v6z"/>
<path d="M114.2 114.3l3 .1z"/>
<path d="M114.2 108.4l.1 6z"/>
<path d="M114.2 108.4l3 .1z"/>
</g>
<g fill="#808080" stroke="#808080" stroke-width=".21">
<path d="M155.7 102.7a.53 .53 0 0 1 .9 .1 .53 .53 0 0 1-.4 .8 .53 .53 0 0 1-.6-.5h.2a.31 .31 0 0 1 .4-.4 .31 .31 0 0 1 .1 .5 .31 .31 0 0 1-.5 0l-.2-.1z" fill-rule="evenodd"/>
<path d="M126.7 102.5a.53 .53 0 0 1 .8 .1 .53 .53 0 0 1-.4 .8 .53 .53 0 0 1-.6-.6h.2a.3 .3 0 0 1 .5-.2 .3 .3 0 0 1 0 .5 .3 .3 0 0 1-.5-.1l-.2-.2z" fill-rule="evenodd"/>
<circle cx="88.9" cy="166.4" r="2.62"/>
<circle cx="94.6" cy="37.8" r="2.62"/>
<circle cx="208.9" cy="166.4" r="2.62"/>
<circle cx="205" cy="37.8" r="2.62"/>
<circle cx="203.4" cy="140.8" r="1.06"/>
<circle cx="201.5" cy="140.8" r="1.06"/>
<circle cx="203.4" cy="138.9" r="1.06"/>
<circle cx="201.5" cy="138.9" r="1.06"/>
<circle cx="203.4" cy="137" r="1.06"/>
<circle cx="201.5" cy="137" r="1.06"/>
<circle cx="203.4" cy="135.1" r="1.06"/>
<circle cx="201.5" cy="135.1" r="1.06"/>
<circle cx="203.4" cy="133.2" r="1.06"/>
<circle cx="201.5" cy="133.2" r="1.06"/>
<circle cx="203.4" cy="131.3" r="1.06"/>
<circle cx="201.5" cy="131.3" r="1.06"/>
<circle cx="203.4" cy="129.4" r="1.06"/>
<circle cx="201.5" cy="129.4" r="1.06"/>
<circle cx="203.4" cy="127.5" r="1.06"/>
<circle cx="201.5" cy="127.5" r="1.06"/>
<circle cx="203.4" cy="125.6" r="1.06"/>
<circle cx="201.5" cy="125.6" r="1.06"/>
<circle cx="203.4" cy="123.7" r="1.06"/>
<circle cx="201.5" cy="123.7" r="1.06"/>
<circle cx="203.4" cy="121.8" r="1.06"/>
<circle cx="201.5" cy="121.8" r="1.06"/>
<circle cx="203.4" cy="119.8" r="1.06"/>
<circle cx="201.5" cy="119.8" r="1.06"/>
<circle cx="203.4" cy="117.9" r="1.06"/>
<circle cx="201.5" cy="117.9" r="1.06"/>
<circle cx="203.4" cy="116" r="1.06"/>
<circle cx="201.5" cy="116" r="1.06"/>
<circle cx="203.4" cy="114.1" r="1.06"/>
<circle cx="201.5" cy="114.1" r="1.06"/>
<circle cx="203.4" cy="112.2" r="1.06"/>
<circle cx="201.5" cy="112.2" r="1.06"/>
<circle cx="203.4" cy="110.3" r="1.06"/>
<circle cx="201.5" cy="110.3" r="1.06"/>
<circle cx="203.4" cy="108.4" r="1.06"/>
<circle cx="201.5" cy="108.4" r="1.06"/>
<circle cx="203.4" cy="106.5" r="1.06"/>
<circle cx="201.5" cy="106.5" r="1.06"/>
<circle cx="203.4" cy="104.6" r="1.06"/>
<circle cx="201.5" cy="104.6" r="1.06"/>
<circle cx="203.4" cy="102.7" r="1.06"/>
<circle cx="201.5" cy="102.7" r="1.06"/>
<circle cx="203.4" cy="100.8" r="1.06"/>
<circle cx="201.5" cy="100.8" r="1.06"/>
<circle cx="203.4" cy="98.9" r="1.06"/>
<circle cx="201.5" cy="98.9" r="1.06"/>
<circle cx="203.4" cy="97" r="1.06"/>
<circle cx="201.5" cy="97" r="1.06"/>
<circle cx="203.4" cy="95.1" r="1.06"/>
<circle cx="201.5" cy="95.1" r="1.06"/>
<circle cx="102.5" cy="41.4" r="1.29"/>
<circle cx="102.5" cy="37.5" r="1.29"/>
<circle cx="106.3" cy="41.4" r="1.29"/>
<circle cx="106.3" cy="37.5" r="1.29"/>
<circle cx="110.1" cy="41.4" r="1.29"/>
<circle cx="110.1" cy="37.5" r="1.29"/>
<circle cx="113.9" cy="41.4" r="1.29"/>
<circle cx="113.9" cy="37.5" r="1.29"/>
<circle cx="117.8" cy="41.4" r="1.29"/>
<circle cx="117.8" cy="37.5" r="1.29"/>
<circle cx="121.6" cy="41.4" r="1.29"/>
<circle cx="121.6" cy="37.5" r="1.29"/>
<circle cx="125.4" cy="41.4" r="1.29"/>
<circle cx="125.4" cy="37.5" r="1.29"/>
<circle cx="129.2" cy="41.4" r="1.29"/>
<circle cx="129.2" cy="37.5" r="1.29"/>
<circle cx="133" cy="41.4" r="1.29"/>
<circle cx="133" cy="37.5" r="1.29"/>
<circle cx="136.8" cy="41.4" r="1.29"/>
<circle cx="136.8" cy="37.5" r="1.29"/>
<circle cx="140.6" cy="41.4" r="1.29"/>
<circle cx="140.6" cy="37.5" r="1.29"/>
<circle cx="144.4" cy="41.4" r="1.29"/>
<circle cx="144.4" cy="37.5" r="1.29"/>
<circle cx="148.2" cy="41.4" r="1.29"/>
<circle cx="148.2" cy="37.5" r="1.29"/>
<circle cx="152" cy="41.4" r="1.29"/>
<circle cx="152" cy="37.5" r="1.29"/>
<circle cx="155.8" cy="41.4" r="1.29"/>
<circle cx="155.8" cy="37.5" r="1.29"/>
<circle cx="159.6" cy="41.4" r="1.29"/>
<circle cx="159.6" cy="37.5" r="1.29"/>
<circle cx="163.4" cy="41.4" r="1.29"/>
<circle cx="163.4" cy="37.5" r="1.29"/>
<circle cx="167.3" cy="41.4" r="1.29"/>
<circle cx="167.3" cy="37.5" r="1.29"/>
<circle cx="171.1" cy="41.4" r="1.29"/>
<circle cx="171.1" cy="37.5" r="1.29"/>
<circle cx="174.9" cy="41.4" r="1.29"/>
<circle cx="174.9" cy="37.5" r="1.29"/>
<circle cx="178.7" cy="41.4" r="1.29"/>
<circle cx="178.7" cy="37.5" r="1.29"/>
<circle cx="182.5" cy="41.4" r="1.29"/>
<circle cx="182.5" cy="37.5" r="1.29"/>
<circle cx="186.3" cy="41.4" r="1.29"/>
<circle cx="186.3" cy="37.5" r="1.29"/>
<circle cx="190.1" cy="41.4" r="1.29"/>
<circle cx="190.1" cy="37.5" r="1.29"/>
<circle cx="193.9" cy="41.4" r="1.29"/>
<circle cx="193.9" cy="37.5" r="1.29"/>
<circle cx="197.7" cy="41.4" r="1.29"/>
<circle cx="197.7" cy="37.5" r="1.29"/>
<circle cx="102.5" cy="49" r="1.29"/>
<circle cx="102.5" cy="45.1" r="1.29"/>
<circle cx="106.3" cy="49" r="1.29"/>
<circle cx="106.3" cy="45.1" r="1.29"/>
<circle cx="110.1" cy="49" r="1.29"/>
<circle cx="110.1" cy="45.1" r="1.29"/>
<circle cx="113.9" cy="49" r="1.29"/>
<circle cx="113.9" cy="45.1" r="1.29"/>
<circle cx="117.8" cy="49" r="1.29"/>
<circle cx="117.8" cy="45.1" r="1.29"/>
<circle cx="121.6" cy="49" r="1.29"/>
<circle cx="121.6" cy="45.1" r="1.29"/>
<circle cx="125.4" cy="49" r="1.29"/>
<circle cx="125.4" cy="45.1" r="1.29"/>
<circle cx="129.2" cy="49" r="1.29"/>
<circle cx="129.2" cy="45.1" r="1.29"/>
<circle cx="133" cy="49" r="1.29"/>
<circle cx="133" cy="45.1" r="1.29"/>
<circle cx="136.8" cy="49" r="1.29"/>
<circle cx="136.8" cy="45.1" r="1.29"/>
<circle cx="140.6" cy="49" r="1.29"/>
<circle cx="140.6" cy="45.1" r="1.29"/>
<circle cx="144.4" cy="49" r="1.29"/>
<circle cx="144.4" cy="45.1" r="1.29"/>
<circle cx="148.2" cy="49" r="1.29"/>
<circle cx="148.2" cy="45.1" r="1.29"/>
<circle cx="152" cy="49" r="1.29"/>
<circle cx="152" cy="45.1" r="1.29"/>
<circle cx="155.9" cy="49" r="1.29"/>
<circle cx="155.9" cy="45.1" r="1.29"/>
<circle cx="159.7" cy="49" r="1.29"/>
<circle cx="159.7" cy="45.1" r="1.29"/>
<circle cx="163.5" cy="49" r="1.29"/>
<circle cx="163.5" cy="45.1" r="1.29"/>
<circle cx="167.3" cy="49" r="1.29"/>
<circle cx="167.3" cy="45.1" r="1.29"/>
<circle cx="171.1" cy="49" r="1.29"/>
<circle cx="171.1" cy="45.1" r="1.29"/>
<circle cx="174.9" cy="49" r="1.29"/>
<circle cx="174.9" cy="45.1" r="1.29"/>
<circle cx="178.7" cy="49" r="1.29"/>
<circle cx="178.7" cy="45.1" r="1.29"/>
<circle cx="182.5" cy="49" r="1.29"/>
<circle cx="182.5" cy="45.1" r="1.29"/>
<circle cx="186.3" cy="49" r="1.29"/>
<circle cx="186.3" cy="45.1" r="1.29"/>
<circle cx="190.1" cy="49" r="1.29"/>
<circle cx="190.1" cy="45.1" r="1.29"/>
<circle cx="193.9" cy="49" r="1.29"/>
<circle cx="193.9" cy="45.1" r="1.29"/>
<circle cx="197.7" cy="49" r="1.29"/>
<circle cx="197.7" cy="45.1" r="1.29"/>
<circle cx="202.1" cy="81" r="1.95"/>
<circle cx="202.1" cy="75" r="1.95"/>
<circle cx="202.1" cy="69" r="1.95"/>
<circle cx="202.1" cy="63" r="1.95"/>
<circle cx="202.1" cy="87" r="2.56"/>
<circle cx="202.1" cy="57" r="2.56"/>
<circle cx="211.6" cy="62.9" r="1.95"/>
<circle cx="211.6" cy="68.9" r="1.95"/>
<circle cx="211.6" cy="74.9" r="1.95"/>
<circle cx="211.6" cy="80.9" r="1.95"/>
<circle cx="211.6" cy="86.9" r="1.95"/>
<circle cx="211.6" cy="92.9" r="1.95"/>
<circle cx="211.6" cy="98.9" r="1.95"/>
<circle cx="211.6" cy="104.9" r="1.95"/>
<circle cx="211.6" cy="110.9" r="1.95"/>
<circle cx="211.6" cy="116.9" r="1.95"/>
<circle cx="211.6" cy="56.9" r="2.56"/>
<circle cx="211.6" cy="122.9" r="2.56"/>
<circle cx="115.6" cy="133.7" r=".83"/>
<circle cx="104.4" cy="122.8" r=".83"/>
<circle cx="187.6" cy="151.8" r=".83"/>
<circle cx="181.5" cy="151.8" r=".83"/>
<circle cx="169.7" cy="39.4" r=".83"/>
<circle cx="137.2" cy="52.9" r=".91"/>
<circle cx="112.4" cy="53.7" r=".91"/>
<circle cx="112.3" cy="76.2" r=".83"/>
<circle cx="124.7" cy="79.6" r=".83"/>
<circle cx="129.8" cy="79.7" r=".83"/>
<circle cx="136.5" cy="79.7" r=".83"/>
<circle cx="113.6" cy="100.4" r=".83"/>
<circle cx="116.6" cy="97.3" r=".83"/>
<circle cx="113.2" cy="95" r=".83"/>
<circle cx="144.4" cy="53.8" r=".91"/>
<circle cx="193.3" cy="149.3" r=".83"/>
<circle cx="201.7" cy="146.7" r=".83"/>
<circle cx="171.2" cy="134.6" r=".83"/>
<circle cx="171.3" cy="127.9" r=".83"/>
<circle cx="119.4" cy="88.2" r=".91"/>
<circle cx="111.5" cy="101" r=".83"/>
<circle cx="114.2" cy="117.4" r=".83"/>
<circle cx="117.2" cy="120.5" r=".83"/>
<circle cx="116.3" cy="127.8" r=".83"/>
<circle cx="176.6" cy="134.5" r=".83"/>
<circle cx="175.3" cy="109.7" r=".83"/>
<circle cx="178.8" cy="113.8" r=".91"/>
<circle cx="186.7" cy="127.5" r=".83"/>
<circle cx="182.8" cy="141.2" r=".83"/>
<circle cx="175.7" cy="164.7" r=".91"/>
<circle cx="123.3" cy="82.1" r=".83"/>
<circle cx="131.1" cy="111.4" r=".83"/>
<circle cx="139.6" cy="127.3" r=".83"/>
<circle cx="161.7" cy="124.1" r=".91"/>
<circle cx="161.4" cy="118" r=".91"/>
<circle cx="165.7" cy="113.8" r=".91"/>
<circle cx="131.9" cy="134.3" r=".83"/>
<circle cx="129.2" cy="115.3" r=".83"/>
<circle cx="126.4" cy="134.2" r=".83"/>
<circle cx="126.4" cy="127.7" r=".83"/>
<circle cx="137.4" cy="134.5" r=".83"/>
<circle cx="137.5" cy="128" r=".83"/>
<circle cx="135" cy="120.3" r=".83"/>
<circle cx="139.3" cy="116.1" r=".83"/>
<circle cx="137.2" cy="113.5" r=".83"/>
<circle cx="131" cy="88.3" r=".83"/>
<circle cx="129.8" cy="82.2" r=".83"/>
<circle cx="123.4" cy="39.5" r=".91"/>
<circle cx="129.7" cy="60.7" r=".83"/>
<circle cx="133.6" cy="62.8" r=".83"/>
<circle cx="133.6" cy="67.6" r=".83"/>
<circle cx="190.5" cy="101.4" r=".83"/>
<circle cx="146.7" cy="95.3" r=".83"/>
<circle cx="170.9" cy="61" r=".83"/>
<circle cx="171.5" cy="64.7" r=".83"/>
<circle cx="194.3" cy="64.7" r=".83"/>
<circle cx="199.2" cy="69.6" r=".83"/>
<circle cx="192.8" cy="88.4" r=".83"/>
<circle cx="165.1" cy="85.3" r=".83"/>
<circle cx="161.3" cy="85.5" r=".83"/>
<circle cx="156.8" cy="80.9" r=".83"/>
<circle cx="149.5" cy="80.9" r=".83"/>
<circle cx="136.5" cy="83.8" r=".83"/>
<circle cx="133.6" cy="83.9" r=".83"/>
<circle cx="133.6" cy="77.6" r=".83"/>
<circle cx="129.8" cy="77.7" r=".83"/>
<circle cx="124.6" cy="77.7" r=".83"/>
<circle cx="117.8" cy="71.7" r=".83"/>
<circle cx="154.7" cy="134.3" r=".83"/>
<circle cx="169.5" cy="107.5" r=".83"/>
<circle cx="106" cy="120.7" r=".83"/>
<circle cx="130.3" cy="125.9" r=".83"/>
<circle cx="133.8" cy="126" r=".83"/>
<circle cx="144.6" cy="126" r=".83"/>
<circle cx="147.5" cy="125.9" r=".83"/>
<circle cx="165.8" cy="134.4" r=".83"/>
<circle cx="172.3" cy="108.6" r=".83"/>
<circle cx="154" cy="113.6" r=".91"/>
<circle cx="147.5" cy="113.6" r=".83"/>
<circle cx="144.7" cy="113.7" r=".83"/>
<circle cx="133.5" cy="117.7" r=".83"/>
<circle cx="128.5" cy="117.7" r=".83"/>
<circle cx="115.5" cy="105.4" r=".91"/>
<circle cx="119.1" cy="100.4" r=".83"/>
<circle cx="126.8" cy="67.7" r=".83"/>
<circle cx="124.6" cy="70.6" r=".83"/>
<circle cx="116" cy="69" r=".83"/>
<circle cx="160.2" cy="134.5" r=".83"/>
<circle cx="160.2" cy="128" r=".83"/>
<circle cx="110.1" cy="117.8" r=".83"/>
<circle cx="130.2" cy="121.9" r=".83"/>
<circle cx="134" cy="122" r=".83"/>
<circle cx="144.7" cy="121.9" r=".83"/>
<circle cx="147.5" cy="122" r=".83"/>
<circle cx="151.2" cy="124.2" r=".91"/>
<circle cx="149" cy="134.3" r=".83"/>
<circle cx="149" cy="128" r=".83"/>
<circle cx="108.3" cy="119.3" r=".83"/>
<circle cx="130.2" cy="124.2" r=".91"/>
<circle cx="134.1" cy="124.1" r=".83"/>
<circle cx="144.5" cy="124" r=".83"/>
<circle cx="192" cy="103.5" r=".83"/>
<circle cx="159.9" cy="65.6" r=".83"/>
<circle cx="165.1" cy="88.2" r=".83"/>
<circle cx="169.3" cy="94.9" r=".91"/>
<circle cx="136.8" cy="107.9" r=".83"/>
<circle cx="120.8" cy="112.9" r=".83"/>
<circle cx="182.4" cy="134.3" r=".83"/>
<circle cx="182.3" cy="127.7" r=".83"/>
<circle cx="102.6" cy="91.5" r=".83"/>
<circle cx="111.5" cy="131.7" r=".83"/>
<circle cx="143.3" cy="134.5" r=".83"/>
<circle cx="143.2" cy="127.4" r=".91"/>
<circle cx="118" cy="114.2" r=".83"/>
<circle cx="138.9" cy="107.9" r=".83"/>
<circle cx="129.7" cy="108.2" r=".83"/>
<circle cx="100.9" cy="117.1" r=".83"/>
<circle cx="118" cy="110.8" r=".61"/>
<circle cx="103.4" cy="114.6" r=".83"/>
<circle cx="103" cy="125.5" r=".83"/>
<circle cx="180" cy="56.2" r=".83"/>
<circle cx="178.5" cy="53.4" r=".83"/>
<circle cx="159.9" cy="61.4" r=".91"/>
<circle cx="158.1" cy="70.3" r=".91"/>
<circle cx="160.8" cy="106.4" r=".91"/>
<circle cx="157.6" cy="43.1" r=".91"/>
<circle cx="177.5" cy="109.3" r=".91"/>
<circle cx="153.4" cy="83" r=".83"/>
<circle cx="167.5" cy="85.1" r=".83"/>
<circle cx="196.3" cy="88.4" r=".83"/>
<circle cx="207" cy="96.4" r=".83"/>
<circle cx="186.6" cy="149.9" r=".83"/>
<circle cx="130.9" cy="93.9" r=".83"/>
<circle cx="153.1" cy="93.7" r=".83"/>
<circle cx="153.1" cy="88.5" r=".83"/>
<circle cx="142.5" cy="82.4" r=".83"/>
<circle cx="159.4" cy="58.9" r=".83"/>
<circle cx="212.2" cy="129.4" r=".83"/>
<circle cx="185.4" cy="146.9" r=".83"/>
<circle cx="156.6" cy="76.8" r=".83"/>
<circle cx="100.1" cy="142.7" r=".83"/>
<circle cx="110.6" cy="136.5" r=".83"/>
<circle cx="149.4" cy="76" r=".83"/>
<circle cx="143.3" cy="73.9" r=".83"/>
<circle cx="143.4" cy="65.6" r=".83"/>
<circle cx="137.6" cy="65.6" r=".83"/>
<circle cx="129.7" cy="68.2" r=".83"/>
<circle cx="124.6" cy="74.9" r=".83"/>
<circle cx="182.6" cy="70.4" r=".83"/>
<circle cx="182.5" cy="76.6" r=".83"/>
<circle cx="182.5" cy="79.4" r=".83"/>
<circle cx="194.1" cy="136.4" r=".83"/>
<circle cx="195" cy="114.4" r=".83"/>
<circle cx="175.1" cy="62.7" r=".83"/>
<circle cx="179.5" cy="62.5" r=".83"/>
<circle cx="179.6" cy="70.3" r=".83"/>
<circle cx="179.6" cy="76.6" r=".83"/>
<circle cx="179.6" cy="79.4" r=".83"/>
<circle cx="179.5" cy="93.8" r=".91"/>
<circle cx="189.3" cy="93.9" r=".83"/>
<circle cx="187.7" cy="70.2" r=".83"/>
<circle cx="187.7" cy="76.7" r=".83"/>
<circle cx="187.7" cy="79.4" r=".83"/>
<circle cx="192.3" cy="70.2" r=".83"/>
<circle cx="192.2" cy="76.6" r=".83"/>
<circle cx="192.2" cy="79.4" r=".83"/>
<circle cx="167.5" cy="74.4" r=".83"/>
<circle cx="159.7" cy="75.1" r=".83"/>
<circle cx="130.1" cy="146.5" r=".83"/>
<circle cx="147.9" cy="105.1" r=".83"/>
<circle cx="168.1" cy="104.5" r=".91"/>
<circle cx="187.6" cy="104.2" r=".83"/>
<circle cx="133" cy="88.5" r=".83"/>
<circle cx="143.8" cy="110.7" r=".83"/>
<circle cx="147.3" cy="109" r=".83"/>
<circle cx="188.8" cy="144.5" r=".83"/>
<circle cx="192" cy="121.6" r=".83"/>
<circle cx="127.2" cy="145.4" r=".83"/>
<circle cx="150.5" cy="103.6" r=".83"/>
<circle cx="164.9" cy="102.8" r=".91"/>
<circle cx="138" cy="88.4" r=".83"/>
<circle cx="153.8" cy="97.9" r=".83"/>
<circle cx="161.2" cy="95.6" r=".91"/>
<circle cx="188.9" cy="102.5" r=".83"/>
<circle cx="168.3" cy="102.4" r=".91"/>
<circle cx="155.3" cy="88.2" r=".83"/>
<circle cx="207.8" cy="128" r=".83"/>
<circle cx="202.1" cy="155.3" r=".83"/>
<circle cx="196.1" cy="155.2" r=".83"/>
<circle cx="142.9" cy="169.5" r=".83"/>
<circle cx="109.3" cy="168.7" r=".83"/>
<circle cx="104.4" cy="112.6" r=".83"/>
<circle cx="117.9" cy="108.6" r=".83"/>
<circle cx="120.4" cy="106.5" r=".83"/>
<circle cx="131.6" cy="100.3" r=".83"/>
<circle cx="141.4" cy="100.8" r=".91"/>
<circle cx="135.2" cy="88.2" r=".83"/>
<circle cx="132.7" cy="53.6" r=".91"/>
<circle cx="137.6" cy="63.2" r=".83"/>
<circle cx="142.6" cy="63.3" r=".83"/>
<circle cx="142.4" cy="55.1" r=".83"/>
<circle cx="107" cy="141.2" r=".83"/>
<circle cx="104.2" cy="138.1" r=".83"/>
<circle cx="184.8" cy="101.7" r=".83"/>
<circle cx="118.2" cy="95.8" r=".83"/>
<circle cx="121.8" cy="87.8" r=".91"/>
<circle cx="170.8" cy="69.8" r=".83"/>
<circle cx="171.3" cy="76.5" r=".83"/>
<circle cx="171.3" cy="79.4" r=".83"/>
<circle cx="193.5" cy="101.1" r=".83"/>
<circle cx="171.2" cy="95.8" r=".91"/>
<circle cx="173.8" cy="72.2" r=".83"/>
<circle cx="173.8" cy="76.5" r=".83"/>
<circle cx="173.8" cy="79.4" r=".83"/>
<circle cx="196.2" cy="102.1" r=".83"/>
<circle cx="173.8" cy="94.8" r=".91"/>
<circle cx="176.9" cy="70.4" r=".83"/>
<circle cx="176.9" cy="76.7" r=".83"/>
<circle cx="176.9" cy="79.4" r=".83"/>
<circle cx="198.1" cy="102.1" r=".83"/>
<circle cx="177.5" cy="94.1" r=".91"/>
<circle cx="205.6" cy="120.2" r=".83"/>
<circle cx="208.2" cy="122.2" r=".83"/>
<circle cx="104.5" cy="102.5" r=".83"/>
<circle cx="113.9" cy="82.4" r=".83"/>
<circle cx="102.7" cy="139.3" r=".83"/>
<circle cx="149.5" cy="145.7" r=".83"/>
<circle cx="210.5" cy="113.8" r=".83"/>
<circle cx="199.2" cy="164.7" r=".83"/>
<circle cx="194.4" cy="160.4" r=".83"/>
<circle cx="191" cy="87.5" r=".83"/>
<circle cx="169.7" cy="87.3" r=".83"/>
<circle cx="149.5" cy="79.1" r=".83"/>
<circle cx="199.5" cy="107.4" r=".91"/>
<circle cx="180" cy="107.4" r=".83"/>
<circle cx="151.5" cy="65.6" r=".83"/>
<circle cx="151.4" cy="83" r=".83"/>
<circle cx="108.9" cy="88.2" r=".83"/>
<circle cx="108.9" cy="83.9" r=".83"/>
<circle cx="174.9" cy="67.8" r=".83"/>
<circle cx="151.7" cy="58.4" r=".83"/>
<circle cx="151.7" cy="62.2" r=".83"/>
<circle cx="209.6" cy="66.2" r=".83"/>
<circle cx="195.9" cy="43.7" r=".91"/>
<circle cx="161.2" cy="76.3" r=".83"/>
<circle cx="199.4" cy="158.1" r=".83"/>
<circle cx="178.1" cy="164.7" r=".91"/>
<circle cx="189.6" cy="165.3" r=".83"/>
<circle cx="146.1" cy="167.7" r=".83"/>
<circle cx="112.4" cy="167.1" r=".83"/>
<circle cx="112.4" cy="158.6" r=".83"/>
<circle cx="113.7" cy="105.5" r=".83"/>
<circle cx="115.7" cy="100.4" r=".83"/>
<circle cx="111.7" cy="96.7" r=".83"/>
<circle cx="111.9" cy="83.8" r=".83"/>
<circle cx="94.6" cy="37.8" r="3.3"/>
<circle cx="205" cy="37.8" r="3.3"/>
<circle cx="208.8" cy="166.3" r="3.3"/>
<circle cx="88.9" cy="166.3" r="3.3"/>
</g>
<g fill="#808080" stroke="#808080" stroke-width=".21">
<path d="M153 102h1.8v.8h-1.8z"/>
<path d="M153 103h1.8v.8h-1.8z"/>
<path d="M153 104h1.8v.8h-1.8z"/>
<path d="M153 105h1.8v.7h-1.8z"/>
<path d="M153 105.9h1.8v.8h-1.8z"/>
<path d="M153 106.9h1.8v.8h-1.8z"/>
<path d="M153 107.9h1.8v.7h-1.8z"/>
<path d="M153 108.9h1.8v.7h-1.8z"/>
<path d="M153 109.8h1.8v.8h-1.8z"/>
<path d="M153 110.8h1.8v.8h-1.8z"/>
<path d="M161.8 110.8h1.8v.8h-1.8z"/>
<path d="M161.8 109.8h1.8v.8h-1.8z"/>
<path d="M161.8 108.9h1.8v.7h-1.8z"/>
<path d="M161.8 107.9h1.8v.7h-1.8z"/>
<path d="M161.8 106.9h1.8v.8h-1.8z"/>
<path d="M161.8 105.9h1.8v.8h-1.8z"/>
<path d="M161.8 105h1.8v.7h-1.8z"/>
<path d="M161.8 104h1.8v.8h-1.8z"/>
<path d="M161.8 103h1.8v.8h-1.8z"/>
<path d="M161.8 102h1.8v.8h-1.8z"/>
<path d="M124 101.8h1.7v.8h-1.7z"/>
<path d="M124 102.8h1.7v.8h-1.7z"/>
<path d="M124 103.8h1.7v.7h-1.7z"/>
<path d="M124 104.8h1.7v.7h-1.7z"/>
<path d="M124 105.7h1.7v.8h-1.7z"/>
<path d="M124 106.7h1.7v.8h-1.7z"/>
<path d="M124 107.7h1.7v.8h-1.7z"/>
<path d="M124 108.7h1.7v.7h-1.7z"/>
<path d="M124 109.6h1.7v.8h-1.7z"/>
<path d="M124 110.6h1.7v.8h-1.7z"/>
<path d="M132.7 110.6h1.8v.8h-1.8z"/>
<path d="M132.7 109.6h1.8v.8h-1.8z"/>
<path d="M132.7 108.7h1.8v.7h-1.8z"/>
<path d="M132.7 107.7h1.8v.8h-1.8z"/>
<path d="M132.7 106.7h1.8v.8h-1.8z"/>
<path d="M132.7 105.7h1.8v.8h-1.8z"/>
<path d="M132.7 104.8h1.8v.7h-1.8z"/>
<path d="M132.7 103.8h1.8v.7h-1.8z"/>
<path d="M132.7 102.8h1.8v.8h-1.8z"/>
<path d="M132.7 101.8h1.8v.8h-1.8z"/>
<path d="M109 128.2h2.2v2.6h-2.2z"/>
<path d="M111.5 128.2h2.3v2.6h-2.3z"/>
<path d="M90.9 130.3h2.6v2.2h-2.6z"/>
<path d="M90.9 127.7h2.6v2.3h-2.6z"/>
<path d="M178.1 135.8h2.6v2.2h-2.6z"/>
<path d="M178.1 138.3h2.6v2.3h-2.6z"/>
<path d="M172.6 135.8h2.5v2.2h-2.5z"/>
<path d="M172.6 138.3h2.5v2.3h-2.5z"/>
<path d="M167 135.8h2.6v2.2h-2.6z"/>
<path d="M167 138.3h2.6v2.3h-2.6z"/>
<path d="M161.5 135.8h2.5v2.2h-2.5z"/>
<path d="M161.5 138.3h2.5v2.2h-2.5z"/>
<path d="M156 135.8h2.5v2.2h-2.5z"/>
<path d="M156 138.3h2.5v2.2h-2.5z"/>
<path d="M150.5 135.8h2.5v2.2h-2.5z"/>
<path d="M150.5 138.3h2.5v2.2h-2.5z"/>
<path d="M144.9 135.8h2.5v2.2h-2.5z"/>
<path d="M144.9 138.3h2.5v2.2h-2.5z"/>
<path d="M183.7 135.7h2.5v2.3h-2.5z"/>
<path d="M183.7 138.3h2.5v2.2h-2.5z"/>
<path d="M183.7 128.2h2.5v2.3h-2.5z"/>
<path d="M183.7 130.8h2.5v2.2h-2.5z"/>
<path d="M178.2 128.2h2.5v2.3h-2.5z"/>
<path d="M178.2 130.8h2.5v2.2h-2.5z"/>
<path d="M172.6 128.2h2.5v2.3h-2.5z"/>
<path d="M172.6 130.7h2.5v2.3h-2.5z"/>
<path d="M167 128.2h2.6v2.3h-2.6z"/>
<path d="M167 130.8h2.6v2.2h-2.6z"/>
<path d="M161.5 128.2h2.5v2.3h-2.5z"/>
<path d="M161.5 130.8h2.5v2.2h-2.5z"/>
<path d="M156 128.2h2.5v2.3h-2.5z"/>
<path d="M156 130.8h2.5v2.2h-2.5z"/>
<path d="M150.4 128.2h2.6v2.3h-2.6z"/>
<path d="M150.4 130.8h2.6v2.2h-2.6z"/>
<path d="M144.9 128.2h2.5v2.3h-2.5z"/>
<path d="M144.9 130.8h2.5v2.2h-2.5z"/>
<path d="M117.5 128.4h2.5v2.2h-2.5z"/>
<path d="M117.5 125.8h2.5v2.3h-2.5z"/>
<path d="M111.8 135.8h2.5v2.3h-2.5z"/>
<path d="M111.8 138.4h2.5v2.2h-2.5z"/>
<path d="M111.4 124.5h2.5v2.3h-2.5z"/>
<path d="M111.4 122h2.5v2.2h-2.5z"/>
<path d="M89.1 115.8h2.5v2.3h-2.5z"/>
<path d="M89.1 118.4h2.5v2.2h-2.5z"/>
<path d="M117.3 135.8h2.5v2.3h-2.5z"/>
<path d="M117.3 138.4h2.5v2.2h-2.5z"/>
<path d="M133.4 135.8h2.6v2.3h-2.6z"/>
<path d="M133.4 138.4h2.6v2.3h-2.6z"/>
<path d="M127.9 135.9h2.6v2.2h-2.6z"/>
<path d="M127.9 138.4h2.6v2.3h-2.6z"/>
<path d="M122.4 135.9h2.5v2.2h-2.5z"/>
<path d="M122.4 138.4h2.5v2.3h-2.5z"/>
<path d="M139 135.8h2.5v2.3h-2.5z"/>
<path d="M139 138.4h2.5v2.3h-2.5z"/>
<path d="M139 128.4h2.5v2.2h-2.5z"/>
<path d="M139 130.9h2.5v2.3h-2.5z"/>
<path d="M133.4 128.4h2.6v2.2h-2.6z"/>
<path d="M133.4 131h2.6v2.2h-2.6z"/>
<path d="M127.9 128.4h2.6v2.2h-2.6z"/>
<path d="M127.9 131h2.6v2.2h-2.6z"/>
<path d="M122.4 128.4h2.5v2.3h-2.5z"/>
<path d="M122.4 131h2.5v2.2h-2.5z"/>
<path d="M102.1 118.6h1.4v1.1h-1.4z"/>
<path d="M100.2 118.6h1.3v1.1h-1.3z"/>
<path d="M148.5 149h2.1v1.1h-2.1z"/>
<path d="M148.5 150.4h2.1v1.2h-2.1z"/>
<path d="M148.5 151.8h2.1v1.2h-2.1z"/>
<path d="M152.4 151.8h2.1v1.2h-2.1z"/>
<path d="M152.4 149h2.1v1.1h-2.1z"/>
<path d="M123.7 164.8h1.4v3.3h-1.4z"/>
<path d="M125.6 164.8h1.4v3.3h-1.4z"/>
<path d="M127.6 164.8h1.3v3.3h-1.3z"/>
<path d="M129.5 164.8h1.3v3.3h-1.3z"/>
<path d="M131.4 164.8h1.3v3.3h-1.3z"/>
<path d="M133.3 164.8h1.3v3.3h-1.3z"/>
<path d="M135.2 164.8h1.3v3.3h-1.3z"/>
<path d="M137.1 164.8h1.3v3.3h-1.3z"/>
<path d="M137.1 149.7h1.3v3.4h-1.3z"/>
<path d="M135.2 149.7h1.3v3.4h-1.3z"/>
<path d="M133.3 149.7h1.3v3.4h-1.3z"/>
<path d="M131.4 149.7h1.3v3.4h-1.3z"/>
<path d="M129.5 149.7h1.3v3.4h-1.3z"/>
<path d="M127.6 149.7h1.3v3.4h-1.3z"/>
<path d="M125.6 149.7h1.4v3.4h-1.4z"/>
<path d="M123.7 149.7h1.4v3.4h-1.4z"/>
<path d="M139 164.8h1.3v3.3h-1.3z"/>
<path d="M140.9 164.8h1.3v3.3h-1.3z"/>
<path d="M139 149.7h1.3v3.4h-1.3z"/>
<path d="M140.9 149.7h1.3v3.4h-1.3z"/>
<path d="M109.8 143.6h2.2v2.5h-2.2z"/>
<path d="M112.3 143.6h2.3v2.5h-2.3z"/>
<path d="M173.7 153.6h6.1v6.1h-6.1z"/>
<path d="M186.5 154.1h5.1v5.1h-5.1z"/>
<path d="M161.9 154.1h5.1v5.1h-5.1z"/>
<path d="M144.5 148.9h2.6v2.3h-2.6z"/>
<path d="M144.5 151.5h2.6v2.2h-2.6z"/>
<path d="M155.8 148.5h2.5v2.2h-2.5z"/>
<path d="M155.8 151h2.5v2.3h-2.5z"/>
<path d="M142.7 96.6a1.15 1.15 0 0 1 1.8 .8v2.3a1.15 1.15 0 0 1-1.1 1 1.15 1.15 0 0 1-1.2-1v-2.3z"/>
<path d="M138.9 96.6a1.15 1.15 0 0 1 1.8 .8v2.3a1.15 1.15 0 0 1-1.1 1 1.15 1.15 0 0 1-1.2-1v-2.3z"/>
<path d="M114.4 109h2.6v2.3h-2.6z"/>
<path d="M114.4 111.5h2.6v2.3h-2.6z"/>
<path d="M114.9 138.9h1.6v1.6h-1.6z"/>
<path d="M98 130.5h1.7v1.7h-1.7z"/>
<path d="M97.9 124.8h1.7v1.6h-1.7z"/>
<path d="M198.7 161.6h1.6v1.7h-1.6z"/>
<path d="M153.2 102.2h1.5v.5h-1.5z"/>
<path d="M153.2 103.2h1.5v.4h-1.5z"/>
<path d="M153.2 104.1h1.5v.5h-1.5z"/>
<path d="M153.2 105.1h1.5v.5h-1.5z"/>
<path d="M153.2 106.1h1.5v.5h-1.5z"/>
<path d="M153.2 107.1h1.5v.4h-1.5z"/>
<path d="M153.2 108h1.5v.5h-1.5z"/>
<path d="M153.2 109h1.5v.5h-1.5z"/>
<path d="M153.2 110h1.5v.4h-1.5z"/>
<path d="M153.2 111h1.5v.4h-1.5z"/>
<path d="M161.9 111h1.5v.4h-1.5z"/>
<path d="M161.9 110h1.5v.4h-1.5z"/>
<path d="M161.9 109h1.5v.5h-1.5z"/>
<path d="M161.9 108h1.5v.5h-1.5z"/>
<path d="M161.9 107.1h1.5v.4h-1.5z"/>
<path d="M161.9 106.1h1.5v.5h-1.5z"/>
<path d="M161.9 105.1h1.5v.5h-1.5z"/>
<path d="M161.9 104.1h1.5v.5h-1.5z"/>
<path d="M161.9 103.2h1.5v.4h-1.5z"/>
<path d="M161.9 102.2h1.5v.5h-1.5z"/>
<path d="M124.1 102h1.5v.4h-1.5z"/>
<path d="M124.1 103h1.5v.4h-1.5z"/>
<path d="M124.1 103.9h1.5v.5h-1.5z"/>
<path d="M124.1 104.9h1.5v.5h-1.5z"/>
<path d="M124.1 105.9h1.5v.4h-1.5z"/>
<path d="M124.1 106.9h1.5v.4h-1.5z"/>
<path d="M124.1 107.8h1.5v.5h-1.5z"/>
<path d="M124.1 108.8h1.5v.5h-1.5z"/>
<path d="M124.1 109.8h1.5v.5h-1.5z"/>
<path d="M124.1 110.8h1.5v.4h-1.5z"/>
<path d="M132.9 110.8h1.4v.4h-1.4z"/>
<path d="M132.9 109.8h1.4v.5h-1.4z"/>
<path d="M132.9 108.8h1.4v.5h-1.4z"/>
<path d="M132.9 107.8h1.4v.5h-1.4z"/>
<path d="M132.9 106.9h1.4v.4h-1.4z"/>
<path d="M132.9 105.9h1.4v.4h-1.4z"/>
<path d="M132.9 104.9h1.4v.5h-1.4z"/>
<path d="M132.9 103.9h1.4v.5h-1.4z"/>
<path d="M132.9 103h1.4v.4h-1.4z"/>
<path d="M132.9 102h1.4v.4h-1.4z"/>
<path d="M109.1 128.4h2v2.2h-2z"/>
<path d="M111.7 128.4h1.9v2.2h-1.9z"/>
<path d="M91.1 130.5h2.2v1.9h-2.2z"/>
<path d="M91.1 127.9h2.2v1.9h-2.2z"/>
<path d="M178.3 135.9h2.2v2h-2.2z"/>
<path d="M178.3 138.5h2.2v1.9h-2.2z"/>
<path d="M172.7 135.9h2.3v2h-2.3z"/>
<path d="M172.7 138.5h2.3v1.9h-2.3z"/>
<path d="M167.2 135.9h2.2v2h-2.2z"/>
<path d="M167.2 138.5h2.2v1.9h-2.2z"/>
<path d="M161.6 135.9h2.3v2h-2.3z"/>
<path d="M161.6 138.5h2.3v1.9h-2.3z"/>
<path d="M156.1 135.9h2.2v2h-2.2z"/>
<path d="M156.1 138.5h2.2v1.9h-2.2z"/>
<path d="M150.6 135.9h2.2v2h-2.2z"/>
<path d="M150.6 138.5h2.2v1.9h-2.2z"/>
<path d="M145.1 135.9h2.2v2h-2.2z"/>
<path d="M145.1 138.5h2.2v1.9h-2.2z"/>
<path d="M183.8 135.9h2.3v1.9h-2.3z"/>
<path d="M183.8 138.4h2.3v2h-2.3z"/>
<path d="M183.8 128.4h2.3v1.9h-2.3z"/>
<path d="M183.8 130.9h2.3v2h-2.3z"/>
<path d="M178.3 128.4h2.3v1.9h-2.3z"/>
<path d="M178.3 130.9h2.3v2h-2.3z"/>
<path d="M172.7 128.4h2.3v1.9h-2.3z"/>
<path d="M172.7 130.9h2.3v1.9h-2.3z"/>
<path d="M167.2 128.4h2.2v1.9h-2.2z"/>
<path d="M167.2 130.9h2.2v2h-2.2z"/>
<path d="M161.6 128.4h2.3v1.9h-2.3z"/>
<path d="M161.6 130.9h2.3v2h-2.3z"/>
<path d="M156.1 128.4h2.3v1.9h-2.3z"/>
<path d="M156.1 130.9h2.3v2h-2.3z"/>
<path d="M150.6 128.4h2.2v1.9h-2.2z"/>
<path d="M150.6 130.9h2.2v2h-2.2z"/>
<path d="M145.1 128.4h2.2v1.9h-2.2z"/>
<path d="M145.1 130.9h2.2v2h-2.2z"/>
<path d="M117.6 128.5h2.3v2h-2.3z"/>
<path d="M117.6 126h2.3v1.9h-2.3z"/>
<path d="M112 136h2.2v1.9h-2.2z"/>
<path d="M112 138.5h2.2v2h-2.2z"/>
<path d="M111.5 124.7h2.3v1.9h-2.3z"/>
<path d="M111.5 122.1h2.3v2h-2.3z"/>
<path d="M89.2 116h2.3v1.9h-2.3z"/>
<path d="M89.2 118.6h2.3v1.9h-2.3z"/>
<path d="M117.5 136h2.2v1.9h-2.2z"/>
<path d="M117.5 138.5h2.2v2h-2.2z"/>
<path d="M133.6 136h2.2v1.9h-2.2z"/>
<path d="M133.6 138.6h2.2v1.9h-2.2z"/>
<path d="M128.1 136h2.2v2h-2.2z"/>
<path d="M128.1 138.6h2.2v1.9h-2.2z"/>
<path d="M122.5 136h2.3v2h-2.3z"/>
<path d="M122.5 138.6h2.3v1.9h-2.3z"/>
<path d="M139.1 136h2.3v1.9h-2.3z"/>
<path d="M139.1 138.6h2.3v1.9h-2.3z"/>
<path d="M139.1 128.5h2.3v2h-2.3z"/>
<path d="M139.1 131.1h2.3v1.9h-2.3z"/>
<path d="M133.6 128.5h2.2v2h-2.2z"/>
<path d="M133.6 131.1h2.2v2h-2.2z"/>
<path d="M128.1 128.5h2.2v2h-2.2z"/>
<path d="M128.1 131.1h2.2v2h-2.2z"/>
<path d="M122.6 128.6h2.2v1.9h-2.2z"/>
<path d="M122.6 131.1h2.2v2h-2.2z"/>
<path d="M102.3 118.8h1v.7h-1z"/>
<path d="M100.3 118.8h1.1v.7h-1.1z"/>
<path d="M148.6 149.2h1.8v.8h-1.8z"/>
<path d="M148.6 150.6h1.8v.8h-1.8z"/>
<path d="M148.6 152h1.8v.8h-1.8z"/>
<path d="M152.5 152h1.8v.8h-1.8z"/>
<path d="M152.5 149.2h1.8v.8h-1.8z"/>
<path d="M123.9 165h1v3h-1z"/>
<path d="M125.8 165h1v3h-1z"/>
<path d="M127.7 165h1v3h-1z"/>
<path d="M129.6 165h1v3h-1z"/>
<path d="M131.5 165h1v3h-1z"/>
<path d="M133.4 165h1v3h-1z"/>
<path d="M135.3 165h1v3h-1z"/>
<path d="M137.2 165h1v3h-1z"/>
<path d="M137.2 149.9h1v3h-1z"/>
<path d="M135.3 149.9h1v3h-1z"/>
<path d="M133.4 149.9h1v3h-1z"/>
<path d="M131.5 149.9h1v3h-1z"/>
<path d="M129.6 149.9h1v3h-1z"/>
<path d="M127.7 149.9h1v3h-1z"/>
<path d="M125.8 149.9h1v3h-1z"/>
<path d="M123.9 149.9h1v3h-1z"/>
<path d="M139.1 165h1v3h-1z"/>
<path d="M141.1 165h.9v3h-.9z"/>
<path d="M139.1 149.9h1v3h-1z"/>
<path d="M141.1 149.9h.9v3h-.9z"/>
<path d="M109.9 143.7h2v2.3h-2z"/>
<path d="M112.5 143.7h1.9v2.3h-1.9z"/>
<path d="M173.8 153.7h5.9v5.9h-5.9z"/>
<path d="M186.7 154.3h4.8v4.7h-4.8z"/>
<path d="M162.1 154.3h4.8v4.7h-4.8z"/>
<path d="M144.7 149.1h2.2v1.9h-2.2z"/>
<path d="M144.7 151.6h2.2v2h-2.2z"/>
<path d="M156 148.6h2.2v2h-2.2z"/>
<path d="M156 151.2h2.2v1.9h-2.2z"/>
<path d="M114.6 109.2h2.2v1.9h-2.2z"/>
<path d="M114.6 111.7h2.2v1.9h-2.2z"/>
<path d="M111.2 128.6h.3v1.8h-.3z"/>
<path d="M91.6 130h1.2v.3h-1.2z"/>
<path d="M178.5 138h1.8v.3h-1.8z"/>
<path d="M173 138h1.8v.3h-1.8z"/>
<path d="M167.4 138h1.8v.3h-1.8z"/>
<path d="M161.9 138h1.8v.3h-1.8z"/>
<path d="M156.3 138h1.8v.3h-1.8z"/>
<path d="M150.8 138h1.8v.3h-1.8z"/>
<path d="M145.3 138h1.8v.3h-1.8z"/>
<path d="M184 138h1.8v.3h-1.8z"/>
<path d="M184.4 130.5h1.1v.3h-1.1z"/>
<path d="M178.8 130.5h1.2v.3h-1.2z"/>
<path d="M173.2 130.5h1.2v.2h-1.2z"/>
<path d="M167.7 130.5h1.2v.3h-1.2z"/>
<path d="M162.2 130.5h1.2v.3h-1.2z"/>
<path d="M156.7 130.5h1.1v.3h-1.1z"/>
<path d="M151.1 130.5h1.2v.3h-1.2z"/>
<path d="M145.6 130.5h1.2v.3h-1.2z"/>
<path d="M117.9 128.1h1.8v.3h-1.8z"/>
<path d="M112.5 138.1h1.2v.3h-1.2z"/>
<path d="M112.1 124.2h1.1v.3h-1.1z"/>
<path d="M89.8 118.1h1.2v.3h-1.2z"/>
<path d="M118 138.1h1.2v.3h-1.2z"/>
<path d="M133.8 138.1h1.8v.3h-1.8z"/>
<path d="M128.3 138.1h1.8v.3h-1.8z"/>
<path d="M122.7 138.1h1.9v.3h-1.9z"/>
<path d="M139.3 138.1h1.8v.3h-1.8z"/>
<path d="M139.6 130.6h1.2v.3h-1.2z"/>
<path d="M134.1 130.6h1.2v.3h-1.2z"/>
<path d="M128.6 130.6h1.2v.3h-1.2z"/>
<path d="M123.1 130.7h1.2v.3h-1.2z"/>
<path d="M112 144.3h.3v1.2h-.3z"/>
<path d="M144.9 151.2h1.8v.3h-1.8z"/>
<path d="M156.5 150.7h1.2v.3h-1.2z"/>
<path d="M114.8 111.3h1.8v.2h-1.8z"/>
<path d="M124 164.5h.8v.2h-.8z"/>
<path d="M125.9 164.5h.8v.2h-.8z"/>
<path d="M127.8 164.5h.8v.2h-.8z"/>
<path d="M129.7 164.5h.8v.2h-.8z"/>
<path d="M131.6 164.5h.8v.2h-.8z"/>
<path d="M133.5 164.5h.8v.2h-.8z"/>
<path d="M135.4 164.5h.8v.2h-.8z"/>
<path d="M137.4 164.5h.7v.2h-.7z"/>
<path d="M124 153.2h.8v.1h-.8z"/>
<path d="M125.9 153.2h.8v.1h-.8z"/>
<path d="M127.8 153.2h.8v.1h-.8z"/>
<path d="M129.7 153.2h.8v.1h-.8z"/>
<path d="M131.6 153.2h.8v.1h-.8z"/>
<path d="M133.5 153.2h.8v.1h-.8z"/>
<path d="M135.4 153.2h.8v.1h-.8z"/>
<path d="M137.4 153.2h.7v.1h-.7z"/>
<path d="M139.3 153.2h.7v.1h-.7z"/>
<path d="M141.2 153.2h.7v.1h-.7z"/>
<path d="M139.3 164.5h.7v.2h-.7z"/>
<path d="M141.2 164.5h.7v.2h-.7z"/>
<path d="M153.6 102.3h1.3v.3h-1.3z"/>
<path d="M153.6 103.3h1.3v.2h-1.3z"/>
<path d="M153.6 104.2h1.3v.3h-1.3z"/>
<path d="M153.6 105.2h1.3v.3h-1.3z"/>
<path d="M153.6 106.2h1.3v.3h-1.3z"/>
<path d="M153.6 107.1h1.3v.3h-1.3z"/>
<path d="M153.6 108.1h1.3v.3h-1.3z"/>
<path d="M153.6 109.1h1.3v.3h-1.3z"/>
<path d="M153.6 110.1h1.3v.3h-1.3z"/>
<path d="M153.6 111h1.3v.3h-1.3z"/>
<path d="M161.7 111h1.3v.3h-1.3z"/>
<path d="M161.7 110.1h1.3v.3h-1.3z"/>
<path d="M161.7 109.1h1.3v.3h-1.3z"/>
<path d="M161.7 108.1h1.3v.3h-1.3z"/>
<path d="M161.7 107.1h1.3v.3h-1.3z"/>
<path d="M161.7 106.2h1.3v.3h-1.3z"/>
<path d="M161.7 105.2h1.3v.3h-1.3z"/>
<path d="M161.7 104.2h1.3v.3h-1.3z"/>
<path d="M161.7 103.3h1.3v.2h-1.3z"/>
<path d="M161.7 102.3h1.3v.3h-1.3z"/>
<path d="M124.5 102.1h1.4v.3h-1.4z"/>
<path d="M124.5 103h1.4v.3h-1.4z"/>
<path d="M124.5 104h1.4v.3h-1.4z"/>
<path d="M124.5 105h1.4v.3h-1.4z"/>
<path d="M124.5 106h1.4v.3h-1.4z"/>
<path d="M124.5 107h1.4v.3h-1.4z"/>
<path d="M124.5 107.9h1.4v.3h-1.4z"/>
<path d="M124.5 108.9h1.4v.3h-1.4z"/>
<path d="M124.5 109.9h1.4v.3h-1.4z"/>
<path d="M124.5 110.8h1.4v.3h-1.4z"/>
<path d="M132.6 110.8h1.3v.3h-1.3z"/>
<path d="M132.6 109.9h1.3v.3h-1.3z"/>
<path d="M132.6 108.9h1.3v.3h-1.3z"/>
<path d="M132.6 107.9h1.3v.3h-1.3z"/>
<path d="M132.6 107h1.3v.3h-1.3z"/>
<path d="M132.6 106h1.3v.3h-1.3z"/>
<path d="M132.6 105h1.3v.3h-1.3z"/>
<path d="M132.6 104h1.3v.3h-1.3z"/>
<path d="M132.6 103h1.3v.3h-1.3z"/>
<path d="M132.6 102.1h1.3v.3h-1.3z"/>
<path d="M112 128.5h1v2.1h-1z"/>
<path d="M109.8 128.5h1v2.1h-1z"/>
<path d="M91.1 130.6h2.2v1.2h-2.2z"/>
<path d="M91.1 128.5h2.2v1.1h-2.2z"/>
<path d="M178.3 138.8h2.1v.9h-2.1z"/>
<path d="M178.3 136.6h2.1v.9h-2.1z"/>
<path d="M172.8 138.8h2.1v.9h-2.1z"/>
<path d="M172.8 136.6h2.1v.9h-2.1z"/>
<path d="M167.3 138.8h2.1v.9h-2.1z"/>
<path d="M167.3 136.6h2.1v.9h-2.1z"/>
<path d="M161.7 138.8h2.1v.9h-2.1z"/>
<path d="M161.7 136.5h2.1v1h-2.1z"/>
<path d="M156.2 138.8h2.1v.9h-2.1z"/>
<path d="M156.2 136.5h2.1v1h-2.1z"/>
<path d="M150.7 138.8h2.1v.9h-2.1z"/>
<path d="M150.7 136.5h2.1v1h-2.1z"/>
<path d="M145.1 138.8h2.1v.9h-2.1z"/>
<path d="M145.1 136.6h2.1v.9h-2.1z"/>
<path d="M183.9 138.7h2.1v1h-2.1z"/>
<path d="M183.9 136.5h2.1v1h-2.1z"/>
<path d="M183.9 129h2.1v1.1h-2.1z"/>
<path d="M183.9 131.1h2.1v1.2h-2.1z"/>
<path d="M178.4 129h2.1v1.1h-2.1z"/>
<path d="M178.4 131.1h2.1v1.2h-2.1z"/>
<path d="M172.8 128.9h2.1v1.2h-2.1z"/>
<path d="M172.8 131.1h2.1v1.2h-2.1z"/>
<path d="M167.2 129h2.2v1.1h-2.2z"/>
<path d="M167.2 131.1h2.2v1.2h-2.2z"/>
<path d="M161.7 129h2.2v1.1h-2.2z"/>
<path d="M161.7 131.1h2.2v1.2h-2.2z"/>
<path d="M156.2 129h2.1v1.1h-2.1z"/>
<path d="M156.2 131.1h2.1v1.2h-2.1z"/>
<path d="M150.6 129h2.2v1.1h-2.2z"/>
<path d="M150.6 131.1h2.2v1.2h-2.2z"/>
<path d="M145.1 129h2.2v1.1h-2.2z"/>
<path d="M145.1 131.1h2.2v1.2h-2.2z"/>
<path d="M117.7 126.6h2.1v1h-2.1z"/>
<path d="M117.7 128.9h2.1v.9h-2.1z"/>
<path d="M112 136.6h2.2v1.1h-2.2z"/>
<path d="M112 138.7h2.2v1.2h-2.2z"/>
<path d="M111.6 124.9h2.1v1.1h-2.1z"/>
<path d="M111.6 122.7h2.1v1.1h-2.1z"/>
<path d="M89.3 116.6h2.1v1.2h-2.1z"/>
<path d="M89.3 118.8h2.1v1.1h-2.1z"/>
<path d="M117.5 136.6h2.2v1.1h-2.2z"/>
<path d="M117.5 138.7h2.2v1.2h-2.2z"/>
<path d="M133.6 138.9h2.2v.9h-2.2z"/>
<path d="M133.6 136.7h2.2v.9h-2.2z"/>
<path d="M128.1 138.9h2.2v.9h-2.2z"/>
<path d="M128.1 136.7h2.2v.9h-2.2z"/>
<path d="M122.6 138.9h2.1v.9h-2.1z"/>
<path d="M122.6 136.7h2.1v.9h-2.1z"/>
<path d="M139.2 138.9h2.1v.9h-2.1z"/>
<path d="M139.2 136.7h2.1v.9h-2.1z"/>
<path d="M139.1 129.1h2.2v1.2h-2.2z"/>
<path d="M139.1 131.3h2.2v1.2h-2.2z"/>
<path d="M133.6 129.2h2.2v1.1h-2.2z"/>
<path d="M133.6 131.3h2.2v1.2h-2.2z"/>
<path d="M128.1 129.2h2.2v1.1h-2.2z"/>
<path d="M128.1 131.3h2.2v1.2h-2.2z"/>
<path d="M122.6 129.2h2.2v1.1h-2.2z"/>
<path d="M122.6 131.3h2.2v1.2h-2.2z"/>
<path d="M100.6 118.9h.3v.5h-.3z"/>
<path d="M102.6 118.9h.3v.5h-.3z"/>
<path d="M100.9 118.6h.4v1.2h-.4z"/>
<path d="M149.3 149.2h1v.7h-1z"/>
<path d="M149.3 150.6h1v.8h-1z"/>
<path d="M149.3 152h1v.8h-1z"/>
<path d="M152.6 152h1v.8h-1z"/>
<path d="M152.6 149.2h1v.7h-1z"/>
<path d="M124 164.7h.8v2.2h-.8z"/>
<path d="M125.9 164.7h.8v2.2h-.8z"/>
<path d="M127.8 164.7h.8v2.2h-.8z"/>
<path d="M129.7 164.7h.8v2.2h-.8z"/>
<path d="M131.6 164.7h.8v2.2h-.8z"/>
<path d="M133.5 164.7h.8v2.2h-.8z"/>
<path d="M135.4 164.7h.8v2.2h-.8z"/>
<path d="M137.4 164.7h.7v2.2h-.7z"/>
<path d="M124 150.9h.8v2.2h-.8z"/>
<path d="M125.9 150.9h.8v2.2h-.8z"/>
<path d="M127.8 150.9h.8v2.2h-.8z"/>
<path d="M129.7 150.9h.8v2.2h-.8z"/>
<path d="M131.6 150.9h.8v2.2h-.8z"/>
<path d="M133.5 150.9h.8v2.2h-.8z"/>
<path d="M135.4 150.9h.8v2.2h-.8z"/>
<path d="M137.4 150.9h.7v2.2h-.7z"/>
<path d="M139.3 150.9h.7v2.2h-.7z"/>
<path d="M141.2 150.9h.7v2.2h-.7z"/>
<path d="M139.3 164.7h.7v2.2h-.7z"/>
<path d="M141.2 164.7h.7v2.2h-.7z"/>
<path d="M110.5 143.8h1.2v2.1h-1.2z"/>
<path d="M112.7 143.8h1.2v2.1h-1.2z"/>
<path d="M144.8 151.9h2.1v1h-2.1z"/>
<path d="M144.8 149.7h2.1v1h-2.1z"/>
<path d="M156 149.2h2.2v1.2h-2.2z"/>
<path d="M156 151.4h2.2v1.1h-2.2z"/>
<path d="M114.7 112h2.1v1h-2.1z"/>
<path d="M114.7 109.8h2.1v1h-2.1z"/>
</g>
<g fill="none" stroke="#808080" stroke-width=".23">
<path d="M140.9 98.6h1.1M114.8 110.8v1.2M116.7 110.8v1.2M126 101.8h6.5v9.7h-6.5zM155 102h6.6v9.7h-6.6zM110.8 128.6h1.2M110.8 130.5h1.2M117.8 127.6v1.2M119.7 127.6v1.2M122.7 137.6v1.3M124.6 137.6v1.3M128.2 137.6v1.3"/>
<path d="M130.2 137.6v1.3M133.8 137.6v1.3M135.7 137.6v1.3M139.3 137.6v1.3M141.2 137.6v1.3M145.2 137.5v1.3M147.1 137.5v1.3M150.8 137.5v1.3M152.7 137.5v1.3M156.3 137.5v1.3M158.2 137.5v1.3M161.8 137.5v1.3"/>
<path d="M163.7 137.5v1.3M167.4 137.5v1.3M169.3 137.5v1.3M172.9 137.5v1.3M174.8 137.5v1.3M178.4 137.5v1.3M180.3 137.5v1.3M184 137.5v1.2M185.9 137.5v1.2M123.2 157a1.91 1.91 0 0 1 1.9 1.9 1.91 1.91 0 0 1-1.9 1.9M123.3 153.6l.5-.3 18.5 .1 .4 .5v10.2l-.5 .4-18.8-.1-.2-.4zM144.9 150.7v1.2"/>
<path d="M146.8 150.7v1.2M150.4 148.9h2.2v4.2h-2.2z"/>
<circle cx="143.4" cy="98.6" r="1.91"/>
</g>
<path d="M199.4 93.1h6.1v49.7h-6.1zM200.1 93.9h4.6v48.1h-4.6z" fill="none" stroke="#808080" stroke-width=".38"/>
<g fill="none" stroke="#808080" stroke-width=".21">
<path d="M93 37.8h3.1M94.6 36.3v3M96.1 36.3l-3.1 3M104 39.8l-3 3.1M104 36l-3 3.1M107.8 36l-3 3.1M107.8 39.8l-3 3.1M111.7 36l-3.1 3.1M111.7 39.8l-3.1 3.1M115.5 36l-3.1 3.1M115.5 39.8l-3.1 3.1M119.3 36l-3.1 3.1"/>
<path d="M119.3 39.8l-3.1 3.1M123.1 36l-3.1 3.1M126.9 36l-6.9 6.9M126.9 39.8l-3.1 3.1M130.7 36l-3 3.1M130.7 39.8l-3 3.1M134.5 36l-3 3.1M134.5 39.8l-3 3.1M138.3 36l-3 3.1M138.3 39.8l-3 3.1M142.1 36l-3 3.1M142.1 39.8l-3 3.1"/>
<path d="M145.9 36l-3 3.1M145.9 39.8l-3 3.1M149.8 36l-3.1 3.1M149.8 39.8l-3.1 3.1M153.6 39.8l-3.1 3.1M153.6 36l-3.1 3.1M157.4 36l-3.1 3.1M157.4 39.8l-3.1 3.1M161.2 36l-3.1 3.1M161.2 39.8l-3.1 3.1M165 36l-3.1 3.1M165 39.8l-3.1 3.1"/>
<path d="M168.1 39.4h3.1M168.8 36l-3.1 3.1M168.8 39.8l-3.1 3.1M169.7 37.9v3M172.6 36l-3.1 3.1M172.6 39.8l-3.1 3.1M176.4 36l-3 3.1M176.4 39.8l-3 3.1M180.2 36l-3 3.1M180.2 39.8l-3 3.1M184 36l-3 3.1M184 39.8l-3 3.1"/>
<path d="M187.8 36l-3 3.1M187.8 39.8l-3 3.1M191.6 36l-3 3.1M191.6 39.8l-3 3.1M195.5 36l-3.1 3.1M195.5 39.8l-3.1 3.1M199.3 36l-3.1 3.1M199.3 39.8l-3.1 3.1M203.5 37.8h3.1M205 36.3v3M206.6 36.3l-3.1 3M104 47.4l-3 3.1"/>
<path d="M104 43.6l-3 3.1M107.8 43.6l-3 3.1M107.8 47.4l-3 3.1M111.7 43.6l-3.1 3.1M111.7 47.4l-3.1 3.1M113.9 52.2l-3.1 3.1M115.5 43.6l-3.1 3.1M115.5 47.4l-3.1 3.1M119.3 47.4l-3.1 3.1M119.3 43.6l-3.1 3.1M123.1 43.6l-3.1 3.1M123.1 47.4l-3.1 3.1"/>
<path d="M126.9 43.6l-3.1 3.1M126.9 47.4l-3.1 3.1M129.7 59.2v3.1M130.7 43.6l-3 3.1M130.7 47.4l-3 3.1M134.2 52l-3 3.1M134.5 43.6l-3 3.1M134.5 47.4l-3 3.1M138.3 43.6l-3 3.1M138.3 47.4l-3 3.1M138.7 51.4l-3 3M140.9 55.1h3"/>
<path d="M142.1 47.4l-3 3.1M142.1 43.6l-3 3.1M142.4 53.6v3M142.9 52.2l3 3.1M145.9 43.6l-3 3.1M145.9 47.4l-3 3.1M145.9 52.2l-3 3.1M149.8 43.6l-3.1 3.1M149.8 47.4l-3.1 3.1M150.2 58.4h3M151.7 56.9v3M153.6 43.6l-3.1 3.1"/>
<path d="M153.6 47.4l-3.1 3.1M156.1 41.6l3.1 3.1M157.4 43.6l-3.1 3.1M157.4 47.4l-3.1 3.1M157.9 58.9h3M159.2 41.6l-3.1 3.1M159.4 57.3v3.1M161.2 43.6l-3.1 3.1M161.2 47.4l-3.1 3.1M161.4 59.8l-3 3.1M165 43.6l-3.1 3.1M165 47.4l-3.1 3.1"/>
<path d="M168.8 43.6l-3 3.1M168.8 47.4l-3 3.1M170.9 59.5v3.1M172.6 43.6l-3 3.1M172.6 47.4l-3 3.1M176.4 43.6l-3 3.1M176.4 47.4l-3 3.1M177 53.4h3M178.5 56.2h3M178.5 51.9v3M180 54.7v3M180.2 43.6l-3 3.1"/>
<path d="M180.2 47.4l-3 3.1M184 47.4l-3 3.1M184 43.6l-3 3.1M187.8 43.6l-3 3.1M187.8 47.4l-3 3.1M191.6 43.6l-3 3.1M191.6 47.4l-3 3.1M195.5 43.6l-3.1 3.1M195.5 47.4l-3.1 3.1M197.4 42.2l-3.1 3M198.4 52.5h8.2v39h-8.2zM199.3 43.6l-3.1 3.1"/>
<path d="M199.3 47.4l-3.1 3.1M200.6 55.5l1.5 1.5-1.5 1.5zM202.1 57h1.5M207.1 52.4h8.3v75h-8.3zM210.1 55.4l1.5 1.5-1.5 1.6zM211.6 56.9h1.5M110.8 76.2h3.1M112.3 74.7v3M114.5 69h3M116 67.5v3.1M116.2 71.7h3.1M117.8 70.2v3"/>
<path d="M123 70.6h3.1M123.1 74.9h3M123.1 77.7h3.1M123.2 79.6h3.1M124.6 69.1v3M124.6 73.3v3.1M124.6 76.1v3.1M124.7 78.1v3.1M125.3 67.7h3.1M126.8 66.2v3M128.2 60.7h3.1M128.2 68.2h3.1"/>
<path d="M128.3 79.7h3M128.3 77.7h3M129.7 66.7v3M129.8 76.1v7.6M132 62.8h3.1M132 67.6h3.1M132.1 77.6h3M133.6 61.3v3M133.6 66.1v3M133.6 76.1v3M135 79.7h3M136.1 65.6h3"/>
<path d="M136.1 63.2h3M136.5 78.1v3.1M137.6 61.7v5.4M141 63.3h3.1M141.7 73.9h3.1M141.8 65.6h3.1M142.6 61.8v3M143.3 72.4v3M143.4 64.1v3M147.9 76h3.1M148 79.1h3M149.4 74.5v3"/>
<path d="M149.5 79.4v3M149.5 77.6v3.1M150 65.6h3M150.2 62.2h3M151.5 64.1v3M151.7 60.7v3M155.1 76.8h3M156.6 75.2v3.1M156.8 79.4v3M158.2 75.1h3M158.4 65.6h3M159.6 68.8l-3 3"/>
<path d="M159.7 73.6v3M159.7 76.3h3.1M159.9 64.1v3.1M161.2 74.7v3.1M166 74.4h3M167.5 72.8v3.1M169.2 69.8h3.1M169.4 61h3M169.8 76.5h3M169.8 79.4h5.5M170 64.7h3M170.8 68.3v3.1"/>
<path d="M171.3 75v5.9M171.5 63.2v3M172.2 76.5h3.1M172.3 72.2h3M173.4 67.8h3.1M173.6 62.7h3M173.8 75v5.9M173.8 70.7v3M174.9 66.3v3.1M175.1 61.2v3M175.3 70.4h3.1M175.3 79.4h8.8"/>
<path d="M175.3 76.7h3.1M176.9 68.9v3M176.9 75.2v5.7M178 62.5h3M178.1 70.3h3M178.1 76.6h3.1M179.5 61v3.1M179.6 68.8v3M179.6 75.1v5.8M181 76.6h3.1M181.1 70.4h3M182.5 75.1v5.8"/>
<path d="M182.6 68.9v3.1M186.1 79.4h3.1M186.1 70.2h3.1M186.1 76.7h3.1M187.7 68.7v3M187.7 75.2v5.7M190.7 79.4h3M190.7 76.6h3.1M190.8 70.2h3M192.2 77.9v3M192.2 75.1v3.1M192.3 68.7v3"/>
<path d="M192.8 64.7h3.1M194.3 63.2v3M197.7 69.6h3M199.2 68.1v3M200.6 76.5l1.5-1.5 1.5 1.5zM200.6 70.5l1.5-1.5 1.5 1.5zM200.6 64.5l1.5-1.5 1.5 1.5zM202.1 61.5v1.5M202.1 67.5v1.5M202.1 73.5v1.5M202.1 79.5v1.5M208.1 66.2h3"/>
<path d="M209.6 64.6v3.1M210.1 64.5l1.5-1.6 1.5 1.6zM210.1 70.4l1.5-1.5 1.5 1.5zM210.1 76.5l1.5-1.6 1.5 1.6zM211.6 61.4v1.5M211.6 67.4v1.5M211.6 73.4v1.5M211.6 79.4v1.5M101.1 91.5h3M102.6 90v3M107.4 88.2h3M107.4 83.9h3"/>
<path d="M108.9 86.7v3M108.9 82.4v3M110.1 96.7h3.1M110.4 83.8h3M111.5 99.4v3.1M111.7 95.2v3M111.7 95h3M111.9 82.3v3M112.4 82.4h3M113.2 93.5v3M113.6 98.8v3.1M113.9 80.9v3"/>
<path d="M115.1 97.3h3.1M115.7 98.8v3.1M116.6 95.8v3M116.7 95.8h3M118.2 94.2v3.1M119.1 98.8v3.1M120.3 86.3l3 3M120.9 86.7l-3 3M121.8 82.1h3.1M123.3 86.3l-3 3M123.3 80.6v3M128.3 82.2h3"/>
<path d="M129.3 93.9h3.1M129.5 88.3h3M130.9 92.3v3.1M131 86.8v3.1M131.5 88.5h3M131.6 98.8v3.1M132.1 83.9h3M133 87v3M133.6 82.4v3M133.7 88.2h3M135 83.8h3M135.2 86.7v3"/>
<path d="M136.4 88.4h3.1M136.5 82.3v3.1M138 86.8v3.1M141 82.4h3.1M141.1 97l-3.1 3.1M142.5 80.9v3M142.9 99.3l-3.1 3.1M144.9 97l-3.1 3.1M145.1 95.3h3.1M146.7 93.8v3M147.9 80.9h3.1M149.9 83h5"/>
<path d="M151.4 81.5v3M151.6 88.5h3M151.6 93.7h3M152.3 97.9h3M153.1 87v3M153.1 92.2v3.1M153.4 81.5v3M153.8 96.4v3M153.8 88.2h3.1M155.2 80.9h3.1M155.3 86.7v3M159.8 85.5h3"/>
<path d="M161.3 84v3M162.7 94.1l-3.1 3M163.6 88.2h3M163.6 85.3h3M165.1 86.7v3M165.1 83.8v3M166 85.1h3M167.5 83.6v3.1M168.2 87.3h3M169.7 94.3l3 3M169.7 85.8v3M170.8 93.4l-3 3.1"/>
<path d="M172.3 93.3l3 3M172.7 94.3l-3 3M175.3 93.3l-3 3M176 92.5l3.1 3.1M178 92.3l3.1 3.1M179.1 92.5l-3.1 3.1M181.1 92.3l-3.1 3.1M187.8 93.9h3.1M189.3 92.4v3.1M189.5 87.5h3.1M190.5 99.9v3M191 86v3"/>
<path d="M191.3 88.4h3M192.8 86.9v3M193.5 99.6v3M194.8 88.4h3M196.3 86.9v3M200.6 82.5l1.5-1.5 1.5 1.5zM200.6 85.5l1.5 1.5-1.5 1.5zM202.1 87h1.5M203 97.4l-3.1 3M203 93.6l-3.1 3M204.9 99.3l-3.1 3M204.9 97.4l-5 4.9"/>
<path d="M204.9 95.5l-3.1 3M204.9 93.6l-5 4.9M205.5 96.4h3M207 94.9v3M210.1 82.4l1.5-1.5 1.5 1.5zM210.1 88.5l1.5-1.6 1.5 1.6zM210.1 94.4l1.5-1.5 1.5 1.5zM211.6 85.4v1.5M211.6 91.4v1.5M211.6 97.4v1.5M89.4 117.7v1.1M91.4 117.7v1.1"/>
<path d="M99.4 117.1h3.1M100.9 118.6h1.8v1.2h-1.8zM100.9 115.6v3M101.9 114.6h3M102.8 112.6h3.1M102.9 102.5h3.1M103.4 113.1v3M104.4 111.1v3.1M104.5 101v3M106 119.2v3.1M106.8 119.3h3.1M108.3 117.8v3"/>
<path d="M108.5 117.8h3.1M109.9 101h3.1M110.1 116.3v3.1M112.1 100.4h5.1M112.2 105.5h3M112.7 117.4h3M113.7 104v3M114 103.9l3.1 3M114.2 115.9v3M116.3 108.6h3.1M116.5 114.2h3M117.1 103.9l-3.1 3"/>
<path d="M117.2 118.9v3.1M117.6 100.4h3M117.9 107.1v3M118 112.7v3.1M118.9 106.5h3.1M119.2 112.9h3.1M119.5 109.2l-3 3.1M120.4 105v3M120.8 111.4v3M127 117.7h3.1M127.6 115.3h3.1M128.2 108.2h3"/>
<path d="M128.5 116.2v3M129.2 113.7v3.1M129.5 111.4h3.1M129.7 106.6v3.1M130 100.3h3.1M131.1 109.9v3M132 117.7h3M133.5 116.1v3.1M135 118.8v3M135.3 107.9h3M135.7 113.5h3M136.8 106.4v3"/>
<path d="M137.2 112v3M137.4 107.9h3M137.8 116.1h3M138.9 106.4v3M139.3 114.6v3M142.3 110.7h3M143.2 113.7h3M143.8 109.1v3.1M144.7 112.2v3M145.7 109h3.1M146 113.6h3M146.4 105.1h3.1"/>
<path d="M147.3 107.5v3.1M147.5 112.1v3.1M147.9 103.6v3.1M149 103.6h3M150.5 102.1v3M152.5 112.1l3 3.1M155.5 112.1l-3 3.1M162.3 104.9l-3 3.1M163 116.5l-3.1 3M163.4 101.2l3.1 3.1M166.5 101.2l-3.1 3.1M166.5 103l3.1 3"/>
<path d="M166.8 100.8l3 3.1M167.2 112.2l-3 3.1M168 107.5h3M169.5 106v3.1M169.6 103l-3.1 3M169.8 100.8l-3 3.1M170.8 108.6h3M172.3 107.1v3M173.8 109.7h3M175.3 108.2v3M175.9 107.8l3.1 3M178.5 107.4h3"/>
<path d="M179 107.8l-3.1 3M180 105.8v3.1M180.3 112.2l-3 3.1M183.2 101.7h3.1M184.8 100.2v3.1M186.1 104.2h3M187.4 102.5h3M187.6 102.7v3M188.9 101v3.1M189 101.4h3.1M190.4 103.5h3.1M192 101.9v3.1"/>
<path d="M192 101.1h3M193.5 114.4h3M195 112.8v3.1M196.2 100.6v3M198.1 100.5v3.1M199.6 102.1h-4.9M201 105.8l-3 3.1M203 101.2l-3.1 3M204.9 118.3l-5 5M204.9 116.4l-5 5M204.9 114.5l-5 5M204.9 112.6l-5 5"/>
<path d="M204.9 110.7l-5 5M204.9 108.8l-5 4.9M204.9 106.9l-5 4.9M204.9 105l-5 4.9M204.9 103.1l-5 4.9M204.9 101.2l-5 4.9M205.6 118.6v3.1M209 113.8h3M210.1 100.4l1.5-1.5 1.5 1.5zM210.1 106.4l1.5-1.5 1.5 1.5zM210.1 112.4l1.5-1.5 1.5 1.5zM210.1 118.4l1.5-1.5 1.5 1.5z"/>
<path d="M210.5 112.2v3.1M211.6 103.4v1.5M211.6 109.4v1.5M211.6 115.4v1.5M91.2 129.6v1.1M93.2 129.6v1.1M97.2 125.6h3.1M97.3 131.3h3.1M98.8 124.1v3M98.9 129.8v3.1M101.2 139.3h3M101.5 125.5h3"/>
<path d="M102.7 138.1h3M102.7 137.8v3.1M102.8 122.8h3.1M103 124v3.1M104.2 136.6v3M104.4 121.3v3.1M104.5 120.7h3M107 139.7v3.1M109.1 136.5h3M109.9 131.7h3.1M110.6 135v3M111.5 130.2v3.1"/>
<path d="M111.7 123.8v1.1M112.1 137.7v1.1M113.6 123.8v1.1M114.1 137.6v1.2M114.1 133.7h3.1M114.2 139.7h3M114.8 127.8h3.1M115.6 132.2v3M115.7 138.2v3M115.7 120.5h3.1M116.3 126.3v3M117.6 137.7v1.1"/>
<path d="M119.6 137.7v1.1M122.7 130.3v1.1M124.7 130.2v1.2M124.9 134.2h3M124.9 127.7h3M126.4 126.1v3.1M126.4 132.7v3M128.2 130.3v1.1M128.6 122.6l3.1 3.1M128.7 121.9h3M128.7 125.9h3.1M130.2 120.4v3"/>
<path d="M130.2 130.2v1.2M130.3 124.4v3.1M130.4 134.3h3M131.7 122.6l-3.1 3.1M131.9 132.8v3M132.3 126h3.1M132.5 122h3.1M132.5 124.1h3.1M133.5 120.3h3.1M133.7 130.3v1.1M133.8 124.5v3M134 120.5l.1 5.1"/>
<path d="M135.7 130.2v1.2M135.9 134.5h3.1M136 128h3.1M137.4 132.9v3.1M137.5 126.4v3.1M138.1 127.3h3M139.2 130.3v1.1M139.6 125.8v3M141.2 130.2v1.2M141.7 125.9l3.1 3.1M141.7 134.5h3.1M142.9 124h3.1"/>
<path d="M143.2 121.9h3.1M143.3 133v3.1M144.5 122.4v3.1M144.6 124.4v3.1M144.7 120.4v3M144.8 125.9l-3.1 3.1M145.2 130.1v1.1M145.9 122h3.1M147.2 130.1v1.1M147.5 128h3M147.5 134.3h3M147.5 120.5v3"/>
<path d="M147.5 124.4v3.1M149 126.4v3.1M149 132.7v3.1M149.1 125.9l-6.1 .1M149.7 122.7l3.1 3.1M150.7 130.1v1.1M152.7 130v1.2M152.8 122.7l-3.1 3.1M153.2 134.3h3.1M154.7 132.7v3.1M156.3 130.1v1.1M158.2 130v1.2"/>
<path d="M158.7 128h3M158.7 134.5h3M160.2 126.4v3.1M160.2 132.9v3.1M161.8 130.1v1.1M163.3 122.6l-3.1 3M163.8 130v1.2M164.2 134.4h3.1M165.8 132.9v3M167.3 130.1v1.1M169.3 130v1.2M169.7 134.6h3"/>
<path d="M169.7 127.9h3.1M171.2 133v3.1M171.3 126.4v3M172.9 130.1v1.1M174.8 130v1.2M175.1 134.5h3M176.6 132.9v3.1M178.4 130.1v1.1M180.4 130v1.2M180.8 127.7h3M180.8 134.3h3.1M182.3 126.2v3"/>
<path d="M182.4 132.8v3M182.8 139.7v3M184 130.1v1.1M185.2 127.5h3M185.9 130v1.2M186.7 126v3M190.5 121.6h3M192 120v3.1M192.6 136.4h3M194.1 134.8v3.1M204.1 120.2h3M204.9 139.3l-3.1 3"/>
<path d="M204.9 137.4l-5 4.9M204.9 135.5l-5 4.9M204.9 133.6l-5 4.9M204.9 131.7l-5 4.9M204.9 129.8l-5 4.9M204.9 127.8l-5 5M204.9 125.9l-5 5M204.9 124l-5 5M204.9 122.1l-5 5M204.9 120.2l-5 5M206.2 128h3.1M206.7 122.2h3"/>
<path d="M207.8 126.5v3M208.2 120.6v3.1M210.1 121.4l1.5 1.5-1.5 1.5zM210.7 129.4h3.1M211.6 122.9h1.5M212.2 127.8v3.1M98.6 142.7h3M100.1 141.2v3M105.4 141.2h3.1M110.8 158.6h3.1M111.6 143.9h1.2M111.7 145.8h1.1"/>
<path d="M112.4 157v3.1M125.7 145.4h3M127.2 143.9v3M128.6 146.5h3M130.1 144.9v3.1M148 145.7h3.1M149.5 144.1v3.1M156.1 150.3v1.1M158.1 150.3v1.1M162 154.3h4.8v-3.4l4-4.2h11.7l4.3 4.5v3h4.7v4.9h-4.7v7.5h-2l-3.5-3.3h-10.1l-3.2 3.3h-1.2v-7.5h-4.8zM180 151.8h3.1M181.2 141.2h3.1"/>
<path d="M181.5 150.3v3.1M183.9 146.9h3M185.1 149.9h3M185.4 145.3v3.1M186.1 151.8h3.1M186.6 148.3v3.1M187.3 144.5h3.1M187.6 150.3v3.1M188.8 143v3.1M191.7 149.3h3.1M193.3 147.8v3M194.4 158.9v3.1"/>
<path d="M194.6 155.2h3.1M196.1 153.7v3M197.8 158.1h3.1M199.4 156.6v3.1M200.2 146.7h3M200.5 155.3h3.1M201.7 145.2v3M202.1 153.8v3.1M87.4 166.3h3M88.9 164.8v3M90.4 164.8l-3 3.1M107.8 168.7h3"/>
<path d="M109.3 167.2v3.1M110.8 167.1h3.1M112.4 165.6v3M123.3 164h19.4M141.3 169.5h3.1M142.9 168v3M144.6 167.7h3M146.1 166.2v3M175.3 165.1v2l.3 .4h.8l.4-.4v-2M177.3 163.1l-3.1 3.1M178.4 164.8v3.1M179.1 165.5l-.4-.4h-.8l-.3 .4v.4l.3 .4h.8l.4 .4v.4l-.4 .4h-.8l-.3-.4"/>
<path d="M179.7 163.2l-3.1 3M181.4 165.1h-1.5v1.2l.8-.4h.3l.4 .4v.8l-.4 .4h-.7l-.4-.4M188.1 165.3h3M189.6 163.8v3M192.9 160.4h3.1M197.7 164.7h3M198 162.4h3M199.2 163.1v3.1M199.5 160.9v3.1M207.3 166.3h3M208.8 164.8v3M210.4 164.8l-3.1 3.1"/>
<circle cx="94.6" cy="37.8" r="1.48"/>
<circle cx="94.6" cy="37.8" r=".74"/>
<circle cx="102.5" cy="37.5" r="1.48"/>
<circle cx="106.3" cy="37.5" r="1.48"/>
<circle cx="110.1" cy="37.5" r="1.48"/>
<circle cx="113.9" cy="37.5" r="1.48"/>
<circle cx="117.8" cy="37.5" r="1.48"/>
<circle cx="121.6" cy="37.5" r="1.48"/>
<circle cx="123.4" cy="39.5" r="1.48"/>
<circle cx="125.4" cy="37.5" r="1.48"/>
<circle cx="129.2" cy="37.5" r="1.48"/>
<circle cx="133" cy="37.5" r="1.48"/>
<circle cx="136.8" cy="37.5" r="1.48"/>
<circle cx="140.6" cy="37.5" r="1.48"/>
<circle cx="144.4" cy="37.5" r="1.48"/>
<circle cx="148.2" cy="37.5" r="1.48"/>
<circle cx="152" cy="37.5" r="1.48"/>
<circle cx="155.8" cy="37.5" r="1.48"/>
<circle cx="159.6" cy="37.5" r="1.48"/>
<circle cx="163.4" cy="37.5" r="1.48"/>
<circle cx="167.3" cy="37.5" r="1.48"/>
<circle cx="171.1" cy="37.5" r="1.48"/>
<circle cx="174.9" cy="37.5" r="1.48"/>
<circle cx="178.7" cy="37.5" r="1.48"/>
<circle cx="182.5" cy="37.5" r="1.48"/>
<circle cx="186.3" cy="37.5" r="1.48"/>
<circle cx="190.1" cy="37.5" r="1.48"/>
<circle cx="193.9" cy="37.5" r="1.48"/>
<circle cx="197.7" cy="37.5" r="1.48"/>
<circle cx="205" cy="37.8" r="1.48"/>
<circle cx="205" cy="37.8" r=".74"/>
<circle cx="102.5" cy="41.4" r="1.48"/>
<circle cx="102.5" cy="49" r="1.48"/>
<circle cx="102.5" cy="45.1" r="1.48"/>
<circle cx="106.3" cy="41.4" r="1.48"/>
<circle cx="106.3" cy="49" r="1.48"/>
<circle cx="106.3" cy="45.1" r="1.48"/>
<circle cx="110.1" cy="45.1" r="1.48"/>
<circle cx="110.1" cy="49" r="1.48"/>
<circle cx="110.1" cy="41.4" r="1.48"/>
<circle cx="112.4" cy="53.7" r="1.48"/>
<circle cx="113.9" cy="41.4" r="1.48"/>
<circle cx="113.9" cy="49" r="1.48"/>
<circle cx="113.9" cy="45.1" r="1.48"/>
<circle cx="117.8" cy="49" r="1.48"/>
<circle cx="117.8" cy="41.4" r="1.48"/>
<circle cx="117.8" cy="45.1" r="1.48"/>
<circle cx="121.6" cy="49" r="1.48"/>
<circle cx="121.6" cy="41.4" r="1.48"/>
<circle cx="121.6" cy="45.1" r="1.48"/>
<circle cx="125.4" cy="49" r="1.48"/>
<circle cx="125.4" cy="45.1" r="1.48"/>
<circle cx="125.4" cy="41.4" r="1.48"/>
<circle cx="129.2" cy="49" r="1.48"/>
<circle cx="129.2" cy="41.4" r="1.48"/>
<circle cx="129.2" cy="45.1" r="1.48"/>
<circle cx="132.7" cy="53.6" r="1.48"/>
<circle cx="133" cy="41.4" r="1.48"/>
<circle cx="133" cy="49" r="1.48"/>
<circle cx="133" cy="45.1" r="1.48"/>
<circle cx="136.8" cy="49" r="1.48"/>
<circle cx="136.8" cy="45.1" r="1.48"/>
<circle cx="136.8" cy="41.4" r="1.48"/>
<circle cx="137.2" cy="52.9" r="1.48"/>
<circle cx="140.6" cy="49" r="1.48"/>
<circle cx="140.6" cy="41.4" r="1.48"/>
<circle cx="140.6" cy="45.1" r="1.48"/>
<circle cx="144.4" cy="41.4" r="1.48"/>
<circle cx="144.4" cy="49" r="1.48"/>
<circle cx="144.4" cy="45.1" r="1.48"/>
<circle cx="148.2" cy="49" r="1.48"/>
<circle cx="148.2" cy="41.4" r="1.48"/>
<circle cx="148.2" cy="45.1" r="1.48"/>
<circle cx="152" cy="41.4" r="1.48"/>
<circle cx="152" cy="49" r="1.48"/>
<circle cx="152" cy="45.1" r="1.48"/>
<circle cx="155.8" cy="41.4" r="1.48"/>
<circle cx="155.8" cy="49" r="1.48"/>
<circle cx="155.8" cy="45.1" r="1.48"/>
<circle cx="159.6" cy="41.4" r="1.48"/>
<circle cx="159.7" cy="49" r="1.48"/>
<circle cx="159.7" cy="45.1" r="1.48"/>
<circle cx="163.4" cy="41.4" r="1.48"/>
<circle cx="163.5" cy="45.1" r="1.48"/>
<circle cx="163.5" cy="49" r="1.48"/>
<circle cx="167.3" cy="41.4" r="1.48"/>
<circle cx="167.3" cy="49" r="1.48"/>
<circle cx="167.3" cy="45.1" r="1.48"/>
<circle cx="171.1" cy="41.4" r="1.48"/>
<circle cx="171.1" cy="49" r="1.48"/>
<circle cx="171.1" cy="45.1" r="1.48"/>
<circle cx="174.9" cy="41.4" r="1.48"/>
<circle cx="174.9" cy="49" r="1.48"/>
<circle cx="174.9" cy="45.1" r="1.48"/>
<circle cx="178.7" cy="41.4" r="1.48"/>
<circle cx="178.7" cy="45.1" r="1.48"/>
<circle cx="178.7" cy="49" r="1.48"/>
<circle cx="182.5" cy="41.4" r="1.48"/>
<circle cx="182.5" cy="49" r="1.48"/>
<circle cx="182.5" cy="45.1" r="1.48"/>
<circle cx="186.3" cy="49" r="1.48"/>
<circle cx="186.3" cy="45.1" r="1.48"/>
<circle cx="186.3" cy="41.4" r="1.48"/>
<circle cx="190.1" cy="49" r="1.48"/>
<circle cx="190.1" cy="45.1" r="1.48"/>
<circle cx="190.1" cy="41.4" r="1.48"/>
<circle cx="193.9" cy="45.1" r="1.48"/>
<circle cx="193.9" cy="49" r="1.48"/>
<circle cx="193.9" cy="41.4" r="1.48"/>
<circle cx="195.9" cy="43.7" r="1.48"/>
<circle cx="197.7" cy="49" r="1.48"/>
<circle cx="197.7" cy="45.1" r="1.48"/>
<circle cx="197.7" cy="41.4" r="1.48"/>
<circle cx="158.1" cy="70.3" r="1.48"/>
<circle cx="159.9" cy="61.4" r="1.48"/>
<circle cx="119.4" cy="88.2" r="1.48"/>
<circle cx="139.6" cy="98.6" r="1.48"/>
<circle cx="143.4" cy="98.6" r="1.48"/>
<circle cx="161.2" cy="95.6" r="1.48"/>
<circle cx="169.3" cy="94.9" r="1.48"/>
<circle cx="201.5" cy="95.1" r="1.48"/>
<circle cx="201.5" cy="97" r="1.48"/>
<circle cx="201.5" cy="98.9" r="1.48"/>
<circle cx="203.4" cy="97" r="1.48"/>
<circle cx="203.4" cy="95.1" r="1.48"/>
<circle cx="203.4" cy="98.9" r="1.48"/>
<circle cx="118" cy="110.8" r="1.48"/>
<circle cx="141.4" cy="100.8" r="1.48"/>
<circle cx="160.8" cy="106.4" r="1.48"/>
<circle cx="161.4" cy="118" r="1.48"/>
<circle cx="165.7" cy="113.8" r="1.48"/>
<circle cx="178.8" cy="113.8" r="1.48"/>
<circle cx="199.5" cy="107.4" r="1.48"/>
<circle cx="201.5" cy="112.2" r="1.48"/>
<circle cx="201.5" cy="108.4" r="1.48"/>
<circle cx="201.5" cy="110.3" r="1.48"/>
<circle cx="201.5" cy="106.5" r="1.48"/>
<circle cx="201.5" cy="116" r="1.48"/>
<circle cx="201.5" cy="102.7" r="1.48"/>
<circle cx="201.5" cy="119.8" r="1.48"/>
<circle cx="201.5" cy="117.9" r="1.48"/>
<circle cx="201.5" cy="100.8" r="1.48"/>
<circle cx="201.5" cy="114.1" r="1.48"/>
<circle cx="201.5" cy="104.6" r="1.48"/>
<circle cx="203.4" cy="108.4" r="1.48"/>
<circle cx="203.4" cy="100.8" r="1.48"/>
<circle cx="203.4" cy="114.1" r="1.48"/>
<circle cx="203.4" cy="104.6" r="1.48"/>
<circle cx="203.4" cy="110.3" r="1.48"/>
<circle cx="203.4" cy="112.2" r="1.48"/>
<circle cx="203.4" cy="117.9" r="1.48"/>
<circle cx="203.4" cy="116" r="1.48"/>
<circle cx="203.4" cy="106.5" r="1.48"/>
<circle cx="203.4" cy="102.7" r="1.48"/>
<circle cx="203.4" cy="119.8" r="1.48"/>
<circle cx="161.7" cy="124.1" r="1.48"/>
<circle cx="201.5" cy="121.8" r="1.48"/>
<circle cx="201.5" cy="123.7" r="1.48"/>
<circle cx="201.5" cy="133.2" r="1.48"/>
<circle cx="201.5" cy="129.4" r="1.48"/>
<circle cx="201.5" cy="137" r="1.48"/>
<circle cx="201.5" cy="125.6" r="1.48"/>
<circle cx="201.5" cy="135.1" r="1.48"/>
<circle cx="201.5" cy="131.3" r="1.48"/>
<circle cx="201.5" cy="127.5" r="1.48"/>
<circle cx="201.5" cy="138.9" r="1.48"/>
<circle cx="203.4" cy="123.7" r="1.48"/>
<circle cx="203.4" cy="121.8" r="1.48"/>
<circle cx="203.4" cy="129.4" r="1.48"/>
<circle cx="203.4" cy="138.9" r="1.48"/>
<circle cx="203.4" cy="133.2" r="1.48"/>
<circle cx="203.4" cy="137" r="1.48"/>
<circle cx="203.4" cy="127.5" r="1.48"/>
<circle cx="203.4" cy="125.6" r="1.48"/>
<circle cx="203.4" cy="135.1" r="1.48"/>
<circle cx="203.4" cy="131.3" r="1.48"/>
<circle cx="164.2" cy="156.9" r="1.38"/>
<circle cx="189.1" cy="156.7" r="1.38"/>
<circle cx="201.5" cy="140.8" r="1.48"/>
<circle cx="203.4" cy="140.8" r="1.48"/>
<circle cx="88.9" cy="166.4" r="1.48"/>
<circle cx="88.9" cy="166.3" r="1.48"/>
<circle cx="88.9" cy="166.3" r=".74"/>
<circle cx="175.7" cy="164.7" r="1.48"/>
<circle cx="178.1" cy="164.7" r="1.48"/>
<circle cx="208.8" cy="166.3" r="1.48"/>
<circle cx="208.8" cy="166.3" r=".74"/>
<circle cx="208.9" cy="166.4" r="1.48"/>
</g>
<g fill="none" stroke="#000" stroke-width=".21">
<path d="M143.4 38.4l2 2.1M145.4 38.4l-2 2.1M143.4 46l2 2.1M145.4 46l-2 2.1M216.5 42.7l.3 .3M201.3 72h1.7M202.1 71.2v1.7M81 93.7v-60.4h135.7v137.7h-135.7v-19.7h18.2M81 93.7h18.2M99.1 93.7a3.8 3.8 0 0 1 3.8 3.8 3.8 3.8 0 0 1-3.8 3.7M140.3 98.6h2.3M141.5 97.4v2.3"/>
<path d="M210.8 89.9h1.7M211.6 89.1v1.7M89.5 118.2h1.7M90.4 117.4v1.7M99.2 101.2h-18.2v42.7h18.2M101 119.2h1.5M101.8 118.5v1.4M114.9 111.4h1.6M115.7 110.6v1.6M127.7 107.6h3M129.2 106.1v3M156.8 107.8h3"/>
<path d="M158.3 106.3v3M200.9 117h3M202.4 115.5v3M91.4 130.1h1.6M92.2 129.3v1.6M110.6 129.5h1.5M111.4 128.8v1.5M112 124.4h1.3M112.4 138.2h1.3M112.6 123.7v1.3M113.1 137.6v1.3M117.9 138.2h1.3"/>
<path d="M118.2 128.2h1.2M118.6 137.6v1.3M118.8 127.6v1.2M123 130.8h1.3M123.1 138.3h1.2M123.7 137.7v1.2M123.7 130.2v1.3M128.6 130.8h1.2M128.6 138.3h1.2M129.2 130.2v1.2M129.2 137.7v1.1M134.1 130.8h1.2"/>
<path d="M134.1 138.3h1.2M134.7 130.2v1.2M134.7 137.7v1.1M139.6 138.2h1.3M139.6 130.8h1.2M140.2 130.2v1.2M140.2 137.6v1.3M145.5 130.6h1.4M145.6 138.2h1.2M146.2 129.9v1.4M146.2 137.6v1.1M151.1 130.6h1.2"/>
<path d="M151.1 138.2h1.2M151.7 130v1.2M151.7 137.5v1.3M156.6 130.6h1.3M156.7 138.2h1.1M157.2 137.6v1.1M157.2 130v1.3M162.2 138.2h1.2M162.2 130.6h1.2M162.8 130v1.2M162.8 137.5v1.3M167.7 138.2h1.2"/>
<path d="M167.7 130.6h1.2M168.3 130v1.2M168.3 137.6v1.2M173.2 130.6h1.3M173.3 138.2h1.1M173.8 130v1.2M173.9 137.6v1.1M178.8 138.2h1.2M178.8 130.6h1.2M179.4 137.6v1.2M179.4 130v1.2M184.3 130.6h1.3"/>
<path d="M184.3 138.1h1.2M184.9 137.5v1.2M185 130v1.2M99.1 143.9a3.7 3.7 0 0 1 3.7 3.8 3.7 3.7 0 0 1-3.7 3.6M111.3 144.9h1.8M112.2 144v1.7M131.4 158.9h3.1M133 157.4v3.1M145 151.3h1.6M145.8 150.5v1.6M150.3 151h2.3M151.5 149.9v2.2"/>
<path d="M156.2 150.9h1.7M157.1 150v1.7M175.2 156.7h3.1M176.8 155.1v3.1"/>
<circle cx="94.6" cy="37.8" r="2.48"/>
<circle cx="205" cy="37.8" r="2.48"/>
<circle cx="88.9" cy="166.4" r="2.48"/>
<circle cx="208.9" cy="166.4" r="2.48"/>
</g>
<path d="M124.8 109v.1M153.8 110.2h.1M153.9 109.2v.1M153.9 108.2v.1M162.7 107.3h.1" fill="none" stroke="#808000" stroke-width=".21"/>
<use href="#words"/>
</svg>
